VERSION 5.8 ;
BUSBITCHARS "[]" ;
DIVIDERCHAR "/" ;
UNITS
    DATABASE MICRONS 1000 ;
END UNITS

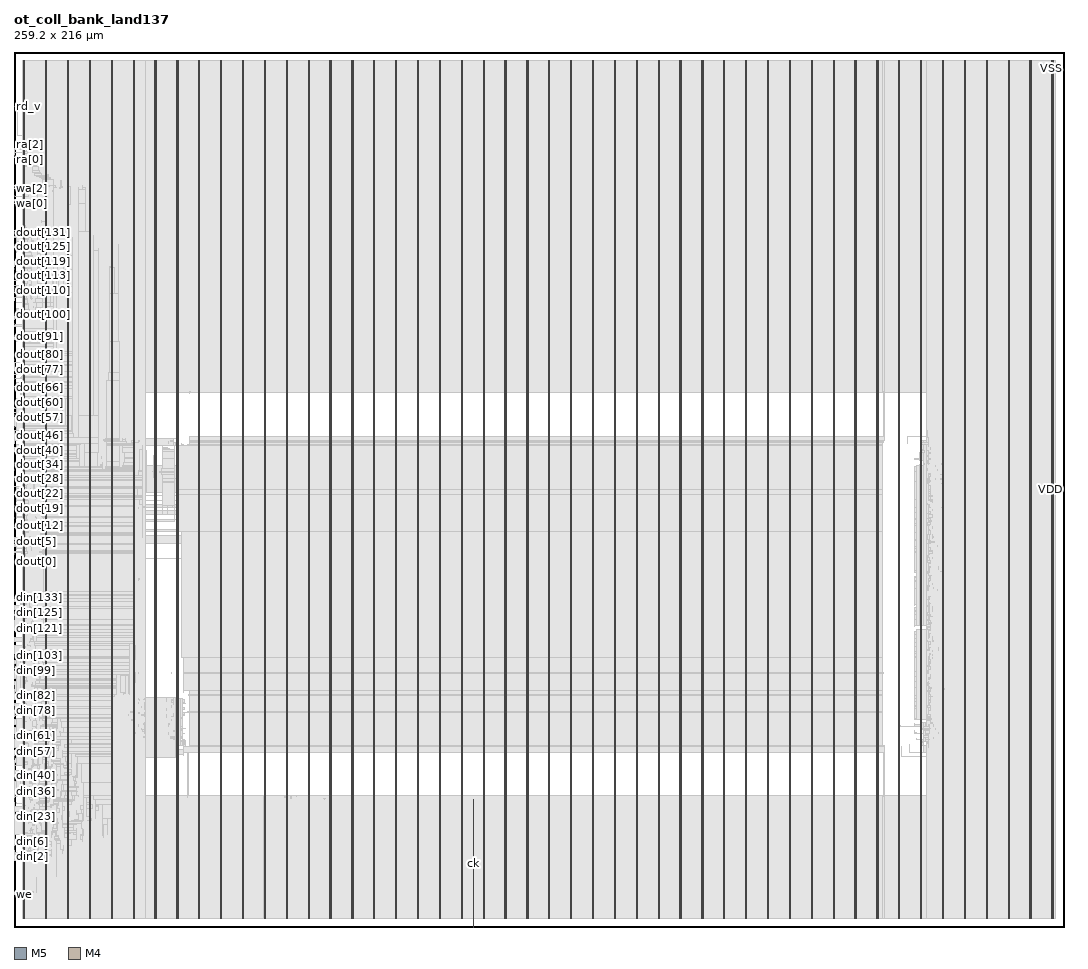
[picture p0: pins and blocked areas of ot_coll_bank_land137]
MACRO ot_coll_bank_land137
  FOREIGN ot_coll_bank_land137 0 0 ;
  CLASS BLOCK ;
  SIZE 259.2 BY 216 ;
  PIN ck
    DIRECTION INPUT ;
    USE SIGNAL ;
    PORT
      LAYER M5 ;
        RECT  113.376 0 113.4 0.084 ;
    END
    PORT
      LAYER M5 ;
        RECT  113.376 0.016 113.4 31.475 ;
    END
  END ck
  PIN din[0]
    DIRECTION INPUT ;
    USE SIGNAL ;
    PORT
      LAYER M4 ;
        RECT  0 16.416 0.084 16.44 ;
    END
  END din[0]
  PIN din[100]
    DIRECTION INPUT ;
    USE SIGNAL ;
    PORT
      LAYER M4 ;
        RECT  0 63.744 0.084 63.768 ;
    END
  END din[100]
  PIN din[101]
    DIRECTION INPUT ;
    USE SIGNAL ;
    PORT
      LAYER M4 ;
        RECT  0 64.176 0.084 64.2 ;
    END
  END din[101]
  PIN din[102]
    DIRECTION INPUT ;
    USE SIGNAL ;
    PORT
      LAYER M4 ;
        RECT  0 64.656 0.084 64.68 ;
    END
  END din[102]
  PIN din[103]
    DIRECTION INPUT ;
    USE SIGNAL ;
    PORT
      LAYER M4 ;
        RECT  0 65.136 0.084 65.16 ;
    END
  END din[103]
  PIN din[104]
    DIRECTION INPUT ;
    USE SIGNAL ;
    PORT
      LAYER M4 ;
        RECT  0 65.616 0.084 65.64 ;
    END
  END din[104]
  PIN din[105]
    DIRECTION INPUT ;
    USE SIGNAL ;
    PORT
      LAYER M4 ;
        RECT  0 66.096 0.084 66.12 ;
    END
  END din[105]
  PIN din[106]
    DIRECTION INPUT ;
    USE SIGNAL ;
    PORT
      LAYER M4 ;
        RECT  0 66.576 0.084 66.6 ;
    END
  END din[106]
  PIN din[107]
    DIRECTION INPUT ;
    USE SIGNAL ;
    PORT
      LAYER M4 ;
        RECT  0 67.056 0.084 67.08 ;
    END
  END din[107]
  PIN din[108]
    DIRECTION INPUT ;
    USE SIGNAL ;
    PORT
      LAYER M4 ;
        RECT  0 67.488 0.084 67.512 ;
    END
  END din[108]
  PIN din[109]
    DIRECTION INPUT ;
    USE SIGNAL ;
    PORT
      LAYER M4 ;
        RECT  0 67.968 0.084 67.992 ;
    END
  END din[109]
  PIN din[10]
    DIRECTION INPUT ;
    USE SIGNAL ;
    PORT
      LAYER M4 ;
        RECT  0 21.168 0.084 21.192 ;
    END
  END din[10]
  PIN din[110]
    DIRECTION INPUT ;
    USE SIGNAL ;
    PORT
      LAYER M4 ;
        RECT  0 68.448 0.084 68.472 ;
    END
  END din[110]
  PIN din[111]
    DIRECTION INPUT ;
    USE SIGNAL ;
    PORT
      LAYER M4 ;
        RECT  0 68.928 0.084 68.952 ;
    END
  END din[111]
  PIN din[112]
    DIRECTION INPUT ;
    USE SIGNAL ;
    PORT
      LAYER M4 ;
        RECT  0 69.408 0.084 69.432 ;
    END
  END din[112]
  PIN din[113]
    DIRECTION INPUT ;
    USE SIGNAL ;
    PORT
      LAYER M4 ;
        RECT  0 69.888 0.084 69.912 ;
    END
  END din[113]
  PIN din[114]
    DIRECTION INPUT ;
    USE SIGNAL ;
    PORT
      LAYER M4 ;
        RECT  0 70.368 0.084 70.392 ;
    END
  END din[114]
  PIN din[115]
    DIRECTION INPUT ;
    USE SIGNAL ;
    PORT
      LAYER M4 ;
        RECT  0 70.8 0.084 70.824 ;
    END
  END din[115]
  PIN din[116]
    DIRECTION INPUT ;
    USE SIGNAL ;
    PORT
      LAYER M4 ;
        RECT  0 71.28 0.084 71.304 ;
    END
  END din[116]
  PIN din[117]
    DIRECTION INPUT ;
    USE SIGNAL ;
    PORT
      LAYER M4 ;
        RECT  0 71.76 0.084 71.784 ;
    END
  END din[117]
  PIN din[118]
    DIRECTION INPUT ;
    USE SIGNAL ;
    PORT
      LAYER M4 ;
        RECT  0 72.24 0.084 72.264 ;
    END
  END din[118]
  PIN din[119]
    DIRECTION INPUT ;
    USE SIGNAL ;
    PORT
      LAYER M4 ;
        RECT  0 72.72 0.084 72.744 ;
    END
  END din[119]
  PIN din[11]
    DIRECTION INPUT ;
    USE SIGNAL ;
    PORT
      LAYER M4 ;
        RECT  0 21.648 0.084 21.672 ;
    END
  END din[11]
  PIN din[120]
    DIRECTION INPUT ;
    USE SIGNAL ;
    PORT
      LAYER M4 ;
        RECT  0 73.2 0.084 73.224 ;
    END
  END din[120]
  PIN din[121]
    DIRECTION INPUT ;
    USE SIGNAL ;
    PORT
      LAYER M4 ;
        RECT  0 73.68 0.084 73.704 ;
    END
  END din[121]
  PIN din[122]
    DIRECTION INPUT ;
    USE SIGNAL ;
    PORT
      LAYER M4 ;
        RECT  0 74.112 0.084 74.136 ;
    END
  END din[122]
  PIN din[123]
    DIRECTION INPUT ;
    USE SIGNAL ;
    PORT
      LAYER M4 ;
        RECT  0 74.592 0.084 74.616 ;
    END
  END din[123]
  PIN din[124]
    DIRECTION INPUT ;
    USE SIGNAL ;
    PORT
      LAYER M4 ;
        RECT  0 75.072 0.084 75.096 ;
    END
  END din[124]
  PIN din[125]
    DIRECTION INPUT ;
    USE SIGNAL ;
    PORT
      LAYER M4 ;
        RECT  0 75.552 0.084 75.576 ;
    END
  END din[125]
  PIN din[126]
    DIRECTION INPUT ;
    USE SIGNAL ;
    PORT
      LAYER M4 ;
        RECT  0 76.032 0.084 76.056 ;
    END
  END din[126]
  PIN din[127]
    DIRECTION INPUT ;
    USE SIGNAL ;
    PORT
      LAYER M4 ;
        RECT  0 76.512 0.084 76.536 ;
    END
  END din[127]
  PIN din[128]
    DIRECTION INPUT ;
    USE SIGNAL ;
    PORT
      LAYER M4 ;
        RECT  0 76.992 0.084 77.016 ;
    END
  END din[128]
  PIN din[129]
    DIRECTION INPUT ;
    USE SIGNAL ;
    PORT
      LAYER M4 ;
        RECT  0 77.424 0.084 77.448 ;
    END
  END din[129]
  PIN din[12]
    DIRECTION INPUT ;
    USE SIGNAL ;
    PORT
      LAYER M4 ;
        RECT  0 22.08 0.084 22.104 ;
    END
  END din[12]
  PIN din[130]
    DIRECTION INPUT ;
    USE SIGNAL ;
    PORT
      LAYER M4 ;
        RECT  0 77.904 0.084 77.928 ;
    END
  END din[130]
  PIN din[131]
    DIRECTION INPUT ;
    USE SIGNAL ;
    PORT
      LAYER M4 ;
        RECT  0 78.384 0.084 78.408 ;
    END
  END din[131]
  PIN din[132]
    DIRECTION INPUT ;
    USE SIGNAL ;
    PORT
      LAYER M4 ;
        RECT  0 78.864 0.084 78.888 ;
    END
  END din[132]
  PIN din[133]
    DIRECTION INPUT ;
    USE SIGNAL ;
    PORT
      LAYER M4 ;
        RECT  0 79.344 0.084 79.368 ;
    END
  END din[133]
  PIN din[134]
    DIRECTION INPUT ;
    USE SIGNAL ;
    PORT
      LAYER M4 ;
        RECT  0 79.824 0.084 79.848 ;
    END
  END din[134]
  PIN din[135]
    DIRECTION INPUT ;
    USE SIGNAL ;
    PORT
      LAYER M4 ;
        RECT  0 80.256 0.084 80.28 ;
    END
  END din[135]
  PIN din[136]
    DIRECTION INPUT ;
    USE SIGNAL ;
    PORT
      LAYER M4 ;
        RECT  0 80.736 0.084 80.76 ;
    END
  END din[136]
  PIN din[13]
    DIRECTION INPUT ;
    USE SIGNAL ;
    PORT
      LAYER M4 ;
        RECT  0 22.56 0.084 22.584 ;
    END
  END din[13]
  PIN din[14]
    DIRECTION INPUT ;
    USE SIGNAL ;
    PORT
      LAYER M4 ;
        RECT  0 23.04 0.084 23.064 ;
    END
  END din[14]
  PIN din[15]
    DIRECTION INPUT ;
    USE SIGNAL ;
    PORT
      LAYER M4 ;
        RECT  0 23.52 0.084 23.544 ;
    END
  END din[15]
  PIN din[16]
    DIRECTION INPUT ;
    USE SIGNAL ;
    PORT
      LAYER M4 ;
        RECT  0 24 0.084 24.024 ;
    END
  END din[16]
  PIN din[17]
    DIRECTION INPUT ;
    USE SIGNAL ;
    PORT
      LAYER M4 ;
        RECT  0 24.48 0.084 24.504 ;
    END
  END din[17]
  PIN din[18]
    DIRECTION INPUT ;
    USE SIGNAL ;
    PORT
      LAYER M4 ;
        RECT  0 24.96 0.084 24.984 ;
    END
  END din[18]
  PIN din[19]
    DIRECTION INPUT ;
    USE SIGNAL ;
    PORT
      LAYER M4 ;
        RECT  0 25.392 0.084 25.416 ;
    END
  END din[19]
  PIN din[1]
    DIRECTION INPUT ;
    USE SIGNAL ;
    PORT
      LAYER M4 ;
        RECT  0 16.896 0.084 16.92 ;
    END
  END din[1]
  PIN din[20]
    DIRECTION INPUT ;
    USE SIGNAL ;
    PORT
      LAYER M4 ;
        RECT  0 25.872 0.084 25.896 ;
    END
  END din[20]
  PIN din[21]
    DIRECTION INPUT ;
    USE SIGNAL ;
    PORT
      LAYER M4 ;
        RECT  0 26.352 0.084 26.376 ;
    END
  END din[21]
  PIN din[22]
    DIRECTION INPUT ;
    USE SIGNAL ;
    PORT
      LAYER M4 ;
        RECT  0 26.832 0.084 26.856 ;
    END
  END din[22]
  PIN din[23]
    DIRECTION INPUT ;
    USE SIGNAL ;
    PORT
      LAYER M4 ;
        RECT  0 27.312 0.084 27.336 ;
    END
  END din[23]
  PIN din[24]
    DIRECTION INPUT ;
    USE SIGNAL ;
    PORT
      LAYER M4 ;
        RECT  0 27.792 0.084 27.816 ;
    END
  END din[24]
  PIN din[25]
    DIRECTION INPUT ;
    USE SIGNAL ;
    PORT
      LAYER M4 ;
        RECT  0 28.272 0.084 28.296 ;
    END
  END din[25]
  PIN din[26]
    DIRECTION INPUT ;
    USE SIGNAL ;
    PORT
      LAYER M4 ;
        RECT  0 28.704 0.084 28.728 ;
    END
  END din[26]
  PIN din[27]
    DIRECTION INPUT ;
    USE SIGNAL ;
    PORT
      LAYER M4 ;
        RECT  0 29.184 0.084 29.208 ;
    END
  END din[27]
  PIN din[28]
    DIRECTION INPUT ;
    USE SIGNAL ;
    PORT
      LAYER M4 ;
        RECT  0 29.664 0.084 29.688 ;
    END
  END din[28]
  PIN din[29]
    DIRECTION INPUT ;
    USE SIGNAL ;
    PORT
      LAYER M4 ;
        RECT  0 30.144 0.084 30.168 ;
    END
  END din[29]
  PIN din[2]
    DIRECTION INPUT ;
    USE SIGNAL ;
    PORT
      LAYER M4 ;
        RECT  0 17.376 0.084 17.4 ;
    END
  END din[2]
  PIN din[30]
    DIRECTION INPUT ;
    USE SIGNAL ;
    PORT
      LAYER M4 ;
        RECT  0 30.624 0.084 30.648 ;
    END
  END din[30]
  PIN din[31]
    DIRECTION INPUT ;
    USE SIGNAL ;
    PORT
      LAYER M4 ;
        RECT  0 31.104 0.084 31.128 ;
    END
  END din[31]
  PIN din[32]
    DIRECTION INPUT ;
    USE SIGNAL ;
    PORT
      LAYER M4 ;
        RECT  0 31.584 0.084 31.608 ;
    END
  END din[32]
  PIN din[33]
    DIRECTION INPUT ;
    USE SIGNAL ;
    PORT
      LAYER M4 ;
        RECT  0 32.016 0.084 32.04 ;
    END
  END din[33]
  PIN din[34]
    DIRECTION INPUT ;
    USE SIGNAL ;
    PORT
      LAYER M4 ;
        RECT  0 32.496 0.084 32.52 ;
    END
  END din[34]
  PIN din[35]
    DIRECTION INPUT ;
    USE SIGNAL ;
    PORT
      LAYER M4 ;
        RECT  0 32.976 0.084 33 ;
    END
  END din[35]
  PIN din[36]
    DIRECTION INPUT ;
    USE SIGNAL ;
    PORT
      LAYER M4 ;
        RECT  0 33.456 0.084 33.48 ;
    END
  END din[36]
  PIN din[37]
    DIRECTION INPUT ;
    USE SIGNAL ;
    PORT
      LAYER M4 ;
        RECT  0 33.936 0.084 33.96 ;
    END
  END din[37]
  PIN din[38]
    DIRECTION INPUT ;
    USE SIGNAL ;
    PORT
      LAYER M4 ;
        RECT  0 34.416 0.084 34.44 ;
    END
  END din[38]
  PIN din[39]
    DIRECTION INPUT ;
    USE SIGNAL ;
    PORT
      LAYER M4 ;
        RECT  0 34.848 0.084 34.872 ;
    END
  END din[39]
  PIN din[3]
    DIRECTION INPUT ;
    USE SIGNAL ;
    PORT
      LAYER M4 ;
        RECT  0 17.856 0.084 17.88 ;
    END
  END din[3]
  PIN din[40]
    DIRECTION INPUT ;
    USE SIGNAL ;
    PORT
      LAYER M4 ;
        RECT  0 35.328 0.084 35.352 ;
    END
  END din[40]
  PIN din[41]
    DIRECTION INPUT ;
    USE SIGNAL ;
    PORT
      LAYER M4 ;
        RECT  0 35.808 0.084 35.832 ;
    END
  END din[41]
  PIN din[42]
    DIRECTION INPUT ;
    USE SIGNAL ;
    PORT
      LAYER M4 ;
        RECT  0 36.288 0.084 36.312 ;
    END
  END din[42]
  PIN din[43]
    DIRECTION INPUT ;
    USE SIGNAL ;
    PORT
      LAYER M4 ;
        RECT  0 36.768 0.084 36.792 ;
    END
  END din[43]
  PIN din[44]
    DIRECTION INPUT ;
    USE SIGNAL ;
    PORT
      LAYER M4 ;
        RECT  0 37.248 0.084 37.272 ;
    END
  END din[44]
  PIN din[45]
    DIRECTION INPUT ;
    USE SIGNAL ;
    PORT
      LAYER M4 ;
        RECT  0 37.728 0.084 37.752 ;
    END
  END din[45]
  PIN din[46]
    DIRECTION INPUT ;
    USE SIGNAL ;
    PORT
      LAYER M4 ;
        RECT  0 38.16 0.084 38.184 ;
    END
  END din[46]
  PIN din[47]
    DIRECTION INPUT ;
    USE SIGNAL ;
    PORT
      LAYER M4 ;
        RECT  0 38.64 0.084 38.664 ;
    END
  END din[47]
  PIN din[48]
    DIRECTION INPUT ;
    USE SIGNAL ;
    PORT
      LAYER M4 ;
        RECT  0 39.12 0.084 39.144 ;
    END
  END din[48]
  PIN din[49]
    DIRECTION INPUT ;
    USE SIGNAL ;
    PORT
      LAYER M4 ;
        RECT  0 39.6 0.084 39.624 ;
    END
  END din[49]
  PIN din[4]
    DIRECTION INPUT ;
    USE SIGNAL ;
    PORT
      LAYER M4 ;
        RECT  0 18.336 0.084 18.36 ;
    END
  END din[4]
  PIN din[50]
    DIRECTION INPUT ;
    USE SIGNAL ;
    PORT
      LAYER M4 ;
        RECT  0 40.08 0.084 40.104 ;
    END
  END din[50]
  PIN din[51]
    DIRECTION INPUT ;
    USE SIGNAL ;
    PORT
      LAYER M4 ;
        RECT  0 40.56 0.084 40.584 ;
    END
  END din[51]
  PIN din[52]
    DIRECTION INPUT ;
    USE SIGNAL ;
    PORT
      LAYER M4 ;
        RECT  0 41.04 0.084 41.064 ;
    END
  END din[52]
  PIN din[53]
    DIRECTION INPUT ;
    USE SIGNAL ;
    PORT
      LAYER M4 ;
        RECT  0 41.472 0.084 41.496 ;
    END
  END din[53]
  PIN din[54]
    DIRECTION INPUT ;
    USE SIGNAL ;
    PORT
      LAYER M4 ;
        RECT  0 41.952 0.084 41.976 ;
    END
  END din[54]
  PIN din[55]
    DIRECTION INPUT ;
    USE SIGNAL ;
    PORT
      LAYER M4 ;
        RECT  0 42.432 0.084 42.456 ;
    END
  END din[55]
  PIN din[56]
    DIRECTION INPUT ;
    USE SIGNAL ;
    PORT
      LAYER M4 ;
        RECT  0 42.912 0.084 42.936 ;
    END
  END din[56]
  PIN din[57]
    DIRECTION INPUT ;
    USE SIGNAL ;
    PORT
      LAYER M4 ;
        RECT  0 43.392 0.084 43.416 ;
    END
  END din[57]
  PIN din[58]
    DIRECTION INPUT ;
    USE SIGNAL ;
    PORT
      LAYER M4 ;
        RECT  0 43.872 0.084 43.896 ;
    END
  END din[58]
  PIN din[59]
    DIRECTION INPUT ;
    USE SIGNAL ;
    PORT
      LAYER M4 ;
        RECT  0 44.352 0.084 44.376 ;
    END
  END din[59]
  PIN din[5]
    DIRECTION INPUT ;
    USE SIGNAL ;
    PORT
      LAYER M4 ;
        RECT  0 18.768 0.084 18.792 ;
    END
  END din[5]
  PIN din[60]
    DIRECTION INPUT ;
    USE SIGNAL ;
    PORT
      LAYER M4 ;
        RECT  0 44.784 0.084 44.808 ;
    END
  END din[60]
  PIN din[61]
    DIRECTION INPUT ;
    USE SIGNAL ;
    PORT
      LAYER M4 ;
        RECT  0 45.264 0.084 45.288 ;
    END
  END din[61]
  PIN din[62]
    DIRECTION INPUT ;
    USE SIGNAL ;
    PORT
      LAYER M4 ;
        RECT  0 45.744 0.084 45.768 ;
    END
  END din[62]
  PIN din[63]
    DIRECTION INPUT ;
    USE SIGNAL ;
    PORT
      LAYER M4 ;
        RECT  0 46.224 0.084 46.248 ;
    END
  END din[63]
  PIN din[64]
    DIRECTION INPUT ;
    USE SIGNAL ;
    PORT
      LAYER M4 ;
        RECT  0 46.704 0.084 46.728 ;
    END
  END din[64]
  PIN din[65]
    DIRECTION INPUT ;
    USE SIGNAL ;
    PORT
      LAYER M4 ;
        RECT  0 47.184 0.084 47.208 ;
    END
  END din[65]
  PIN din[66]
    DIRECTION INPUT ;
    USE SIGNAL ;
    PORT
      LAYER M4 ;
        RECT  0 47.664 0.084 47.688 ;
    END
  END din[66]
  PIN din[67]
    DIRECTION INPUT ;
    USE SIGNAL ;
    PORT
      LAYER M4 ;
        RECT  0 48.096 0.084 48.12 ;
    END
  END din[67]
  PIN din[68]
    DIRECTION INPUT ;
    USE SIGNAL ;
    PORT
      LAYER M4 ;
        RECT  0 48.576 0.084 48.6 ;
    END
  END din[68]
  PIN din[69]
    DIRECTION INPUT ;
    USE SIGNAL ;
    PORT
      LAYER M4 ;
        RECT  0 49.056 0.084 49.08 ;
    END
  END din[69]
  PIN din[6]
    DIRECTION INPUT ;
    USE SIGNAL ;
    PORT
      LAYER M4 ;
        RECT  0 19.248 0.084 19.272 ;
    END
  END din[6]
  PIN din[70]
    DIRECTION INPUT ;
    USE SIGNAL ;
    PORT
      LAYER M4 ;
        RECT  0 49.536 0.084 49.56 ;
    END
  END din[70]
  PIN din[71]
    DIRECTION INPUT ;
    USE SIGNAL ;
    PORT
      LAYER M4 ;
        RECT  0 50.016 0.084 50.04 ;
    END
  END din[71]
  PIN din[72]
    DIRECTION INPUT ;
    USE SIGNAL ;
    PORT
      LAYER M4 ;
        RECT  0 50.496 0.084 50.52 ;
    END
  END din[72]
  PIN din[73]
    DIRECTION INPUT ;
    USE SIGNAL ;
    PORT
      LAYER M4 ;
        RECT  0 50.976 0.084 51 ;
    END
  END din[73]
  PIN din[74]
    DIRECTION INPUT ;
    USE SIGNAL ;
    PORT
      LAYER M4 ;
        RECT  0 51.408 0.084 51.432 ;
    END
  END din[74]
  PIN din[75]
    DIRECTION INPUT ;
    USE SIGNAL ;
    PORT
      LAYER M4 ;
        RECT  0 51.888 0.084 51.912 ;
    END
  END din[75]
  PIN din[76]
    DIRECTION INPUT ;
    USE SIGNAL ;
    PORT
      LAYER M4 ;
        RECT  0 52.368 0.084 52.392 ;
    END
  END din[76]
  PIN din[77]
    DIRECTION INPUT ;
    USE SIGNAL ;
    PORT
      LAYER M4 ;
        RECT  0 52.848 0.084 52.872 ;
    END
  END din[77]
  PIN din[78]
    DIRECTION INPUT ;
    USE SIGNAL ;
    PORT
      LAYER M4 ;
        RECT  0 53.328 0.084 53.352 ;
    END
  END din[78]
  PIN din[79]
    DIRECTION INPUT ;
    USE SIGNAL ;
    PORT
      LAYER M4 ;
        RECT  0 53.808 0.084 53.832 ;
    END
  END din[79]
  PIN din[7]
    DIRECTION INPUT ;
    USE SIGNAL ;
    PORT
      LAYER M4 ;
        RECT  0 19.728 0.084 19.752 ;
    END
  END din[7]
  PIN din[80]
    DIRECTION INPUT ;
    USE SIGNAL ;
    PORT
      LAYER M4 ;
        RECT  0 54.288 0.084 54.312 ;
    END
  END din[80]
  PIN din[81]
    DIRECTION INPUT ;
    USE SIGNAL ;
    PORT
      LAYER M4 ;
        RECT  0 54.72 0.084 54.744 ;
    END
  END din[81]
  PIN din[82]
    DIRECTION INPUT ;
    USE SIGNAL ;
    PORT
      LAYER M4 ;
        RECT  0 55.2 0.084 55.224 ;
    END
  END din[82]
  PIN din[83]
    DIRECTION INPUT ;
    USE SIGNAL ;
    PORT
      LAYER M4 ;
        RECT  0 55.68 0.084 55.704 ;
    END
  END din[83]
  PIN din[84]
    DIRECTION INPUT ;
    USE SIGNAL ;
    PORT
      LAYER M4 ;
        RECT  0 56.16 0.084 56.184 ;
    END
  END din[84]
  PIN din[85]
    DIRECTION INPUT ;
    USE SIGNAL ;
    PORT
      LAYER M4 ;
        RECT  0 56.64 0.084 56.664 ;
    END
  END din[85]
  PIN din[86]
    DIRECTION INPUT ;
    USE SIGNAL ;
    PORT
      LAYER M4 ;
        RECT  0 57.12 0.084 57.144 ;
    END
  END din[86]
  PIN din[87]
    DIRECTION INPUT ;
    USE SIGNAL ;
    PORT
      LAYER M4 ;
        RECT  0 57.552 0.084 57.576 ;
    END
  END din[87]
  PIN din[88]
    DIRECTION INPUT ;
    USE SIGNAL ;
    PORT
      LAYER M4 ;
        RECT  0 58.032 0.084 58.056 ;
    END
  END din[88]
  PIN din[89]
    DIRECTION INPUT ;
    USE SIGNAL ;
    PORT
      LAYER M4 ;
        RECT  0 58.512 0.084 58.536 ;
    END
  END din[89]
  PIN din[8]
    DIRECTION INPUT ;
    USE SIGNAL ;
    PORT
      LAYER M4 ;
        RECT  0 20.208 0.084 20.232 ;
    END
  END din[8]
  PIN din[90]
    DIRECTION INPUT ;
    USE SIGNAL ;
    PORT
      LAYER M4 ;
        RECT  0 58.992 0.084 59.016 ;
    END
  END din[90]
  PIN din[91]
    DIRECTION INPUT ;
    USE SIGNAL ;
    PORT
      LAYER M4 ;
        RECT  0 59.472 0.084 59.496 ;
    END
  END din[91]
  PIN din[92]
    DIRECTION INPUT ;
    USE SIGNAL ;
    PORT
      LAYER M4 ;
        RECT  0 59.952 0.084 59.976 ;
    END
  END din[92]
  PIN din[93]
    DIRECTION INPUT ;
    USE SIGNAL ;
    PORT
      LAYER M4 ;
        RECT  0 60.432 0.084 60.456 ;
    END
  END din[93]
  PIN din[94]
    DIRECTION INPUT ;
    USE SIGNAL ;
    PORT
      LAYER M4 ;
        RECT  0 60.864 0.084 60.888 ;
    END
  END din[94]
  PIN din[95]
    DIRECTION INPUT ;
    USE SIGNAL ;
    PORT
      LAYER M4 ;
        RECT  0 61.344 0.084 61.368 ;
    END
  END din[95]
  PIN din[96]
    DIRECTION INPUT ;
    USE SIGNAL ;
    PORT
      LAYER M4 ;
        RECT  0 61.824 0.084 61.848 ;
    END
  END din[96]
  PIN din[97]
    DIRECTION INPUT ;
    USE SIGNAL ;
    PORT
      LAYER M4 ;
        RECT  0 62.304 0.084 62.328 ;
    END
  END din[97]
  PIN din[98]
    DIRECTION INPUT ;
    USE SIGNAL ;
    PORT
      LAYER M4 ;
        RECT  0 62.784 0.084 62.808 ;
    END
  END din[98]
  PIN din[99]
    DIRECTION INPUT ;
    USE SIGNAL ;
    PORT
      LAYER M4 ;
        RECT  0 63.264 0.084 63.288 ;
    END
  END din[99]
  PIN din[9]
    DIRECTION INPUT ;
    USE SIGNAL ;
    PORT
      LAYER M4 ;
        RECT  0 20.688 0.084 20.712 ;
    END
  END din[9]
  PIN dout[0]
    DIRECTION OUTPUT ;
    USE SIGNAL ;
    PORT
      LAYER M4 ;
        RECT  0 92.064 0.084 92.088 ;
    END
  END dout[0]
  PIN dout[100]
    DIRECTION OUTPUT ;
    USE SIGNAL ;
    PORT
      LAYER M4 ;
        RECT  0 151.2 0.084 151.224 ;
    END
  END dout[100]
  PIN dout[101]
    DIRECTION OUTPUT ;
    USE SIGNAL ;
    PORT
      LAYER M4 ;
        RECT  0 151.776 0.084 151.8 ;
    END
  END dout[101]
  PIN dout[102]
    DIRECTION OUTPUT ;
    USE SIGNAL ;
    PORT
      LAYER M4 ;
        RECT  0 152.4 0.084 152.424 ;
    END
  END dout[102]
  PIN dout[103]
    DIRECTION OUTPUT ;
    USE SIGNAL ;
    PORT
      LAYER M4 ;
        RECT  0 152.976 0.084 153 ;
    END
  END dout[103]
  PIN dout[104]
    DIRECTION OUTPUT ;
    USE SIGNAL ;
    PORT
      LAYER M4 ;
        RECT  0 153.552 0.084 153.576 ;
    END
  END dout[104]
  PIN dout[105]
    DIRECTION OUTPUT ;
    USE SIGNAL ;
    PORT
      LAYER M4 ;
        RECT  0 154.176 0.084 154.2 ;
    END
  END dout[105]
  PIN dout[106]
    DIRECTION OUTPUT ;
    USE SIGNAL ;
    PORT
      LAYER M4 ;
        RECT  0 154.752 0.084 154.776 ;
    END
  END dout[106]
  PIN dout[107]
    DIRECTION OUTPUT ;
    USE SIGNAL ;
    PORT
      LAYER M4 ;
        RECT  0 155.328 0.084 155.352 ;
    END
  END dout[107]
  PIN dout[108]
    DIRECTION OUTPUT ;
    USE SIGNAL ;
    PORT
      LAYER M4 ;
        RECT  0 155.952 0.084 155.976 ;
    END
  END dout[108]
  PIN dout[109]
    DIRECTION OUTPUT ;
    USE SIGNAL ;
    PORT
      LAYER M4 ;
        RECT  0 156.528 0.084 156.552 ;
    END
  END dout[109]
  PIN dout[10]
    DIRECTION OUTPUT ;
    USE SIGNAL ;
    PORT
      LAYER M4 ;
        RECT  0 98.016 0.084 98.04 ;
    END
  END dout[10]
  PIN dout[110]
    DIRECTION OUTPUT ;
    USE SIGNAL ;
    PORT
      LAYER M4 ;
        RECT  0 157.104 0.084 157.128 ;
    END
  END dout[110]
  PIN dout[111]
    DIRECTION OUTPUT ;
    USE SIGNAL ;
    PORT
      LAYER M4 ;
        RECT  0 157.728 0.084 157.752 ;
    END
  END dout[111]
  PIN dout[112]
    DIRECTION OUTPUT ;
    USE SIGNAL ;
    PORT
      LAYER M4 ;
        RECT  0 158.304 0.084 158.328 ;
    END
  END dout[112]
  PIN dout[113]
    DIRECTION OUTPUT ;
    USE SIGNAL ;
    PORT
      LAYER M4 ;
        RECT  0 158.88 0.084 158.904 ;
    END
  END dout[113]
  PIN dout[114]
    DIRECTION OUTPUT ;
    USE SIGNAL ;
    PORT
      LAYER M4 ;
        RECT  0 159.504 0.084 159.528 ;
    END
  END dout[114]
  PIN dout[115]
    DIRECTION OUTPUT ;
    USE SIGNAL ;
    PORT
      LAYER M4 ;
        RECT  0 160.08 0.084 160.104 ;
    END
  END dout[115]
  PIN dout[116]
    DIRECTION OUTPUT ;
    USE SIGNAL ;
    PORT
      LAYER M4 ;
        RECT  0 160.656 0.084 160.68 ;
    END
  END dout[116]
  PIN dout[117]
    DIRECTION OUTPUT ;
    USE SIGNAL ;
    PORT
      LAYER M4 ;
        RECT  0 161.28 0.084 161.304 ;
    END
  END dout[117]
  PIN dout[118]
    DIRECTION OUTPUT ;
    USE SIGNAL ;
    PORT
      LAYER M4 ;
        RECT  0 161.856 0.084 161.88 ;
    END
  END dout[118]
  PIN dout[119]
    DIRECTION OUTPUT ;
    USE SIGNAL ;
    PORT
      LAYER M4 ;
        RECT  0 162.432 0.084 162.456 ;
    END
  END dout[119]
  PIN dout[11]
    DIRECTION OUTPUT ;
    USE SIGNAL ;
    PORT
      LAYER M4 ;
        RECT  0 98.592 0.084 98.616 ;
    END
  END dout[11]
  PIN dout[120]
    DIRECTION OUTPUT ;
    USE SIGNAL ;
    PORT
      LAYER M4 ;
        RECT  0 163.056 0.084 163.08 ;
    END
  END dout[120]
  PIN dout[121]
    DIRECTION OUTPUT ;
    USE SIGNAL ;
    PORT
      LAYER M4 ;
        RECT  0 163.632 0.084 163.656 ;
    END
  END dout[121]
  PIN dout[122]
    DIRECTION OUTPUT ;
    USE SIGNAL ;
    PORT
      LAYER M4 ;
        RECT  0 164.208 0.084 164.232 ;
    END
  END dout[122]
  PIN dout[123]
    DIRECTION OUTPUT ;
    USE SIGNAL ;
    PORT
      LAYER M4 ;
        RECT  0 164.784 0.084 164.808 ;
    END
  END dout[123]
  PIN dout[124]
    DIRECTION OUTPUT ;
    USE SIGNAL ;
    PORT
      LAYER M4 ;
        RECT  0 165.408 0.084 165.432 ;
    END
  END dout[124]
  PIN dout[125]
    DIRECTION OUTPUT ;
    USE SIGNAL ;
    PORT
      LAYER M4 ;
        RECT  0 165.984 0.084 166.008 ;
    END
  END dout[125]
  PIN dout[126]
    DIRECTION OUTPUT ;
    USE SIGNAL ;
    PORT
      LAYER M4 ;
        RECT  0 166.56 0.084 166.584 ;
    END
  END dout[126]
  PIN dout[127]
    DIRECTION OUTPUT ;
    USE SIGNAL ;
    PORT
      LAYER M4 ;
        RECT  0 167.184 0.084 167.208 ;
    END
  END dout[127]
  PIN dout[128]
    DIRECTION OUTPUT ;
    USE SIGNAL ;
    PORT
      LAYER M4 ;
        RECT  0 167.76 0.084 167.784 ;
    END
  END dout[128]
  PIN dout[129]
    DIRECTION OUTPUT ;
    USE SIGNAL ;
    PORT
      LAYER M4 ;
        RECT  0 168.336 0.084 168.36 ;
    END
  END dout[129]
  PIN dout[12]
    DIRECTION OUTPUT ;
    USE SIGNAL ;
    PORT
      LAYER M4 ;
        RECT  0 99.168 0.084 99.192 ;
    END
  END dout[12]
  PIN dout[130]
    DIRECTION OUTPUT ;
    USE SIGNAL ;
    PORT
      LAYER M4 ;
        RECT  0 168.96 0.084 168.984 ;
    END
  END dout[130]
  PIN dout[131]
    DIRECTION OUTPUT ;
    USE SIGNAL ;
    PORT
      LAYER M4 ;
        RECT  0 169.536 0.084 169.56 ;
    END
  END dout[131]
  PIN dout[132]
    DIRECTION OUTPUT ;
    USE SIGNAL ;
    PORT
      LAYER M4 ;
        RECT  0 170.112 0.084 170.136 ;
    END
  END dout[132]
  PIN dout[133]
    DIRECTION OUTPUT ;
    USE SIGNAL ;
    PORT
      LAYER M4 ;
        RECT  0 170.736 0.084 170.76 ;
    END
  END dout[133]
  PIN dout[134]
    DIRECTION OUTPUT ;
    USE SIGNAL ;
    PORT
      LAYER M4 ;
        RECT  0 171.312 0.084 171.336 ;
    END
  END dout[134]
  PIN dout[135]
    DIRECTION OUTPUT ;
    USE SIGNAL ;
    PORT
      LAYER M4 ;
        RECT  0 171.888 0.084 171.912 ;
    END
  END dout[135]
  PIN dout[136]
    DIRECTION OUTPUT ;
    USE SIGNAL ;
    PORT
      LAYER M4 ;
        RECT  0 172.512 0.084 172.536 ;
    END
  END dout[136]
  PIN dout[13]
    DIRECTION OUTPUT ;
    USE SIGNAL ;
    PORT
      LAYER M4 ;
        RECT  0 99.792 0.084 99.816 ;
    END
  END dout[13]
  PIN dout[14]
    DIRECTION OUTPUT ;
    USE SIGNAL ;
    PORT
      LAYER M4 ;
        RECT  0 100.368 0.084 100.392 ;
    END
  END dout[14]
  PIN dout[15]
    DIRECTION OUTPUT ;
    USE SIGNAL ;
    PORT
      LAYER M4 ;
        RECT  0 100.944 0.084 100.968 ;
    END
  END dout[15]
  PIN dout[16]
    DIRECTION OUTPUT ;
    USE SIGNAL ;
    PORT
      LAYER M4 ;
        RECT  0 101.52 0.084 101.544 ;
    END
  END dout[16]
  PIN dout[17]
    DIRECTION OUTPUT ;
    USE SIGNAL ;
    PORT
      LAYER M4 ;
        RECT  0 102.144 0.084 102.168 ;
    END
  END dout[17]
  PIN dout[18]
    DIRECTION OUTPUT ;
    USE SIGNAL ;
    PORT
      LAYER M4 ;
        RECT  0 102.72 0.084 102.744 ;
    END
  END dout[18]
  PIN dout[19]
    DIRECTION OUTPUT ;
    USE SIGNAL ;
    PORT
      LAYER M4 ;
        RECT  0 103.296 0.084 103.32 ;
    END
  END dout[19]
  PIN dout[1]
    DIRECTION OUTPUT ;
    USE SIGNAL ;
    PORT
      LAYER M4 ;
        RECT  0 92.688 0.084 92.712 ;
    END
  END dout[1]
  PIN dout[20]
    DIRECTION OUTPUT ;
    USE SIGNAL ;
    PORT
      LAYER M4 ;
        RECT  0 103.92 0.084 103.944 ;
    END
  END dout[20]
  PIN dout[21]
    DIRECTION OUTPUT ;
    USE SIGNAL ;
    PORT
      LAYER M4 ;
        RECT  0 104.496 0.084 104.52 ;
    END
  END dout[21]
  PIN dout[22]
    DIRECTION OUTPUT ;
    USE SIGNAL ;
    PORT
      LAYER M4 ;
        RECT  0 105.072 0.084 105.096 ;
    END
  END dout[22]
  PIN dout[23]
    DIRECTION OUTPUT ;
    USE SIGNAL ;
    PORT
      LAYER M4 ;
        RECT  0 105.696 0.084 105.72 ;
    END
  END dout[23]
  PIN dout[24]
    DIRECTION OUTPUT ;
    USE SIGNAL ;
    PORT
      LAYER M4 ;
        RECT  0 106.272 0.084 106.296 ;
    END
  END dout[24]
  PIN dout[25]
    DIRECTION OUTPUT ;
    USE SIGNAL ;
    PORT
      LAYER M4 ;
        RECT  0 106.848 0.084 106.872 ;
    END
  END dout[25]
  PIN dout[26]
    DIRECTION OUTPUT ;
    USE SIGNAL ;
    PORT
      LAYER M4 ;
        RECT  0 107.472 0.084 107.496 ;
    END
  END dout[26]
  PIN dout[27]
    DIRECTION OUTPUT ;
    USE SIGNAL ;
    PORT
      LAYER M4 ;
        RECT  0 108.048 0.084 108.072 ;
    END
  END dout[27]
  PIN dout[28]
    DIRECTION OUTPUT ;
    USE SIGNAL ;
    PORT
      LAYER M4 ;
        RECT  0 108.624 0.084 108.648 ;
    END
  END dout[28]
  PIN dout[29]
    DIRECTION OUTPUT ;
    USE SIGNAL ;
    PORT
      LAYER M4 ;
        RECT  0 109.248 0.084 109.272 ;
    END
  END dout[29]
  PIN dout[2]
    DIRECTION OUTPUT ;
    USE SIGNAL ;
    PORT
      LAYER M4 ;
        RECT  0 93.264 0.084 93.288 ;
    END
  END dout[2]
  PIN dout[30]
    DIRECTION OUTPUT ;
    USE SIGNAL ;
    PORT
      LAYER M4 ;
        RECT  0 109.824 0.084 109.848 ;
    END
  END dout[30]
  PIN dout[31]
    DIRECTION OUTPUT ;
    USE SIGNAL ;
    PORT
      LAYER M4 ;
        RECT  0 110.4 0.084 110.424 ;
    END
  END dout[31]
  PIN dout[32]
    DIRECTION OUTPUT ;
    USE SIGNAL ;
    PORT
      LAYER M4 ;
        RECT  0 111.024 0.084 111.048 ;
    END
  END dout[32]
  PIN dout[33]
    DIRECTION OUTPUT ;
    USE SIGNAL ;
    PORT
      LAYER M4 ;
        RECT  0 111.6 0.084 111.624 ;
    END
  END dout[33]
  PIN dout[34]
    DIRECTION OUTPUT ;
    USE SIGNAL ;
    PORT
      LAYER M4 ;
        RECT  0 112.176 0.084 112.2 ;
    END
  END dout[34]
  PIN dout[35]
    DIRECTION OUTPUT ;
    USE SIGNAL ;
    PORT
      LAYER M4 ;
        RECT  0 112.8 0.084 112.824 ;
    END
  END dout[35]
  PIN dout[36]
    DIRECTION OUTPUT ;
    USE SIGNAL ;
    PORT
      LAYER M4 ;
        RECT  0 113.376 0.084 113.4 ;
    END
  END dout[36]
  PIN dout[37]
    DIRECTION OUTPUT ;
    USE SIGNAL ;
    PORT
      LAYER M4 ;
        RECT  0 113.952 0.084 113.976 ;
    END
  END dout[37]
  PIN dout[38]
    DIRECTION OUTPUT ;
    USE SIGNAL ;
    PORT
      LAYER M4 ;
        RECT  0 114.528 0.084 114.552 ;
    END
  END dout[38]
  PIN dout[39]
    DIRECTION OUTPUT ;
    USE SIGNAL ;
    PORT
      LAYER M4 ;
        RECT  0 115.152 0.084 115.176 ;
    END
  END dout[39]
  PIN dout[3]
    DIRECTION OUTPUT ;
    USE SIGNAL ;
    PORT
      LAYER M4 ;
        RECT  0 93.84 0.084 93.864 ;
    END
  END dout[3]
  PIN dout[40]
    DIRECTION OUTPUT ;
    USE SIGNAL ;
    PORT
      LAYER M4 ;
        RECT  0 115.728 0.084 115.752 ;
    END
  END dout[40]
  PIN dout[41]
    DIRECTION OUTPUT ;
    USE SIGNAL ;
    PORT
      LAYER M4 ;
        RECT  0 116.304 0.084 116.328 ;
    END
  END dout[41]
  PIN dout[42]
    DIRECTION OUTPUT ;
    USE SIGNAL ;
    PORT
      LAYER M4 ;
        RECT  0 116.928 0.084 116.952 ;
    END
  END dout[42]
  PIN dout[43]
    DIRECTION OUTPUT ;
    USE SIGNAL ;
    PORT
      LAYER M4 ;
        RECT  0 117.504 0.084 117.528 ;
    END
  END dout[43]
  PIN dout[44]
    DIRECTION OUTPUT ;
    USE SIGNAL ;
    PORT
      LAYER M4 ;
        RECT  0 118.08 0.084 118.104 ;
    END
  END dout[44]
  PIN dout[45]
    DIRECTION OUTPUT ;
    USE SIGNAL ;
    PORT
      LAYER M4 ;
        RECT  0 118.704 0.084 118.728 ;
    END
  END dout[45]
  PIN dout[46]
    DIRECTION OUTPUT ;
    USE SIGNAL ;
    PORT
      LAYER M4 ;
        RECT  0 119.28 0.084 119.304 ;
    END
  END dout[46]
  PIN dout[47]
    DIRECTION OUTPUT ;
    USE SIGNAL ;
    PORT
      LAYER M4 ;
        RECT  0 119.856 0.084 119.88 ;
    END
  END dout[47]
  PIN dout[48]
    DIRECTION OUTPUT ;
    USE SIGNAL ;
    PORT
      LAYER M4 ;
        RECT  0 120.48 0.084 120.504 ;
    END
  END dout[48]
  PIN dout[49]
    DIRECTION OUTPUT ;
    USE SIGNAL ;
    PORT
      LAYER M4 ;
        RECT  0 121.056 0.084 121.08 ;
    END
  END dout[49]
  PIN dout[4]
    DIRECTION OUTPUT ;
    USE SIGNAL ;
    PORT
      LAYER M4 ;
        RECT  0 94.464 0.084 94.488 ;
    END
  END dout[4]
  PIN dout[50]
    DIRECTION OUTPUT ;
    USE SIGNAL ;
    PORT
      LAYER M4 ;
        RECT  0 121.632 0.084 121.656 ;
    END
  END dout[50]
  PIN dout[51]
    DIRECTION OUTPUT ;
    USE SIGNAL ;
    PORT
      LAYER M4 ;
        RECT  0 122.256 0.084 122.28 ;
    END
  END dout[51]
  PIN dout[52]
    DIRECTION OUTPUT ;
    USE SIGNAL ;
    PORT
      LAYER M4 ;
        RECT  0 122.832 0.084 122.856 ;
    END
  END dout[52]
  PIN dout[53]
    DIRECTION OUTPUT ;
    USE SIGNAL ;
    PORT
      LAYER M4 ;
        RECT  0 123.408 0.084 123.432 ;
    END
  END dout[53]
  PIN dout[54]
    DIRECTION OUTPUT ;
    USE SIGNAL ;
    PORT
      LAYER M4 ;
        RECT  0 124.032 0.084 124.056 ;
    END
  END dout[54]
  PIN dout[55]
    DIRECTION OUTPUT ;
    USE SIGNAL ;
    PORT
      LAYER M4 ;
        RECT  0 124.608 0.084 124.632 ;
    END
  END dout[55]
  PIN dout[56]
    DIRECTION OUTPUT ;
    USE SIGNAL ;
    PORT
      LAYER M4 ;
        RECT  0 125.184 0.084 125.208 ;
    END
  END dout[56]
  PIN dout[57]
    DIRECTION OUTPUT ;
    USE SIGNAL ;
    PORT
      LAYER M4 ;
        RECT  0 125.808 0.084 125.832 ;
    END
  END dout[57]
  PIN dout[58]
    DIRECTION OUTPUT ;
    USE SIGNAL ;
    PORT
      LAYER M4 ;
        RECT  0 126.384 0.084 126.408 ;
    END
  END dout[58]
  PIN dout[59]
    DIRECTION OUTPUT ;
    USE SIGNAL ;
    PORT
      LAYER M4 ;
        RECT  0 126.96 0.084 126.984 ;
    END
  END dout[59]
  PIN dout[5]
    DIRECTION OUTPUT ;
    USE SIGNAL ;
    PORT
      LAYER M4 ;
        RECT  0 95.04 0.084 95.064 ;
    END
  END dout[5]
  PIN dout[60]
    DIRECTION OUTPUT ;
    USE SIGNAL ;
    PORT
      LAYER M4 ;
        RECT  0 127.536 0.084 127.56 ;
    END
  END dout[60]
  PIN dout[61]
    DIRECTION OUTPUT ;
    USE SIGNAL ;
    PORT
      LAYER M4 ;
        RECT  0 128.16 0.084 128.184 ;
    END
  END dout[61]
  PIN dout[62]
    DIRECTION OUTPUT ;
    USE SIGNAL ;
    PORT
      LAYER M4 ;
        RECT  0 128.736 0.084 128.76 ;
    END
  END dout[62]
  PIN dout[63]
    DIRECTION OUTPUT ;
    USE SIGNAL ;
    PORT
      LAYER M4 ;
        RECT  0 129.312 0.084 129.336 ;
    END
  END dout[63]
  PIN dout[64]
    DIRECTION OUTPUT ;
    USE SIGNAL ;
    PORT
      LAYER M4 ;
        RECT  0 129.936 0.084 129.96 ;
    END
  END dout[64]
  PIN dout[65]
    DIRECTION OUTPUT ;
    USE SIGNAL ;
    PORT
      LAYER M4 ;
        RECT  0 130.512 0.084 130.536 ;
    END
  END dout[65]
  PIN dout[66]
    DIRECTION OUTPUT ;
    USE SIGNAL ;
    PORT
      LAYER M4 ;
        RECT  0 131.088 0.084 131.112 ;
    END
  END dout[66]
  PIN dout[67]
    DIRECTION OUTPUT ;
    USE SIGNAL ;
    PORT
      LAYER M4 ;
        RECT  0 131.712 0.084 131.736 ;
    END
  END dout[67]
  PIN dout[68]
    DIRECTION OUTPUT ;
    USE SIGNAL ;
    PORT
      LAYER M4 ;
        RECT  0 132.288 0.084 132.312 ;
    END
  END dout[68]
  PIN dout[69]
    DIRECTION OUTPUT ;
    USE SIGNAL ;
    PORT
      LAYER M4 ;
        RECT  0 132.864 0.084 132.888 ;
    END
  END dout[69]
  PIN dout[6]
    DIRECTION OUTPUT ;
    USE SIGNAL ;
    PORT
      LAYER M4 ;
        RECT  0 95.616 0.084 95.64 ;
    END
  END dout[6]
  PIN dout[70]
    DIRECTION OUTPUT ;
    USE SIGNAL ;
    PORT
      LAYER M4 ;
        RECT  0 133.488 0.084 133.512 ;
    END
  END dout[70]
  PIN dout[71]
    DIRECTION OUTPUT ;
    USE SIGNAL ;
    PORT
      LAYER M4 ;
        RECT  0 134.064 0.084 134.088 ;
    END
  END dout[71]
  PIN dout[72]
    DIRECTION OUTPUT ;
    USE SIGNAL ;
    PORT
      LAYER M4 ;
        RECT  0 134.64 0.084 134.664 ;
    END
  END dout[72]
  PIN dout[73]
    DIRECTION OUTPUT ;
    USE SIGNAL ;
    PORT
      LAYER M4 ;
        RECT  0 135.264 0.084 135.288 ;
    END
  END dout[73]
  PIN dout[74]
    DIRECTION OUTPUT ;
    USE SIGNAL ;
    PORT
      LAYER M4 ;
        RECT  0 135.84 0.084 135.864 ;
    END
  END dout[74]
  PIN dout[75]
    DIRECTION OUTPUT ;
    USE SIGNAL ;
    PORT
      LAYER M4 ;
        RECT  0 136.416 0.084 136.44 ;
    END
  END dout[75]
  PIN dout[76]
    DIRECTION OUTPUT ;
    USE SIGNAL ;
    PORT
      LAYER M4 ;
        RECT  0 137.04 0.084 137.064 ;
    END
  END dout[76]
  PIN dout[77]
    DIRECTION OUTPUT ;
    USE SIGNAL ;
    PORT
      LAYER M4 ;
        RECT  0 137.616 0.084 137.64 ;
    END
  END dout[77]
  PIN dout[78]
    DIRECTION OUTPUT ;
    USE SIGNAL ;
    PORT
      LAYER M4 ;
        RECT  0 138.192 0.084 138.216 ;
    END
  END dout[78]
  PIN dout[79]
    DIRECTION OUTPUT ;
    USE SIGNAL ;
    PORT
      LAYER M4 ;
        RECT  0 138.816 0.084 138.84 ;
    END
  END dout[79]
  PIN dout[7]
    DIRECTION OUTPUT ;
    USE SIGNAL ;
    PORT
      LAYER M4 ;
        RECT  0 96.24 0.084 96.264 ;
    END
  END dout[7]
  PIN dout[80]
    DIRECTION OUTPUT ;
    USE SIGNAL ;
    PORT
      LAYER M4 ;
        RECT  0 139.392 0.084 139.416 ;
    END
  END dout[80]
  PIN dout[81]
    DIRECTION OUTPUT ;
    USE SIGNAL ;
    PORT
      LAYER M4 ;
        RECT  0 139.968 0.084 139.992 ;
    END
  END dout[81]
  PIN dout[82]
    DIRECTION OUTPUT ;
    USE SIGNAL ;
    PORT
      LAYER M4 ;
        RECT  0 140.544 0.084 140.568 ;
    END
  END dout[82]
  PIN dout[83]
    DIRECTION OUTPUT ;
    USE SIGNAL ;
    PORT
      LAYER M4 ;
        RECT  0 141.168 0.084 141.192 ;
    END
  END dout[83]
  PIN dout[84]
    DIRECTION OUTPUT ;
    USE SIGNAL ;
    PORT
      LAYER M4 ;
        RECT  0 141.744 0.084 141.768 ;
    END
  END dout[84]
  PIN dout[85]
    DIRECTION OUTPUT ;
    USE SIGNAL ;
    PORT
      LAYER M4 ;
        RECT  0 142.32 0.084 142.344 ;
    END
  END dout[85]
  PIN dout[86]
    DIRECTION OUTPUT ;
    USE SIGNAL ;
    PORT
      LAYER M4 ;
        RECT  0 142.944 0.084 142.968 ;
    END
  END dout[86]
  PIN dout[87]
    DIRECTION OUTPUT ;
    USE SIGNAL ;
    PORT
      LAYER M4 ;
        RECT  0 143.52 0.084 143.544 ;
    END
  END dout[87]
  PIN dout[88]
    DIRECTION OUTPUT ;
    USE SIGNAL ;
    PORT
      LAYER M4 ;
        RECT  0 144.096 0.084 144.12 ;
    END
  END dout[88]
  PIN dout[89]
    DIRECTION OUTPUT ;
    USE SIGNAL ;
    PORT
      LAYER M4 ;
        RECT  0 144.72 0.084 144.744 ;
    END
  END dout[89]
  PIN dout[8]
    DIRECTION OUTPUT ;
    USE SIGNAL ;
    PORT
      LAYER M4 ;
        RECT  0 96.816 0.084 96.84 ;
    END
  END dout[8]
  PIN dout[90]
    DIRECTION OUTPUT ;
    USE SIGNAL ;
    PORT
      LAYER M4 ;
        RECT  0 145.296 0.084 145.32 ;
    END
  END dout[90]
  PIN dout[91]
    DIRECTION OUTPUT ;
    USE SIGNAL ;
    PORT
      LAYER M4 ;
        RECT  0 145.872 0.084 145.896 ;
    END
  END dout[91]
  PIN dout[92]
    DIRECTION OUTPUT ;
    USE SIGNAL ;
    PORT
      LAYER M4 ;
        RECT  0 146.496 0.084 146.52 ;
    END
  END dout[92]
  PIN dout[93]
    DIRECTION OUTPUT ;
    USE SIGNAL ;
    PORT
      LAYER M4 ;
        RECT  0 147.072 0.084 147.096 ;
    END
  END dout[93]
  PIN dout[94]
    DIRECTION OUTPUT ;
    USE SIGNAL ;
    PORT
      LAYER M4 ;
        RECT  0 147.648 0.084 147.672 ;
    END
  END dout[94]
  PIN dout[95]
    DIRECTION OUTPUT ;
    USE SIGNAL ;
    PORT
      LAYER M4 ;
        RECT  0 148.272 0.084 148.296 ;
    END
  END dout[95]
  PIN dout[96]
    DIRECTION OUTPUT ;
    USE SIGNAL ;
    PORT
      LAYER M4 ;
        RECT  0 148.848 0.084 148.872 ;
    END
  END dout[96]
  PIN dout[97]
    DIRECTION OUTPUT ;
    USE SIGNAL ;
    PORT
      LAYER M4 ;
        RECT  0 149.424 0.084 149.448 ;
    END
  END dout[97]
  PIN dout[98]
    DIRECTION OUTPUT ;
    USE SIGNAL ;
    PORT
      LAYER M4 ;
        RECT  0 150.048 0.084 150.072 ;
    END
  END dout[98]
  PIN dout[99]
    DIRECTION OUTPUT ;
    USE SIGNAL ;
    PORT
      LAYER M4 ;
        RECT  0 150.624 0.084 150.648 ;
    END
  END dout[99]
  PIN dout[9]
    DIRECTION OUTPUT ;
    USE SIGNAL ;
    PORT
      LAYER M4 ;
        RECT  0 97.392 0.084 97.416 ;
    END
  END dout[9]
  PIN ra[0]
    DIRECTION INPUT ;
    USE SIGNAL ;
    PORT
      LAYER M4 ;
        RECT  0 189.456 0.084 189.48 ;
    END
  END ra[0]
  PIN ra[1]
    DIRECTION INPUT ;
    USE SIGNAL ;
    PORT
      LAYER M4 ;
        RECT  0 190.32 0.084 190.344 ;
    END
  END ra[1]
  PIN ra[2]
    DIRECTION INPUT ;
    USE SIGNAL ;
    PORT
      LAYER M4 ;
        RECT  0 191.232 0.084 191.256 ;
    END
  END ra[2]
  PIN ra[3]
    DIRECTION INPUT ;
    USE SIGNAL ;
    PORT
      LAYER M4 ;
        RECT  0 192.144 0.084 192.168 ;
    END
  END ra[3]
  PIN ra[4]
    DIRECTION INPUT ;
    USE SIGNAL ;
    PORT
      LAYER M4 ;
        RECT  0 193.056 0.084 193.08 ;
    END
  END ra[4]
  PIN ra[5]
    DIRECTION INPUT ;
    USE SIGNAL ;
    PORT
      LAYER M4 ;
        RECT  0 193.92 0.084 193.944 ;
    END
  END ra[5]
  PIN rd_v
    DIRECTION INPUT ;
    USE SIGNAL ;
    PORT
      LAYER M4 ;
        RECT  0 202.512 0.084 202.536 ;
    END
    PORT
      LAYER M4 ;
        RECT  0.06 202.512 0.857 202.536 ;
    END
  END rd_v
  PIN wa[0]
    DIRECTION INPUT ;
    USE SIGNAL ;
    PORT
      LAYER M4 ;
        RECT  0 178.656 0.084 178.68 ;
    END
  END wa[0]
  PIN wa[1]
    DIRECTION INPUT ;
    USE SIGNAL ;
    PORT
      LAYER M4 ;
        RECT  0 179.52 0.084 179.544 ;
    END
  END wa[1]
  PIN wa[2]
    DIRECTION INPUT ;
    USE SIGNAL ;
    PORT
      LAYER M4 ;
        RECT  0 180.432 0.084 180.456 ;
    END
  END wa[2]
  PIN wa[3]
    DIRECTION INPUT ;
    USE SIGNAL ;
    PORT
      LAYER M4 ;
        RECT  0 181.344 0.084 181.368 ;
    END
  END wa[3]
  PIN wa[4]
    DIRECTION INPUT ;
    USE SIGNAL ;
    PORT
      LAYER M4 ;
        RECT  0 182.256 0.084 182.28 ;
    END
  END wa[4]
  PIN wa[5]
    DIRECTION INPUT ;
    USE SIGNAL ;
    PORT
      LAYER M4 ;
        RECT  0 183.12 0.084 183.144 ;
    END
  END wa[5]
  PIN we
    DIRECTION INPUT ;
    USE SIGNAL ;
    PORT
      LAYER M4 ;
        RECT  0 8.112 0.084 8.136 ;
    END
    PORT
      LAYER M4 ;
        RECT  0.06 8.112 0.137 8.136 ;
    END
  END we
  PIN VDD
    DIRECTION INOUT ;
    USE POWER ;
    PORT
      LAYER M5 ;
        RECT  256.392 2.151 256.512 213.849 ;
        RECT  250.992 2.151 251.112 213.849 ;
        RECT  245.592 2.151 245.712 213.849 ;
        RECT  240.192 2.151 240.312 213.849 ;
        RECT  234.792 2.151 234.912 213.849 ;
        RECT  229.392 2.151 229.512 213.849 ;
        RECT  223.992 2.151 224.112 213.849 ;
        RECT  218.592 2.151 218.712 213.849 ;
        RECT  213.192 2.151 213.312 213.849 ;
        RECT  207.792 2.151 207.912 213.849 ;
        RECT  202.392 2.151 202.512 213.849 ;
        RECT  196.992 2.151 197.112 213.849 ;
        RECT  191.592 2.151 191.712 213.849 ;
        RECT  186.192 2.151 186.312 213.849 ;
        RECT  180.792 2.151 180.912 213.849 ;
        RECT  175.392 2.151 175.512 213.849 ;
        RECT  169.992 2.151 170.112 213.849 ;
        RECT  164.592 2.151 164.712 213.849 ;
        RECT  159.192 2.151 159.312 213.849 ;
        RECT  153.792 2.151 153.912 213.849 ;
        RECT  148.392 2.151 148.512 213.849 ;
        RECT  142.992 2.151 143.112 213.849 ;
        RECT  137.592 2.151 137.712 213.849 ;
        RECT  132.192 2.151 132.312 213.849 ;
        RECT  126.792 2.151 126.912 213.849 ;
        RECT  121.392 2.151 121.512 213.849 ;
        RECT  115.992 2.151 116.112 213.849 ;
        RECT  110.592 2.151 110.712 213.849 ;
        RECT  105.192 2.151 105.312 213.849 ;
        RECT  99.792 2.151 99.912 213.849 ;
        RECT  94.392 2.151 94.512 213.849 ;
        RECT  88.992 2.151 89.112 213.849 ;
        RECT  83.592 2.151 83.712 213.849 ;
        RECT  78.192 2.151 78.312 213.849 ;
        RECT  72.792 2.151 72.912 213.849 ;
        RECT  67.392 2.151 67.512 213.849 ;
        RECT  61.992 2.151 62.112 213.849 ;
        RECT  56.592 2.151 56.712 213.849 ;
        RECT  51.192 2.151 51.312 213.849 ;
        RECT  45.792 2.151 45.912 213.849 ;
        RECT  40.392 2.151 40.512 213.849 ;
        RECT  34.992 2.151 35.112 213.849 ;
        RECT  29.592 2.151 29.712 213.849 ;
        RECT  24.192 2.151 24.312 213.849 ;
        RECT  18.792 2.151 18.912 213.849 ;
        RECT  13.392 2.151 13.512 213.849 ;
        RECT  7.992 2.151 8.112 213.849 ;
        RECT  2.592 2.151 2.712 213.849 ;
    END
  END VDD
  PIN VSS
    DIRECTION INOUT ;
    USE GROUND ;
    PORT
      LAYER M5 ;
        RECT  256.2 2.137 256.32 213.863 ;
        RECT  250.8 2.137 250.92 213.863 ;
        RECT  245.4 2.137 245.52 213.863 ;
        RECT  240 2.137 240.12 213.863 ;
        RECT  234.6 2.137 234.72 213.863 ;
        RECT  229.2 2.137 229.32 213.863 ;
        RECT  223.8 2.137 223.92 213.863 ;
        RECT  218.4 2.137 218.52 213.863 ;
        RECT  213 2.137 213.12 213.863 ;
        RECT  207.6 2.137 207.72 213.863 ;
        RECT  202.2 2.137 202.32 213.863 ;
        RECT  196.8 2.137 196.92 213.863 ;
        RECT  191.4 2.137 191.52 213.863 ;
        RECT  186 2.137 186.12 213.863 ;
        RECT  180.6 2.137 180.72 213.863 ;
        RECT  175.2 2.137 175.32 213.863 ;
        RECT  169.8 2.137 169.92 213.863 ;
        RECT  164.4 2.137 164.52 213.863 ;
        RECT  159 2.137 159.12 213.863 ;
        RECT  153.6 2.137 153.72 213.863 ;
        RECT  148.2 2.137 148.32 213.863 ;
        RECT  142.8 2.137 142.92 213.863 ;
        RECT  137.4 2.137 137.52 213.863 ;
        RECT  132 2.137 132.12 213.863 ;
        RECT  126.6 2.137 126.72 213.863 ;
        RECT  121.2 2.137 121.32 213.863 ;
        RECT  115.8 2.137 115.92 213.863 ;
        RECT  110.4 2.137 110.52 213.863 ;
        RECT  105 2.137 105.12 213.863 ;
        RECT  99.6 2.137 99.72 213.863 ;
        RECT  94.2 2.137 94.32 213.863 ;
        RECT  88.8 2.137 88.92 213.863 ;
        RECT  83.4 2.137 83.52 213.863 ;
        RECT  78 2.137 78.12 213.863 ;
        RECT  72.6 2.137 72.72 213.863 ;
        RECT  67.2 2.137 67.32 213.863 ;
        RECT  61.8 2.137 61.92 213.863 ;
        RECT  56.4 2.137 56.52 213.863 ;
        RECT  51 2.137 51.12 213.863 ;
        RECT  45.6 2.137 45.72 213.863 ;
        RECT  40.2 2.137 40.32 213.863 ;
        RECT  34.8 2.137 34.92 213.863 ;
        RECT  29.4 2.137 29.52 213.863 ;
        RECT  24 2.137 24.12 213.863 ;
        RECT  18.6 2.137 18.72 213.863 ;
        RECT  13.2 2.137 13.32 213.863 ;
        RECT  7.8 2.137 7.92 213.863 ;
        RECT  2.4 2.137 2.52 213.863 ;
    END
  END VSS
  # OT_OBS_CLOSED layer=M5 d_um=1.536 added=112
  OBS
    LAYER RVTN ;
     RECT  2.16 2.16 257.04 2.295 ;
     RECT  2.16 2.565 257.04 2.835 ;
     RECT  2.16 3.105 257.04 3.375 ;
     RECT  2.16 3.645 257.04 3.915 ;
     RECT  2.16 4.185 257.04 4.455 ;
     RECT  2.16 4.725 257.04 4.995 ;
     RECT  2.16 5.265 257.04 5.535 ;
     RECT  2.16 5.805 257.04 6.075 ;
     RECT  2.16 6.345 257.04 6.615 ;
     RECT  2.16 6.885 257.04 7.155 ;
     RECT  2.16 7.425 257.04 7.695 ;
     RECT  2.16 7.965 257.04 8.235 ;
     RECT  2.16 8.505 257.04 8.775 ;
     RECT  2.16 9.045 257.04 9.315 ;
     RECT  2.16 9.585 257.04 9.855 ;
     RECT  2.16 10.125 257.04 10.395 ;
     RECT  2.16 10.665 257.04 10.935 ;
     RECT  2.16 11.205 257.04 11.475 ;
     RECT  2.16 11.745 257.04 12.015 ;
     RECT  2.16 12.285 257.04 12.555 ;
     RECT  2.16 12.825 257.04 13.095 ;
     RECT  2.16 13.365 257.04 13.635 ;
     RECT  2.16 13.905 257.04 14.175 ;
     RECT  2.16 14.445 257.04 14.715 ;
     RECT  2.16 14.985 257.04 15.255 ;
     RECT  2.16 15.525 257.04 15.795 ;
     RECT  2.16 16.065 257.04 16.335 ;
     RECT  2.16 16.605 257.04 16.875 ;
     RECT  2.16 17.145 257.04 17.415 ;
     RECT  2.16 17.685 257.04 17.955 ;
     RECT  2.16 18.225 257.04 18.495 ;
     RECT  2.16 18.765 257.04 19.035 ;
     RECT  2.16 19.305 257.04 19.575 ;
     RECT  2.16 19.845 257.04 20.115 ;
     RECT  2.16 20.385 257.04 20.655 ;
     RECT  2.16 20.925 257.04 21.195 ;
     RECT  2.16 21.465 257.04 21.735 ;
     RECT  2.16 22.005 257.04 22.275 ;
     RECT  2.16 22.545 257.04 22.815 ;
     RECT  2.16 23.085 257.04 23.355 ;
     RECT  2.16 23.625 257.04 23.895 ;
     RECT  2.16 24.165 257.04 24.435 ;
     RECT  2.16 24.705 257.04 24.975 ;
     RECT  2.16 25.245 257.04 25.515 ;
     RECT  2.16 25.785 257.04 26.055 ;
     RECT  2.16 26.325 257.04 26.595 ;
     RECT  2.16 26.865 257.04 27.135 ;
     RECT  2.16 27.405 257.04 27.675 ;
     RECT  2.16 27.945 257.04 28.215 ;
     RECT  2.16 28.485 257.04 28.755 ;
     RECT  2.16 29.025 257.04 29.295 ;
     RECT  2.16 29.565 257.04 29.835 ;
     RECT  2.16 30.105 257.04 30.375 ;
     RECT  2.16 30.645 257.04 30.915 ;
     RECT  2.16 31.185 257.04 31.455 ;
     RECT  2.16 31.725 257.04 31.995 ;
     RECT  2.16 32.265 257.04 32.4 ;
     RECT  2.16 32.4 32.4 32.535 ;
     RECT  225.288 32.4 257.04 32.535 ;
     RECT  2.16 32.805 32.4 33.075 ;
     RECT  225.288 32.805 257.04 33.075 ;
     RECT  2.16 33.345 32.4 33.615 ;
     RECT  225.288 33.345 257.04 33.615 ;
     RECT  2.16 33.885 32.4 34.155 ;
     RECT  225.288 33.885 257.04 34.155 ;
     RECT  2.16 34.425 32.4 34.695 ;
     RECT  225.288 34.425 257.04 34.695 ;
     RECT  2.16 34.965 32.4 35.235 ;
     RECT  225.288 34.965 257.04 35.235 ;
     RECT  2.16 35.505 32.4 35.775 ;
     RECT  225.288 35.505 257.04 35.775 ;
     RECT  2.16 36.045 32.4 36.315 ;
     RECT  225.288 36.045 257.04 36.315 ;
     RECT  2.16 36.585 32.4 36.855 ;
     RECT  225.288 36.585 257.04 36.855 ;
     RECT  2.16 37.125 32.4 37.395 ;
     RECT  225.288 37.125 257.04 37.395 ;
     RECT  2.16 37.665 32.4 37.935 ;
     RECT  225.288 37.665 257.04 37.935 ;
     RECT  2.16 38.205 32.4 38.475 ;
     RECT  225.288 38.205 257.04 38.475 ;
     RECT  2.16 38.745 32.4 39.015 ;
     RECT  225.288 38.745 257.04 39.015 ;
     RECT  2.16 39.285 32.4 39.555 ;
     RECT  225.288 39.285 257.04 39.555 ;
     RECT  2.16 39.825 32.4 40.095 ;
     RECT  225.288 39.825 257.04 40.095 ;
     RECT  2.16 40.365 32.4 40.635 ;
     RECT  225.288 40.365 257.04 40.635 ;
     RECT  2.16 40.905 32.4 41.175 ;
     RECT  225.288 40.905 257.04 41.175 ;
     RECT  2.16 41.445 32.4 41.715 ;
     RECT  225.288 41.445 257.04 41.715 ;
     RECT  2.16 41.985 32.4 42.255 ;
     RECT  225.288 41.985 257.04 42.255 ;
     RECT  2.16 42.525 32.4 42.795 ;
     RECT  225.288 42.525 257.04 42.795 ;
     RECT  2.16 43.065 32.4 43.335 ;
     RECT  225.288 43.065 257.04 43.335 ;
     RECT  2.16 43.605 32.4 43.875 ;
     RECT  225.288 43.605 257.04 43.875 ;
     RECT  2.16 44.145 32.4 44.415 ;
     RECT  225.288 44.145 257.04 44.415 ;
     RECT  2.16 44.685 32.4 44.955 ;
     RECT  225.288 44.685 257.04 44.955 ;
     RECT  2.16 45.225 32.4 45.495 ;
     RECT  225.288 45.225 257.04 45.495 ;
     RECT  2.16 45.765 32.4 46.035 ;
     RECT  225.288 45.765 257.04 46.035 ;
     RECT  2.16 46.305 32.4 46.575 ;
     RECT  225.288 46.305 257.04 46.575 ;
     RECT  2.16 46.845 32.4 47.115 ;
     RECT  225.288 46.845 257.04 47.115 ;
     RECT  2.16 47.385 32.4 47.655 ;
     RECT  225.288 47.385 257.04 47.655 ;
     RECT  2.16 47.925 32.4 48.195 ;
     RECT  225.288 47.925 257.04 48.195 ;
     RECT  2.16 48.465 32.4 48.735 ;
     RECT  225.288 48.465 257.04 48.735 ;
     RECT  2.16 49.005 32.4 49.275 ;
     RECT  225.288 49.005 257.04 49.275 ;
     RECT  2.16 49.545 32.4 49.815 ;
     RECT  225.288 49.545 257.04 49.815 ;
     RECT  2.16 50.085 32.4 50.355 ;
     RECT  225.288 50.085 257.04 50.355 ;
     RECT  2.16 50.625 32.4 50.895 ;
     RECT  225.288 50.625 257.04 50.895 ;
     RECT  2.16 51.165 32.4 51.435 ;
     RECT  225.288 51.165 257.04 51.435 ;
     RECT  2.16 51.705 32.4 51.975 ;
     RECT  225.288 51.705 257.04 51.975 ;
     RECT  2.16 52.245 32.4 52.515 ;
     RECT  225.288 52.245 257.04 52.515 ;
     RECT  2.16 52.785 32.4 53.055 ;
     RECT  225.288 52.785 257.04 53.055 ;
     RECT  2.16 53.325 32.4 53.595 ;
     RECT  225.288 53.325 257.04 53.595 ;
     RECT  2.16 53.865 32.4 54.135 ;
     RECT  225.288 53.865 257.04 54.135 ;
     RECT  2.16 54.405 32.4 54.675 ;
     RECT  225.288 54.405 257.04 54.675 ;
     RECT  2.16 54.945 32.4 55.215 ;
     RECT  225.288 54.945 257.04 55.215 ;
     RECT  2.16 55.485 32.4 55.755 ;
     RECT  225.288 55.485 257.04 55.755 ;
     RECT  2.16 56.025 32.4 56.295 ;
     RECT  225.288 56.025 257.04 56.295 ;
     RECT  2.16 56.565 32.4 56.835 ;
     RECT  225.288 56.565 257.04 56.835 ;
     RECT  2.16 57.105 32.4 57.375 ;
     RECT  225.288 57.105 257.04 57.375 ;
     RECT  2.16 57.645 32.4 57.915 ;
     RECT  225.288 57.645 257.04 57.915 ;
     RECT  2.16 58.185 32.4 58.455 ;
     RECT  225.288 58.185 257.04 58.455 ;
     RECT  2.16 58.725 32.4 58.995 ;
     RECT  225.288 58.725 257.04 58.995 ;
     RECT  2.16 59.265 32.4 59.535 ;
     RECT  225.288 59.265 257.04 59.535 ;
     RECT  2.16 59.805 32.4 60.075 ;
     RECT  225.288 59.805 257.04 60.075 ;
     RECT  2.16 60.345 32.4 60.615 ;
     RECT  225.288 60.345 257.04 60.615 ;
     RECT  2.16 60.885 32.4 61.155 ;
     RECT  225.288 60.885 257.04 61.155 ;
     RECT  2.16 61.425 32.4 61.695 ;
     RECT  225.288 61.425 257.04 61.695 ;
     RECT  2.16 61.965 32.4 62.235 ;
     RECT  225.288 61.965 257.04 62.235 ;
     RECT  2.16 62.505 32.4 62.775 ;
     RECT  225.288 62.505 257.04 62.775 ;
     RECT  2.16 63.045 32.4 63.315 ;
     RECT  225.288 63.045 257.04 63.315 ;
     RECT  2.16 63.585 32.4 63.855 ;
     RECT  225.288 63.585 257.04 63.855 ;
     RECT  2.16 64.125 32.4 64.395 ;
     RECT  225.288 64.125 257.04 64.395 ;
     RECT  2.16 64.665 32.4 64.935 ;
     RECT  225.288 64.665 257.04 64.935 ;
     RECT  2.16 65.205 32.4 65.475 ;
     RECT  225.288 65.205 257.04 65.475 ;
     RECT  2.16 65.745 32.4 66.015 ;
     RECT  225.288 65.745 257.04 66.015 ;
     RECT  2.16 66.285 32.4 66.555 ;
     RECT  225.288 66.285 257.04 66.555 ;
     RECT  2.16 66.825 32.4 67.095 ;
     RECT  225.288 66.825 257.04 67.095 ;
     RECT  2.16 67.365 32.4 67.635 ;
     RECT  225.288 67.365 257.04 67.635 ;
     RECT  2.16 67.905 32.4 68.175 ;
     RECT  225.288 67.905 257.04 68.175 ;
     RECT  2.16 68.445 32.4 68.715 ;
     RECT  225.288 68.445 257.04 68.715 ;
     RECT  2.16 68.985 32.4 69.255 ;
     RECT  225.288 68.985 257.04 69.255 ;
     RECT  2.16 69.525 32.4 69.795 ;
     RECT  225.288 69.525 257.04 69.795 ;
     RECT  2.16 70.065 32.4 70.335 ;
     RECT  225.288 70.065 257.04 70.335 ;
     RECT  2.16 70.605 32.4 70.875 ;
     RECT  225.288 70.605 257.04 70.875 ;
     RECT  2.16 71.145 32.4 71.415 ;
     RECT  225.288 71.145 257.04 71.415 ;
     RECT  2.16 71.685 32.4 71.955 ;
     RECT  225.288 71.685 257.04 71.955 ;
     RECT  2.16 72.225 32.4 72.495 ;
     RECT  225.288 72.225 257.04 72.495 ;
     RECT  2.16 72.765 32.4 73.035 ;
     RECT  225.288 72.765 257.04 73.035 ;
     RECT  2.16 73.305 32.4 73.575 ;
     RECT  225.288 73.305 257.04 73.575 ;
     RECT  2.16 73.845 32.4 74.115 ;
     RECT  225.288 73.845 257.04 74.115 ;
     RECT  2.16 74.385 32.4 74.655 ;
     RECT  225.288 74.385 257.04 74.655 ;
     RECT  2.16 74.925 32.4 75.195 ;
     RECT  225.288 74.925 257.04 75.195 ;
     RECT  2.16 75.465 32.4 75.735 ;
     RECT  225.288 75.465 257.04 75.735 ;
     RECT  2.16 76.005 32.4 76.275 ;
     RECT  225.288 76.005 257.04 76.275 ;
     RECT  2.16 76.545 32.4 76.815 ;
     RECT  225.288 76.545 257.04 76.815 ;
     RECT  2.16 77.085 32.4 77.355 ;
     RECT  225.288 77.085 257.04 77.355 ;
     RECT  2.16 77.625 32.4 77.895 ;
     RECT  225.288 77.625 257.04 77.895 ;
     RECT  2.16 78.165 32.4 78.435 ;
     RECT  225.288 78.165 257.04 78.435 ;
     RECT  2.16 78.705 32.4 78.975 ;
     RECT  225.288 78.705 257.04 78.975 ;
     RECT  2.16 79.245 32.4 79.515 ;
     RECT  225.288 79.245 257.04 79.515 ;
     RECT  2.16 79.785 32.4 80.055 ;
     RECT  225.288 79.785 257.04 80.055 ;
     RECT  2.16 80.325 32.4 80.595 ;
     RECT  225.288 80.325 257.04 80.595 ;
     RECT  2.16 80.865 32.4 81.135 ;
     RECT  225.288 80.865 257.04 81.135 ;
     RECT  2.16 81.405 32.4 81.675 ;
     RECT  225.288 81.405 257.04 81.675 ;
     RECT  2.16 81.945 32.4 82.215 ;
     RECT  225.288 81.945 257.04 82.215 ;
     RECT  2.16 82.485 32.4 82.755 ;
     RECT  225.288 82.485 257.04 82.755 ;
     RECT  2.16 83.025 32.4 83.295 ;
     RECT  225.288 83.025 257.04 83.295 ;
     RECT  2.16 83.565 32.4 83.835 ;
     RECT  225.288 83.565 257.04 83.835 ;
     RECT  2.16 84.105 32.4 84.375 ;
     RECT  225.288 84.105 257.04 84.375 ;
     RECT  2.16 84.645 32.4 84.915 ;
     RECT  225.288 84.645 257.04 84.915 ;
     RECT  2.16 85.185 32.4 85.455 ;
     RECT  225.288 85.185 257.04 85.455 ;
     RECT  2.16 85.725 32.4 85.995 ;
     RECT  225.288 85.725 257.04 85.995 ;
     RECT  2.16 86.265 32.4 86.535 ;
     RECT  225.288 86.265 257.04 86.535 ;
     RECT  2.16 86.805 32.4 87.075 ;
     RECT  225.288 86.805 257.04 87.075 ;
     RECT  2.16 87.345 32.4 87.615 ;
     RECT  225.288 87.345 257.04 87.615 ;
     RECT  2.16 87.885 32.4 88.155 ;
     RECT  225.288 87.885 257.04 88.155 ;
     RECT  2.16 88.425 32.4 88.695 ;
     RECT  225.288 88.425 257.04 88.695 ;
     RECT  2.16 88.965 32.4 89.235 ;
     RECT  225.288 88.965 257.04 89.235 ;
     RECT  2.16 89.505 32.4 89.775 ;
     RECT  225.288 89.505 257.04 89.775 ;
     RECT  2.16 90.045 32.4 90.315 ;
     RECT  225.288 90.045 257.04 90.315 ;
     RECT  2.16 90.585 32.4 90.855 ;
     RECT  225.288 90.585 257.04 90.855 ;
     RECT  2.16 91.125 32.4 91.395 ;
     RECT  225.288 91.125 257.04 91.395 ;
     RECT  2.16 91.665 32.4 91.935 ;
     RECT  225.288 91.665 257.04 91.935 ;
     RECT  2.16 92.205 32.4 92.475 ;
     RECT  225.288 92.205 257.04 92.475 ;
     RECT  2.16 92.745 32.4 93.015 ;
     RECT  225.288 92.745 257.04 93.015 ;
     RECT  2.16 93.285 32.4 93.555 ;
     RECT  225.288 93.285 257.04 93.555 ;
     RECT  2.16 93.825 32.4 94.095 ;
     RECT  225.288 93.825 257.04 94.095 ;
     RECT  2.16 94.365 32.4 94.635 ;
     RECT  225.288 94.365 257.04 94.635 ;
     RECT  2.16 94.905 32.4 95.175 ;
     RECT  225.288 94.905 257.04 95.175 ;
     RECT  2.16 95.445 32.4 95.715 ;
     RECT  225.288 95.445 257.04 95.715 ;
     RECT  2.16 95.985 32.4 96.255 ;
     RECT  225.288 95.985 257.04 96.255 ;
     RECT  2.16 96.525 32.4 96.795 ;
     RECT  225.288 96.525 257.04 96.795 ;
     RECT  2.16 97.065 32.4 97.335 ;
     RECT  225.288 97.065 257.04 97.335 ;
     RECT  2.16 97.605 32.4 97.875 ;
     RECT  225.288 97.605 257.04 97.875 ;
     RECT  2.16 98.145 32.4 98.415 ;
     RECT  225.288 98.145 257.04 98.415 ;
     RECT  2.16 98.685 32.4 98.955 ;
     RECT  225.288 98.685 257.04 98.955 ;
     RECT  2.16 99.225 32.4 99.495 ;
     RECT  225.288 99.225 257.04 99.495 ;
     RECT  2.16 99.765 32.4 100.035 ;
     RECT  225.288 99.765 257.04 100.035 ;
     RECT  2.16 100.305 32.4 100.575 ;
     RECT  225.288 100.305 257.04 100.575 ;
     RECT  2.16 100.845 32.4 101.115 ;
     RECT  225.288 100.845 257.04 101.115 ;
     RECT  2.16 101.385 32.4 101.655 ;
     RECT  225.288 101.385 257.04 101.655 ;
     RECT  2.16 101.925 32.4 102.195 ;
     RECT  225.288 101.925 257.04 102.195 ;
     RECT  2.16 102.465 32.4 102.735 ;
     RECT  225.288 102.465 257.04 102.735 ;
     RECT  2.16 103.005 32.4 103.275 ;
     RECT  225.288 103.005 257.04 103.275 ;
     RECT  2.16 103.545 32.4 103.815 ;
     RECT  225.288 103.545 257.04 103.815 ;
     RECT  2.16 104.085 32.4 104.355 ;
     RECT  225.288 104.085 257.04 104.355 ;
     RECT  2.16 104.625 32.4 104.895 ;
     RECT  225.288 104.625 257.04 104.895 ;
     RECT  2.16 105.165 32.4 105.435 ;
     RECT  225.288 105.165 257.04 105.435 ;
     RECT  2.16 105.705 32.4 105.975 ;
     RECT  225.288 105.705 257.04 105.975 ;
     RECT  2.16 106.245 32.4 106.515 ;
     RECT  225.288 106.245 257.04 106.515 ;
     RECT  2.16 106.785 32.4 107.055 ;
     RECT  225.288 106.785 257.04 107.055 ;
     RECT  2.16 107.325 32.4 107.595 ;
     RECT  225.288 107.325 257.04 107.595 ;
     RECT  2.16 107.865 32.4 108.135 ;
     RECT  225.288 107.865 257.04 108.135 ;
     RECT  2.16 108.405 32.4 108.675 ;
     RECT  225.288 108.405 257.04 108.675 ;
     RECT  2.16 108.945 32.4 109.215 ;
     RECT  225.288 108.945 257.04 109.215 ;
     RECT  2.16 109.485 32.4 109.755 ;
     RECT  225.288 109.485 257.04 109.755 ;
     RECT  2.16 110.025 32.4 110.295 ;
     RECT  225.288 110.025 257.04 110.295 ;
     RECT  2.16 110.565 32.4 110.835 ;
     RECT  225.288 110.565 257.04 110.835 ;
     RECT  2.16 111.105 32.4 111.375 ;
     RECT  225.288 111.105 257.04 111.375 ;
     RECT  2.16 111.645 32.4 111.915 ;
     RECT  225.288 111.645 257.04 111.915 ;
     RECT  2.16 112.185 32.4 112.455 ;
     RECT  225.288 112.185 257.04 112.455 ;
     RECT  2.16 112.725 32.4 112.995 ;
     RECT  225.288 112.725 257.04 112.995 ;
     RECT  2.16 113.265 32.4 113.535 ;
     RECT  225.288 113.265 257.04 113.535 ;
     RECT  2.16 113.805 32.4 114.075 ;
     RECT  225.288 113.805 257.04 114.075 ;
     RECT  2.16 114.345 32.4 114.615 ;
     RECT  225.288 114.345 257.04 114.615 ;
     RECT  2.16 114.885 32.4 115.155 ;
     RECT  225.288 114.885 257.04 115.155 ;
     RECT  2.16 115.425 32.4 115.695 ;
     RECT  225.288 115.425 257.04 115.695 ;
     RECT  2.16 115.965 32.4 116.235 ;
     RECT  225.288 115.965 257.04 116.235 ;
     RECT  2.16 116.505 32.4 116.775 ;
     RECT  225.288 116.505 257.04 116.775 ;
     RECT  2.16 117.045 32.4 117.315 ;
     RECT  225.288 117.045 257.04 117.315 ;
     RECT  2.16 117.585 32.4 117.855 ;
     RECT  225.288 117.585 257.04 117.855 ;
     RECT  2.16 118.125 32.4 118.395 ;
     RECT  225.288 118.125 257.04 118.395 ;
     RECT  2.16 118.665 32.4 118.935 ;
     RECT  225.288 118.665 257.04 118.935 ;
     RECT  2.16 119.205 32.4 119.475 ;
     RECT  225.288 119.205 257.04 119.475 ;
     RECT  2.16 119.745 32.4 120.015 ;
     RECT  225.288 119.745 257.04 120.015 ;
     RECT  2.16 120.285 32.4 120.555 ;
     RECT  225.288 120.285 257.04 120.555 ;
     RECT  2.16 120.825 32.4 121.095 ;
     RECT  225.288 120.825 257.04 121.095 ;
     RECT  2.16 121.365 32.4 121.635 ;
     RECT  225.288 121.365 257.04 121.635 ;
     RECT  2.16 121.905 32.4 122.175 ;
     RECT  225.288 121.905 257.04 122.175 ;
     RECT  2.16 122.445 32.4 122.715 ;
     RECT  225.288 122.445 257.04 122.715 ;
     RECT  2.16 122.985 32.4 123.255 ;
     RECT  225.288 122.985 257.04 123.255 ;
     RECT  2.16 123.525 32.4 123.795 ;
     RECT  225.288 123.525 257.04 123.795 ;
     RECT  2.16 124.065 32.4 124.335 ;
     RECT  225.288 124.065 257.04 124.335 ;
     RECT  2.16 124.605 32.4 124.875 ;
     RECT  225.288 124.605 257.04 124.875 ;
     RECT  2.16 125.145 32.4 125.415 ;
     RECT  225.288 125.145 257.04 125.415 ;
     RECT  2.16 125.685 32.4 125.955 ;
     RECT  225.288 125.685 257.04 125.955 ;
     RECT  2.16 126.225 32.4 126.495 ;
     RECT  225.288 126.225 257.04 126.495 ;
     RECT  2.16 126.765 32.4 127.035 ;
     RECT  225.288 126.765 257.04 127.035 ;
     RECT  2.16 127.305 32.4 127.575 ;
     RECT  225.288 127.305 257.04 127.575 ;
     RECT  2.16 127.845 32.4 128.115 ;
     RECT  225.288 127.845 257.04 128.115 ;
     RECT  2.16 128.385 32.4 128.655 ;
     RECT  225.288 128.385 257.04 128.655 ;
     RECT  2.16 128.925 32.4 129.195 ;
     RECT  225.288 128.925 257.04 129.195 ;
     RECT  2.16 129.465 32.4 129.735 ;
     RECT  225.288 129.465 257.04 129.735 ;
     RECT  2.16 130.005 32.4 130.275 ;
     RECT  225.288 130.005 257.04 130.275 ;
     RECT  2.16 130.545 32.4 130.815 ;
     RECT  225.288 130.545 257.04 130.815 ;
     RECT  2.16 131.085 32.4 131.355 ;
     RECT  225.288 131.085 257.04 131.355 ;
     RECT  2.16 131.625 32.4 131.895 ;
     RECT  225.288 131.625 257.04 131.895 ;
     RECT  2.16 132.165 257.04 132.435 ;
     RECT  2.16 132.705 257.04 132.975 ;
     RECT  2.16 133.245 257.04 133.515 ;
     RECT  2.16 133.785 257.04 134.055 ;
     RECT  2.16 134.325 257.04 134.595 ;
     RECT  2.16 134.865 257.04 135.135 ;
     RECT  2.16 135.405 257.04 135.675 ;
     RECT  2.16 135.945 257.04 136.215 ;
     RECT  2.16 136.485 257.04 136.755 ;
     RECT  2.16 137.025 257.04 137.295 ;
     RECT  2.16 137.565 257.04 137.835 ;
     RECT  2.16 138.105 257.04 138.375 ;
     RECT  2.16 138.645 257.04 138.915 ;
     RECT  2.16 139.185 257.04 139.455 ;
     RECT  2.16 139.725 257.04 139.995 ;
     RECT  2.16 140.265 257.04 140.535 ;
     RECT  2.16 140.805 257.04 141.075 ;
     RECT  2.16 141.345 257.04 141.615 ;
     RECT  2.16 141.885 257.04 142.155 ;
     RECT  2.16 142.425 257.04 142.695 ;
     RECT  2.16 142.965 257.04 143.235 ;
     RECT  2.16 143.505 257.04 143.775 ;
     RECT  2.16 144.045 257.04 144.315 ;
     RECT  2.16 144.585 257.04 144.855 ;
     RECT  2.16 145.125 257.04 145.395 ;
     RECT  2.16 145.665 257.04 145.935 ;
     RECT  2.16 146.205 257.04 146.475 ;
     RECT  2.16 146.745 257.04 147.015 ;
     RECT  2.16 147.285 257.04 147.555 ;
     RECT  2.16 147.825 257.04 148.095 ;
     RECT  2.16 148.365 257.04 148.635 ;
     RECT  2.16 148.905 257.04 149.175 ;
     RECT  2.16 149.445 257.04 149.715 ;
     RECT  2.16 149.985 257.04 150.255 ;
     RECT  2.16 150.525 257.04 150.795 ;
     RECT  2.16 151.065 257.04 151.335 ;
     RECT  2.16 151.605 257.04 151.875 ;
     RECT  2.16 152.145 257.04 152.415 ;
     RECT  2.16 152.685 257.04 152.955 ;
     RECT  2.16 153.225 257.04 153.495 ;
     RECT  2.16 153.765 257.04 154.035 ;
     RECT  2.16 154.305 257.04 154.575 ;
     RECT  2.16 154.845 257.04 155.115 ;
     RECT  2.16 155.385 257.04 155.655 ;
     RECT  2.16 155.925 257.04 156.195 ;
     RECT  2.16 156.465 257.04 156.735 ;
     RECT  2.16 157.005 257.04 157.275 ;
     RECT  2.16 157.545 257.04 157.815 ;
     RECT  2.16 158.085 257.04 158.355 ;
     RECT  2.16 158.625 257.04 158.895 ;
     RECT  2.16 159.165 257.04 159.435 ;
     RECT  2.16 159.705 257.04 159.975 ;
     RECT  2.16 160.245 257.04 160.515 ;
     RECT  2.16 160.785 257.04 161.055 ;
     RECT  2.16 161.325 257.04 161.595 ;
     RECT  2.16 161.865 257.04 162.135 ;
     RECT  2.16 162.405 257.04 162.675 ;
     RECT  2.16 162.945 257.04 163.215 ;
     RECT  2.16 163.485 257.04 163.755 ;
     RECT  2.16 164.025 257.04 164.295 ;
     RECT  2.16 164.565 257.04 164.835 ;
     RECT  2.16 165.105 257.04 165.375 ;
     RECT  2.16 165.645 257.04 165.915 ;
     RECT  2.16 166.185 257.04 166.455 ;
     RECT  2.16 166.725 257.04 166.995 ;
     RECT  2.16 167.265 257.04 167.535 ;
     RECT  2.16 167.805 257.04 168.075 ;
     RECT  2.16 168.345 257.04 168.615 ;
     RECT  2.16 168.885 257.04 169.155 ;
     RECT  2.16 169.425 257.04 169.695 ;
     RECT  2.16 169.965 257.04 170.235 ;
     RECT  2.16 170.505 257.04 170.775 ;
     RECT  2.16 171.045 257.04 171.315 ;
     RECT  2.16 171.585 257.04 171.855 ;
     RECT  2.16 172.125 257.04 172.395 ;
     RECT  2.16 172.665 257.04 172.935 ;
     RECT  2.16 173.205 257.04 173.475 ;
     RECT  2.16 173.745 257.04 174.015 ;
     RECT  2.16 174.285 257.04 174.555 ;
     RECT  2.16 174.825 257.04 175.095 ;
     RECT  2.16 175.365 257.04 175.635 ;
     RECT  2.16 175.905 257.04 176.175 ;
     RECT  2.16 176.445 257.04 176.715 ;
     RECT  2.16 176.985 257.04 177.255 ;
     RECT  2.16 177.525 257.04 177.795 ;
     RECT  2.16 178.065 257.04 178.335 ;
     RECT  2.16 178.605 257.04 178.875 ;
     RECT  2.16 179.145 257.04 179.415 ;
     RECT  2.16 179.685 257.04 179.955 ;
     RECT  2.16 180.225 257.04 180.495 ;
     RECT  2.16 180.765 257.04 181.035 ;
     RECT  2.16 181.305 257.04 181.575 ;
     RECT  2.16 181.845 257.04 182.115 ;
     RECT  2.16 182.385 257.04 182.655 ;
     RECT  2.16 182.925 257.04 183.195 ;
     RECT  2.16 183.465 257.04 183.735 ;
     RECT  2.16 184.005 257.04 184.275 ;
     RECT  2.16 184.545 257.04 184.815 ;
     RECT  2.16 185.085 257.04 185.355 ;
     RECT  2.16 185.625 257.04 185.895 ;
     RECT  2.16 186.165 257.04 186.435 ;
     RECT  2.16 186.705 257.04 186.975 ;
     RECT  2.16 187.245 257.04 187.515 ;
     RECT  2.16 187.785 257.04 188.055 ;
     RECT  2.16 188.325 257.04 188.595 ;
     RECT  2.16 188.865 257.04 189.135 ;
     RECT  2.16 189.405 257.04 189.675 ;
     RECT  2.16 189.945 257.04 190.215 ;
     RECT  2.16 190.485 257.04 190.755 ;
     RECT  2.16 191.025 257.04 191.295 ;
     RECT  2.16 191.565 257.04 191.835 ;
     RECT  2.16 192.105 257.04 192.375 ;
     RECT  2.16 192.645 257.04 192.915 ;
     RECT  2.16 193.185 257.04 193.455 ;
     RECT  2.16 193.725 257.04 193.995 ;
     RECT  2.16 194.265 257.04 194.535 ;
     RECT  2.16 194.805 257.04 195.075 ;
     RECT  2.16 195.345 257.04 195.615 ;
     RECT  2.16 195.885 257.04 196.155 ;
     RECT  2.16 196.425 257.04 196.695 ;
     RECT  2.16 196.965 257.04 197.235 ;
     RECT  2.16 197.505 257.04 197.775 ;
     RECT  2.16 198.045 257.04 198.315 ;
     RECT  2.16 198.585 257.04 198.855 ;
     RECT  2.16 199.125 257.04 199.395 ;
     RECT  2.16 199.665 257.04 199.935 ;
     RECT  2.16 200.205 257.04 200.475 ;
     RECT  2.16 200.745 257.04 201.015 ;
     RECT  2.16 201.285 257.04 201.555 ;
     RECT  2.16 201.825 257.04 202.095 ;
     RECT  2.16 202.365 257.04 202.635 ;
     RECT  2.16 202.905 257.04 203.175 ;
     RECT  2.16 203.445 257.04 203.715 ;
     RECT  2.16 203.985 257.04 204.255 ;
     RECT  2.16 204.525 257.04 204.795 ;
     RECT  2.16 205.065 257.04 205.335 ;
     RECT  2.16 205.605 257.04 205.875 ;
     RECT  2.16 206.145 257.04 206.415 ;
     RECT  2.16 206.685 257.04 206.955 ;
     RECT  2.16 207.225 257.04 207.495 ;
     RECT  2.16 207.765 257.04 208.035 ;
     RECT  2.16 208.305 257.04 208.575 ;
     RECT  2.16 208.845 257.04 209.115 ;
     RECT  2.16 209.385 257.04 209.655 ;
     RECT  2.16 209.925 257.04 210.195 ;
     RECT  2.16 210.465 257.04 210.735 ;
     RECT  2.16 211.005 257.04 211.275 ;
     RECT  2.16 211.545 257.04 211.815 ;
     RECT  2.16 212.085 257.04 212.355 ;
     RECT  2.16 212.625 257.04 212.895 ;
     RECT  2.16 213.165 257.04 213.435 ;
     RECT  2.16 213.705 257.04 213.84 ;
    LAYER RVTP ;
     RECT  2.16 2.295 257.04 2.565 ;
     RECT  2.16 2.835 257.04 3.105 ;
     RECT  2.16 3.375 257.04 3.645 ;
     RECT  2.16 3.915 257.04 4.185 ;
     RECT  2.16 4.455 257.04 4.725 ;
     RECT  2.16 4.995 257.04 5.265 ;
     RECT  2.16 5.535 257.04 5.805 ;
     RECT  2.16 6.075 257.04 6.345 ;
     RECT  2.16 6.615 257.04 6.885 ;
     RECT  2.16 7.155 257.04 7.425 ;
     RECT  2.16 7.695 257.04 7.965 ;
     RECT  2.16 8.235 257.04 8.505 ;
     RECT  2.16 8.775 257.04 9.045 ;
     RECT  2.16 9.315 257.04 9.585 ;
     RECT  2.16 9.855 257.04 10.125 ;
     RECT  2.16 10.395 257.04 10.665 ;
     RECT  2.16 10.935 257.04 11.205 ;
     RECT  2.16 11.475 257.04 11.745 ;
     RECT  2.16 12.015 257.04 12.285 ;
     RECT  2.16 12.555 257.04 12.825 ;
     RECT  2.16 13.095 257.04 13.365 ;
     RECT  2.16 13.635 257.04 13.905 ;
     RECT  2.16 14.175 257.04 14.445 ;
     RECT  2.16 14.715 257.04 14.985 ;
     RECT  2.16 15.255 257.04 15.525 ;
     RECT  2.16 15.795 257.04 16.065 ;
     RECT  2.16 16.335 257.04 16.605 ;
     RECT  2.16 16.875 257.04 17.145 ;
     RECT  2.16 17.415 257.04 17.685 ;
     RECT  2.16 17.955 257.04 18.225 ;
     RECT  2.16 18.495 257.04 18.765 ;
     RECT  2.16 19.035 257.04 19.305 ;
     RECT  2.16 19.575 257.04 19.845 ;
     RECT  2.16 20.115 257.04 20.385 ;
     RECT  2.16 20.655 257.04 20.925 ;
     RECT  2.16 21.195 257.04 21.465 ;
     RECT  2.16 21.735 257.04 22.005 ;
     RECT  2.16 22.275 257.04 22.545 ;
     RECT  2.16 22.815 257.04 23.085 ;
     RECT  2.16 23.355 257.04 23.625 ;
     RECT  2.16 23.895 257.04 24.165 ;
     RECT  2.16 24.435 257.04 24.705 ;
     RECT  2.16 24.975 257.04 25.245 ;
     RECT  2.16 25.515 257.04 25.785 ;
     RECT  2.16 26.055 257.04 26.325 ;
     RECT  2.16 26.595 257.04 26.865 ;
     RECT  2.16 27.135 257.04 27.405 ;
     RECT  2.16 27.675 257.04 27.945 ;
     RECT  2.16 28.215 257.04 28.485 ;
     RECT  2.16 28.755 257.04 29.025 ;
     RECT  2.16 29.295 257.04 29.565 ;
     RECT  2.16 29.835 257.04 30.105 ;
     RECT  2.16 30.375 257.04 30.645 ;
     RECT  2.16 30.915 257.04 31.185 ;
     RECT  2.16 31.455 257.04 31.725 ;
     RECT  2.16 31.995 257.04 32.265 ;
     RECT  2.16 32.535 32.4 32.805 ;
     RECT  225.288 32.535 257.04 32.805 ;
     RECT  2.16 33.075 32.4 33.345 ;
     RECT  225.288 33.075 257.04 33.345 ;
     RECT  2.16 33.615 32.4 33.885 ;
     RECT  225.288 33.615 257.04 33.885 ;
     RECT  2.16 34.155 32.4 34.425 ;
     RECT  225.288 34.155 257.04 34.425 ;
     RECT  2.16 34.695 32.4 34.965 ;
     RECT  225.288 34.695 257.04 34.965 ;
     RECT  2.16 35.235 32.4 35.505 ;
     RECT  225.288 35.235 257.04 35.505 ;
     RECT  2.16 35.775 32.4 36.045 ;
     RECT  225.288 35.775 257.04 36.045 ;
     RECT  2.16 36.315 32.4 36.585 ;
     RECT  225.288 36.315 257.04 36.585 ;
     RECT  2.16 36.855 32.4 37.125 ;
     RECT  225.288 36.855 257.04 37.125 ;
     RECT  2.16 37.395 32.4 37.665 ;
     RECT  225.288 37.395 257.04 37.665 ;
     RECT  2.16 37.935 32.4 38.205 ;
     RECT  225.288 37.935 257.04 38.205 ;
     RECT  2.16 38.475 32.4 38.745 ;
     RECT  225.288 38.475 257.04 38.745 ;
     RECT  2.16 39.015 32.4 39.285 ;
     RECT  225.288 39.015 257.04 39.285 ;
     RECT  2.16 39.555 32.4 39.825 ;
     RECT  225.288 39.555 257.04 39.825 ;
     RECT  2.16 40.095 32.4 40.365 ;
     RECT  225.288 40.095 257.04 40.365 ;
     RECT  2.16 40.635 32.4 40.905 ;
     RECT  225.288 40.635 257.04 40.905 ;
     RECT  2.16 41.175 32.4 41.445 ;
     RECT  225.288 41.175 257.04 41.445 ;
     RECT  2.16 41.715 32.4 41.985 ;
     RECT  225.288 41.715 257.04 41.985 ;
     RECT  2.16 42.255 32.4 42.525 ;
     RECT  225.288 42.255 257.04 42.525 ;
     RECT  2.16 42.795 32.4 43.065 ;
     RECT  225.288 42.795 257.04 43.065 ;
     RECT  2.16 43.335 32.4 43.605 ;
     RECT  225.288 43.335 257.04 43.605 ;
     RECT  2.16 43.875 32.4 44.145 ;
     RECT  225.288 43.875 257.04 44.145 ;
     RECT  2.16 44.415 32.4 44.685 ;
     RECT  225.288 44.415 257.04 44.685 ;
     RECT  2.16 44.955 32.4 45.225 ;
     RECT  225.288 44.955 257.04 45.225 ;
     RECT  2.16 45.495 32.4 45.765 ;
     RECT  225.288 45.495 257.04 45.765 ;
     RECT  2.16 46.035 32.4 46.305 ;
     RECT  225.288 46.035 257.04 46.305 ;
     RECT  2.16 46.575 32.4 46.845 ;
     RECT  225.288 46.575 257.04 46.845 ;
     RECT  2.16 47.115 32.4 47.385 ;
     RECT  225.288 47.115 257.04 47.385 ;
     RECT  2.16 47.655 32.4 47.925 ;
     RECT  225.288 47.655 257.04 47.925 ;
     RECT  2.16 48.195 32.4 48.465 ;
     RECT  225.288 48.195 257.04 48.465 ;
     RECT  2.16 48.735 32.4 49.005 ;
     RECT  225.288 48.735 257.04 49.005 ;
     RECT  2.16 49.275 32.4 49.545 ;
     RECT  225.288 49.275 257.04 49.545 ;
     RECT  2.16 49.815 32.4 50.085 ;
     RECT  225.288 49.815 257.04 50.085 ;
     RECT  2.16 50.355 32.4 50.625 ;
     RECT  225.288 50.355 257.04 50.625 ;
     RECT  2.16 50.895 32.4 51.165 ;
     RECT  225.288 50.895 257.04 51.165 ;
     RECT  2.16 51.435 32.4 51.705 ;
     RECT  225.288 51.435 257.04 51.705 ;
     RECT  2.16 51.975 32.4 52.245 ;
     RECT  225.288 51.975 257.04 52.245 ;
     RECT  2.16 52.515 32.4 52.785 ;
     RECT  225.288 52.515 257.04 52.785 ;
     RECT  2.16 53.055 32.4 53.325 ;
     RECT  225.288 53.055 257.04 53.325 ;
     RECT  2.16 53.595 32.4 53.865 ;
     RECT  225.288 53.595 257.04 53.865 ;
     RECT  2.16 54.135 32.4 54.405 ;
     RECT  225.288 54.135 257.04 54.405 ;
     RECT  2.16 54.675 32.4 54.945 ;
     RECT  225.288 54.675 257.04 54.945 ;
     RECT  2.16 55.215 32.4 55.485 ;
     RECT  225.288 55.215 257.04 55.485 ;
     RECT  2.16 55.755 32.4 56.025 ;
     RECT  225.288 55.755 257.04 56.025 ;
     RECT  2.16 56.295 32.4 56.565 ;
     RECT  225.288 56.295 257.04 56.565 ;
     RECT  2.16 56.835 32.4 57.105 ;
     RECT  225.288 56.835 257.04 57.105 ;
     RECT  2.16 57.375 32.4 57.645 ;
     RECT  225.288 57.375 257.04 57.645 ;
     RECT  2.16 57.915 32.4 58.185 ;
     RECT  225.288 57.915 257.04 58.185 ;
     RECT  2.16 58.455 32.4 58.725 ;
     RECT  225.288 58.455 257.04 58.725 ;
     RECT  2.16 58.995 32.4 59.265 ;
     RECT  225.288 58.995 257.04 59.265 ;
     RECT  2.16 59.535 32.4 59.805 ;
     RECT  225.288 59.535 257.04 59.805 ;
     RECT  2.16 60.075 32.4 60.345 ;
     RECT  225.288 60.075 257.04 60.345 ;
     RECT  2.16 60.615 32.4 60.885 ;
     RECT  225.288 60.615 257.04 60.885 ;
     RECT  2.16 61.155 32.4 61.425 ;
     RECT  225.288 61.155 257.04 61.425 ;
     RECT  2.16 61.695 32.4 61.965 ;
     RECT  225.288 61.695 257.04 61.965 ;
     RECT  2.16 62.235 32.4 62.505 ;
     RECT  225.288 62.235 257.04 62.505 ;
     RECT  2.16 62.775 32.4 63.045 ;
     RECT  225.288 62.775 257.04 63.045 ;
     RECT  2.16 63.315 32.4 63.585 ;
     RECT  225.288 63.315 257.04 63.585 ;
     RECT  2.16 63.855 32.4 64.125 ;
     RECT  225.288 63.855 257.04 64.125 ;
     RECT  2.16 64.395 32.4 64.665 ;
     RECT  225.288 64.395 257.04 64.665 ;
     RECT  2.16 64.935 32.4 65.205 ;
     RECT  225.288 64.935 257.04 65.205 ;
     RECT  2.16 65.475 32.4 65.745 ;
     RECT  225.288 65.475 257.04 65.745 ;
     RECT  2.16 66.015 32.4 66.285 ;
     RECT  225.288 66.015 257.04 66.285 ;
     RECT  2.16 66.555 32.4 66.825 ;
     RECT  225.288 66.555 257.04 66.825 ;
     RECT  2.16 67.095 32.4 67.365 ;
     RECT  225.288 67.095 257.04 67.365 ;
     RECT  2.16 67.635 32.4 67.905 ;
     RECT  225.288 67.635 257.04 67.905 ;
     RECT  2.16 68.175 32.4 68.445 ;
     RECT  225.288 68.175 257.04 68.445 ;
     RECT  2.16 68.715 32.4 68.985 ;
     RECT  225.288 68.715 257.04 68.985 ;
     RECT  2.16 69.255 32.4 69.525 ;
     RECT  225.288 69.255 257.04 69.525 ;
     RECT  2.16 69.795 32.4 70.065 ;
     RECT  225.288 69.795 257.04 70.065 ;
     RECT  2.16 70.335 32.4 70.605 ;
     RECT  225.288 70.335 257.04 70.605 ;
     RECT  2.16 70.875 32.4 71.145 ;
     RECT  225.288 70.875 257.04 71.145 ;
     RECT  2.16 71.415 32.4 71.685 ;
     RECT  225.288 71.415 257.04 71.685 ;
     RECT  2.16 71.955 32.4 72.225 ;
     RECT  225.288 71.955 257.04 72.225 ;
     RECT  2.16 72.495 32.4 72.765 ;
     RECT  225.288 72.495 257.04 72.765 ;
     RECT  2.16 73.035 32.4 73.305 ;
     RECT  225.288 73.035 257.04 73.305 ;
     RECT  2.16 73.575 32.4 73.845 ;
     RECT  225.288 73.575 257.04 73.845 ;
     RECT  2.16 74.115 32.4 74.385 ;
     RECT  225.288 74.115 257.04 74.385 ;
     RECT  2.16 74.655 32.4 74.925 ;
     RECT  225.288 74.655 257.04 74.925 ;
     RECT  2.16 75.195 32.4 75.465 ;
     RECT  225.288 75.195 257.04 75.465 ;
     RECT  2.16 75.735 32.4 76.005 ;
     RECT  225.288 75.735 257.04 76.005 ;
     RECT  2.16 76.275 32.4 76.545 ;
     RECT  225.288 76.275 257.04 76.545 ;
     RECT  2.16 76.815 32.4 77.085 ;
     RECT  225.288 76.815 257.04 77.085 ;
     RECT  2.16 77.355 32.4 77.625 ;
     RECT  225.288 77.355 257.04 77.625 ;
     RECT  2.16 77.895 32.4 78.165 ;
     RECT  225.288 77.895 257.04 78.165 ;
     RECT  2.16 78.435 32.4 78.705 ;
     RECT  225.288 78.435 257.04 78.705 ;
     RECT  2.16 78.975 32.4 79.245 ;
     RECT  225.288 78.975 257.04 79.245 ;
     RECT  2.16 79.515 32.4 79.785 ;
     RECT  225.288 79.515 257.04 79.785 ;
     RECT  2.16 80.055 32.4 80.325 ;
     RECT  225.288 80.055 257.04 80.325 ;
     RECT  2.16 80.595 32.4 80.865 ;
     RECT  225.288 80.595 257.04 80.865 ;
     RECT  2.16 81.135 32.4 81.405 ;
     RECT  225.288 81.135 257.04 81.405 ;
     RECT  2.16 81.675 32.4 81.945 ;
     RECT  225.288 81.675 257.04 81.945 ;
     RECT  2.16 82.215 32.4 82.485 ;
     RECT  225.288 82.215 257.04 82.485 ;
     RECT  2.16 82.755 32.4 83.025 ;
     RECT  225.288 82.755 257.04 83.025 ;
     RECT  2.16 83.295 32.4 83.565 ;
     RECT  225.288 83.295 257.04 83.565 ;
     RECT  2.16 83.835 32.4 84.105 ;
     RECT  225.288 83.835 257.04 84.105 ;
     RECT  2.16 84.375 32.4 84.645 ;
     RECT  225.288 84.375 257.04 84.645 ;
     RECT  2.16 84.915 32.4 85.185 ;
     RECT  225.288 84.915 257.04 85.185 ;
     RECT  2.16 85.455 32.4 85.725 ;
     RECT  225.288 85.455 257.04 85.725 ;
     RECT  2.16 85.995 32.4 86.265 ;
     RECT  225.288 85.995 257.04 86.265 ;
     RECT  2.16 86.535 32.4 86.805 ;
     RECT  225.288 86.535 257.04 86.805 ;
     RECT  2.16 87.075 32.4 87.345 ;
     RECT  225.288 87.075 257.04 87.345 ;
     RECT  2.16 87.615 32.4 87.885 ;
     RECT  225.288 87.615 257.04 87.885 ;
     RECT  2.16 88.155 32.4 88.425 ;
     RECT  225.288 88.155 257.04 88.425 ;
     RECT  2.16 88.695 32.4 88.965 ;
     RECT  225.288 88.695 257.04 88.965 ;
     RECT  2.16 89.235 32.4 89.505 ;
     RECT  225.288 89.235 257.04 89.505 ;
     RECT  2.16 89.775 32.4 90.045 ;
     RECT  225.288 89.775 257.04 90.045 ;
     RECT  2.16 90.315 32.4 90.585 ;
     RECT  225.288 90.315 257.04 90.585 ;
     RECT  2.16 90.855 32.4 91.125 ;
     RECT  225.288 90.855 257.04 91.125 ;
     RECT  2.16 91.395 32.4 91.665 ;
     RECT  225.288 91.395 257.04 91.665 ;
     RECT  2.16 91.935 32.4 92.205 ;
     RECT  225.288 91.935 257.04 92.205 ;
     RECT  2.16 92.475 32.4 92.745 ;
     RECT  225.288 92.475 257.04 92.745 ;
     RECT  2.16 93.015 32.4 93.285 ;
     RECT  225.288 93.015 257.04 93.285 ;
     RECT  2.16 93.555 32.4 93.825 ;
     RECT  225.288 93.555 257.04 93.825 ;
     RECT  2.16 94.095 32.4 94.365 ;
     RECT  225.288 94.095 257.04 94.365 ;
     RECT  2.16 94.635 32.4 94.905 ;
     RECT  225.288 94.635 257.04 94.905 ;
     RECT  2.16 95.175 32.4 95.445 ;
     RECT  225.288 95.175 257.04 95.445 ;
     RECT  2.16 95.715 32.4 95.985 ;
     RECT  225.288 95.715 257.04 95.985 ;
     RECT  2.16 96.255 32.4 96.525 ;
     RECT  225.288 96.255 257.04 96.525 ;
     RECT  2.16 96.795 32.4 97.065 ;
     RECT  225.288 96.795 257.04 97.065 ;
     RECT  2.16 97.335 32.4 97.605 ;
     RECT  225.288 97.335 257.04 97.605 ;
     RECT  2.16 97.875 32.4 98.145 ;
     RECT  225.288 97.875 257.04 98.145 ;
     RECT  2.16 98.415 32.4 98.685 ;
     RECT  225.288 98.415 257.04 98.685 ;
     RECT  2.16 98.955 32.4 99.225 ;
     RECT  225.288 98.955 257.04 99.225 ;
     RECT  2.16 99.495 32.4 99.765 ;
     RECT  225.288 99.495 257.04 99.765 ;
     RECT  2.16 100.035 32.4 100.305 ;
     RECT  225.288 100.035 257.04 100.305 ;
     RECT  2.16 100.575 32.4 100.845 ;
     RECT  225.288 100.575 257.04 100.845 ;
     RECT  2.16 101.115 32.4 101.385 ;
     RECT  225.288 101.115 257.04 101.385 ;
     RECT  2.16 101.655 32.4 101.925 ;
     RECT  225.288 101.655 257.04 101.925 ;
     RECT  2.16 102.195 32.4 102.465 ;
     RECT  225.288 102.195 257.04 102.465 ;
     RECT  2.16 102.735 32.4 103.005 ;
     RECT  225.288 102.735 257.04 103.005 ;
     RECT  2.16 103.275 32.4 103.545 ;
     RECT  225.288 103.275 257.04 103.545 ;
     RECT  2.16 103.815 32.4 104.085 ;
     RECT  225.288 103.815 257.04 104.085 ;
     RECT  2.16 104.355 32.4 104.625 ;
     RECT  225.288 104.355 257.04 104.625 ;
     RECT  2.16 104.895 32.4 105.165 ;
     RECT  225.288 104.895 257.04 105.165 ;
     RECT  2.16 105.435 32.4 105.705 ;
     RECT  225.288 105.435 257.04 105.705 ;
     RECT  2.16 105.975 32.4 106.245 ;
     RECT  225.288 105.975 257.04 106.245 ;
     RECT  2.16 106.515 32.4 106.785 ;
     RECT  225.288 106.515 257.04 106.785 ;
     RECT  2.16 107.055 32.4 107.325 ;
     RECT  225.288 107.055 257.04 107.325 ;
     RECT  2.16 107.595 32.4 107.865 ;
     RECT  225.288 107.595 257.04 107.865 ;
     RECT  2.16 108.135 32.4 108.405 ;
     RECT  225.288 108.135 257.04 108.405 ;
     RECT  2.16 108.675 32.4 108.945 ;
     RECT  225.288 108.675 257.04 108.945 ;
     RECT  2.16 109.215 32.4 109.485 ;
     RECT  225.288 109.215 257.04 109.485 ;
     RECT  2.16 109.755 32.4 110.025 ;
     RECT  225.288 109.755 257.04 110.025 ;
     RECT  2.16 110.295 32.4 110.565 ;
     RECT  225.288 110.295 257.04 110.565 ;
     RECT  2.16 110.835 32.4 111.105 ;
     RECT  225.288 110.835 257.04 111.105 ;
     RECT  2.16 111.375 32.4 111.645 ;
     RECT  225.288 111.375 257.04 111.645 ;
     RECT  2.16 111.915 32.4 112.185 ;
     RECT  225.288 111.915 257.04 112.185 ;
     RECT  2.16 112.455 32.4 112.725 ;
     RECT  225.288 112.455 257.04 112.725 ;
     RECT  2.16 112.995 32.4 113.265 ;
     RECT  225.288 112.995 257.04 113.265 ;
     RECT  2.16 113.535 32.4 113.805 ;
     RECT  225.288 113.535 257.04 113.805 ;
     RECT  2.16 114.075 32.4 114.345 ;
     RECT  225.288 114.075 257.04 114.345 ;
     RECT  2.16 114.615 32.4 114.885 ;
     RECT  225.288 114.615 257.04 114.885 ;
     RECT  2.16 115.155 32.4 115.425 ;
     RECT  225.288 115.155 257.04 115.425 ;
     RECT  2.16 115.695 32.4 115.965 ;
     RECT  225.288 115.695 257.04 115.965 ;
     RECT  2.16 116.235 32.4 116.505 ;
     RECT  225.288 116.235 257.04 116.505 ;
     RECT  2.16 116.775 32.4 117.045 ;
     RECT  225.288 116.775 257.04 117.045 ;
     RECT  2.16 117.315 32.4 117.585 ;
     RECT  225.288 117.315 257.04 117.585 ;
     RECT  2.16 117.855 32.4 118.125 ;
     RECT  225.288 117.855 257.04 118.125 ;
     RECT  2.16 118.395 32.4 118.665 ;
     RECT  225.288 118.395 257.04 118.665 ;
     RECT  2.16 118.935 32.4 119.205 ;
     RECT  225.288 118.935 257.04 119.205 ;
     RECT  2.16 119.475 32.4 119.745 ;
     RECT  225.288 119.475 257.04 119.745 ;
     RECT  2.16 120.015 32.4 120.285 ;
     RECT  225.288 120.015 257.04 120.285 ;
     RECT  2.16 120.555 32.4 120.825 ;
     RECT  225.288 120.555 257.04 120.825 ;
     RECT  2.16 121.095 32.4 121.365 ;
     RECT  225.288 121.095 257.04 121.365 ;
     RECT  2.16 121.635 32.4 121.905 ;
     RECT  225.288 121.635 257.04 121.905 ;
     RECT  2.16 122.175 32.4 122.445 ;
     RECT  225.288 122.175 257.04 122.445 ;
     RECT  2.16 122.715 32.4 122.985 ;
     RECT  225.288 122.715 257.04 122.985 ;
     RECT  2.16 123.255 32.4 123.525 ;
     RECT  225.288 123.255 257.04 123.525 ;
     RECT  2.16 123.795 32.4 124.065 ;
     RECT  225.288 123.795 257.04 124.065 ;
     RECT  2.16 124.335 32.4 124.605 ;
     RECT  225.288 124.335 257.04 124.605 ;
     RECT  2.16 124.875 32.4 125.145 ;
     RECT  225.288 124.875 257.04 125.145 ;
     RECT  2.16 125.415 32.4 125.685 ;
     RECT  225.288 125.415 257.04 125.685 ;
     RECT  2.16 125.955 32.4 126.225 ;
     RECT  225.288 125.955 257.04 126.225 ;
     RECT  2.16 126.495 32.4 126.765 ;
     RECT  225.288 126.495 257.04 126.765 ;
     RECT  2.16 127.035 32.4 127.305 ;
     RECT  225.288 127.035 257.04 127.305 ;
     RECT  2.16 127.575 32.4 127.845 ;
     RECT  225.288 127.575 257.04 127.845 ;
     RECT  2.16 128.115 32.4 128.385 ;
     RECT  225.288 128.115 257.04 128.385 ;
     RECT  2.16 128.655 32.4 128.925 ;
     RECT  225.288 128.655 257.04 128.925 ;
     RECT  2.16 129.195 32.4 129.465 ;
     RECT  225.288 129.195 257.04 129.465 ;
     RECT  2.16 129.735 32.4 130.005 ;
     RECT  225.288 129.735 257.04 130.005 ;
     RECT  2.16 130.275 32.4 130.545 ;
     RECT  225.288 130.275 257.04 130.545 ;
     RECT  2.16 130.815 32.4 131.085 ;
     RECT  225.288 130.815 257.04 131.085 ;
     RECT  2.16 131.355 32.4 131.625 ;
     RECT  225.288 131.355 257.04 131.625 ;
     RECT  2.16 131.895 32.4 132.03 ;
     RECT  225.288 131.895 257.04 132.03 ;
     RECT  2.16 132.03 257.04 132.165 ;
     RECT  2.16 132.435 257.04 132.705 ;
     RECT  2.16 132.975 257.04 133.245 ;
     RECT  2.16 133.515 257.04 133.785 ;
     RECT  2.16 134.055 257.04 134.325 ;
     RECT  2.16 134.595 257.04 134.865 ;
     RECT  2.16 135.135 257.04 135.405 ;
     RECT  2.16 135.675 257.04 135.945 ;
     RECT  2.16 136.215 257.04 136.485 ;
     RECT  2.16 136.755 257.04 137.025 ;
     RECT  2.16 137.295 257.04 137.565 ;
     RECT  2.16 137.835 257.04 138.105 ;
     RECT  2.16 138.375 257.04 138.645 ;
     RECT  2.16 138.915 257.04 139.185 ;
     RECT  2.16 139.455 257.04 139.725 ;
     RECT  2.16 139.995 257.04 140.265 ;
     RECT  2.16 140.535 257.04 140.805 ;
     RECT  2.16 141.075 257.04 141.345 ;
     RECT  2.16 141.615 257.04 141.885 ;
     RECT  2.16 142.155 257.04 142.425 ;
     RECT  2.16 142.695 257.04 142.965 ;
     RECT  2.16 143.235 257.04 143.505 ;
     RECT  2.16 143.775 257.04 144.045 ;
     RECT  2.16 144.315 257.04 144.585 ;
     RECT  2.16 144.855 257.04 145.125 ;
     RECT  2.16 145.395 257.04 145.665 ;
     RECT  2.16 145.935 257.04 146.205 ;
     RECT  2.16 146.475 257.04 146.745 ;
     RECT  2.16 147.015 257.04 147.285 ;
     RECT  2.16 147.555 257.04 147.825 ;
     RECT  2.16 148.095 257.04 148.365 ;
     RECT  2.16 148.635 257.04 148.905 ;
     RECT  2.16 149.175 257.04 149.445 ;
     RECT  2.16 149.715 257.04 149.985 ;
     RECT  2.16 150.255 257.04 150.525 ;
     RECT  2.16 150.795 257.04 151.065 ;
     RECT  2.16 151.335 257.04 151.605 ;
     RECT  2.16 151.875 257.04 152.145 ;
     RECT  2.16 152.415 257.04 152.685 ;
     RECT  2.16 152.955 257.04 153.225 ;
     RECT  2.16 153.495 257.04 153.765 ;
     RECT  2.16 154.035 257.04 154.305 ;
     RECT  2.16 154.575 257.04 154.845 ;
     RECT  2.16 155.115 257.04 155.385 ;
     RECT  2.16 155.655 257.04 155.925 ;
     RECT  2.16 156.195 257.04 156.465 ;
     RECT  2.16 156.735 257.04 157.005 ;
     RECT  2.16 157.275 257.04 157.545 ;
     RECT  2.16 157.815 257.04 158.085 ;
     RECT  2.16 158.355 257.04 158.625 ;
     RECT  2.16 158.895 257.04 159.165 ;
     RECT  2.16 159.435 257.04 159.705 ;
     RECT  2.16 159.975 257.04 160.245 ;
     RECT  2.16 160.515 257.04 160.785 ;
     RECT  2.16 161.055 257.04 161.325 ;
     RECT  2.16 161.595 257.04 161.865 ;
     RECT  2.16 162.135 257.04 162.405 ;
     RECT  2.16 162.675 257.04 162.945 ;
     RECT  2.16 163.215 257.04 163.485 ;
     RECT  2.16 163.755 257.04 164.025 ;
     RECT  2.16 164.295 257.04 164.565 ;
     RECT  2.16 164.835 257.04 165.105 ;
     RECT  2.16 165.375 257.04 165.645 ;
     RECT  2.16 165.915 257.04 166.185 ;
     RECT  2.16 166.455 257.04 166.725 ;
     RECT  2.16 166.995 257.04 167.265 ;
     RECT  2.16 167.535 257.04 167.805 ;
     RECT  2.16 168.075 257.04 168.345 ;
     RECT  2.16 168.615 257.04 168.885 ;
     RECT  2.16 169.155 257.04 169.425 ;
     RECT  2.16 169.695 257.04 169.965 ;
     RECT  2.16 170.235 257.04 170.505 ;
     RECT  2.16 170.775 257.04 171.045 ;
     RECT  2.16 171.315 257.04 171.585 ;
     RECT  2.16 171.855 257.04 172.125 ;
     RECT  2.16 172.395 257.04 172.665 ;
     RECT  2.16 172.935 257.04 173.205 ;
     RECT  2.16 173.475 257.04 173.745 ;
     RECT  2.16 174.015 257.04 174.285 ;
     RECT  2.16 174.555 257.04 174.825 ;
     RECT  2.16 175.095 257.04 175.365 ;
     RECT  2.16 175.635 257.04 175.905 ;
     RECT  2.16 176.175 257.04 176.445 ;
     RECT  2.16 176.715 257.04 176.985 ;
     RECT  2.16 177.255 257.04 177.525 ;
     RECT  2.16 177.795 257.04 178.065 ;
     RECT  2.16 178.335 257.04 178.605 ;
     RECT  2.16 178.875 257.04 179.145 ;
     RECT  2.16 179.415 257.04 179.685 ;
     RECT  2.16 179.955 257.04 180.225 ;
     RECT  2.16 180.495 257.04 180.765 ;
     RECT  2.16 181.035 257.04 181.305 ;
     RECT  2.16 181.575 257.04 181.845 ;
     RECT  2.16 182.115 257.04 182.385 ;
     RECT  2.16 182.655 257.04 182.925 ;
     RECT  2.16 183.195 257.04 183.465 ;
     RECT  2.16 183.735 257.04 184.005 ;
     RECT  2.16 184.275 257.04 184.545 ;
     RECT  2.16 184.815 257.04 185.085 ;
     RECT  2.16 185.355 257.04 185.625 ;
     RECT  2.16 185.895 257.04 186.165 ;
     RECT  2.16 186.435 257.04 186.705 ;
     RECT  2.16 186.975 257.04 187.245 ;
     RECT  2.16 187.515 257.04 187.785 ;
     RECT  2.16 188.055 257.04 188.325 ;
     RECT  2.16 188.595 257.04 188.865 ;
     RECT  2.16 189.135 257.04 189.405 ;
     RECT  2.16 189.675 257.04 189.945 ;
     RECT  2.16 190.215 257.04 190.485 ;
     RECT  2.16 190.755 257.04 191.025 ;
     RECT  2.16 191.295 257.04 191.565 ;
     RECT  2.16 191.835 257.04 192.105 ;
     RECT  2.16 192.375 257.04 192.645 ;
     RECT  2.16 192.915 257.04 193.185 ;
     RECT  2.16 193.455 257.04 193.725 ;
     RECT  2.16 193.995 257.04 194.265 ;
     RECT  2.16 194.535 257.04 194.805 ;
     RECT  2.16 195.075 257.04 195.345 ;
     RECT  2.16 195.615 257.04 195.885 ;
     RECT  2.16 196.155 257.04 196.425 ;
     RECT  2.16 196.695 257.04 196.965 ;
     RECT  2.16 197.235 257.04 197.505 ;
     RECT  2.16 197.775 257.04 198.045 ;
     RECT  2.16 198.315 257.04 198.585 ;
     RECT  2.16 198.855 257.04 199.125 ;
     RECT  2.16 199.395 257.04 199.665 ;
     RECT  2.16 199.935 257.04 200.205 ;
     RECT  2.16 200.475 257.04 200.745 ;
     RECT  2.16 201.015 257.04 201.285 ;
     RECT  2.16 201.555 257.04 201.825 ;
     RECT  2.16 202.095 257.04 202.365 ;
     RECT  2.16 202.635 257.04 202.905 ;
     RECT  2.16 203.175 257.04 203.445 ;
     RECT  2.16 203.715 257.04 203.985 ;
     RECT  2.16 204.255 257.04 204.525 ;
     RECT  2.16 204.795 257.04 205.065 ;
     RECT  2.16 205.335 257.04 205.605 ;
     RECT  2.16 205.875 257.04 206.145 ;
     RECT  2.16 206.415 257.04 206.685 ;
     RECT  2.16 206.955 257.04 207.225 ;
     RECT  2.16 207.495 257.04 207.765 ;
     RECT  2.16 208.035 257.04 208.305 ;
     RECT  2.16 208.575 257.04 208.845 ;
     RECT  2.16 209.115 257.04 209.385 ;
     RECT  2.16 209.655 257.04 209.925 ;
     RECT  2.16 210.195 257.04 210.465 ;
     RECT  2.16 210.735 257.04 211.005 ;
     RECT  2.16 211.275 257.04 211.545 ;
     RECT  2.16 211.815 257.04 212.085 ;
     RECT  2.16 212.355 257.04 212.625 ;
     RECT  2.16 212.895 257.04 213.165 ;
     RECT  2.16 213.435 257.04 213.705 ;
    LAYER M1 ;
     RECT  2.16 2.151 257.04 32.409 ;
     RECT  43.2 43.2 214.488 120.984 ;
     RECT  2.16 32.409 32.4 132.021 ;
     RECT  225.288 32.409 257.04 132.021 ;
     RECT  2.16 132.021 257.04 213.849 ;
    LAYER M2 ;
     RECT  0.103 20.322 0.535 20.88 ;
     RECT  0.103 21.672 0.535 21.69 ;
     RECT  0.103 33.012 0.535 35.838 ;
     RECT  0.103 36.792 0.535 37.35 ;
     RECT  0.103 39.762 0.535 39.78 ;
     RECT  0.103 40.572 0.535 41.508 ;
     RECT  0.103 42.462 0.535 43.56 ;
     RECT  0.103 47.862 0.535 49.23 ;
     RECT  0.103 50.022 0.535 51.12 ;
     RECT  0.103 58.122 0.535 60.57 ;
     RECT  0.103 61.362 0.535 63 ;
     RECT  0.103 63.792 0.535 64.35 ;
     RECT  0.103 65.142 0.535 65.7 ;
     RECT  0.103 93.906 0.535 94.284 ;
     RECT  0.103 106.866 0.535 106.884 ;
     RECT  0.103 108.684 0.535 108.702 ;
     RECT  0.103 117.63 0.535 118.314 ;
     RECT  0.103 122.526 0.535 122.544 ;
     RECT  0.103 123.534 0.535 125.604 ;
     RECT  0.103 126.936 0.535 126.954 ;
     RECT  0.103 128.016 0.535 128.034 ;
     RECT  0.103 145.026 0.535 145.044 ;
     RECT  0.103 155.466 0.535 155.484 ;
     RECT  0.103 156.546 0.535 156.564 ;
     RECT  0.103 158.436 0.535 158.454 ;
     RECT  0.103 163.566 0.535 164.322 ;
     RECT  0.103 168.048 0.535 168.066 ;
     RECT  0.103 170.316 0.535 170.334 ;
     RECT  0.103 32.202 1.723 32.22 ;
     RECT  0.535 33.012 1.723 37.35 ;
     RECT  0.103 38.142 1.723 38.7 ;
     RECT  0.535 58.122 1.723 63 ;
     RECT  0.535 63.792 1.723 65.7 ;
     RECT  0.103 78.372 1.723 79.47 ;
     RECT  0.103 80.262 1.723 80.82 ;
     RECT  0.535 130.446 1.723 130.464 ;
     RECT  0.535 134.406 1.723 134.424 ;
     RECT  0.103 135.306 1.723 135.324 ;
     RECT  0.103 145.836 1.723 145.854 ;
     RECT  0.103 189.99 1.723 190.008 ;
     RECT  0.103 8.442 2.16 8.46 ;
     RECT  0.103 16.38 2.16 17.37 ;
     RECT  0.103 18.162 2.16 18.45 ;
     RECT  0.535 20.322 2.16 21.69 ;
     RECT  0.103 22.752 2.16 27.36 ;
     RECT  0.103 28.422 2.16 29.79 ;
     RECT  0.535 30.582 2.16 30.6 ;
     RECT  1.723 32.202 2.16 38.7 ;
     RECT  0.535 39.762 2.16 43.56 ;
     RECT  0.103 44.352 2.16 46.26 ;
     RECT  0.535 47.862 2.16 51.39 ;
     RECT  0.103 52.182 2.16 52.2 ;
     RECT  0.103 52.992 2.16 55.17 ;
     RECT  0.103 56.232 2.16 57.33 ;
     RECT  1.723 58.122 2.16 65.7 ;
     RECT  0.103 67.572 2.16 69.48 ;
     RECT  0.103 70.542 2.16 71.37 ;
     RECT  0.103 73.242 2.16 77.04 ;
     RECT  1.723 78.372 2.16 80.82 ;
     RECT  1.723 91.746 2.16 91.764 ;
     RECT  0.103 92.556 2.16 92.574 ;
     RECT  0.535 93.366 2.16 94.824 ;
     RECT  0.103 95.616 2.16 96.174 ;
     RECT  0.103 98.586 2.16 98.604 ;
     RECT  0.535 101.196 2.16 101.214 ;
     RECT  0.535 102.006 2.16 102.564 ;
     RECT  0.535 104.166 2.16 104.184 ;
     RECT  0.535 105.246 2.16 107.424 ;
     RECT  0.535 108.216 2.16 108.702 ;
     RECT  0.535 109.998 2.16 110.016 ;
     RECT  0.103 111.078 2.16 111.096 ;
     RECT  0.535 113.346 2.16 114.444 ;
     RECT  1.723 116.676 2.16 116.694 ;
     RECT  0.535 117.63 2.16 119.034 ;
     RECT  0.103 120.186 2.16 121.662 ;
     RECT  0.535 122.526 2.16 128.682 ;
     RECT  1.723 130.446 2.16 132.624 ;
     RECT  0.103 133.524 2.16 133.542 ;
     RECT  1.723 134.406 2.16 134.514 ;
     RECT  1.723 135.306 2.16 135.594 ;
     RECT  0.103 136.386 2.16 136.404 ;
     RECT  0.103 137.466 2.16 138.024 ;
     RECT  0.103 139.356 2.16 139.374 ;
     RECT  0.535 140.544 2.16 140.562 ;
     RECT  0.535 141.624 2.16 141.642 ;
     RECT  0.535 144.486 2.16 145.044 ;
     RECT  1.723 145.836 2.16 146.934 ;
     RECT  0.103 148.266 2.16 148.824 ;
     RECT  0.103 150.264 2.16 150.822 ;
     RECT  0.535 151.578 2.16 152.676 ;
     RECT  0.535 154.116 2.16 154.134 ;
     RECT  0.535 155.466 2.16 158.454 ;
     RECT  0.103 159.516 2.16 159.534 ;
     RECT  0.535 161.838 2.16 161.856 ;
     RECT  0.535 163.566 2.16 164.934 ;
     RECT  0.535 166.806 2.16 168.444 ;
     RECT  0.535 169.236 2.16 170.334 ;
     RECT  0.103 171.936 2.16 171.954 ;
     RECT  0.103 178.65 2.16 178.668 ;
     RECT  0.103 179.46 2.16 179.478 ;
     RECT  0.103 180.432 2.16 180.45 ;
     RECT  1.723 181.242 2.16 181.26 ;
     RECT  0.103 182.322 2.16 182.34 ;
     RECT  0.103 183.132 2.16 183.15 ;
     RECT  1.723 189.18 2.16 190.008 ;
     RECT  0.139 191.07 2.16 191.088 ;
     RECT  0.571 192.042 2.16 192.06 ;
     RECT  0.823 195.39 2.16 195.408 ;
     RECT  2.16 2.151 32.4 213.849 ;
     RECT  32.4 65.25 32.495 65.268 ;
     RECT  32.4 107.262 32.783 114.03 ;
     RECT  32.4 2.151 34.699 32.409 ;
     RECT  34.699 2.151 35.015 32.49 ;
     RECT  32.4 118.836 39.371 120.51 ;
     RECT  32.4 100.008 39.623 100.602 ;
     RECT  39.371 118.836 39.947 119.574 ;
     RECT  32.4 41.922 39.983 56.754 ;
     RECT  39.983 44.622 40.019 56.754 ;
     RECT  35.015 2.151 40.099 32.409 ;
     RECT  39.983 41.922 40.199 43.794 ;
     RECT  40.099 2.151 40.415 32.49 ;
     RECT  40.019 44.856 40.451 56.754 ;
     RECT  39.371 120.492 40.451 120.51 ;
     RECT  32.4 97.542 40.739 98.064 ;
     RECT  40.451 44.856 41.027 56.52 ;
     RECT  32.4 103.518 41.315 104.346 ;
     RECT  32.783 107.37 41.315 114.03 ;
     RECT  32.4 94.608 41.351 96.552 ;
     RECT  40.739 98.046 41.351 98.064 ;
     RECT  41.351 94.608 41.387 95.472 ;
     RECT  41.387 95.148 41.459 95.472 ;
     RECT  41.315 110.376 41.495 114.03 ;
     RECT  41.027 46.476 41.603 56.52 ;
     RECT  41.027 44.856 41.639 45.72 ;
     RECT  41.603 46.476 41.639 56.214 ;
     RECT  41.495 110.646 41.639 114.03 ;
     RECT  41.639 51.408 41.675 51.426 ;
     RECT  41.639 47.862 41.711 48.114 ;
     RECT  41.639 50.526 41.711 50.544 ;
     RECT  40.199 42.462 41.891 43.794 ;
     RECT  32.4 105.174 41.891 105.192 ;
     RECT  32.4 101.736 41.927 102.726 ;
     RECT  41.315 103.518 41.927 103.536 ;
     RECT  41.891 42.696 41.963 43.794 ;
     RECT  32.4 90.9 41.963 90.918 ;
     RECT  41.351 96.228 41.963 96.552 ;
     RECT  41.315 104.328 41.999 104.346 ;
     RECT  39.623 100.584 42.035 100.602 ;
     RECT  41.315 107.37 42.107 109.584 ;
     RECT  41.639 55.116 42.143 56.214 ;
     RECT  41.639 110.736 42.143 114.03 ;
     RECT  41.711 47.862 42.179 47.88 ;
     RECT  41.639 52.182 42.179 52.974 ;
     RECT  41.639 53.766 42.179 54.279 ;
     RECT  42.143 55.116 42.179 56.124 ;
     RECT  42.107 107.568 42.179 109.584 ;
     RECT  42.143 110.736 42.179 113.832 ;
     RECT  41.639 44.856 42.215 45.414 ;
     RECT  41.639 48.942 42.215 48.96 ;
     RECT  42.179 55.116 42.215 55.134 ;
     RECT  42.179 113.274 42.215 113.832 ;
     RECT  42.215 44.892 42.251 44.982 ;
     RECT  42.179 110.736 42.251 112.518 ;
     RECT  42.215 113.31 42.251 113.832 ;
     RECT  42.251 44.964 42.287 44.982 ;
     RECT  42.251 113.31 42.287 113.76 ;
     RECT  41.963 43.002 42.359 43.794 ;
     RECT  42.359 43.002 42.395 43.596 ;
     RECT  42.395 43.002 42.431 43.02 ;
     RECT  42.367 58.536 42.467 58.554 ;
     RECT  42.287 113.346 42.467 113.76 ;
     RECT  42.251 110.736 43.051 112.212 ;
     RECT  42.467 113.346 43.051 113.724 ;
     RECT  42.179 52.956 43.2 52.974 ;
     RECT  41.459 95.454 43.2 95.472 ;
     RECT  41.963 96.228 43.2 96.246 ;
     RECT  41.927 101.736 43.2 101.916 ;
     RECT  41.927 102.708 43.2 102.726 ;
     RECT  42.403 104.904 43.2 104.922 ;
     RECT  32.4 106.452 43.2 106.506 ;
     RECT  42.179 107.604 43.2 109.584 ;
     RECT  43.051 110.736 43.2 113.724 ;
     RECT  39.947 118.836 43.2 118.854 ;
     RECT  40.415 2.151 45.499 32.409 ;
     RECT  45.499 2.151 45.815 32.49 ;
     RECT  45.815 2.151 50.899 32.409 ;
     RECT  50.899 2.151 51.215 32.49 ;
     RECT  51.215 2.151 56.299 32.409 ;
     RECT  56.299 2.151 56.615 32.49 ;
     RECT  56.615 2.151 61.699 32.409 ;
     RECT  61.699 2.151 62.015 32.49 ;
     RECT  62.015 2.151 214.339 32.409 ;
     RECT  32.4 132.021 214.339 213.849 ;
     RECT  43.2 43.2 214.488 120.984 ;
     RECT  214.339 2.151 214.871 32.454 ;
     RECT  214.339 131.976 214.871 213.849 ;
     RECT  221.071 43.038 221.143 43.056 ;
     RECT  221.143 43.002 222.295 43.056 ;
     RECT  218.839 49.482 222.295 49.5 ;
     RECT  222.295 74.322 222.331 78.12 ;
     RECT  222.295 78.876 222.331 78.894 ;
     RECT  222.295 43.002 222.395 43.164 ;
     RECT  222.295 79.722 222.799 86.49 ;
     RECT  222.295 103.176 222.799 113.76 ;
     RECT  222.259 47.826 222.835 47.844 ;
     RECT  222.295 51.336 222.835 72.954 ;
     RECT  222.331 74.322 222.835 78.894 ;
     RECT  222.799 79.722 222.835 86.724 ;
     RECT  222.295 87.552 222.835 102.42 ;
     RECT  222.799 103.176 222.835 113.832 ;
     RECT  222.295 115.362 223.411 115.614 ;
     RECT  222.835 74.322 223.447 113.904 ;
     RECT  223.411 115.128 223.447 115.614 ;
     RECT  223.447 115.128 223.483 117 ;
     RECT  222.295 49.482 223.987 50.04 ;
     RECT  222.871 46.242 224.023 46.26 ;
     RECT  223.987 48.78 224.023 50.04 ;
     RECT  224.023 119.682 224.059 119.7 ;
     RECT  224.023 118.062 224.131 118.926 ;
     RECT  224.059 119.682 224.131 120.078 ;
     RECT  222.395 43.074 224.419 43.164 ;
     RECT  224.419 43.074 224.455 43.326 ;
     RECT  224.455 43.074 224.491 43.866 ;
     RECT  224.023 44.766 224.491 44.784 ;
     RECT  224.023 45.846 224.599 46.26 ;
     RECT  222.835 47.826 224.599 47.88 ;
     RECT  224.023 48.78 224.599 50.58 ;
     RECT  223.447 74.322 224.599 113.994 ;
     RECT  223.483 115.128 224.599 117.234 ;
     RECT  224.131 118.062 224.599 120.078 ;
     RECT  224.599 45.846 225.031 50.58 ;
     RECT  225.031 45.774 225.139 50.58 ;
     RECT  222.835 51.336 225.139 73.404 ;
     RECT  224.599 74.322 225.139 120.078 ;
     RECT  220.603 120.996 225.139 121.014 ;
     RECT  225.139 45.774 225.175 120.078 ;
     RECT  214.871 2.151 225.288 32.409 ;
     RECT  219.127 42.156 225.288 42.174 ;
     RECT  224.491 43.074 225.288 44.784 ;
     RECT  225.175 45.774 225.288 120.24 ;
     RECT  225.139 120.996 225.288 121.554 ;
     RECT  214.871 132.021 225.288 213.849 ;
     RECT  225.288 2.151 257.04 213.849 ;
    LAYER M3 ;
     RECT  2.415 2.143 2.505 2.413 ;
     RECT  7.815 2.143 7.905 2.413 ;
     RECT  13.215 2.143 13.305 2.413 ;
     RECT  18.615 2.143 18.705 2.413 ;
     RECT  24.015 2.143 24.105 2.413 ;
     RECT  29.415 2.143 29.505 2.413 ;
     RECT  34.815 2.143 34.905 2.413 ;
     RECT  40.215 2.143 40.305 2.413 ;
     RECT  45.615 2.143 45.705 2.413 ;
     RECT  51.015 2.143 51.105 2.413 ;
     RECT  56.415 2.143 56.505 2.413 ;
     RECT  61.815 2.143 61.905 2.413 ;
     RECT  67.215 2.143 67.305 2.413 ;
     RECT  72.615 2.143 72.705 2.413 ;
     RECT  78.015 2.143 78.105 2.413 ;
     RECT  83.415 2.143 83.505 2.413 ;
     RECT  88.815 2.143 88.905 2.413 ;
     RECT  94.215 2.143 94.305 2.413 ;
     RECT  99.615 2.143 99.705 2.413 ;
     RECT  105.015 2.143 105.105 2.413 ;
     RECT  110.415 2.143 110.505 2.413 ;
     RECT  115.815 2.143 115.905 2.413 ;
     RECT  121.215 2.143 121.305 2.413 ;
     RECT  126.615 2.143 126.705 2.413 ;
     RECT  132.015 2.143 132.105 2.413 ;
     RECT  137.415 2.143 137.505 2.413 ;
     RECT  142.815 2.143 142.905 2.413 ;
     RECT  148.215 2.143 148.305 2.413 ;
     RECT  153.615 2.143 153.705 2.413 ;
     RECT  159.015 2.143 159.105 2.413 ;
     RECT  164.415 2.143 164.505 2.413 ;
     RECT  169.815 2.143 169.905 2.413 ;
     RECT  175.215 2.143 175.305 2.413 ;
     RECT  180.615 2.143 180.705 2.413 ;
     RECT  186.015 2.143 186.105 2.413 ;
     RECT  191.415 2.143 191.505 2.413 ;
     RECT  196.815 2.143 196.905 2.413 ;
     RECT  202.215 2.143 202.305 2.413 ;
     RECT  207.615 2.143 207.705 2.413 ;
     RECT  213.015 2.143 213.105 2.413 ;
     RECT  218.415 2.143 218.505 2.413 ;
     RECT  223.815 2.143 223.905 2.413 ;
     RECT  229.215 2.143 229.305 2.413 ;
     RECT  234.615 2.143 234.705 2.413 ;
     RECT  240.015 2.143 240.105 2.413 ;
     RECT  245.415 2.143 245.505 2.413 ;
     RECT  250.815 2.143 250.905 2.413 ;
     RECT  256.215 2.143 256.305 2.413 ;
     RECT  4.032 8.401 4.05 8.437 ;
     RECT  0.108 8.107 0.126 8.465 ;
     RECT  4.032 8.437 4.59 8.509 ;
     RECT  4.032 8.509 4.734 8.699 ;
     RECT  4.032 8.699 4.302 8.735 ;
     RECT  4.284 8.735 4.302 8.771 ;
     RECT  5.508 8.581 5.526 12.245 ;
     RECT  5.652 16.375 5.67 16.411 ;
     RECT  7.815 2.413 8.097 16.411 ;
     RECT  3.96 16.411 3.978 16.501 ;
     RECT  5.652 16.411 5.814 16.529 ;
     RECT  5.652 16.529 5.67 16.541 ;
     RECT  3.96 16.501 4.59 16.565 ;
     RECT  4.572 16.565 4.59 16.673 ;
     RECT  3.672 17.041 3.69 17.375 ;
     RECT  4.428 17.311 4.446 17.411 ;
     RECT  7.416 16.411 8.097 17.581 ;
     RECT  9.144 17.491 9.162 17.581 ;
     RECT  6.624 17.491 6.642 17.651 ;
     RECT  7.416 17.581 9.162 17.915 ;
     RECT  3.78 17.491 3.798 18.121 ;
     RECT  3.528 18.121 3.798 18.139 ;
     RECT  3.528 18.139 4.05 18.301 ;
     RECT  0.108 16.375 0.126 18.455 ;
     RECT  2.415 2.413 2.697 18.571 ;
     RECT  3.528 18.301 4.194 18.571 ;
     RECT  2.415 18.571 4.194 18.763 ;
     RECT  2.415 18.763 4.554 18.803 ;
     RECT  5.94 18.121 5.958 18.811 ;
     RECT  11.916 18.031 11.934 18.931 ;
     RECT  2.415 18.803 4.014 18.995 ;
     RECT  7.815 17.915 9.162 18.995 ;
     RECT  9.144 18.995 9.162 19.103 ;
     RECT  5.724 18.811 5.958 19.111 ;
     RECT  7.815 18.995 8.226 19.111 ;
     RECT  11.916 18.931 12.258 19.111 ;
     RECT  11.412 19.111 12.258 19.229 ;
     RECT  2.415 18.995 2.697 19.243 ;
     RECT  3.492 18.995 4.014 19.265 ;
     RECT  4.932 19.201 4.95 19.301 ;
     RECT  13.215 2.413 13.497 19.345 ;
     RECT  3.78 19.265 4.014 19.805 ;
     RECT  5.724 19.111 5.994 19.877 ;
     RECT  4.428 19.963 4.446 20.039 ;
     RECT  12.24 19.229 12.258 20.039 ;
     RECT  2.304 19.243 2.697 20.075 ;
     RECT  5.724 19.877 5.742 20.191 ;
     RECT  13.104 19.345 13.497 20.191 ;
     RECT  7.416 19.111 8.226 20.281 ;
     RECT  9.144 19.921 9.162 20.281 ;
     RECT  4.572 20.191 4.59 20.309 ;
     RECT  6.588 19.921 6.606 20.345 ;
     RECT  3.528 20.191 3.546 20.461 ;
     RECT  10.584 12.361 10.602 20.587 ;
     RECT  11.412 19.229 11.43 20.587 ;
     RECT  5.364 20.191 5.742 20.821 ;
     RECT  0.108 20.203 0.126 20.885 ;
     RECT  3.492 20.461 3.546 21.001 ;
     RECT  5.292 20.821 5.742 21.119 ;
     RECT  7.416 20.281 9.162 21.119 ;
     RECT  3.492 21.001 3.582 21.155 ;
     RECT  5.364 21.119 5.742 21.155 ;
     RECT  0.54 21.127 0.558 21.197 ;
     RECT  2.415 20.075 2.697 21.271 ;
     RECT  7.416 21.119 8.694 21.271 ;
     RECT  6.84 21.271 8.694 21.389 ;
     RECT  10.584 20.587 11.43 21.389 ;
     RECT  4.32 21.091 4.338 21.469 ;
     RECT  10.584 21.389 11.178 21.469 ;
     RECT  4.32 21.469 4.554 21.541 ;
     RECT  5.688 21.155 5.742 21.541 ;
     RECT  6.84 21.389 8.37 21.541 ;
     RECT  10.26 21.469 11.178 21.541 ;
     RECT  13.104 20.191 14.202 21.541 ;
     RECT  16.992 21.001 17.01 21.631 ;
     RECT  4.212 21.541 4.554 21.659 ;
     RECT  5.688 21.541 8.37 21.659 ;
     RECT  13.104 21.541 15.534 21.659 ;
     RECT  0.108 21.643 0.126 21.695 ;
     RECT  6.84 21.659 8.37 21.695 ;
     RECT  13.104 21.659 14.202 21.695 ;
     RECT  5.688 21.659 6.102 21.803 ;
     RECT  10.116 21.541 11.178 21.929 ;
     RECT  2.415 21.271 3.438 22.075 ;
     RECT  13.104 21.695 13.497 22.081 ;
     RECT  4.284 21.659 4.554 22.123 ;
     RECT  10.116 21.929 11.106 22.235 ;
     RECT  2.304 22.075 3.438 22.505 ;
     RECT  10.26 22.235 11.106 22.505 ;
     RECT  16.524 21.631 17.01 22.585 ;
     RECT  2.415 22.505 3.438 22.621 ;
     RECT  4.284 22.123 4.626 22.621 ;
     RECT  6.084 21.803 6.102 22.621 ;
     RECT  16.524 22.585 17.226 22.621 ;
     RECT  22.032 22.171 22.05 22.621 ;
     RECT  9.144 22.171 9.162 22.711 ;
     RECT  7.416 21.695 8.37 22.739 ;
     RECT  15.516 21.659 15.534 22.739 ;
     RECT  16.308 22.621 17.226 22.739 ;
     RECT  16.848 22.739 17.046 22.781 ;
     RECT  15.372 22.747 15.426 22.783 ;
     RECT  6.084 22.621 6.282 22.981 ;
     RECT  7.416 22.739 8.154 22.981 ;
     RECT  12.564 22.081 13.497 22.981 ;
     RECT  2.415 22.621 5.13 23.009 ;
     RECT  2.415 23.009 4.626 23.045 ;
     RECT  6.084 22.981 8.154 23.083 ;
     RECT  10.26 22.505 10.602 23.161 ;
     RECT  12.564 22.981 13.698 23.161 ;
     RECT  2.415 23.045 3.402 23.279 ;
     RECT  5.472 23.083 8.154 23.279 ;
     RECT  5.616 23.279 8.154 23.315 ;
     RECT  9.144 22.711 9.45 23.323 ;
     RECT  10.224 23.161 10.602 23.323 ;
     RECT  12.564 23.161 13.914 23.323 ;
     RECT  14.724 22.783 15.426 23.323 ;
     RECT  6.804 23.315 8.154 23.549 ;
     RECT  9.144 23.323 10.602 23.549 ;
     RECT  9.432 23.549 10.602 23.701 ;
     RECT  4.14 23.045 4.626 23.791 ;
     RECT  21.924 22.621 22.05 23.791 ;
     RECT  12.564 23.323 15.426 23.819 ;
     RECT  6.84 23.549 8.154 23.855 ;
     RECT  3.744 23.791 4.626 23.891 ;
     RECT  12.564 23.819 14.598 23.899 ;
     RECT  3.996 23.891 4.626 23.971 ;
     RECT  3.996 23.971 4.806 24.089 ;
     RECT  17.028 22.781 17.046 24.089 ;
     RECT  23.076 22.747 23.094 24.097 ;
     RECT  21.78 23.791 22.05 24.169 ;
     RECT  5.616 23.315 5.67 24.241 ;
     RECT  5.616 24.241 5.778 24.359 ;
     RECT  15.408 23.819 15.426 24.359 ;
     RECT  3.996 24.089 4.302 24.395 ;
     RECT  9.432 23.701 10.854 24.395 ;
     RECT  16.884 24.091 16.902 24.403 ;
     RECT  16.56 24.403 16.902 24.431 ;
     RECT  9.432 24.395 9.81 24.503 ;
     RECT  16.56 24.431 16.65 24.509 ;
     RECT  12.528 23.899 14.598 24.601 ;
     RECT  9.684 24.503 9.81 24.629 ;
     RECT  4.284 24.395 4.302 24.665 ;
     RECT  5.616 24.359 5.67 24.665 ;
     RECT  5.616 24.665 5.634 24.935 ;
     RECT  6.84 23.855 6.858 25.051 ;
     RECT  4.5 25.051 4.554 25.141 ;
     RECT  6.588 25.051 6.858 25.141 ;
     RECT  7.815 23.855 8.154 25.147 ;
     RECT  7.815 25.147 8.37 25.205 ;
     RECT  4.5 25.141 5.094 25.241 ;
     RECT  11.988 24.601 14.598 25.285 ;
     RECT  6.588 25.141 6.894 25.313 ;
     RECT  9.792 24.629 9.81 25.321 ;
     RECT  10.584 24.395 10.854 25.321 ;
     RECT  11.988 25.285 14.958 25.321 ;
     RECT  21.78 24.169 22.086 25.411 ;
     RECT  23.076 24.097 23.166 25.411 ;
     RECT  9.792 25.321 10.854 25.439 ;
     RECT  6.588 25.313 6.858 25.475 ;
     RECT  9.9 25.439 10.854 25.519 ;
     RECT  11.988 25.321 15.318 25.547 ;
     RECT  6.588 25.475 6.606 25.591 ;
     RECT  13.104 25.547 15.318 25.591 ;
     RECT  16.632 24.509 16.65 25.591 ;
     RECT  3.564 25.591 3.582 25.681 ;
     RECT  4.5 25.241 4.698 25.681 ;
     RECT  6.3 25.591 6.606 25.709 ;
     RECT  9.9 25.519 10.89 25.709 ;
     RECT  3.564 25.681 4.698 25.745 ;
     RECT  7.815 25.205 8.154 25.745 ;
     RECT  3.636 25.745 4.698 25.781 ;
     RECT  13.104 25.591 16.65 25.979 ;
     RECT  9.9 25.709 10.854 26.015 ;
     RECT  14.256 25.979 16.65 26.023 ;
     RECT  5.472 26.131 5.49 26.189 ;
     RECT  14.256 26.023 17.01 26.221 ;
     RECT  14.256 26.221 17.154 26.249 ;
     RECT  18.615 2.413 18.897 26.251 ;
     RECT  3.636 25.781 3.654 26.285 ;
     RECT  14.94 26.249 16.146 26.291 ;
     RECT  18.18 26.251 18.897 26.291 ;
     RECT  16.956 26.249 17.154 26.393 ;
     RECT  18.615 26.291 18.897 26.401 ;
     RECT  14.94 26.291 15.966 26.429 ;
     RECT  11.988 25.547 12.042 26.491 ;
     RECT  10.512 26.015 10.854 26.555 ;
     RECT  15.3 26.429 15.966 26.555 ;
     RECT  7.815 25.745 8.097 26.635 ;
     RECT  15.876 26.555 15.966 26.663 ;
     RECT  4.5 25.781 4.698 26.671 ;
     RECT  6.3 25.709 6.318 26.671 ;
     RECT  7.74 26.635 8.097 26.671 ;
     RECT  2.415 23.279 2.697 26.761 ;
     RECT  4.464 26.671 4.698 26.761 ;
     RECT  5.832 26.671 6.318 26.761 ;
     RECT  21.78 25.411 23.166 26.761 ;
     RECT  24.015 2.413 24.297 26.761 ;
     RECT  5.832 26.761 6.858 26.765 ;
     RECT  5.976 26.765 6.858 26.789 ;
     RECT  6.3 26.789 6.858 26.797 ;
     RECT  4.464 26.761 4.95 26.825 ;
     RECT  10.584 26.555 10.854 26.825 ;
     RECT  18.615 26.401 19.134 26.825 ;
     RECT  15.948 26.663 15.966 27.031 ;
     RECT  16.956 26.393 17.118 27.059 ;
     RECT  6.3 26.797 6.93 27.095 ;
     RECT  18.615 26.825 18.897 27.211 ;
     RECT  4.464 26.825 4.734 27.301 ;
     RECT  9.648 27.211 9.666 27.301 ;
     RECT  13.104 25.979 13.497 27.301 ;
     RECT  4.212 27.301 4.734 27.341 ;
     RECT  6.48 27.095 6.93 27.355 ;
     RECT  7.668 26.671 8.097 27.355 ;
     RECT  0.108 22.555 0.126 27.365 ;
     RECT  4.716 27.341 4.734 27.365 ;
     RECT  11.7 26.491 12.042 27.365 ;
     RECT  2.415 26.761 3.33 27.481 ;
     RECT  11.7 27.365 12.006 27.599 ;
     RECT  2.415 27.481 3.438 27.787 ;
     RECT  9.144 27.301 9.666 27.841 ;
     RECT  15.948 27.031 16.002 27.841 ;
     RECT  2.304 27.787 3.438 27.905 ;
     RECT  15.408 27.841 16.002 27.985 ;
     RECT  16.956 27.059 17.082 27.985 ;
     RECT  3.888 28.111 3.906 28.123 ;
     RECT  6.48 27.355 8.097 28.139 ;
     RECT  15.408 27.985 17.082 28.139 ;
     RECT  2.304 27.905 2.697 28.175 ;
     RECT  10.584 26.825 10.602 28.183 ;
     RECT  3.888 28.123 4.374 28.211 ;
     RECT  3.996 28.211 4.374 28.291 ;
     RECT  10.584 28.183 10.782 28.291 ;
     RECT  9.144 27.841 9.846 28.409 ;
     RECT  13.104 27.301 13.698 28.409 ;
     RECT  3.996 28.291 4.518 28.459 ;
     RECT  3.996 28.459 4.95 28.651 ;
     RECT  5.724 28.291 5.742 28.651 ;
     RECT  11.988 27.599 12.006 28.651 ;
     RECT  20.196 26.797 20.214 28.651 ;
     RECT  15.408 28.139 15.426 28.679 ;
     RECT  3.996 28.651 5.742 28.715 ;
     RECT  9.828 28.409 9.846 28.715 ;
     RECT  4.356 28.715 5.742 28.795 ;
     RECT  7.128 28.139 8.097 28.921 ;
     RECT  4.356 28.795 6.318 28.949 ;
     RECT  4.356 28.949 4.95 28.985 ;
     RECT  5.724 28.949 6.318 28.985 ;
     RECT  13.104 28.409 13.497 28.985 ;
     RECT  4.536 28.985 4.95 29.021 ;
     RECT  16.56 28.139 17.082 29.029 ;
     RECT  6.012 28.985 6.318 29.069 ;
     RECT  6.264 29.069 6.318 29.083 ;
     RECT  7.092 28.921 8.097 29.083 ;
     RECT  17.892 27.211 18.897 29.191 ;
     RECT  10.584 28.291 11.178 29.219 ;
     RECT  4.788 29.021 4.95 29.489 ;
     RECT  3.564 29.371 3.582 29.525 ;
     RECT  8.928 29.569 8.946 29.605 ;
     RECT  6.264 29.083 8.097 29.755 ;
     RECT  8.928 29.605 9.162 29.755 ;
     RECT  20.196 28.651 20.826 29.755 ;
     RECT  11.988 28.651 12.366 29.759 ;
     RECT  6.264 29.755 9.162 29.789 ;
     RECT  0.108 28.267 0.126 29.795 ;
     RECT  7.128 29.789 9.162 29.795 ;
     RECT  2.415 28.175 2.697 29.911 ;
     RECT  8.928 29.795 9.162 29.911 ;
     RECT  13.215 28.985 13.497 29.911 ;
     RECT  16.524 29.029 17.082 29.939 ;
     RECT  2.415 29.911 2.934 30.029 ;
     RECT  20.124 29.755 20.826 30.065 ;
     RECT  10.584 29.219 10.854 30.109 ;
     RECT  2.415 30.029 2.697 30.139 ;
     RECT  17.892 29.191 19.386 30.173 ;
     RECT  5.004 29.995 5.022 30.181 ;
     RECT  6.264 29.789 6.282 30.181 ;
     RECT  8.928 29.911 9.702 30.181 ;
     RECT  10.584 30.109 10.89 30.181 ;
     RECT  13.104 29.911 13.497 30.181 ;
     RECT  20.196 30.065 20.826 30.181 ;
     RECT  21.78 26.761 24.297 30.181 ;
     RECT  5.004 30.181 5.166 30.299 ;
     RECT  8.928 30.181 10.89 30.299 ;
     RECT  2.304 30.139 2.697 30.335 ;
     RECT  4.032 30.181 4.05 30.335 ;
     RECT  9.684 30.299 10.89 30.451 ;
     RECT  5.94 30.181 6.282 30.541 ;
     RECT  7.128 29.795 8.097 30.541 ;
     RECT  4.788 30.451 4.806 30.605 ;
     RECT  5.58 30.541 8.097 30.641 ;
     RECT  0.54 30.577 0.558 30.653 ;
     RECT  5.94 30.641 8.097 30.721 ;
     RECT  17.892 30.173 18.99 30.839 ;
     RECT  11.988 29.759 12.006 30.919 ;
     RECT  13.104 30.181 14.202 30.919 ;
     RECT  5.94 30.721 8.586 30.983 ;
     RECT  9.684 30.451 11.106 30.991 ;
     RECT  11.988 30.919 14.202 30.991 ;
     RECT  6.228 30.983 8.586 31.081 ;
     RECT  2.415 30.335 2.697 31.099 ;
     RECT  6.228 31.081 8.766 31.261 ;
     RECT  3.996 30.721 4.014 31.339 ;
     RECT  9.684 30.991 14.418 31.339 ;
     RECT  20.196 30.181 24.297 31.351 ;
     RECT  9.684 31.339 14.85 31.379 ;
     RECT  9.684 31.379 13.497 31.415 ;
     RECT  3.996 31.339 4.482 31.531 ;
     RECT  76.536 31.435 76.554 31.621 ;
     RECT  9.9 31.415 13.497 31.649 ;
     RECT  76.536 31.621 76.878 31.675 ;
     RECT  6.228 31.261 8.838 31.685 ;
     RECT  9.9 31.649 11.43 31.685 ;
     RECT  76.392 31.675 76.878 31.721 ;
     RECT  8.82 31.685 8.838 31.801 ;
     RECT  3.888 31.531 4.626 31.891 ;
     RECT  17.064 29.939 17.082 31.891 ;
     RECT  17.892 30.839 18.897 31.891 ;
     RECT  10.44 31.685 11.43 31.955 ;
     RECT  67.215 2.413 67.497 32.011 ;
     RECT  34.815 2.413 35.097 32.147 ;
     RECT  40.215 2.413 40.497 32.147 ;
     RECT  45.615 2.413 45.897 32.147 ;
     RECT  51.015 2.413 51.297 32.147 ;
     RECT  56.415 2.413 56.697 32.147 ;
     RECT  61.815 2.413 62.097 32.147 ;
     RECT  66.708 32.011 67.497 32.147 ;
     RECT  72.615 2.413 72.897 32.147 ;
     RECT  78.015 2.413 78.297 32.147 ;
     RECT  83.415 2.413 83.697 32.147 ;
     RECT  88.815 2.413 89.097 32.147 ;
     RECT  94.215 2.413 94.497 32.147 ;
     RECT  99.615 2.413 99.897 32.147 ;
     RECT  105.015 2.413 105.297 32.147 ;
     RECT  110.415 2.413 110.697 32.147 ;
     RECT  115.815 2.413 116.097 32.147 ;
     RECT  121.215 2.413 121.497 32.147 ;
     RECT  126.615 2.413 126.897 32.147 ;
     RECT  132.015 2.413 132.297 32.147 ;
     RECT  137.415 2.413 137.697 32.147 ;
     RECT  142.815 2.413 143.097 32.147 ;
     RECT  148.215 2.413 148.497 32.147 ;
     RECT  153.615 2.413 153.897 32.147 ;
     RECT  159.015 2.413 159.297 32.147 ;
     RECT  164.415 2.413 164.697 32.147 ;
     RECT  169.815 2.413 170.097 32.147 ;
     RECT  175.215 2.413 175.497 32.147 ;
     RECT  180.615 2.413 180.897 32.147 ;
     RECT  186.015 2.413 186.297 32.147 ;
     RECT  191.415 2.413 191.697 32.147 ;
     RECT  196.815 2.413 197.097 32.147 ;
     RECT  202.215 2.413 202.497 32.147 ;
     RECT  207.615 2.413 207.897 32.147 ;
     RECT  213.015 2.413 213.297 32.147 ;
     RECT  218.415 2.413 218.697 32.147 ;
     RECT  223.815 2.413 224.097 32.147 ;
     RECT  0.108 32.011 0.126 32.225 ;
     RECT  68.364 31.675 68.382 32.225 ;
     RECT  214.56 32.197 214.578 32.269 ;
     RECT  66.708 32.147 67.305 32.285 ;
     RECT  214.56 32.269 214.722 32.305 ;
     RECT  69.84 32.299 69.858 32.339 ;
     RECT  3.636 31.891 4.878 32.341 ;
     RECT  6.228 31.685 8.097 32.341 ;
     RECT  8.82 31.801 9.162 32.341 ;
     RECT  14.4 31.379 14.85 32.341 ;
     RECT  15.84 32.269 15.858 32.341 ;
     RECT  42.732 31.891 42.75 32.341 ;
     RECT  214.56 32.305 214.794 32.341 ;
     RECT  42.732 32.341 43.398 32.381 ;
     RECT  67.215 32.285 67.305 32.417 ;
     RECT  72.615 32.147 72.705 32.417 ;
     RECT  78.015 32.147 78.105 32.417 ;
     RECT  83.415 32.147 83.505 32.417 ;
     RECT  88.815 32.147 88.905 32.417 ;
     RECT  94.215 32.147 94.305 32.417 ;
     RECT  99.615 32.147 99.705 32.417 ;
     RECT  105.015 32.147 105.105 32.417 ;
     RECT  110.415 32.147 110.505 32.417 ;
     RECT  115.815 32.147 115.905 32.417 ;
     RECT  121.215 32.147 121.305 32.417 ;
     RECT  126.615 32.147 126.705 32.417 ;
     RECT  132.015 32.147 132.105 32.417 ;
     RECT  137.415 32.147 137.505 32.417 ;
     RECT  142.815 32.147 142.905 32.417 ;
     RECT  148.215 32.147 148.305 32.417 ;
     RECT  153.615 32.147 153.705 32.417 ;
     RECT  159.015 32.147 159.105 32.417 ;
     RECT  164.415 32.147 164.505 32.417 ;
     RECT  169.815 32.147 169.905 32.417 ;
     RECT  175.215 32.147 175.305 32.417 ;
     RECT  180.615 32.147 180.705 32.417 ;
     RECT  186.015 32.147 186.105 32.417 ;
     RECT  191.415 32.147 191.505 32.417 ;
     RECT  196.815 32.147 196.905 32.417 ;
     RECT  202.215 32.147 202.305 32.417 ;
     RECT  207.615 32.147 207.705 32.417 ;
     RECT  213.015 32.147 213.105 32.417 ;
     RECT  218.415 32.147 218.505 32.417 ;
     RECT  223.815 32.147 223.905 32.417 ;
     RECT  17.064 31.891 18.897 32.431 ;
     RECT  19.656 31.351 24.297 32.431 ;
     RECT  214.344 32.341 214.794 32.431 ;
     RECT  34.815 32.147 35.01 32.443 ;
     RECT  40.215 32.147 40.41 32.443 ;
     RECT  45.615 32.147 45.81 32.443 ;
     RECT  51.015 32.147 51.21 32.443 ;
     RECT  56.415 32.147 56.61 32.443 ;
     RECT  61.815 32.147 62.01 32.443 ;
     RECT  14.292 32.341 15.858 32.459 ;
     RECT  214.344 32.431 214.866 32.459 ;
     RECT  2.304 31.099 2.697 32.467 ;
     RECT  3.636 32.341 8.097 32.467 ;
     RECT  8.82 32.341 9.702 32.467 ;
     RECT  10.44 31.955 10.602 32.467 ;
     RECT  11.412 31.955 11.43 32.467 ;
     RECT  3.636 32.467 10.602 32.495 ;
     RECT  12.564 31.649 13.497 32.495 ;
     RECT  14.292 32.459 15.714 32.495 ;
     RECT  34.704 32.443 35.01 32.495 ;
     RECT  40.104 32.443 40.41 32.495 ;
     RECT  45.504 32.443 45.81 32.495 ;
     RECT  50.904 32.443 51.21 32.495 ;
     RECT  56.304 32.443 56.61 32.495 ;
     RECT  61.704 32.443 62.01 32.495 ;
     RECT  1.728 32.467 2.697 32.525 ;
     RECT  3.456 32.611 3.474 32.765 ;
     RECT  4.248 32.495 5.922 32.837 ;
     RECT  6.912 32.495 10.602 32.873 ;
     RECT  6.948 32.873 10.602 32.909 ;
     RECT  5.58 32.837 5.922 33.035 ;
     RECT  6.984 32.909 10.602 33.035 ;
     RECT  11.412 32.467 11.646 33.241 ;
     RECT  11.412 33.241 11.754 33.349 ;
     RECT  12.6 32.495 13.497 33.349 ;
     RECT  11.412 33.349 13.497 33.421 ;
     RECT  14.292 32.495 15.39 33.421 ;
     RECT  7.128 33.035 10.602 33.449 ;
     RECT  11.412 33.421 15.786 33.539 ;
     RECT  11.736 33.539 15.39 33.575 ;
     RECT  4.248 32.837 4.662 33.583 ;
     RECT  3.924 33.583 4.662 33.739 ;
     RECT  5.58 33.035 5.598 33.739 ;
     RECT  9.936 33.449 10.602 33.787 ;
     RECT  3.924 33.739 5.598 33.809 ;
     RECT  7.128 33.449 9.198 33.917 ;
     RECT  9.936 33.787 10.926 33.917 ;
     RECT  5.112 33.809 5.598 33.961 ;
     RECT  7.488 33.917 9.198 34.187 ;
     RECT  5.112 33.961 6.066 34.349 ;
     RECT  7.488 34.187 8.19 34.349 ;
     RECT  3.924 33.809 3.978 34.385 ;
     RECT  13.104 33.575 15.39 34.429 ;
     RECT  5.58 34.349 6.066 34.591 ;
     RECT  13.104 34.429 16.038 34.619 ;
     RECT  3.888 34.501 3.906 34.655 ;
     RECT  14.76 34.619 15.858 34.655 ;
     RECT  5.58 34.591 6.138 34.771 ;
     RECT  7.488 34.349 8.097 34.771 ;
     RECT  14.76 34.655 15.174 34.781 ;
     RECT  5.58 34.771 8.097 34.925 ;
     RECT  9.18 34.187 9.198 35.041 ;
     RECT  9.936 33.917 10.602 35.041 ;
     RECT  6.12 34.925 8.097 35.131 ;
     RECT  11.736 33.575 12.15 35.159 ;
     RECT  11.988 35.159 12.15 35.203 ;
     RECT  13.104 34.619 13.497 35.203 ;
     RECT  4.644 34.795 4.662 35.311 ;
     RECT  9.18 35.041 10.602 35.311 ;
     RECT  6.12 35.131 8.154 35.429 ;
     RECT  14.976 34.781 15.174 35.509 ;
     RECT  3.744 35.311 3.762 35.545 ;
     RECT  4.644 35.311 4.806 35.545 ;
     RECT  9.144 35.311 10.602 35.581 ;
     RECT  17.064 32.431 24.297 35.581 ;
     RECT  3.744 35.545 5.274 35.699 ;
     RECT  3.744 35.699 4.59 35.735 ;
     RECT  0.108 32.971 0.126 35.843 ;
     RECT  3.888 35.735 4.59 35.843 ;
     RECT  6.228 35.429 8.154 35.851 ;
     RECT  9.144 35.581 10.818 35.851 ;
     RECT  6.228 35.851 10.818 35.969 ;
     RECT  14.976 35.509 15.498 35.969 ;
     RECT  4.572 35.843 4.59 36.005 ;
     RECT  9.684 35.969 10.818 36.113 ;
     RECT  10.584 36.113 10.818 36.121 ;
     RECT  11.988 35.203 13.497 36.121 ;
     RECT  14.976 35.969 15.246 36.121 ;
     RECT  0.54 36.247 0.558 36.317 ;
     RECT  6.228 35.969 8.91 36.413 ;
     RECT  6.228 36.413 6.282 36.509 ;
     RECT  10.584 36.121 13.497 36.509 ;
     RECT  5.328 36.391 5.346 36.545 ;
     RECT  7.164 36.413 8.91 36.545 ;
     RECT  6.264 36.509 6.282 36.617 ;
     RECT  7.344 36.545 8.91 36.815 ;
     RECT  2.415 32.525 2.697 36.895 ;
     RECT  8.892 36.815 8.91 36.895 ;
     RECT  9.684 36.113 9.738 36.895 ;
     RECT  2.415 36.895 3.294 36.931 ;
     RECT  14.652 36.121 15.246 36.931 ;
     RECT  8.892 36.895 9.738 37.021 ;
     RECT  8.892 37.021 9.774 37.085 ;
     RECT  14.652 36.931 15.714 37.165 ;
     RECT  7.38 36.815 8.097 37.193 ;
     RECT  14.508 37.165 15.714 37.229 ;
     RECT  11.376 36.509 13.497 37.319 ;
     RECT  0.108 36.763 0.126 37.355 ;
     RECT  10.584 36.509 10.602 37.399 ;
     RECT  5.148 36.931 5.166 37.471 ;
     RECT  9.36 37.085 9.774 37.471 ;
     RECT  10.584 37.399 10.638 37.471 ;
     RECT  12.564 37.319 13.497 37.471 ;
     RECT  15.228 37.229 15.714 37.499 ;
     RECT  12.564 37.471 13.698 37.561 ;
     RECT  2.415 36.931 3.438 37.589 ;
     RECT  9.36 37.471 10.638 37.589 ;
     RECT  2.415 37.589 3.366 37.597 ;
     RECT  1.728 37.597 3.366 37.625 ;
     RECT  9.36 37.589 10.602 37.625 ;
     RECT  4.5 37.471 5.166 37.741 ;
     RECT  1.728 37.625 2.697 37.757 ;
     RECT  9.756 37.625 10.602 37.895 ;
     RECT  12.564 37.561 14.238 38.165 ;
     RECT  4.356 37.741 5.166 38.173 ;
     RECT  4.284 38.173 5.166 38.189 ;
     RECT  15.48 37.499 15.714 38.189 ;
     RECT  6.264 38.101 6.282 38.515 ;
     RECT  7.452 37.193 8.097 38.551 ;
     RECT  6.264 38.515 6.318 38.573 ;
     RECT  11.376 37.319 11.538 38.579 ;
     RECT  0.108 38.137 0.126 38.705 ;
     RECT  5.148 38.189 5.166 38.705 ;
     RECT  4.284 38.189 4.302 38.821 ;
     RECT  10.26 37.895 10.602 38.939 ;
     RECT  13.14 38.165 14.238 38.975 ;
     RECT  3.672 38.821 4.302 39.091 ;
     RECT  6.264 38.573 6.282 39.091 ;
     RECT  7.416 38.551 8.097 39.091 ;
     RECT  9.108 38.713 9.126 39.091 ;
     RECT  13.14 38.975 13.497 39.091 ;
     RECT  2.415 37.757 2.697 39.115 ;
     RECT  11.412 38.579 11.538 39.209 ;
     RECT  15.516 38.189 15.714 39.209 ;
     RECT  3.672 39.091 4.374 39.245 ;
     RECT  7.416 39.091 9.126 39.289 ;
     RECT  12.564 39.091 13.497 39.289 ;
     RECT  4.248 39.245 4.374 39.355 ;
     RECT  2.304 39.115 2.697 39.515 ;
     RECT  7.416 39.289 9.378 39.515 ;
     RECT  9.36 39.515 9.378 39.559 ;
     RECT  4.248 39.355 4.662 39.631 ;
     RECT  10.584 38.939 10.602 39.631 ;
     RECT  11.412 39.209 11.502 39.631 ;
     RECT  0.108 39.595 0.126 39.785 ;
     RECT  4.248 39.631 4.914 39.785 ;
     RECT  4.644 39.785 4.914 39.865 ;
     RECT  5.724 39.091 6.282 39.865 ;
     RECT  12.276 39.289 13.497 39.893 ;
     RECT  14.292 39.289 14.31 39.901 ;
     RECT  10.584 39.631 11.502 39.991 ;
     RECT  12.276 39.893 12.294 39.991 ;
     RECT  9.36 39.559 9.45 40.019 ;
     RECT  4.644 39.865 6.282 40.055 ;
     RECT  0.54 40.063 0.558 40.109 ;
     RECT  5.688 40.055 6.282 40.165 ;
     RECT  2.415 39.515 2.697 40.171 ;
     RECT  10.584 39.991 12.294 40.171 ;
     RECT  5.688 40.165 6.606 40.205 ;
     RECT  7.416 39.515 8.478 40.289 ;
     RECT  14.256 39.901 14.31 40.289 ;
     RECT  10.26 40.171 12.294 40.325 ;
     RECT  4.644 40.055 4.95 40.361 ;
     RECT  13.068 39.893 13.497 40.411 ;
     RECT  14.256 40.289 14.274 40.411 ;
     RECT  10.26 40.325 11.574 40.441 ;
     RECT  15.516 39.209 15.642 40.441 ;
     RECT  16.776 35.581 24.297 40.441 ;
     RECT  15.516 40.441 24.297 40.445 ;
     RECT  13.068 40.411 14.274 40.469 ;
     RECT  4.644 40.361 4.842 40.64 ;
     RECT  2.415 40.171 3.33 40.711 ;
     RECT  9.684 40.441 11.574 40.801 ;
     RECT  2.415 40.711 3.402 40.865 ;
     RECT  7.815 40.289 8.478 40.865 ;
     RECT  13.068 40.469 13.497 40.909 ;
     RECT  9.36 40.801 11.574 40.981 ;
     RECT  6.912 40.441 6.93 41.135 ;
     RECT  4.644 40.64 4.806 41.251 ;
     RECT  7.815 40.865 8.097 41.251 ;
     RECT  4.284 41.251 4.806 41.369 ;
     RECT  4.284 41.369 4.59 41.405 ;
     RECT  0.108 40.555 0.126 41.513 ;
     RECT  9.144 40.981 11.574 41.639 ;
     RECT  4.536 41.405 4.59 41.675 ;
     RECT  5.688 40.205 5.994 41.675 ;
     RECT  11.556 41.639 11.574 41.675 ;
     RECT  6.948 41.251 8.097 41.719 ;
     RECT  9.144 41.639 10.602 41.719 ;
     RECT  6.948 41.719 10.602 41.783 ;
     RECT  14.256 40.469 14.274 41.791 ;
     RECT  0.54 41.917 0.558 41.981 ;
     RECT  12.024 41.791 12.042 42.025 ;
     RECT  12.816 40.909 13.497 42.025 ;
     RECT  5.904 41.675 5.994 42.061 ;
     RECT  15.768 40.445 24.297 42.061 ;
     RECT  6.948 41.783 9.162 42.089 ;
     RECT  6.948 42.089 7.074 42.173 ;
     RECT  5.904 42.061 6.174 42.179 ;
     RECT  4.536 41.675 4.554 42.215 ;
     RECT  6.948 42.173 6.966 42.215 ;
     RECT  7.815 42.089 9.162 42.215 ;
     RECT  15.228 42.061 24.297 42.691 ;
     RECT  41.868 42.457 41.886 42.691 ;
     RECT  5.904 42.179 6.03 42.727 ;
     RECT  10.08 41.783 10.602 42.727 ;
     RECT  14.256 41.791 14.31 42.727 ;
     RECT  15.12 42.691 24.297 42.727 ;
     RECT  3.564 42.601 3.582 42.755 ;
     RECT  5.472 42.727 6.03 42.763 ;
     RECT  4.644 42.763 6.03 42.8 ;
     RECT  12.024 42.025 13.497 42.871 ;
     RECT  14.256 42.727 24.297 42.871 ;
     RECT  7.815 42.215 8.946 42.961 ;
     RECT  41.868 42.691 41.958 42.997 ;
     RECT  42.732 32.381 43.146 42.997 ;
     RECT  221.148 42.997 221.166 43.033 ;
     RECT  222.372 42.997 222.39 43.033 ;
     RECT  222.3 43.033 222.39 43.097 ;
     RECT  222.3 43.097 222.318 43.169 ;
     RECT  41.868 42.997 43.146 43.2 ;
     RECT  214.56 32.459 214.866 43.2 ;
     RECT  40.176 41.917 40.194 43.231 ;
     RECT  5.004 42.8 6.03 43.259 ;
     RECT  7.815 42.961 9.198 43.295 ;
     RECT  12.024 42.871 24.297 43.331 ;
     RECT  0.108 42.427 0.126 43.565 ;
     RECT  3.924 43.231 3.942 43.565 ;
     RECT  12.024 43.331 12.042 43.565 ;
     RECT  5.004 43.259 5.958 43.681 ;
     RECT  9.936 42.727 10.602 43.681 ;
     RECT  6.876 43.303 6.894 43.771 ;
     RECT  7.815 43.295 8.097 43.771 ;
     RECT  4.788 43.681 5.958 43.835 ;
     RECT  224.424 43.303 224.442 43.843 ;
     RECT  2.415 40.865 2.697 43.867 ;
     RECT  40.032 43.231 40.194 44.077 ;
     RECT  2.304 43.867 2.697 44.105 ;
     RECT  5.256 43.835 5.958 44.105 ;
     RECT  9.936 43.681 10.998 44.105 ;
     RECT  13.215 43.331 24.297 44.221 ;
     RECT  224.424 43.843 224.478 44.221 ;
     RECT  6.876 43.771 8.097 44.311 ;
     RECT  8.856 43.295 9.198 44.311 ;
     RECT  39.96 44.077 40.194 44.311 ;
     RECT  224.424 44.221 224.55 44.311 ;
     RECT  4.284 44.383 4.482 44.429 ;
     RECT  6.876 44.311 9.414 44.443 ;
     RECT  41.868 43.2 214.866 44.477 ;
     RECT  39.924 44.311 40.194 44.573 ;
     RECT  4.464 44.429 4.482 44.609 ;
     RECT  225.72 44.311 225.738 44.617 ;
     RECT  219.132 42.151 219.15 44.669 ;
     RECT  10.584 44.105 10.998 44.761 ;
     RECT  224.424 44.311 224.586 44.761 ;
     RECT  43.2 44.477 214.866 44.765 ;
     RECT  5.256 44.105 5.742 44.851 ;
     RECT  10.584 44.761 11.106 44.851 ;
     RECT  221.076 43.033 221.166 44.861 ;
     RECT  6.84 44.443 9.414 44.915 ;
     RECT  39.924 44.573 40.05 44.957 ;
     RECT  221.148 44.861 221.166 44.957 ;
     RECT  5.04 44.851 5.742 44.995 ;
     RECT  6.84 44.915 8.586 44.995 ;
     RECT  9.396 44.915 9.414 44.995 ;
     RECT  10.584 44.851 11.43 44.995 ;
     RECT  41.868 44.477 42.426 45.053 ;
     RECT  5.04 44.995 8.586 45.101 ;
     RECT  12.564 44.221 24.297 45.149 ;
     RECT  39.924 44.957 40.014 45.149 ;
     RECT  41.868 45.053 42.39 45.157 ;
     RECT  3.564 44.491 3.582 45.185 ;
     RECT  5.112 45.101 8.586 45.185 ;
     RECT  2.415 44.105 2.697 45.301 ;
     RECT  225.684 44.617 225.738 45.301 ;
     RECT  41.616 45.157 42.39 45.341 ;
     RECT  13.176 45.149 24.297 45.419 ;
     RECT  41.616 45.341 42.318 45.437 ;
     RECT  2.415 45.301 3.402 45.455 ;
     RECT  5.112 45.185 5.274 45.455 ;
     RECT  9.396 44.995 11.43 45.455 ;
     RECT  13.176 45.419 13.497 45.485 ;
     RECT  224.028 44.761 224.586 45.533 ;
     RECT  10.008 45.455 11.43 45.689 ;
     RECT  225.504 45.301 225.738 45.769 ;
     RECT  41.616 45.437 42.282 45.821 ;
     RECT  6.084 45.185 8.586 45.841 ;
     RECT  32.184 45.733 32.202 45.869 ;
     RECT  41.616 45.821 42.246 45.883 ;
     RECT  41.004 45.883 42.246 45.959 ;
     RECT  5.112 45.455 5.13 45.995 ;
     RECT  39.924 45.149 39.978 46.003 ;
     RECT  41.616 45.959 42.246 46.013 ;
     RECT  224.028 45.533 224.046 46.031 ;
     RECT  6.084 45.841 8.658 46.111 ;
     RECT  10.152 45.689 11.43 46.171 ;
     RECT  6.084 46.111 8.946 46.201 ;
     RECT  41.616 46.013 42.21 46.205 ;
     RECT  39.924 46.003 40.014 46.237 ;
     RECT  225.036 45.769 225.738 46.237 ;
     RECT  6.084 46.201 9.198 46.253 ;
     RECT  0.108 44.347 0.126 46.265 ;
     RECT  10.152 46.171 12.114 46.265 ;
     RECT  225.036 46.237 226.098 46.301 ;
     RECT  10.476 46.265 12.114 46.381 ;
     RECT  13.215 45.485 13.497 46.381 ;
     RECT  14.256 45.419 24.297 46.381 ;
     RECT  34.776 46.003 34.794 46.507 ;
     RECT  6.084 46.253 8.946 46.535 ;
     RECT  39.348 46.237 40.014 46.555 ;
     RECT  222.876 46.237 222.894 46.589 ;
     RECT  34.776 46.507 34.866 46.607 ;
     RECT  2.415 45.455 2.697 46.651 ;
     RECT  6.084 46.535 6.894 46.651 ;
     RECT  2.415 46.651 3.834 46.699 ;
     RECT  34.704 46.741 34.758 46.747 ;
     RECT  38.736 46.555 40.014 46.747 ;
     RECT  225.036 46.301 225.738 46.747 ;
     RECT  2.304 46.699 3.834 46.805 ;
     RECT  34.632 46.747 34.758 46.805 ;
     RECT  226.872 46.651 226.89 46.805 ;
     RECT  31.932 46.777 31.95 46.813 ;
     RECT  41.616 46.205 41.634 46.813 ;
     RECT  31.932 46.813 32.418 46.885 ;
     RECT  31.932 46.885 32.454 46.913 ;
     RECT  38.736 46.747 40.194 46.925 ;
     RECT  32.4 46.913 32.454 46.949 ;
     RECT  38.736 46.925 38.754 46.949 ;
     RECT  32.436 46.949 32.454 46.994 ;
     RECT  34.668 46.805 34.758 46.994 ;
     RECT  7.74 46.535 8.946 47.011 ;
     RECT  41.04 46.813 41.634 47.069 ;
     RECT  227.124 47.011 227.142 47.069 ;
     RECT  10.476 46.381 24.297 47.075 ;
     RECT  10.476 47.075 10.602 47.119 ;
     RECT  30.78 47.011 30.798 47.147 ;
     RECT  34.668 46.994 34.686 47.147 ;
     RECT  4.572 47.155 4.59 47.191 ;
     RECT  39.924 46.925 40.086 47.261 ;
     RECT  4.572 47.191 4.734 47.275 ;
     RECT  5.796 46.651 6.894 47.275 ;
     RECT  4.572 47.275 6.894 47.281 ;
     RECT  7.74 47.011 9.45 47.281 ;
     RECT  4.572 47.281 9.45 47.309 ;
     RECT  2.304 46.805 2.697 47.345 ;
     RECT  3.42 46.805 3.834 47.345 ;
     RECT  224.604 46.747 225.738 47.357 ;
     RECT  227.448 47.419 227.466 47.489 ;
     RECT  225.072 47.357 225.738 47.549 ;
     RECT  5.112 47.309 9.45 47.579 ;
     RECT  3.96 47.461 3.978 47.615 ;
     RECT  39.924 47.261 40.014 47.707 ;
     RECT  41.616 47.069 41.634 47.803 ;
     RECT  7.38 47.579 9.45 47.821 ;
     RECT  10.224 47.119 10.602 47.821 ;
     RECT  29.415 2.413 29.697 47.821 ;
     RECT  32.112 47.731 32.13 47.857 ;
     RECT  222.264 47.821 222.282 47.857 ;
     RECT  225.108 47.549 225.738 47.857 ;
     RECT  41.616 47.803 42.174 47.885 ;
     RECT  7.38 47.821 10.602 47.891 ;
     RECT  29.415 47.821 30.114 47.921 ;
     RECT  39.888 47.707 40.014 47.933 ;
     RECT  32.112 47.857 32.238 47.957 ;
     RECT  11.484 47.075 24.297 48.001 ;
     RECT  11.34 48.001 24.297 48.029 ;
     RECT  38.16 47.419 38.178 48.029 ;
     RECT  29.415 47.921 29.826 48.119 ;
     RECT  228.204 47.803 228.222 48.119 ;
     RECT  222.264 47.857 222.858 48.125 ;
     RECT  5.148 47.579 6.57 48.155 ;
     RECT  34.848 48.127 34.866 48.227 ;
     RECT  3.816 48.271 3.834 48.361 ;
     RECT  5.472 48.155 6.57 48.361 ;
     RECT  7.38 47.891 8.154 48.361 ;
     RECT  32.112 47.957 32.202 48.361 ;
     RECT  39.888 47.933 39.978 48.361 ;
     RECT  11.34 48.029 11.358 48.365 ;
     RECT  39.348 48.361 39.978 48.379 ;
     RECT  3.816 48.361 4.086 48.397 ;
     RECT  225.108 47.857 225.882 48.397 ;
     RECT  3.816 48.397 4.59 48.425 ;
     RECT  5.472 48.361 8.154 48.425 ;
     RECT  39.312 48.379 39.978 48.425 ;
     RECT  4.068 48.425 4.59 48.461 ;
     RECT  9.072 47.891 10.602 48.461 ;
     RECT  39.348 48.425 39.978 48.509 ;
     RECT  41.616 47.885 41.706 48.541 ;
     RECT  222.264 48.125 222.282 48.605 ;
     RECT  41.04 48.541 41.706 48.631 ;
     RECT  31.752 48.361 32.202 48.659 ;
     RECT  34.74 48.631 34.758 48.667 ;
     RECT  9.072 48.461 9.702 48.695 ;
     RECT  41.004 48.631 41.706 48.701 ;
     RECT  39.924 48.509 39.978 48.703 ;
     RECT  224.604 48.397 225.882 48.775 ;
     RECT  34.704 48.667 34.758 48.803 ;
     RECT  6.444 48.425 8.154 48.811 ;
     RECT  5.472 48.425 5.67 48.929 ;
     RECT  31.392 48.775 31.41 48.929 ;
     RECT  34.74 48.803 34.758 48.929 ;
     RECT  41.04 48.701 41.706 48.937 ;
     RECT  223.992 48.775 225.882 48.937 ;
     RECT  4.464 48.461 4.482 48.965 ;
     RECT  227.448 48.859 227.466 48.965 ;
     RECT  223.992 48.937 225.918 48.973 ;
     RECT  223.992 48.973 226.278 48.989 ;
     RECT  10.584 48.461 10.602 49.081 ;
     RECT  41.04 48.937 42.21 49.085 ;
     RECT  224.568 48.989 226.278 49.085 ;
     RECT  10.584 49.081 10.638 49.171 ;
     RECT  39.924 48.703 40.014 49.181 ;
     RECT  0.108 47.659 0.126 49.235 ;
     RECT  39.924 49.181 39.978 49.277 ;
     RECT  5.472 48.929 5.526 49.351 ;
     RECT  9.504 48.695 9.702 49.351 ;
     RECT  10.584 49.171 10.782 49.351 ;
     RECT  12.312 48.029 24.297 49.351 ;
     RECT  224.568 49.085 225.918 49.373 ;
     RECT  6.444 48.811 8.73 49.435 ;
     RECT  9.504 49.351 10.782 49.435 ;
     RECT  5.22 49.351 5.526 49.441 ;
     RECT  4.572 49.441 5.526 49.505 ;
     RECT  0.54 49.477 0.558 49.565 ;
     RECT  41.04 49.085 41.634 49.565 ;
     RECT  224.568 49.373 224.586 49.565 ;
     RECT  218.844 49.477 218.862 49.661 ;
     RECT  6.444 49.435 10.782 49.775 ;
     RECT  225.72 49.373 225.918 49.855 ;
     RECT  226.872 49.435 226.89 49.883 ;
     RECT  5.508 49.505 5.526 49.891 ;
     RECT  32.184 48.659 32.202 49.891 ;
     RECT  38.196 49.549 38.214 49.981 ;
     RECT  32.184 49.891 32.274 50.008 ;
     RECT  5.508 49.891 5.742 50.009 ;
     RECT  6.984 49.775 10.782 50.009 ;
     RECT  32.112 50.008 32.274 50.011 ;
     RECT  4.572 49.505 4.59 50.045 ;
     RECT  30.78 49.477 30.798 50.045 ;
     RECT  32.04 50.011 32.274 50.045 ;
     RECT  225.72 49.855 226.026 50.045 ;
     RECT  7.38 50.009 8.097 50.051 ;
     RECT  38.196 49.981 38.286 50.117 ;
     RECT  38.196 50.117 38.214 50.141 ;
     RECT  222.3 49.711 222.318 50.141 ;
     RECT  39.924 49.277 39.942 50.251 ;
     RECT  3.528 50.125 3.546 50.315 ;
     RECT  39.852 50.251 39.942 50.333 ;
     RECT  32.04 50.045 32.202 50.351 ;
     RECT  224.532 50.323 224.55 50.395 ;
     RECT  32.184 50.351 32.202 50.423 ;
     RECT  226.296 50.203 226.854 50.423 ;
     RECT  39.888 50.333 39.942 50.429 ;
     RECT  41.616 49.565 41.634 50.521 ;
     RECT  224.532 50.395 224.586 50.525 ;
     RECT  9.144 50.009 10.782 50.549 ;
     RECT  9.144 50.549 10.638 50.585 ;
     RECT  41.616 50.521 41.706 50.621 ;
     RECT  224.028 50.557 224.046 50.621 ;
     RECT  34.776 50.521 34.794 50.657 ;
     RECT  2.415 47.345 2.697 50.701 ;
     RECT  11.664 49.351 24.297 50.701 ;
     RECT  2.415 50.701 3.006 50.819 ;
     RECT  4.464 50.155 4.482 50.819 ;
     RECT  225.144 50.779 225.162 50.819 ;
     RECT  41.616 50.621 41.634 50.827 ;
     RECT  5.508 50.009 5.526 50.855 ;
     RECT  226.296 50.423 226.314 50.863 ;
     RECT  7.488 50.051 8.097 50.971 ;
     RECT  29.415 48.119 29.697 51.061 ;
     RECT  4.788 50.971 5.238 51.089 ;
     RECT  38.772 51.061 38.79 51.101 ;
     RECT  0.108 50.008 0.126 51.125 ;
     RECT  4.032 50.971 4.05 51.125 ;
     RECT  29.124 51.061 29.697 51.161 ;
     RECT  32.22 51.133 32.238 51.269 ;
     RECT  38.196 51.133 38.214 51.293 ;
     RECT  225.468 50.863 226.314 51.331 ;
     RECT  6.228 50.935 6.246 51.355 ;
     RECT  6.984 50.971 8.097 51.355 ;
     RECT  9.396 50.585 10.638 51.355 ;
     RECT  11.412 50.701 24.297 51.355 ;
     RECT  222.3 51.259 222.318 51.355 ;
     RECT  41.58 50.827 41.634 51.367 ;
     RECT  39.924 50.429 39.942 51.389 ;
     RECT  5.22 51.089 5.238 51.395 ;
     RECT  41.04 51.367 41.634 51.403 ;
     RECT  225.468 51.331 226.386 51.431 ;
     RECT  0.54 51.367 0.558 51.437 ;
     RECT  34.704 51.367 34.722 51.503 ;
     RECT  6.228 51.355 8.097 51.511 ;
     RECT  9.396 51.355 24.297 51.511 ;
     RECT  222.3 51.355 222.858 51.581 ;
     RECT  3.744 51.511 3.762 51.665 ;
     RECT  6.228 51.511 24.297 51.701 ;
     RECT  225.468 51.431 226.314 51.739 ;
     RECT  41.04 51.403 41.67 51.773 ;
     RECT  225.144 51.739 226.314 51.899 ;
     RECT  39.348 51.871 39.366 51.907 ;
     RECT  6.984 51.701 8.097 51.935 ;
     RECT  38.808 51.907 39.366 51.965 ;
     RECT  40.428 51.835 40.446 51.971 ;
     RECT  41.616 51.773 41.67 52.123 ;
     RECT  34.848 52.141 34.866 52.277 ;
     RECT  32.184 51.943 32.202 52.285 ;
     RECT  2.415 50.819 2.697 52.363 ;
     RECT  28.26 52.321 28.278 52.439 ;
     RECT  31.5 52.285 32.202 52.439 ;
     RECT  41.616 52.123 42.174 52.439 ;
     RECT  37.62 51.637 37.638 52.445 ;
     RECT  225.504 51.899 226.314 52.448 ;
     RECT  3.96 52.285 4.338 52.475 ;
     RECT  8.856 51.701 24.297 52.475 ;
     RECT  225.504 52.448 225.81 52.541 ;
     RECT  41.616 52.439 41.67 52.603 ;
     RECT  5.112 52.411 5.13 52.681 ;
     RECT  32.112 52.439 32.202 52.681 ;
     RECT  39.348 51.965 39.366 52.733 ;
     RECT  2.304 52.363 2.697 52.745 ;
     RECT  32.112 52.681 32.238 52.789 ;
     RECT  6.228 51.701 6.246 52.825 ;
     RECT  7.092 51.935 8.097 52.825 ;
     RECT  32.112 52.789 32.274 52.825 ;
     RECT  41.58 52.603 41.67 52.829 ;
     RECT  4.644 52.681 5.13 52.861 ;
     RECT  6.228 52.825 8.097 52.861 ;
     RECT  32.112 52.825 32.346 52.889 ;
     RECT  43.2 44.765 214.488 52.951 ;
     RECT  4.644 52.861 5.274 52.979 ;
     RECT  6.048 52.861 8.097 52.979 ;
     RECT  30.852 52.789 30.87 52.979 ;
     RECT  32.184 52.889 32.346 52.979 ;
     RECT  29.415 51.161 29.697 52.987 ;
     RECT  3.888 52.861 3.906 53.015 ;
     RECT  5.112 52.979 5.166 53.021 ;
     RECT  38.196 52.981 38.214 53.021 ;
     RECT  226.764 52.987 226.782 53.024 ;
     RECT  32.328 52.979 32.346 53.051 ;
     RECT  42.768 52.951 214.488 53.117 ;
     RECT  28.728 52.987 29.697 53.123 ;
     RECT  6.804 52.979 8.097 53.371 ;
     RECT  225.72 52.541 225.81 53.371 ;
     RECT  34.776 53.221 34.794 53.429 ;
     RECT  225.72 53.371 225.954 53.467 ;
     RECT  29.415 53.123 29.697 53.491 ;
     RECT  225.72 53.467 226.314 53.563 ;
     RECT  29.415 53.491 29.826 53.591 ;
     RECT  39.924 52.861 39.942 53.693 ;
     RECT  41.58 52.829 41.634 53.752 ;
     RECT  6.804 53.371 8.226 53.789 ;
     RECT  37.62 53.557 37.638 53.885 ;
     RECT  2.415 52.745 2.697 53.941 ;
     RECT  6.984 53.789 8.226 53.941 ;
     RECT  9.036 52.475 24.297 53.941 ;
     RECT  222.3 51.581 222.318 54.043 ;
     RECT  2.415 53.941 2.826 54.059 ;
     RECT  5.148 53.021 5.166 54.103 ;
     RECT  225.684 53.563 226.314 54.103 ;
     RECT  3.996 54.091 4.014 54.131 ;
     RECT  34.848 54.031 34.866 54.131 ;
     RECT  41.58 53.752 42.174 54.284 ;
     RECT  32.184 53.761 32.202 54.301 ;
     RECT  32.184 54.301 32.274 54.337 ;
     RECT  6.984 53.941 24.297 54.365 ;
     RECT  31.392 54.211 31.41 54.365 ;
     RECT  39.852 54.256 39.906 54.427 ;
     RECT  34.704 54.211 34.794 54.437 ;
     RECT  41.58 54.284 41.634 54.437 ;
     RECT  5.148 54.103 5.742 54.445 ;
     RECT  32.184 54.337 32.31 54.473 ;
     RECT  5.112 54.445 5.742 54.481 ;
     RECT  5.112 54.481 6.066 54.509 ;
     RECT  32.292 54.473 32.31 54.509 ;
     RECT  222.3 54.043 222.822 54.523 ;
     RECT  38.808 54.301 38.826 54.557 ;
     RECT  225.576 54.103 226.314 54.571 ;
     RECT  4.248 54.481 4.266 54.635 ;
     RECT  41.616 54.437 41.634 54.653 ;
     RECT  225.504 54.571 226.314 54.653 ;
     RECT  222.3 54.523 222.858 54.671 ;
     RECT  5.256 54.509 6.066 54.715 ;
     RECT  6.984 54.365 8.73 54.715 ;
     RECT  5.256 54.715 8.73 54.749 ;
     RECT  225.504 54.653 225.882 54.749 ;
     RECT  39.852 54.427 40.446 54.845 ;
     RECT  7.668 54.749 8.73 54.869 ;
     RECT  34.776 54.437 34.794 54.941 ;
     RECT  38.196 54.841 38.214 54.941 ;
     RECT  2.415 54.059 2.697 55.021 ;
     RECT  42.156 55.099 42.174 55.111 ;
     RECT  2.415 55.021 3.15 55.139 ;
     RECT  0.108 51.883 0.126 55.229 ;
     RECT  32.328 54.607 32.346 55.291 ;
     RECT  40.428 54.845 40.446 55.319 ;
     RECT  39.348 54.877 39.366 55.381 ;
     RECT  225.684 54.749 225.882 55.387 ;
     RECT  2.415 55.139 2.862 55.409 ;
     RECT  5.256 54.749 6.894 55.409 ;
     RECT  42.156 55.111 42.21 55.421 ;
     RECT  5.256 55.409 6.066 55.445 ;
     RECT  30.78 55.291 30.798 55.445 ;
     RECT  32.328 55.291 32.382 55.445 ;
     RECT  42.156 55.421 42.174 55.453 ;
     RECT  32.328 55.445 32.346 55.517 ;
     RECT  41.616 55.453 42.174 55.517 ;
     RECT  5.256 55.445 5.742 55.553 ;
     RECT  6.84 55.409 6.894 55.561 ;
     RECT  7.668 54.869 8.406 55.561 ;
     RECT  34.74 55.291 34.758 55.589 ;
     RECT  2.415 55.409 2.697 55.675 ;
     RECT  222.3 54.671 222.318 55.771 ;
     RECT  225.684 55.387 226.314 55.901 ;
     RECT  9.684 54.365 24.297 55.949 ;
     RECT  38.808 55.381 39.366 55.957 ;
     RECT  2.412 55.675 2.697 55.985 ;
     RECT  6.84 55.561 8.406 55.985 ;
     RECT  38.772 55.957 39.366 56.093 ;
     RECT  5.256 55.553 5.562 56.101 ;
     RECT  30.888 55.921 30.906 56.129 ;
     RECT  42.12 55.517 42.174 56.129 ;
     RECT  225.828 55.901 226.314 56.129 ;
     RECT  40.464 55.921 40.482 56.189 ;
     RECT  31.932 56.101 32.274 56.219 ;
     RECT  42.12 56.129 42.138 56.219 ;
     RECT  39.348 56.093 39.366 56.285 ;
     RECT  30.78 56.227 30.798 56.327 ;
     RECT  32.256 56.219 32.274 56.327 ;
     RECT  4.896 56.101 5.562 56.371 ;
     RECT  7.02 55.985 8.406 56.371 ;
     RECT  222.3 55.771 222.858 56.381 ;
     RECT  4.5 56.371 6.246 56.489 ;
     RECT  37.584 55.771 37.602 56.489 ;
     RECT  34.74 56.461 34.758 56.497 ;
     RECT  4.5 56.489 4.518 56.525 ;
     RECT  7.02 56.371 8.622 56.525 ;
     RECT  41.58 56.443 41.598 56.525 ;
     RECT  34.704 56.497 34.758 56.597 ;
     RECT  34.704 56.597 34.722 56.669 ;
     RECT  40.428 56.347 40.446 56.759 ;
     RECT  7.815 56.525 8.622 56.795 ;
     RECT  9.684 55.949 9.702 56.795 ;
     RECT  225.864 56.129 226.314 56.875 ;
     RECT  5.364 56.489 6.246 56.911 ;
     RECT  7.02 56.525 7.038 56.911 ;
     RECT  29.415 53.591 29.697 56.923 ;
     RECT  225.864 56.875 226.854 56.957 ;
     RECT  10.584 55.949 24.297 57.001 ;
     RECT  225.864 56.957 226.314 57.019 ;
     RECT  222.3 56.381 222.318 57.181 ;
     RECT  43.2 53.117 214.488 57.211 ;
     RECT  222.3 57.181 222.858 57.245 ;
     RECT  225.792 57.019 226.314 57.299 ;
     RECT  225.792 57.299 225.918 57.343 ;
     RECT  43.092 57.211 214.488 57.389 ;
     RECT  10.584 57.001 24.786 57.403 ;
     RECT  5.364 56.911 7.038 57.451 ;
     RECT  7.815 56.795 8.154 57.451 ;
     RECT  29.415 56.923 29.826 57.479 ;
     RECT  5.148 57.451 8.154 57.541 ;
     RECT  27.036 57.307 27.054 57.541 ;
     RECT  2.415 55.985 2.697 57.547 ;
     RECT  3.42 57.451 3.798 57.569 ;
     RECT  29.415 57.479 29.79 57.569 ;
     RECT  3.924 57.577 3.942 57.595 ;
     RECT  4.86 57.541 8.226 57.595 ;
     RECT  28.404 57.355 28.422 57.595 ;
     RECT  2.304 57.547 2.697 57.605 ;
     RECT  3.924 57.595 8.226 57.629 ;
     RECT  222.3 57.245 222.354 57.641 ;
     RECT  4.356 57.629 8.226 57.839 ;
     RECT  9.036 56.911 9.054 57.839 ;
     RECT  6.732 57.839 8.226 57.875 ;
     RECT  27.036 57.541 27.414 57.883 ;
     RECT  26.568 57.883 27.414 57.979 ;
     RECT  41.868 57.787 41.886 58.075 ;
     RECT  225.684 57.343 225.918 58.075 ;
     RECT  225.684 58.075 226.314 58.117 ;
     RECT  4.356 57.839 5.886 58.168 ;
     RECT  225.468 58.117 226.314 58.205 ;
     RECT  225.54 58.205 226.314 58.301 ;
     RECT  43.2 57.389 214.488 58.411 ;
     RECT  41.868 58.075 41.958 58.459 ;
     RECT  43.092 58.411 214.488 58.459 ;
     RECT  6.912 57.875 8.226 58.531 ;
     RECT  4.86 58.168 5.886 58.685 ;
     RECT  229.215 2.413 229.497 58.693 ;
     RECT  6.912 58.531 8.478 58.801 ;
     RECT  229.215 58.693 229.626 58.829 ;
     RECT  6.912 58.801 8.658 58.843 ;
     RECT  225.648 58.301 226.314 58.843 ;
     RECT  225.648 58.843 226.53 58.973 ;
     RECT  9.576 57.991 9.594 58.987 ;
     RECT  10.584 57.403 25.362 58.987 ;
     RECT  222.3 57.641 222.318 59.029 ;
     RECT  222.3 59.029 222.858 59.069 ;
     RECT  6.804 58.843 8.658 59.071 ;
     RECT  9.576 58.987 25.362 59.071 ;
     RECT  5.076 58.685 5.886 59.161 ;
     RECT  6.804 59.071 25.362 59.161 ;
     RECT  225.756 58.973 226.53 59.225 ;
     RECT  225.756 59.225 225.99 59.357 ;
     RECT  5.076 59.161 25.362 59.419 ;
     RECT  4.356 59.419 25.362 59.495 ;
     RECT  29.415 57.569 29.754 59.539 ;
     RECT  29.415 59.539 29.79 59.645 ;
     RECT  226.836 59.575 226.854 59.645 ;
     RECT  225.756 59.357 225.774 59.737 ;
     RECT  4.356 59.495 4.59 59.837 ;
     RECT  5.364 59.495 25.362 60.035 ;
     RECT  225.54 59.737 225.774 60.115 ;
     RECT  2.415 57.605 2.697 60.151 ;
     RECT  225.54 60.115 225.882 60.221 ;
     RECT  225.54 60.221 225.774 60.377 ;
     RECT  4.572 59.837 4.59 60.413 ;
     RECT  29.415 59.645 29.697 60.475 ;
     RECT  5.364 60.035 5.382 60.539 ;
     RECT  0.108 56.155 0.126 60.575 ;
     RECT  225.684 60.377 225.774 60.605 ;
     RECT  222.3 59.069 222.318 60.655 ;
     RECT  2.415 60.151 2.79 60.691 ;
     RECT  6.3 60.035 25.362 60.781 ;
     RECT  2.415 60.691 3.222 60.809 ;
     RECT  0.54 60.817 0.558 60.893 ;
     RECT  226.836 60.817 226.854 60.893 ;
     RECT  5.58 60.781 25.362 61.079 ;
     RECT  5.58 61.079 6.642 61.115 ;
     RECT  225.792 61.051 226.062 61.223 ;
     RECT  6.336 61.115 6.642 61.229 ;
     RECT  225.828 61.223 226.062 61.357 ;
     RECT  7.416 61.079 25.362 61.385 ;
     RECT  2.415 60.809 3.186 61.619 ;
     RECT  225.828 61.357 226.314 61.661 ;
     RECT  4.608 61.771 4.626 61.819 ;
     RECT  3.672 61.771 3.69 61.853 ;
     RECT  222.3 60.655 222.858 61.853 ;
     RECT  6.336 61.229 6.498 61.925 ;
     RECT  4.572 61.819 4.626 62.041 ;
     RECT  6.372 61.925 6.498 62.041 ;
     RECT  26.352 57.979 27.414 62.203 ;
     RECT  28.188 57.595 28.422 62.203 ;
     RECT  226.296 61.661 226.314 62.237 ;
     RECT  7.815 61.385 25.362 62.299 ;
     RECT  26.352 62.203 28.422 62.299 ;
     RECT  6.372 62.041 6.57 62.311 ;
     RECT  7.815 62.299 28.422 62.311 ;
     RECT  226.836 62.275 226.854 62.333 ;
     RECT  4.572 62.041 4.734 62.509 ;
     RECT  225.684 62.545 225.702 62.671 ;
     RECT  41.868 58.459 214.488 62.683 ;
     RECT  4.572 62.509 5.166 62.707 ;
     RECT  4.464 62.707 5.166 62.735 ;
     RECT  4.464 62.735 4.662 62.807 ;
     RECT  29.415 60.475 29.898 62.807 ;
     RECT  30.672 62.683 30.798 62.861 ;
     RECT  34.74 62.683 34.866 62.861 ;
     RECT  38.772 62.683 38.79 62.861 ;
     RECT  41.868 62.683 214.578 62.861 ;
     RECT  218.268 62.683 218.286 62.861 ;
     RECT  225.576 62.671 225.702 62.968 ;
     RECT  0.108 61.339 0.126 63.005 ;
     RECT  4.464 62.807 4.626 63.005 ;
     RECT  29.415 62.807 29.862 63.005 ;
     RECT  2.415 61.619 2.697 63.049 ;
     RECT  6.372 62.311 28.422 63.049 ;
     RECT  222.3 61.853 222.354 63.067 ;
     RECT  6.336 63.049 28.422 63.121 ;
     RECT  2.415 63.049 3.366 63.149 ;
     RECT  5.724 63.121 28.422 63.149 ;
     RECT  29.415 63.005 29.79 63.149 ;
     RECT  222.3 63.067 222.858 63.149 ;
     RECT  5.724 63.149 6.354 63.239 ;
     RECT  2.415 63.149 2.697 63.247 ;
     RECT  4.464 63.005 4.482 63.275 ;
     RECT  29.415 63.149 29.754 63.275 ;
     RECT  1.728 63.247 2.697 63.293 ;
     RECT  225.576 62.968 225.774 63.293 ;
     RECT  225.684 63.293 225.774 63.355 ;
     RECT  7.092 63.149 28.422 63.545 ;
     RECT  222.3 63.149 222.354 63.617 ;
     RECT  225.684 63.355 225.81 63.643 ;
     RECT  5.724 63.239 6.282 63.779 ;
     RECT  227.088 63.739 227.106 63.779 ;
     RECT  3.708 63.931 3.726 64.049 ;
     RECT  3.564 64.201 3.582 64.253 ;
     RECT  225.684 63.643 226.314 64.291 ;
     RECT  225.612 64.291 226.314 64.319 ;
     RECT  6.264 63.779 6.282 64.327 ;
     RECT  0.108 63.739 0.126 64.355 ;
     RECT  7.416 63.545 28.422 64.471 ;
     RECT  225.612 64.319 225.882 64.637 ;
     RECT  0.54 64.651 0.558 64.733 ;
     RECT  29.415 63.275 29.697 64.795 ;
     RECT  226.836 64.741 226.854 64.829 ;
     RECT  4.716 64.201 4.734 64.939 ;
     RECT  6.264 64.327 6.318 64.987 ;
     RECT  29.415 64.795 29.754 65.083 ;
     RECT  225.864 64.637 225.882 65.083 ;
     RECT  6.12 64.987 6.318 65.129 ;
     RECT  225.864 65.083 226.35 65.18 ;
     RECT  32.472 63.739 32.49 65.273 ;
     RECT  2.415 63.293 2.697 65.281 ;
     RECT  7.236 64.471 28.422 65.281 ;
     RECT  4.716 64.939 4.95 65.371 ;
     RECT  4.716 65.371 5.31 65.509 ;
     RECT  225.864 65.18 226.314 65.515 ;
     RECT  4.356 65.509 5.31 65.549 ;
     RECT  6.12 65.129 6.138 65.549 ;
     RECT  0.108 65.128 0.126 65.705 ;
     RECT  4.932 65.549 5.31 65.705 ;
     RECT  222.3 63.617 222.318 65.755 ;
     RECT  2.415 65.281 2.79 65.821 ;
     RECT  225.684 65.515 226.314 65.939 ;
     RECT  2.415 65.821 3.15 65.975 ;
     RECT  2.415 65.975 2.697 66.091 ;
     RECT  3.816 66.055 3.834 66.125 ;
     RECT  29.415 65.083 29.79 66.139 ;
     RECT  225.684 65.939 225.918 66.245 ;
     RECT  225.684 66.245 225.882 66.269 ;
     RECT  7.092 65.281 28.422 66.361 ;
     RECT  226.656 66.331 226.746 66.389 ;
     RECT  41.868 62.861 214.488 66.427 ;
     RECT  226.656 66.389 226.674 66.461 ;
     RECT  222.3 65.755 222.354 66.595 ;
     RECT  5.076 65.705 5.31 66.631 ;
     RECT  6.732 66.361 28.422 66.631 ;
     RECT  222.3 66.595 222.858 66.653 ;
     RECT  5.076 66.631 5.346 66.749 ;
     RECT  2.304 66.091 2.697 66.785 ;
     RECT  6.588 66.631 28.422 66.785 ;
     RECT  225.864 66.269 225.882 66.785 ;
     RECT  5.112 66.749 5.346 66.901 ;
     RECT  2.415 66.785 2.697 67.051 ;
     RECT  5.112 66.901 5.382 67.055 ;
     RECT  226.836 67.135 226.854 67.229 ;
     RECT  225.936 66.991 225.954 67.291 ;
     RECT  2.415 67.051 2.754 67.325 ;
     RECT  5.292 67.055 5.382 67.441 ;
     RECT  222.3 66.653 222.318 67.441 ;
     RECT  225.936 67.291 226.314 67.559 ;
     RECT  225.792 67.567 225.81 67.613 ;
     RECT  4.212 67.243 4.23 67.711 ;
     RECT  5.292 67.441 5.454 67.711 ;
     RECT  5.292 67.711 5.598 67.801 ;
     RECT  3.816 67.711 4.23 67.819 ;
     RECT  3.708 67.819 4.23 67.853 ;
     RECT  3.708 67.853 3.942 67.865 ;
     RECT  222.3 67.441 222.858 68.009 ;
     RECT  226.692 67.981 226.854 68.093 ;
     RECT  3.816 67.865 3.942 68.099 ;
     RECT  3.816 68.099 3.834 68.135 ;
     RECT  226.692 68.093 226.71 68.243 ;
     RECT  5.292 67.801 5.778 68.251 ;
     RECT  225.72 68.215 225.738 68.341 ;
     RECT  225.72 68.341 225.882 68.377 ;
     RECT  5.148 68.251 5.778 68.405 ;
     RECT  5.328 68.405 5.778 68.521 ;
     RECT  6.732 66.785 28.422 68.521 ;
     RECT  228.204 68.341 228.222 68.549 ;
     RECT  225.468 68.377 225.882 68.573 ;
     RECT  29.415 66.139 29.934 68.827 ;
     RECT  225.648 68.573 225.882 68.917 ;
     RECT  29.415 68.827 29.97 68.945 ;
     RECT  228.276 68.791 228.294 68.945 ;
     RECT  225.648 68.917 226.314 68.957 ;
     RECT  29.415 68.945 29.934 69.017 ;
     RECT  225.648 68.957 225.738 69.053 ;
     RECT  2.415 67.325 2.697 69.061 ;
     RECT  2.415 69.061 2.754 69.179 ;
     RECT  222.3 68.009 222.318 69.259 ;
     RECT  222.3 69.259 222.822 69.331 ;
     RECT  4.14 69.163 4.158 69.421 ;
     RECT  5.328 68.521 28.422 69.421 ;
     RECT  29.415 69.017 29.898 69.437 ;
     RECT  3.42 69.421 4.158 69.449 ;
     RECT  0.108 67.483 0.126 69.485 ;
     RECT  225.684 69.053 225.738 69.485 ;
     RECT  29.415 69.437 29.79 69.521 ;
     RECT  3.42 69.449 3.438 69.755 ;
     RECT  2.415 69.179 2.697 69.883 ;
     RECT  5.076 69.421 28.422 69.979 ;
     RECT  29.415 69.521 29.697 69.979 ;
     RECT  2.304 69.883 2.697 70.295 ;
     RECT  222.3 69.331 222.858 70.331 ;
     RECT  225.756 69.691 226.314 70.403 ;
     RECT  3.744 70.339 3.762 70.411 ;
     RECT  5.076 69.979 29.697 70.411 ;
     RECT  225.756 70.403 225.882 70.501 ;
     RECT  3.744 70.411 29.697 70.529 ;
     RECT  225.504 70.501 225.882 70.565 ;
     RECT  225.504 70.565 225.522 70.609 ;
     RECT  226.836 70.537 226.998 70.637 ;
     RECT  225.144 70.609 225.522 70.781 ;
     RECT  4.068 70.529 4.806 71.069 ;
     RECT  4.068 71.069 4.698 71.105 ;
     RECT  222.3 70.331 222.39 71.227 ;
     RECT  0.108 70.363 0.126 71.375 ;
     RECT  5.58 70.529 29.697 71.455 ;
     RECT  225.72 71.311 225.738 71.515 ;
     RECT  4.68 71.105 4.698 71.645 ;
     RECT  226.836 70.637 226.854 71.645 ;
     RECT  2.415 70.295 2.697 71.755 ;
     RECT  225.72 71.515 225.882 71.761 ;
     RECT  5.436 71.455 29.697 71.837 ;
     RECT  2.304 71.755 2.697 71.915 ;
     RECT  5.58 71.837 29.697 71.915 ;
     RECT  222.3 71.227 222.858 72.125 ;
     RECT  222.3 72.125 222.354 72.23 ;
     RECT  225.684 71.761 225.882 72.463 ;
     RECT  225.684 72.463 226.314 72.509 ;
     RECT  5.796 71.915 29.697 72.689 ;
     RECT  222.3 72.23 222.318 72.959 ;
     RECT  4.356 72.955 4.374 72.995 ;
     RECT  225.684 72.509 225.774 73.237 ;
     RECT  2.415 71.915 2.697 73.381 ;
     RECT  222.84 73.381 222.858 73.469 ;
     RECT  5.292 72.931 5.31 73.483 ;
     RECT  6.192 72.689 29.697 73.483 ;
     RECT  2.415 73.381 2.934 73.499 ;
     RECT  225.684 73.237 226.314 73.507 ;
     RECT  5.292 73.483 29.697 73.535 ;
     RECT  4.536 73.507 4.554 73.921 ;
     RECT  5.292 73.535 5.418 73.921 ;
     RECT  225.576 73.507 226.314 74.011 ;
     RECT  6.192 73.535 6.534 74.075 ;
     RECT  225.504 74.011 226.314 74.083 ;
     RECT  3.96 73.921 5.418 74.141 ;
     RECT  6.444 74.075 6.534 74.389 ;
     RECT  7.416 73.535 29.697 74.389 ;
     RECT  3.96 74.141 4.806 74.461 ;
     RECT  3.636 74.461 4.806 74.551 ;
     RECT  5.58 74.461 5.598 74.615 ;
     RECT  6.444 74.389 29.697 74.651 ;
     RECT  225.144 74.083 226.314 74.717 ;
     RECT  3.42 74.551 4.806 74.759 ;
     RECT  4.284 74.759 4.806 74.849 ;
     RECT  6.444 74.651 6.462 74.849 ;
     RECT  3.42 74.759 3.438 74.885 ;
     RECT  225.684 74.717 226.314 74.971 ;
     RECT  225.684 74.971 226.458 75.119 ;
     RECT  225.684 75.119 226.386 75.191 ;
     RECT  6.3 74.965 6.318 75.245 ;
     RECT  222.3 74.299 222.318 75.355 ;
     RECT  4.284 74.849 4.698 75.425 ;
     RECT  4.536 75.425 4.698 75.437 ;
     RECT  5.616 75.541 5.634 75.581 ;
     RECT  225.684 75.191 226.314 75.581 ;
     RECT  225.684 75.581 225.954 75.775 ;
     RECT  7.236 74.651 29.697 75.901 ;
     RECT  4.536 75.437 4.554 75.965 ;
     RECT  225.576 75.775 225.954 75.965 ;
     RECT  6.84 75.901 29.697 76.001 ;
     RECT  222.3 75.355 222.354 76.027 ;
     RECT  2.415 73.499 2.697 76.081 ;
     RECT  2.415 76.081 3.006 76.199 ;
     RECT  225.648 75.965 225.954 76.309 ;
     RECT  225.648 76.309 225.99 76.603 ;
     RECT  225.648 76.603 226.314 76.621 ;
     RECT  225.648 76.621 226.854 76.733 ;
     RECT  4.464 76.363 4.482 76.891 ;
     RECT  5.544 75.931 5.562 76.891 ;
     RECT  4.284 76.891 4.626 77.009 ;
     RECT  225.648 76.733 226.314 77.017 ;
     RECT  0.108 73.195 0.126 77.045 ;
     RECT  4.284 77.009 4.518 77.045 ;
     RECT  5.544 76.891 5.598 77.045 ;
     RECT  5.58 77.045 5.598 77.161 ;
     RECT  222.3 76.027 222.858 77.189 ;
     RECT  225.612 77.017 226.314 77.213 ;
     RECT  5.58 77.161 5.778 77.279 ;
     RECT  2.415 76.199 2.697 77.419 ;
     RECT  2.412 77.419 2.697 77.585 ;
     RECT  225.612 77.213 225.954 77.597 ;
     RECT  222.3 77.189 222.318 77.935 ;
     RECT  4.464 77.045 4.518 77.971 ;
     RECT  5.58 77.279 5.598 77.971 ;
     RECT  5.4 77.971 5.598 78.029 ;
     RECT  5.58 78.029 5.598 78.061 ;
     RECT  222.3 77.935 222.858 78.077 ;
     RECT  3.852 77.971 4.626 78.089 ;
     RECT  5.58 78.061 5.742 78.125 ;
     RECT  225.792 77.597 225.954 78.269 ;
     RECT  5.724 78.125 5.742 78.331 ;
     RECT  3.852 78.089 4.554 78.395 ;
     RECT  5.724 78.331 5.778 78.395 ;
     RECT  222.3 78.077 222.354 78.503 ;
     RECT  2.415 77.585 2.697 78.511 ;
     RECT  7.236 76.001 29.697 78.601 ;
     RECT  2.415 78.511 2.79 78.629 ;
     RECT  225.792 78.269 225.882 78.637 ;
     RECT  3.852 78.395 4.446 78.667 ;
     RECT  3.816 78.667 4.446 78.899 ;
     RECT  222.3 78.503 222.318 78.899 ;
     RECT  226.836 77.935 226.854 79.133 ;
     RECT  3.816 78.899 4.014 79.169 ;
     RECT  5.724 78.395 5.742 79.169 ;
     RECT  225.684 78.637 225.882 79.177 ;
     RECT  3.816 79.169 3.906 79.205 ;
     RECT  6.768 78.601 29.697 79.213 ;
     RECT  4.788 79.141 4.806 79.241 ;
     RECT  225.468 79.177 225.918 79.325 ;
     RECT  0.108 78.367 0.126 79.475 ;
     RECT  222.336 79.387 222.354 79.555 ;
     RECT  2.415 78.629 2.697 79.681 ;
     RECT  2.415 79.681 3.114 79.717 ;
     RECT  222.336 79.555 222.858 79.717 ;
     RECT  3.888 79.205 3.906 79.745 ;
     RECT  1.728 79.717 3.114 79.853 ;
     RECT  225.72 79.325 225.918 79.867 ;
     RECT  2.415 79.853 3.114 79.979 ;
     RECT  225.72 79.867 226.314 79.979 ;
     RECT  225.72 79.979 225.882 80.123 ;
     RECT  5.76 79.213 29.697 80.285 ;
     RECT  5.76 80.285 6.282 80.357 ;
     RECT  3.852 80.221 3.87 80.555 ;
     RECT  5.76 80.357 5.778 80.671 ;
     RECT  225.684 80.293 225.702 80.797 ;
     RECT  0.108 80.248 0.126 80.825 ;
     RECT  225.54 80.797 225.702 80.897 ;
     RECT  5.4 80.671 5.778 80.923 ;
     RECT  225.684 80.897 225.702 80.923 ;
     RECT  2.415 79.979 2.697 80.941 ;
     RECT  4.464 80.635 4.482 80.957 ;
     RECT  225.684 80.923 225.954 81.053 ;
     RECT  2.415 80.941 3.402 81.059 ;
     RECT  225.72 81.053 225.954 81.203 ;
     RECT  7.236 80.285 29.697 81.211 ;
     RECT  5.256 80.923 5.778 81.341 ;
     RECT  5.4 81.341 5.778 81.509 ;
     RECT  225.828 81.203 225.954 81.595 ;
     RECT  5.4 81.509 5.418 81.635 ;
     RECT  225.828 81.595 226.314 81.635 ;
     RECT  6.696 81.211 29.697 81.751 ;
     RECT  225.792 81.976 225.81 82.021 ;
     RECT  225.684 82.021 225.81 82.109 ;
     RECT  6.444 81.751 29.697 82.139 ;
     RECT  226.836 82.255 226.854 82.301 ;
     RECT  226.296 82.552 226.314 82.589 ;
     RECT  225.144 82.561 225.162 82.685 ;
     RECT  6.696 82.139 29.697 82.715 ;
     RECT  227.88 83.101 227.898 83.219 ;
     RECT  222.3 79.717 222.858 83.597 ;
     RECT  225.468 83.101 225.738 83.605 ;
     RECT  226.872 83.641 226.89 83.707 ;
     RECT  226.872 83.707 226.962 83.795 ;
     RECT  225.468 83.605 225.81 84.145 ;
     RECT  225.468 84.145 225.918 84.221 ;
     RECT  222.3 83.597 222.354 84.371 ;
     RECT  225.468 84.221 225.81 84.413 ;
     RECT  225.648 84.413 225.81 84.569 ;
     RECT  226.692 84.667 226.71 84.685 ;
     RECT  226.62 84.685 226.71 84.713 ;
     RECT  226.62 84.713 226.638 84.797 ;
     RECT  225.648 84.569 225.666 84.989 ;
     RECT  222.3 84.371 222.318 85.243 ;
     RECT  222.3 85.243 222.858 85.487 ;
     RECT  225.864 85.339 225.882 85.621 ;
     RECT  30.708 85.483 30.726 85.819 ;
     RECT  30.708 85.819 31.014 85.919 ;
     RECT  225.864 85.621 226.314 85.927 ;
     RECT  30.78 85.919 30.798 85.949 ;
     RECT  225.684 85.927 226.314 86.027 ;
     RECT  222.3 85.487 222.318 86.395 ;
     RECT  222.3 86.395 222.858 86.525 ;
     RECT  225.936 86.027 226.314 86.683 ;
     RECT  225.936 86.683 226.494 86.729 ;
     RECT  225.792 86.779 225.81 87.151 ;
     RECT  226.836 87.151 226.854 87.197 ;
     RECT  222.804 86.525 222.858 87.547 ;
     RECT  225.612 87.151 225.81 87.547 ;
     RECT  225.612 87.547 225.918 87.691 ;
     RECT  229.215 58.829 229.497 87.739 ;
     RECT  228.6 87.739 229.497 87.809 ;
     RECT  225.576 87.691 225.918 87.869 ;
     RECT  222.3 87.547 222.858 88.061 ;
     RECT  225.648 87.869 225.918 88.087 ;
     RECT  226.764 87.931 226.782 88.115 ;
     RECT  225.648 88.087 225.99 88.445 ;
     RECT  225.684 88.445 225.99 88.861 ;
     RECT  225.684 88.861 226.242 88.925 ;
     RECT  228.168 88.231 228.186 89.033 ;
     RECT  225.684 88.925 225.81 89.659 ;
     RECT  225.684 89.659 226.314 89.941 ;
     RECT  225.504 89.941 226.314 90.365 ;
     RECT  225.504 90.365 225.918 90.481 ;
     RECT  222.3 88.061 222.318 90.523 ;
     RECT  222.3 90.523 222.354 90.581 ;
     RECT  225.468 90.481 225.918 91.133 ;
     RECT  226.836 91.003 226.854 91.157 ;
     RECT  225.468 91.133 225.702 91.613 ;
     RECT  2.415 81.059 2.697 91.669 ;
     RECT  222.3 90.581 222.318 91.675 ;
     RECT  2.415 91.669 2.718 91.741 ;
     RECT  225.648 91.613 225.702 91.805 ;
     RECT  225.684 91.805 225.702 91.963 ;
     RECT  1.728 91.741 2.718 92.093 ;
     RECT  2.34 92.093 2.718 92.101 ;
     RECT  2.34 92.101 3.006 92.129 ;
     RECT  7.236 82.715 29.697 92.245 ;
     RECT  225.684 91.963 225.918 92.245 ;
     RECT  226.836 92.155 226.854 92.245 ;
     RECT  225.684 92.245 226.854 92.273 ;
     RECT  2.415 92.129 3.006 92.281 ;
     RECT  222.3 91.675 222.354 92.347 ;
     RECT  7.056 92.245 29.697 92.551 ;
     RECT  225.684 92.273 226.638 92.573 ;
     RECT  222.3 92.347 222.858 92.579 ;
     RECT  2.415 92.281 3.222 92.669 ;
     RECT  6.408 92.551 29.697 92.669 ;
     RECT  0.108 92.551 0.126 92.717 ;
     RECT  4.356 92.911 4.374 92.923 ;
     RECT  7.056 92.669 29.697 92.957 ;
     RECT  225.792 92.573 226.638 93.053 ;
     RECT  4.356 92.923 4.41 93.119 ;
     RECT  0.54 93.259 0.558 93.389 ;
     RECT  2.415 92.669 3.114 93.479 ;
     RECT  222.3 92.579 222.318 93.499 ;
     RECT  225.792 93.053 226.314 93.725 ;
     RECT  2.415 93.479 3.042 93.829 ;
     RECT  4.392 93.119 4.41 93.901 ;
     RECT  222.3 93.499 222.858 93.917 ;
     RECT  225.792 93.725 225.81 93.991 ;
     RECT  2.304 93.829 3.042 94.019 ;
     RECT  4.068 93.901 4.41 94.019 ;
     RECT  5.472 93.901 5.49 94.055 ;
     RECT  4.392 94.019 4.41 94.061 ;
     RECT  225.684 93.991 225.81 94.063 ;
     RECT  227.952 93.991 227.97 94.091 ;
     RECT  7.236 92.957 29.697 94.369 ;
     RECT  222.3 93.917 222.39 94.433 ;
     RECT  7.164 94.369 29.697 94.441 ;
     RECT  0.108 93.835 0.126 94.493 ;
     RECT  6.228 94.369 6.246 94.555 ;
     RECT  7.092 94.441 29.697 94.555 ;
     RECT  2.415 94.019 2.934 94.595 ;
     RECT  6.228 94.555 29.697 94.595 ;
     RECT  225.648 94.063 225.81 94.603 ;
     RECT  225.504 94.603 225.81 94.739 ;
     RECT  225.684 94.739 225.81 94.747 ;
     RECT  6.228 94.595 6.246 94.901 ;
     RECT  3.78 94.801 3.798 94.981 ;
     RECT  225.684 94.747 226.314 95.035 ;
     RECT  227.16 94.981 227.178 95.035 ;
     RECT  0.54 94.801 0.558 95.069 ;
     RECT  225.684 95.035 227.178 95.135 ;
     RECT  4.716 94.603 4.734 95.179 ;
     RECT  225.684 95.135 226.314 95.453 ;
     RECT  3.708 94.981 3.798 95.485 ;
     RECT  4.572 95.179 4.734 95.485 ;
     RECT  222.3 94.433 222.354 95.485 ;
     RECT  222.3 95.485 222.858 95.645 ;
     RECT  225.684 95.453 225.918 95.647 ;
     RECT  3.708 95.485 4.734 95.675 ;
     RECT  2.415 94.595 2.862 95.683 ;
     RECT  3.708 95.675 4.302 95.683 ;
     RECT  2.415 95.683 4.302 95.909 ;
     RECT  226.836 96.025 226.854 96.187 ;
     RECT  3.816 95.909 4.302 96.215 ;
     RECT  0.108 95.611 0.126 96.269 ;
     RECT  226.836 96.187 226.998 96.287 ;
     RECT  3.816 96.215 4.158 96.323 ;
     RECT  2.415 95.909 2.862 96.485 ;
     RECT  7.236 94.595 29.697 96.601 ;
     RECT  6.768 96.601 29.697 96.835 ;
     RECT  226.836 96.287 226.854 96.863 ;
     RECT  3.708 96.835 3.726 96.989 ;
     RECT  225.468 95.647 225.918 96.989 ;
     RECT  225.792 96.989 225.918 96.997 ;
     RECT  222.3 95.645 222.318 97.141 ;
     RECT  2.415 96.485 2.826 97.231 ;
     RECT  6.624 96.835 29.697 97.259 ;
     RECT  222.3 97.141 222.354 97.375 ;
     RECT  2.415 97.231 2.898 97.387 ;
     RECT  2.304 97.387 2.898 97.411 ;
     RECT  6.804 97.259 29.697 97.469 ;
     RECT  222.3 97.375 222.858 97.469 ;
     RECT  2.304 97.411 3.582 97.529 ;
     RECT  41.292 66.427 214.488 97.537 ;
     RECT  225.792 96.997 226.314 97.853 ;
     RECT  227.484 98.011 227.502 98.105 ;
     RECT  225.792 97.853 225.882 98.141 ;
     RECT  2.304 97.529 3.402 98.249 ;
     RECT  4.572 98.299 4.59 98.347 ;
     RECT  4.572 98.347 4.734 98.491 ;
     RECT  0.108 98.581 0.126 98.621 ;
     RECT  4.572 98.491 5.274 98.731 ;
     RECT  4.572 98.731 5.814 98.765 ;
     RECT  226.836 98.455 226.854 98.813 ;
     RECT  2.376 98.249 3.402 98.879 ;
     RECT  7.236 97.469 29.697 98.959 ;
     RECT  225.72 98.395 225.738 98.971 ;
     RECT  222.3 97.469 222.318 98.995 ;
     RECT  2.412 98.879 3.402 99.031 ;
     RECT  5.796 98.765 5.814 99.031 ;
     RECT  4.392 98.959 4.518 99.149 ;
     RECT  5.796 99.031 5.994 99.149 ;
     RECT  6.768 98.959 29.697 99.149 ;
     RECT  225.72 98.971 225.81 99.157 ;
     RECT  5.796 99.149 5.814 99.185 ;
     RECT  225.144 99.157 225.99 99.197 ;
     RECT  225.54 99.197 225.99 99.259 ;
     RECT  2.412 99.031 3.438 99.301 ;
     RECT  2.412 99.301 3.726 99.455 ;
     RECT  222.3 98.995 222.858 99.677 ;
     RECT  2.412 99.455 3.294 99.733 ;
     RECT  225.54 99.259 226.314 99.773 ;
     RECT  7.236 99.149 29.697 99.883 ;
     RECT  6.912 99.883 29.697 99.959 ;
     RECT  225.648 99.773 226.314 100.219 ;
     RECT  225.648 100.219 226.53 100.265 ;
     RECT  2.268 99.733 3.294 100.273 ;
     RECT  2.268 100.273 3.438 100.409 ;
     RECT  2.415 100.409 3.438 100.499 ;
     RECT  2.415 100.499 3.15 100.571 ;
     RECT  222.3 99.677 222.354 100.615 ;
     RECT  4.14 100.615 4.158 100.685 ;
     RECT  225.648 100.265 226.314 100.777 ;
     RECT  222.3 100.615 222.858 100.877 ;
     RECT  225.468 100.777 226.314 100.925 ;
     RECT  5.436 100.921 5.454 101.039 ;
     RECT  225.684 100.925 226.314 101.083 ;
     RECT  7.236 99.959 29.697 101.191 ;
     RECT  5.256 101.155 5.274 101.213 ;
     RECT  6.948 101.191 29.697 101.275 ;
     RECT  6.804 101.275 29.697 101.315 ;
     RECT  2.415 100.571 3.006 101.461 ;
     RECT  225.684 101.083 226.854 101.789 ;
     RECT  225.684 101.789 226.314 102.001 ;
     RECT  225.504 102.001 226.314 102.077 ;
     RECT  2.415 101.461 3.294 102.163 ;
     RECT  222.3 100.877 222.318 102.331 ;
     RECT  2.415 102.163 3.402 102.389 ;
     RECT  5.472 102.361 5.49 102.533 ;
     RECT  4.464 102.505 4.482 102.541 ;
     RECT  0.54 100.939 0.558 102.569 ;
     RECT  225.72 102.077 226.314 102.659 ;
     RECT  2.415 102.389 2.862 102.715 ;
     RECT  4.464 102.541 5.13 102.731 ;
     RECT  226.836 102.775 226.854 102.941 ;
     RECT  225.72 102.659 225.738 102.973 ;
     RECT  4.464 102.731 4.59 103.171 ;
     RECT  2.376 102.715 2.862 103.199 ;
     RECT  4.428 103.171 4.59 103.291 ;
     RECT  2.415 103.199 2.862 103.351 ;
     RECT  3.996 103.291 4.59 103.351 ;
     RECT  2.415 103.351 4.59 103.373 ;
     RECT  2.415 103.373 4.446 103.469 ;
     RECT  30.708 103.195 30.726 103.469 ;
     RECT  225.684 102.973 225.738 103.513 ;
     RECT  229.215 87.809 229.497 103.513 ;
     RECT  39.6 100.003 39.618 103.549 ;
     RECT  225.684 103.513 226.278 103.613 ;
     RECT  31.608 96.061 31.626 103.621 ;
     RECT  4.428 103.469 4.446 103.649 ;
     RECT  222.3 102.331 222.858 103.649 ;
     RECT  229.068 103.513 229.497 103.649 ;
     RECT  225.684 103.613 225.882 103.711 ;
     RECT  31.608 103.621 32.274 103.757 ;
     RECT  7.236 101.315 29.697 103.891 ;
     RECT  7.056 103.891 29.697 103.963 ;
     RECT  6.912 103.963 29.697 104.009 ;
     RECT  37.872 101.857 37.89 104.017 ;
     RECT  39.024 103.549 39.618 104.017 ;
     RECT  2.415 103.469 3.69 104.053 ;
     RECT  36.756 102.163 36.774 104.053 ;
     RECT  37.872 104.017 39.618 104.053 ;
     RECT  0.54 103.915 0.558 104.189 ;
     RECT  225.648 103.711 225.882 104.251 ;
     RECT  2.304 104.053 3.69 104.315 ;
     RECT  31.608 103.757 31.626 104.359 ;
     RECT  225.504 104.251 225.882 104.381 ;
     RECT  2.376 104.315 3.69 104.549 ;
     RECT  225.504 104.381 225.522 104.573 ;
     RECT  226.836 104.443 226.854 104.585 ;
     RECT  225.468 104.923 225.486 104.963 ;
     RECT  226.656 104.701 226.674 105.097 ;
     RECT  222.3 103.649 222.318 105.211 ;
     RECT  2.376 104.549 3.618 105.331 ;
     RECT  226.296 105.097 226.674 105.331 ;
     RECT  2.304 105.331 3.618 105.359 ;
     RECT  225.684 105.331 226.674 105.403 ;
     RECT  2.304 105.359 3.294 105.437 ;
     RECT  225.684 105.403 226.782 105.44 ;
     RECT  7.236 104.009 29.697 105.475 ;
     RECT  31.032 104.359 31.626 105.475 ;
     RECT  225.684 105.44 226.314 105.533 ;
     RECT  222.3 105.211 222.354 105.595 ;
     RECT  2.304 105.437 3.006 105.665 ;
     RECT  5.364 105.511 5.382 105.745 ;
     RECT  5.22 105.745 5.382 105.821 ;
     RECT  7.236 105.475 31.626 106.051 ;
     RECT  2.415 105.665 3.006 106.285 ;
     RECT  7.092 106.051 31.626 106.285 ;
     RECT  225.864 105.533 226.314 106.321 ;
     RECT  0.54 105.067 0.558 106.349 ;
     RECT  225.864 106.321 226.854 106.397 ;
     RECT  2.415 106.285 3.258 106.439 ;
     RECT  5.436 106.321 5.454 106.439 ;
     RECT  6.948 106.285 31.626 106.619 ;
     RECT  2.415 106.439 3.006 106.681 ;
     RECT  40.716 97.537 214.488 106.747 ;
     RECT  0.108 106.843 0.126 106.889 ;
     RECT  225.864 106.397 226.314 106.939 ;
     RECT  2.376 106.681 3.006 106.951 ;
     RECT  6.948 106.619 29.697 106.979 ;
     RECT  225.72 106.939 226.314 106.979 ;
     RECT  5.004 106.861 5.022 107.131 ;
     RECT  2.304 106.951 3.006 107.159 ;
     RECT  2.304 107.159 2.697 107.285 ;
     RECT  225.792 106.979 226.314 107.555 ;
     RECT  4.932 107.131 5.022 107.671 ;
     RECT  4.932 107.671 5.31 107.755 ;
     RECT  4.356 107.755 5.742 107.761 ;
     RECT  4.356 107.761 5.886 107.789 ;
     RECT  5.724 107.789 5.886 107.795 ;
     RECT  3.456 107.671 3.474 107.825 ;
     RECT  4.356 107.789 4.95 107.825 ;
     RECT  2.415 107.285 2.697 107.905 ;
     RECT  40.428 106.747 214.488 107.933 ;
     RECT  225.828 107.555 226.314 107.969 ;
     RECT  3.96 107.905 3.978 108.203 ;
     RECT  0.54 107.401 0.558 108.239 ;
     RECT  5.868 107.795 5.886 108.239 ;
     RECT  7.308 106.979 29.697 108.301 ;
     RECT  30.42 106.619 31.626 108.301 ;
     RECT  2.415 107.905 3.042 108.445 ;
     RECT  7.308 108.301 31.626 108.445 ;
     RECT  2.304 108.445 3.042 108.571 ;
     RECT  6.732 108.445 31.626 108.643 ;
     RECT  0.108 108.619 0.126 108.707 ;
     RECT  6.552 108.643 31.626 108.749 ;
     RECT  6.588 108.749 31.626 108.779 ;
     RECT  2.304 108.571 3.186 108.905 ;
     RECT  225.864 107.969 226.314 108.989 ;
     RECT  4.932 107.825 4.95 109.291 ;
     RECT  225.72 109.183 225.738 109.381 ;
     RECT  229.215 103.649 229.497 109.381 ;
     RECT  225.684 109.381 225.738 109.417 ;
     RECT  2.304 108.905 2.697 109.445 ;
     RECT  229.032 109.381 229.497 109.481 ;
     RECT  225.468 109.417 225.738 109.565 ;
     RECT  4.932 109.291 5.13 109.651 ;
     RECT  4.896 109.651 5.13 109.709 ;
     RECT  225.54 109.565 225.738 109.723 ;
     RECT  2.415 109.445 2.697 109.759 ;
     RECT  3.42 109.243 3.438 109.759 ;
     RECT  36.756 104.053 39.618 109.795 ;
     RECT  222.3 105.595 222.858 109.853 ;
     RECT  225.54 109.723 225.918 109.915 ;
     RECT  2.415 109.759 3.438 110.011 ;
     RECT  4.932 109.709 5.13 110.011 ;
     RECT  0.54 109.819 0.558 110.021 ;
     RECT  36.756 109.795 39.654 110.029 ;
     RECT  2.415 110.011 4.05 110.065 ;
     RECT  4.932 110.011 5.562 110.101 ;
     RECT  4.932 110.101 5.706 110.191 ;
     RECT  2.415 110.065 4.194 110.219 ;
     RECT  225.54 109.915 226.314 110.237 ;
     RECT  4.932 110.191 5.778 110.263 ;
     RECT  6.66 108.779 31.626 110.263 ;
     RECT  2.415 110.219 2.718 110.395 ;
     RECT  4.932 110.263 31.626 110.489 ;
     RECT  225.54 110.237 226.098 110.497 ;
     RECT  225.468 110.497 226.098 110.533 ;
     RECT  229.215 109.481 229.497 110.533 ;
     RECT  6.336 110.489 31.626 110.561 ;
     RECT  36.756 110.029 39.69 110.605 ;
     RECT  225.396 110.533 226.098 110.669 ;
     RECT  228.744 110.533 229.497 110.669 ;
     RECT  225.468 110.669 226.098 110.717 ;
     RECT  227.448 110.491 227.466 110.759 ;
     RECT  36.756 110.605 39.942 110.813 ;
     RECT  6.408 110.561 31.626 110.909 ;
     RECT  2.304 110.395 2.718 110.939 ;
     RECT  3.456 110.219 4.194 111.001 ;
     RECT  4.932 110.489 5.598 111.001 ;
     RECT  2.376 110.939 2.718 111.037 ;
     RECT  3.456 111.001 5.598 111.037 ;
     RECT  222.3 109.853 222.318 111.067 ;
     RECT  0.108 111.019 0.126 111.101 ;
     RECT  222.3 111.067 222.354 111.137 ;
     RECT  225.684 110.717 226.098 111.259 ;
     RECT  6.732 110.909 31.626 111.335 ;
     RECT  30.42 111.335 31.626 111.479 ;
     RECT  229.215 110.669 229.497 111.613 ;
     RECT  36.756 110.813 39.69 111.685 ;
     RECT  228.744 111.613 229.497 111.749 ;
     RECT  225.684 111.259 226.314 111.773 ;
     RECT  225.72 111.773 226.314 112.061 ;
     RECT  36.504 111.685 39.69 112.261 ;
     RECT  226.368 112.219 226.386 112.289 ;
     RECT  223.416 112.261 223.434 112.349 ;
     RECT  34.452 111.001 34.47 112.351 ;
     RECT  34.2 112.351 34.47 112.445 ;
     RECT  34.272 112.445 34.47 112.487 ;
     RECT  2.376 111.037 5.598 112.495 ;
     RECT  6.732 111.335 29.697 112.495 ;
     RECT  222.3 111.137 222.318 112.495 ;
     RECT  30.708 111.479 31.626 112.531 ;
     RECT  35.928 112.261 39.69 112.541 ;
     RECT  2.376 112.495 29.697 112.657 ;
     RECT  30.636 112.531 31.626 112.685 ;
     RECT  226.62 112.603 226.638 112.685 ;
     RECT  30.78 112.685 31.626 112.757 ;
     RECT  0.108 112.699 0.126 112.829 ;
     RECT  2.304 112.657 29.697 112.919 ;
     RECT  227.988 112.801 228.006 112.925 ;
     RECT  22.68 112.919 29.697 112.939 ;
     RECT  22.68 112.939 29.79 113.117 ;
     RECT  229.215 111.749 229.497 113.179 ;
     RECT  36.468 112.541 39.69 113.225 ;
     RECT  225.54 112.795 225.558 113.225 ;
     RECT  229.14 113.179 229.497 113.225 ;
     RECT  2.304 112.919 21.87 113.459 ;
     RECT  22.68 113.117 29.697 113.459 ;
     RECT  226.26 113.431 226.278 113.531 ;
     RECT  2.415 113.459 21.87 113.597 ;
     RECT  2.415 113.597 20.574 113.729 ;
     RECT  22.68 113.459 26.01 113.729 ;
     RECT  2.415 113.729 16.434 113.765 ;
     RECT  222.3 112.495 222.858 113.765 ;
     RECT  22.788 113.729 26.01 113.801 ;
     RECT  26.748 113.459 29.697 113.801 ;
     RECT  227.412 113.737 227.43 113.837 ;
     RECT  222.804 113.765 222.858 113.885 ;
     RECT  222.84 113.885 222.858 113.971 ;
     RECT  222.84 113.971 223.47 113.981 ;
     RECT  21.456 113.597 21.87 113.999 ;
     RECT  26.82 113.801 29.697 113.999 ;
     RECT  21.456 113.999 21.762 114.077 ;
     RECT  223.452 113.981 223.47 114.077 ;
     RECT  224.604 114.139 224.622 114.151 ;
     RECT  224.604 114.151 224.658 114.235 ;
     RECT  229.215 113.225 229.497 114.277 ;
     RECT  228.924 114.277 229.497 114.365 ;
     RECT  224.604 114.235 224.694 114.413 ;
     RECT  225.684 114.151 225.702 114.421 ;
     RECT  224.604 114.413 224.658 114.461 ;
     RECT  225.684 114.421 225.918 114.511 ;
     RECT  225.504 114.511 225.918 114.539 ;
     RECT  0.54 113.341 0.558 114.557 ;
     RECT  224.604 114.461 224.622 114.557 ;
     RECT  27 113.999 29.697 114.583 ;
     RECT  27 114.583 29.754 114.611 ;
     RECT  21.744 114.077 21.762 114.653 ;
     RECT  2.415 113.765 16.218 114.817 ;
     RECT  22.86 113.801 26.01 114.941 ;
     RECT  228.168 114.907 228.186 114.953 ;
     RECT  2.415 114.817 16.254 115.123 ;
     RECT  225.504 114.539 225.846 115.133 ;
     RECT  2.268 115.123 16.254 115.181 ;
     RECT  222.3 115.291 222.318 115.387 ;
     RECT  223.416 115.123 223.434 115.387 ;
     RECT  225.684 115.133 225.846 115.457 ;
     RECT  225.72 115.457 225.846 115.501 ;
     RECT  36.756 113.225 39.69 115.613 ;
     RECT  2.34 115.181 16.254 115.619 ;
     RECT  222.3 115.387 223.434 115.619 ;
     RECT  225.72 115.501 226.278 115.655 ;
     RECT  222.84 115.619 223.434 115.709 ;
     RECT  27.324 114.611 29.754 115.723 ;
     RECT  27.324 115.723 29.79 115.901 ;
     RECT  223.452 115.867 223.47 116.041 ;
     RECT  21.6 115.723 21.618 116.159 ;
     RECT  225.72 115.655 225.738 116.203 ;
     RECT  228.096 116.131 228.114 116.231 ;
     RECT  2.34 115.619 15.39 116.239 ;
     RECT  225.612 116.203 225.738 116.303 ;
     RECT  34.452 112.487 34.47 116.477 ;
     RECT  2.268 116.239 15.39 116.671 ;
     RECT  225.684 116.303 225.738 116.923 ;
     RECT  1.728 116.671 15.39 116.957 ;
     RECT  225.684 116.923 225.774 116.977 ;
     RECT  223.452 116.041 224.01 117.005 ;
     RECT  223.488 117.005 224.01 117.019 ;
     RECT  17.388 113.729 20.574 117.121 ;
     RECT  27.324 115.901 29.697 117.121 ;
     RECT  225.684 116.977 226.242 117.205 ;
     RECT  223.488 117.019 224.694 117.239 ;
     RECT  225.684 117.205 226.278 117.245 ;
     RECT  36.756 115.613 39.654 117.341 ;
     RECT  225.684 117.245 225.702 117.517 ;
     RECT  32.76 107.257 32.778 117.533 ;
     RECT  224.028 117.239 224.694 117.617 ;
     RECT  225.612 117.517 225.702 117.617 ;
     RECT  225.684 117.617 225.702 117.629 ;
     RECT  2.304 116.957 15.39 117.689 ;
     RECT  224.028 117.617 224.658 117.692 ;
     RECT  224.028 117.692 224.622 117.779 ;
     RECT  31.032 112.757 31.626 117.821 ;
     RECT  36.756 117.341 39.618 117.917 ;
     RECT  36.756 117.917 38.466 118.205 ;
     RECT  36.756 118.205 37.89 118.301 ;
     RECT  0.108 117.499 0.126 118.319 ;
     RECT  26.856 117.121 29.697 118.363 ;
     RECT  226.296 117.979 226.314 118.363 ;
     RECT  36.756 118.301 37.314 118.397 ;
     RECT  226.296 118.363 226.35 118.4 ;
     RECT  36.756 118.397 36.774 118.493 ;
     RECT  2.415 117.689 15.39 118.741 ;
     RECT  40.716 107.933 214.488 118.781 ;
     RECT  2.304 118.741 15.39 118.859 ;
     RECT  31.608 117.821 31.626 118.859 ;
     RECT  41.364 118.781 214.488 118.877 ;
     RECT  22.86 114.941 25.974 118.903 ;
     RECT  26.748 118.363 29.697 118.903 ;
     RECT  39.6 117.917 39.618 118.973 ;
     RECT  0.54 118.699 0.558 119.039 ;
     RECT  41.364 118.877 41.958 119.069 ;
     RECT  225.756 118.555 225.774 119.131 ;
     RECT  42.768 118.877 214.488 119.165 ;
     RECT  225.684 119.131 225.774 119.165 ;
     RECT  16.2 115.619 16.254 119.173 ;
     RECT  2.415 118.859 15.39 119.209 ;
     RECT  16.2 119.173 16.434 119.209 ;
     RECT  22.86 118.903 29.697 119.209 ;
     RECT  224.028 117.779 224.55 119.227 ;
     RECT  225.684 119.165 225.702 119.227 ;
     RECT  2.415 119.209 16.434 119.281 ;
     RECT  41.364 119.069 41.454 119.357 ;
     RECT  2.415 119.281 16.47 119.371 ;
     RECT  17.388 117.121 20.79 119.371 ;
     RECT  22.824 119.209 29.697 119.399 ;
     RECT  41.364 119.357 41.382 119.453 ;
     RECT  28.692 119.399 29.697 119.471 ;
     RECT  38.232 119.371 38.25 119.515 ;
     RECT  43.2 119.165 214.488 119.515 ;
     RECT  224.028 119.227 225.702 119.543 ;
     RECT  28.98 119.471 29.697 119.551 ;
     RECT  30.528 119.515 30.546 119.551 ;
     RECT  28.98 119.551 30.546 119.641 ;
     RECT  39.924 119.551 39.942 119.645 ;
     RECT  28.98 119.641 30.726 119.669 ;
     RECT  30.708 119.669 30.726 119.693 ;
     RECT  32.256 119.659 32.274 119.705 ;
     RECT  224.028 119.543 224.118 119.705 ;
     RECT  38.196 119.515 38.25 119.741 ;
     RECT  22.824 119.399 27.81 119.749 ;
     RECT  43.2 119.515 214.614 119.803 ;
     RECT  38.7 119.803 38.718 119.821 ;
     RECT  22.32 119.749 27.81 119.939 ;
     RECT  224.064 119.705 224.118 119.939 ;
     RECT  38.7 119.821 39.366 119.975 ;
     RECT  28.98 119.669 29.754 120.011 ;
     RECT  39.348 119.975 39.366 120.029 ;
     RECT  30.78 119.911 30.87 120.083 ;
     RECT  224.064 119.939 224.082 120.083 ;
     RECT  22.32 119.939 25.974 120.091 ;
     RECT  43.2 119.803 214.758 120.091 ;
     RECT  29.415 120.011 29.754 120.119 ;
     RECT  30.78 120.083 30.798 120.119 ;
     RECT  22.212 120.091 25.974 120.245 ;
     RECT  26.784 119.939 27.594 120.281 ;
     RECT  27.576 120.281 27.594 120.515 ;
     RECT  40.428 120.091 40.446 120.515 ;
     RECT  22.644 120.245 25.974 120.551 ;
     RECT  26.784 120.281 26.802 120.587 ;
     RECT  2.415 119.371 20.79 120.749 ;
     RECT  225.144 119.543 225.702 120.785 ;
     RECT  43.2 120.091 214.866 120.984 ;
     RECT  220.608 119.323 220.626 121.019 ;
     RECT  225.144 120.785 225.558 121.559 ;
     RECT  2.415 120.749 14.742 121.711 ;
     RECT  2.304 121.711 14.742 121.829 ;
     RECT  225.504 121.559 225.558 121.865 ;
     RECT  2.304 121.829 14.526 122.369 ;
     RECT  0.108 119.275 0.126 122.549 ;
     RECT  2.415 122.369 14.526 122.639 ;
     RECT  225.504 121.865 225.522 122.639 ;
     RECT  0.54 122.827 0.558 123.089 ;
     RECT  2.415 122.639 13.497 123.151 ;
     RECT  2.304 123.151 13.497 123.449 ;
     RECT  2.415 123.449 13.497 123.719 ;
     RECT  2.415 123.719 11.862 124.681 ;
     RECT  2.34 124.681 11.862 124.799 ;
     RECT  2.376 124.799 11.862 125.339 ;
     RECT  0.108 123.403 0.126 125.837 ;
     RECT  15.804 120.749 20.79 126.257 ;
     RECT  12.744 123.719 13.497 126.265 ;
     RECT  14.22 122.639 14.526 126.265 ;
     RECT  0.54 126.193 0.558 126.413 ;
     RECT  0.108 126.931 0.126 126.989 ;
     RECT  0.54 127.471 0.558 127.565 ;
     RECT  0.108 128.011 0.126 128.189 ;
     RECT  0.54 128.659 0.558 128.765 ;
     RECT  2.415 125.339 11.862 129.307 ;
     RECT  0.54 130.441 0.558 130.541 ;
     RECT  2.304 129.307 11.862 130.555 ;
     RECT  12.744 126.265 14.526 130.555 ;
     RECT  2.304 130.555 14.526 130.981 ;
     RECT  43.236 131.755 43.254 131.899 ;
     RECT  214.524 120.984 214.866 131.971 ;
     RECT  214.344 131.971 214.866 131.999 ;
     RECT  43.236 131.899 43.542 132.089 ;
     RECT  214.344 131.999 214.758 132.125 ;
     RECT  214.56 132.125 214.686 132.197 ;
     RECT  35.007 132.013 35.097 132.283 ;
     RECT  40.407 132.013 40.497 132.283 ;
     RECT  45.807 132.013 45.897 132.283 ;
     RECT  51.207 132.013 51.297 132.283 ;
     RECT  56.607 132.013 56.697 132.283 ;
     RECT  62.007 132.013 62.097 132.283 ;
     RECT  67.407 132.013 67.497 132.283 ;
     RECT  72.807 132.013 72.897 132.283 ;
     RECT  78.207 132.013 78.297 132.283 ;
     RECT  83.607 132.013 83.697 132.283 ;
     RECT  89.007 132.013 89.097 132.283 ;
     RECT  94.407 132.013 94.497 132.283 ;
     RECT  99.807 132.013 99.897 132.283 ;
     RECT  105.207 132.013 105.297 132.283 ;
     RECT  110.607 132.013 110.697 132.283 ;
     RECT  116.007 132.013 116.097 132.283 ;
     RECT  121.407 132.013 121.497 132.283 ;
     RECT  126.807 132.013 126.897 132.283 ;
     RECT  132.207 132.013 132.297 132.283 ;
     RECT  137.607 132.013 137.697 132.283 ;
     RECT  143.007 132.013 143.097 132.283 ;
     RECT  148.407 132.013 148.497 132.283 ;
     RECT  153.807 132.013 153.897 132.283 ;
     RECT  159.207 132.013 159.297 132.283 ;
     RECT  164.607 132.013 164.697 132.283 ;
     RECT  170.007 132.013 170.097 132.283 ;
     RECT  175.407 132.013 175.497 132.283 ;
     RECT  180.807 132.013 180.897 132.283 ;
     RECT  186.207 132.013 186.297 132.283 ;
     RECT  191.607 132.013 191.697 132.283 ;
     RECT  197.007 132.013 197.097 132.283 ;
     RECT  202.407 132.013 202.497 132.283 ;
     RECT  207.807 132.013 207.897 132.283 ;
     RECT  213.207 132.013 213.297 132.283 ;
     RECT  218.607 132.013 218.697 132.283 ;
     RECT  224.007 132.013 224.097 132.283 ;
     RECT  1.728 130.981 14.526 132.893 ;
     RECT  0.108 133.483 0.126 133.547 ;
     RECT  2.304 132.893 14.526 133.709 ;
     RECT  0.54 134.059 0.558 134.429 ;
     RECT  2.415 133.709 14.526 134.491 ;
     RECT  1.728 134.491 14.526 134.669 ;
     RECT  22.86 120.551 25.974 134.825 ;
     RECT  0.108 135.259 0.126 135.329 ;
     RECT  2.415 134.669 14.526 135.571 ;
     RECT  1.728 135.571 14.526 135.869 ;
     RECT  0.108 136.381 0.126 136.445 ;
     RECT  23.292 134.825 25.974 136.949 ;
     RECT  2.415 135.869 14.526 137.101 ;
     RECT  2.304 137.101 14.526 137.219 ;
     RECT  2.415 137.219 14.526 138.721 ;
     RECT  2.34 138.721 14.526 138.839 ;
     RECT  0.108 137.461 0.126 139.421 ;
     RECT  2.412 138.839 14.526 139.649 ;
     RECT  0.54 140.533 0.558 140.573 ;
     RECT  2.415 139.649 14.526 141.163 ;
     RECT  2.304 141.163 14.526 141.539 ;
     RECT  0.54 141.619 0.558 141.773 ;
     RECT  2.415 141.539 14.526 141.989 ;
     RECT  2.415 141.989 9.738 142.315 ;
     RECT  2.304 142.315 9.738 143.339 ;
     RECT  2.415 143.339 9.738 144.121 ;
     RECT  2.34 144.121 9.738 144.239 ;
     RECT  23.616 136.949 25.974 144.509 ;
     RECT  0.54 144.481 0.558 144.749 ;
     RECT  2.415 144.239 9.738 145.471 ;
     RECT  0.108 145.021 0.126 145.901 ;
     RECT  2.304 145.471 9.738 146.443 ;
     RECT  1.728 146.443 9.738 147.101 ;
     RECT  2.268 147.101 9.738 147.677 ;
     RECT  0.108 148.261 0.126 148.877 ;
     RECT  2.415 147.677 9.738 150.449 ;
     RECT  2.415 150.449 4.374 150.461 ;
     RECT  0.108 150.043 0.126 150.827 ;
     RECT  2.415 150.461 3.834 150.997 ;
     RECT  5.4 150.449 9.738 151.979 ;
     RECT  2.304 150.997 3.834 152.339 ;
     RECT  2.304 152.339 3.618 152.525 ;
     RECT  0.54 151.195 0.558 152.681 ;
     RECT  5.4 151.979 7.002 152.879 ;
     RECT  4.716 152.995 4.734 153.053 ;
     RECT  7.815 151.979 9.738 153.059 ;
     RECT  2.304 152.525 3.51 153.571 ;
     RECT  2.304 153.571 3.618 153.599 ;
     RECT  2.34 153.599 3.618 153.833 ;
     RECT  2.34 153.833 3.33 154.031 ;
     RECT  5.472 152.879 7.002 154.111 ;
     RECT  7.815 153.059 8.097 154.111 ;
     RECT  8.892 153.059 9.738 154.111 ;
     RECT  0.54 154.111 0.558 154.205 ;
     RECT  4.896 154.111 7.002 154.219 ;
     RECT  7.815 154.111 9.738 154.219 ;
     RECT  4.896 154.219 9.738 154.229 ;
     RECT  5.4 154.229 8.097 154.265 ;
     RECT  2.415 154.031 3.33 154.843 ;
     RECT  4.32 154.849 4.338 154.921 ;
     RECT  2.415 154.843 3.438 154.949 ;
     RECT  2.415 154.949 3.33 155.039 ;
     RECT  5.4 154.265 7.002 155.039 ;
     RECT  4.248 154.921 4.338 155.155 ;
     RECT  4.248 155.155 4.59 155.191 ;
     RECT  4.068 155.191 4.59 155.213 ;
     RECT  0.108 154.747 0.126 155.489 ;
     RECT  2.415 155.039 3.078 156.001 ;
     RECT  4.068 155.213 4.266 156.001 ;
     RECT  0.54 155.947 0.558 156.029 ;
     RECT  2.415 156.001 3.222 156.091 ;
     RECT  3.96 156.001 4.266 156.091 ;
     RECT  2.415 156.091 4.266 156.119 ;
     RECT  2.415 156.119 3.294 156.191 ;
     RECT  23.616 144.509 25.794 156.497 ;
     RECT  5.904 155.039 7.002 156.541 ;
     RECT  0.108 156.523 0.126 156.569 ;
     RECT  5.904 156.541 7.038 156.631 ;
     RECT  8.892 154.229 9.738 156.659 ;
     RECT  7.815 154.265 8.097 156.703 ;
     RECT  2.415 156.191 3.222 156.731 ;
     RECT  5.508 156.631 7.038 156.731 ;
     RECT  10.512 141.989 14.526 156.731 ;
     RECT  4.248 156.119 4.266 156.763 ;
     RECT  2.415 156.731 3.078 156.901 ;
     RECT  5.508 156.731 7.002 157.307 ;
     RECT  4.248 156.763 4.662 157.351 ;
     RECT  7.815 156.703 8.586 157.379 ;
     RECT  4.248 157.351 5.022 157.469 ;
     RECT  2.304 156.901 3.078 157.621 ;
     RECT  2.304 157.621 3.15 157.775 ;
     RECT  0.54 157.081 0.558 157.811 ;
     RECT  4.248 157.469 4.842 158.093 ;
     RECT  2.304 157.775 3.078 158.189 ;
     RECT  11.844 156.731 14.526 158.189 ;
     RECT  5.904 157.307 7.002 158.279 ;
     RECT  4.248 158.093 4.266 158.431 ;
     RECT  0.108 158.299 0.126 158.459 ;
     RECT  3.816 158.431 4.266 158.693 ;
     RECT  5.904 158.279 6.858 158.819 ;
     RECT  2.415 158.189 3.078 158.827 ;
     RECT  2.415 158.827 3.402 158.971 ;
     RECT  2.412 158.971 3.402 159.475 ;
     RECT  2.376 159.475 3.402 159.511 ;
     RECT  4.248 158.693 4.266 159.511 ;
     RECT  0.108 159.499 0.126 159.539 ;
     RECT  5.904 158.819 6.678 159.547 ;
     RECT  2.376 159.511 4.266 159.781 ;
     RECT  10.512 156.731 11.106 160.169 ;
     RECT  2.304 159.781 4.266 160.241 ;
     RECT  10.62 160.169 11.106 160.439 ;
     RECT  5.58 159.547 6.678 160.733 ;
     RECT  10.62 160.439 11.07 160.979 ;
     RECT  7.815 157.379 8.097 161.131 ;
     RECT  2.304 160.241 3.402 161.221 ;
     RECT  4.176 160.241 4.266 161.221 ;
     RECT  7.56 161.131 8.097 161.321 ;
     RECT  2.304 161.221 4.266 161.789 ;
     RECT  5.148 161.671 5.166 161.789 ;
     RECT  9.54 156.659 9.738 161.789 ;
     RECT  0.54 161.833 0.558 161.885 ;
     RECT  4.248 161.789 4.266 161.941 ;
     RECT  4.248 161.941 4.302 162.059 ;
     RECT  5.904 160.733 6.678 162.283 ;
     RECT  5.616 162.283 6.678 162.329 ;
     RECT  12.24 158.189 14.526 162.329 ;
     RECT  2.304 161.789 3.438 162.571 ;
     RECT  4.248 162.059 4.266 162.571 ;
     RECT  5.904 162.329 6.678 162.715 ;
     RECT  7.815 161.321 8.097 162.715 ;
     RECT  23.616 156.497 24.714 162.743 ;
     RECT  2.304 162.571 4.266 162.869 ;
     RECT  23.616 162.743 24.297 163.049 ;
     RECT  5.904 162.715 8.097 163.409 ;
     RECT  2.304 162.869 2.697 163.445 ;
     RECT  5.904 163.409 7.074 163.565 ;
     RECT  0.108 163.051 0.126 163.627 ;
     RECT  3.42 162.869 4.266 163.751 ;
     RECT  2.415 163.445 2.697 163.795 ;
     RECT  3.42 163.751 3.438 163.795 ;
     RECT  10.62 160.979 10.638 164.219 ;
     RECT  0.108 163.627 0.558 164.327 ;
     RECT  4.248 163.751 4.266 164.335 ;
     RECT  5.904 163.565 6.678 164.491 ;
     RECT  5.652 164.491 6.678 164.531 ;
     RECT  5.904 164.531 6.678 164.633 ;
     RECT  0.54 164.327 0.558 164.939 ;
     RECT  2.415 163.795 3.438 165.001 ;
     RECT  2.415 165.001 3.51 165.181 ;
     RECT  4.248 164.335 4.554 165.181 ;
     RECT  12.24 162.329 12.258 165.209 ;
     RECT  4.248 165.181 4.95 165.299 ;
     RECT  4.248 165.299 4.806 165.341 ;
     RECT  2.268 165.181 3.51 165.437 ;
     RECT  5.904 164.633 6.534 165.451 ;
     RECT  2.34 165.437 3.51 165.541 ;
     RECT  4.248 165.341 4.626 165.541 ;
     RECT  5.688 165.451 6.534 165.749 ;
     RECT  5.904 165.749 6.534 165.811 ;
     RECT  2.34 165.541 4.626 165.839 ;
     RECT  13.215 162.329 14.526 165.839 ;
     RECT  5.904 165.811 6.822 165.869 ;
     RECT  5.904 165.869 6.534 166.289 ;
     RECT  2.34 165.839 4.266 166.531 ;
     RECT  2.304 166.531 4.266 166.801 ;
     RECT  2.304 166.801 5.058 166.919 ;
     RECT  19.692 126.257 20.79 166.919 ;
     RECT  0.54 166.555 0.558 167.369 ;
     RECT  20.772 166.919 20.79 167.459 ;
     RECT  2.415 166.919 5.058 167.467 ;
     RECT  2.415 167.467 5.094 167.501 ;
     RECT  2.415 167.501 4.266 167.729 ;
     RECT  5.076 167.501 5.094 167.909 ;
     RECT  0.108 167.755 0.126 168.071 ;
     RECT  5.904 166.289 5.922 168.523 ;
     RECT  25.776 156.497 25.794 168.539 ;
     RECT  5.868 168.523 5.922 168.575 ;
     RECT  2.415 167.729 3.438 168.961 ;
     RECT  2.376 168.961 3.438 169.079 ;
     RECT  4.248 167.729 4.266 169.291 ;
     RECT  4.248 169.291 4.806 169.349 ;
     RECT  4.248 169.349 4.662 169.565 ;
     RECT  2.415 169.079 3.438 169.771 ;
     RECT  0.54 168.331 0.558 169.799 ;
     RECT  2.415 169.771 3.474 169.889 ;
     RECT  3.456 169.889 3.474 170.131 ;
     RECT  4.248 169.565 4.266 170.131 ;
     RECT  5.904 168.575 5.922 170.131 ;
     RECT  6.804 170.107 6.822 170.131 ;
     RECT  5.904 170.131 6.822 170.159 ;
     RECT  14.508 165.839 14.526 170.159 ;
     RECT  0.108 170.107 0.126 170.339 ;
     RECT  2.415 169.889 2.697 170.671 ;
     RECT  19.692 166.919 19.71 170.699 ;
     RECT  2.415 170.671 2.718 170.731 ;
     RECT  3.456 170.131 4.266 170.731 ;
     RECT  5.904 170.159 6.426 170.861 ;
     RECT  2.415 170.731 4.266 170.969 ;
     RECT  2.415 170.969 3.33 170.977 ;
     RECT  2.376 170.977 3.33 171.121 ;
     RECT  2.268 171.121 3.33 171.341 ;
     RECT  4.104 170.969 4.266 171.509 ;
     RECT  5.04 171.391 5.058 171.509 ;
     RECT  2.304 171.341 3.33 171.751 ;
     RECT  15.804 126.257 18.897 171.779 ;
     RECT  2.304 171.751 3.474 171.887 ;
     RECT  5.904 170.861 5.922 171.895 ;
     RECT  0.108 171.883 0.126 171.959 ;
     RECT  2.304 171.887 3.294 171.959 ;
     RECT  5.58 171.895 5.922 172.157 ;
     RECT  5.76 172.157 5.922 172.319 ;
     RECT  5.76 172.319 5.778 172.493 ;
     RECT  2.304 171.959 3.042 172.589 ;
     RECT  2.304 172.589 2.97 172.625 ;
     RECT  2.304 172.625 2.754 172.733 ;
     RECT  2.415 172.733 2.754 173.201 ;
     RECT  6.84 173.851 6.858 174.181 ;
     RECT  7.815 163.409 8.097 174.181 ;
     RECT  6.84 174.181 8.097 174.221 ;
     RECT  6.84 174.221 6.858 174.479 ;
     RECT  13.215 165.839 13.497 178.267 ;
     RECT  6.588 178.459 6.606 178.529 ;
     RECT  15.804 171.779 17.658 178.529 ;
     RECT  0.108 178.645 0.126 178.685 ;
     RECT  4.536 179.311 4.554 179.491 ;
     RECT  0.108 179.455 0.126 179.549 ;
     RECT  4.176 179.491 4.698 179.609 ;
     RECT  4.176 179.609 4.194 179.645 ;
     RECT  2.415 173.201 2.697 180.301 ;
     RECT  5.724 180.121 5.742 180.301 ;
     RECT  2.415 180.301 3.69 180.419 ;
     RECT  5.724 180.301 5.886 180.419 ;
     RECT  3.672 180.419 3.69 180.455 ;
     RECT  0.108 180.427 0.126 180.464 ;
     RECT  5.724 180.419 5.742 180.697 ;
     RECT  5.292 180.697 5.742 180.725 ;
     RECT  2.415 180.419 2.697 181.237 ;
     RECT  5.292 180.725 5.454 181.277 ;
     RECT  1.728 181.237 2.697 181.373 ;
     RECT  5.436 181.277 5.454 181.499 ;
     RECT  4.536 181.237 4.554 181.535 ;
     RECT  9.72 161.789 9.738 181.615 ;
     RECT  7.815 174.221 8.097 181.651 ;
     RECT  9.468 181.615 9.738 181.805 ;
     RECT  15.804 178.529 17.55 182.039 ;
     RECT  0.108 182.251 0.126 182.345 ;
     RECT  11.448 182.395 11.466 182.425 ;
     RECT  16.812 182.039 17.55 182.453 ;
     RECT  7.092 181.651 8.097 182.461 ;
     RECT  11.304 182.425 11.466 182.461 ;
     RECT  9.72 181.805 9.738 182.539 ;
     RECT  9.72 182.539 10.386 182.579 ;
     RECT  11.304 182.461 11.934 182.579 ;
     RECT  15.804 182.039 15.822 182.579 ;
     RECT  9.72 182.579 10.314 182.623 ;
     RECT  6.84 182.461 8.097 182.731 ;
     RECT  6.84 182.731 8.622 182.759 ;
     RECT  11.592 182.579 11.934 182.759 ;
     RECT  16.812 182.453 16.902 182.759 ;
     RECT  7.092 182.759 8.622 182.827 ;
     RECT  4.428 182.395 4.446 182.849 ;
     RECT  5.364 182.731 5.382 182.849 ;
     RECT  13.215 178.267 13.95 182.849 ;
     RECT  7.092 182.827 8.802 182.929 ;
     RECT  9.648 182.623 10.314 182.929 ;
     RECT  4.572 183.001 4.59 183.119 ;
     RECT  16.884 182.759 16.902 183.119 ;
     RECT  0.108 183.115 0.126 183.155 ;
     RECT  7.092 182.929 10.314 183.155 ;
     RECT  11.592 182.759 11.61 184.199 ;
     RECT  7.092 183.155 9.666 184.469 ;
     RECT  7.092 184.469 9.126 184.855 ;
     RECT  6.84 184.855 9.126 185.009 ;
     RECT  6.84 185.009 8.622 185.125 ;
     RECT  6.228 185.125 8.622 185.287 ;
     RECT  5.652 185.287 8.622 185.395 ;
     RECT  5.148 185.395 8.622 185.549 ;
     RECT  7.815 185.549 8.622 185.819 ;
     RECT  5.148 185.549 6.858 186.089 ;
     RECT  5.148 186.089 6.534 186.125 ;
     RECT  5.148 186.125 6.462 186.133 ;
     RECT  4.464 186.133 6.462 186.197 ;
     RECT  4.464 186.197 6.246 186.809 ;
     RECT  4.464 186.809 6.102 187.709 ;
     RECT  2.415 181.373 2.697 187.753 ;
     RECT  4.464 187.709 5.67 187.853 ;
     RECT  2.415 187.753 3.042 187.979 ;
     RECT  4.464 187.853 5.634 187.979 ;
     RECT  4.464 187.979 5.274 188.015 ;
     RECT  4.464 188.015 5.238 188.519 ;
     RECT  2.415 187.979 2.934 189.175 ;
     RECT  4.536 188.519 5.238 189.329 ;
     RECT  1.728 189.175 2.934 189.445 ;
     RECT  4.536 189.329 4.626 189.869 ;
     RECT  4.608 189.869 4.626 190.139 ;
     RECT  1.728 189.445 3.402 190.349 ;
     RECT  2.415 190.349 3.402 190.949 ;
     RECT  0.108 189.985 0.126 191.065 ;
     RECT  0.108 191.065 0.162 191.261 ;
     RECT  2.415 190.949 3.222 191.489 ;
     RECT  2.415 191.489 3.114 191.497 ;
     RECT  2.304 191.497 3.114 192.029 ;
     RECT  0.144 191.261 0.162 192.037 ;
     RECT  0.144 192.037 0.594 192.173 ;
     RECT  2.304 192.029 2.697 193.085 ;
     RECT  0.576 192.173 0.594 193.949 ;
     RECT  0.828 195.385 0.846 202.541 ;
     RECT  2.415 193.085 2.697 213.587 ;
     RECT  7.815 185.819 8.097 213.587 ;
     RECT  13.215 182.849 13.497 213.587 ;
     RECT  18.615 171.779 18.897 213.587 ;
     RECT  24.015 163.049 24.297 213.587 ;
     RECT  29.415 120.119 29.697 213.587 ;
     RECT  34.815 132.283 35.097 213.587 ;
     RECT  40.215 132.283 40.497 213.587 ;
     RECT  45.615 132.283 45.897 213.587 ;
     RECT  51.015 132.283 51.297 213.587 ;
     RECT  56.415 132.283 56.697 213.587 ;
     RECT  61.815 132.283 62.097 213.587 ;
     RECT  67.215 132.283 67.497 213.587 ;
     RECT  72.615 132.283 72.897 213.587 ;
     RECT  78.015 132.283 78.297 213.587 ;
     RECT  83.415 132.283 83.697 213.587 ;
     RECT  88.815 132.283 89.097 213.587 ;
     RECT  94.215 132.283 94.497 213.587 ;
     RECT  99.615 132.283 99.897 213.587 ;
     RECT  105.015 132.283 105.297 213.587 ;
     RECT  110.415 132.283 110.697 213.587 ;
     RECT  115.815 132.283 116.097 213.587 ;
     RECT  121.215 132.283 121.497 213.587 ;
     RECT  126.615 132.283 126.897 213.587 ;
     RECT  132.015 132.283 132.297 213.587 ;
     RECT  137.415 132.283 137.697 213.587 ;
     RECT  142.815 132.283 143.097 213.587 ;
     RECT  148.215 132.283 148.497 213.587 ;
     RECT  153.615 132.283 153.897 213.587 ;
     RECT  159.015 132.283 159.297 213.587 ;
     RECT  164.415 132.283 164.697 213.587 ;
     RECT  169.815 132.283 170.097 213.587 ;
     RECT  175.215 132.283 175.497 213.587 ;
     RECT  180.615 132.283 180.897 213.587 ;
     RECT  186.015 132.283 186.297 213.587 ;
     RECT  191.415 132.283 191.697 213.587 ;
     RECT  196.815 132.283 197.097 213.587 ;
     RECT  202.215 132.283 202.497 213.587 ;
     RECT  207.615 132.283 207.897 213.587 ;
     RECT  213.015 132.283 213.297 213.587 ;
     RECT  218.415 132.283 218.697 213.587 ;
     RECT  223.815 132.283 224.097 213.587 ;
     RECT  229.215 114.365 229.497 213.587 ;
     RECT  234.615 2.413 234.897 213.587 ;
     RECT  240.015 2.413 240.297 213.587 ;
     RECT  245.415 2.413 245.697 213.587 ;
     RECT  250.815 2.413 251.097 213.587 ;
     RECT  256.215 2.413 256.497 213.587 ;
     RECT  2.415 213.587 2.505 213.857 ;
     RECT  7.815 213.587 7.905 213.857 ;
     RECT  13.215 213.587 13.305 213.857 ;
     RECT  18.615 213.587 18.705 213.857 ;
     RECT  24.015 213.587 24.105 213.857 ;
     RECT  29.415 213.587 29.505 213.857 ;
     RECT  34.815 213.587 34.905 213.857 ;
     RECT  40.215 213.587 40.305 213.857 ;
     RECT  45.615 213.587 45.705 213.857 ;
     RECT  51.015 213.587 51.105 213.857 ;
     RECT  56.415 213.587 56.505 213.857 ;
     RECT  61.815 213.587 61.905 213.857 ;
     RECT  67.215 213.587 67.305 213.857 ;
     RECT  72.615 213.587 72.705 213.857 ;
     RECT  78.015 213.587 78.105 213.857 ;
     RECT  83.415 213.587 83.505 213.857 ;
     RECT  88.815 213.587 88.905 213.857 ;
     RECT  94.215 213.587 94.305 213.857 ;
     RECT  99.615 213.587 99.705 213.857 ;
     RECT  105.015 213.587 105.105 213.857 ;
     RECT  110.415 213.587 110.505 213.857 ;
     RECT  115.815 213.587 115.905 213.857 ;
     RECT  121.215 213.587 121.305 213.857 ;
     RECT  126.615 213.587 126.705 213.857 ;
     RECT  132.015 213.587 132.105 213.857 ;
     RECT  137.415 213.587 137.505 213.857 ;
     RECT  142.815 213.587 142.905 213.857 ;
     RECT  148.215 213.587 148.305 213.857 ;
     RECT  153.615 213.587 153.705 213.857 ;
     RECT  159.015 213.587 159.105 213.857 ;
     RECT  164.415 213.587 164.505 213.857 ;
     RECT  169.815 213.587 169.905 213.857 ;
     RECT  175.215 213.587 175.305 213.857 ;
     RECT  180.615 213.587 180.705 213.857 ;
     RECT  186.015 213.587 186.105 213.857 ;
     RECT  191.415 213.587 191.505 213.857 ;
     RECT  196.815 213.587 196.905 213.857 ;
     RECT  202.215 213.587 202.305 213.857 ;
     RECT  207.615 213.587 207.705 213.857 ;
     RECT  213.015 213.587 213.105 213.857 ;
     RECT  218.415 213.587 218.505 213.857 ;
     RECT  223.815 213.587 223.905 213.857 ;
     RECT  229.215 213.587 229.305 213.857 ;
     RECT  234.615 213.587 234.705 213.857 ;
     RECT  240.015 213.587 240.105 213.857 ;
     RECT  245.415 213.587 245.505 213.857 ;
     RECT  250.815 213.587 250.905 213.857 ;
     RECT  256.215 213.587 256.305 213.857 ;
    LAYER M4 ;
     RECT  0.084 16.416 0.137 16.44 ;
     RECT  0.06 16.44 0.137 16.896 ;
     RECT  0.084 16.896 0.137 16.92 ;
     RECT  0.06 16.92 0.137 17.376 ;
     RECT  0.084 17.376 0.137 17.4 ;
     RECT  0.06 17.4 0.137 17.856 ;
     RECT  0.084 17.856 0.137 17.88 ;
     RECT  0.06 17.88 0.137 18.336 ;
     RECT  0.084 18.336 0.137 18.36 ;
     RECT  0.06 18.36 0.137 18.768 ;
     RECT  0.084 18.768 0.137 18.792 ;
     RECT  0.06 18.792 0.137 19.248 ;
     RECT  0.084 19.248 0.137 19.272 ;
     RECT  0.06 19.272 0.137 19.728 ;
     RECT  0.084 19.728 0.137 19.752 ;
     RECT  0.06 19.752 0.137 20.208 ;
     RECT  0.084 20.208 0.137 20.232 ;
     RECT  0.06 20.232 0.137 20.688 ;
     RECT  0.084 20.688 0.137 20.712 ;
     RECT  0.06 20.712 0.137 21.168 ;
     RECT  0.084 21.168 0.137 21.192 ;
     RECT  0.06 21.192 0.137 21.648 ;
     RECT  0.084 21.648 0.137 21.672 ;
     RECT  0.06 21.672 0.137 22.08 ;
     RECT  0.084 22.08 0.137 22.104 ;
     RECT  0.06 22.104 0.137 22.56 ;
     RECT  0.084 22.56 0.137 22.584 ;
     RECT  0.06 22.584 0.137 23.04 ;
     RECT  0.084 23.04 0.137 23.064 ;
     RECT  0.06 23.064 0.137 23.52 ;
     RECT  0.084 23.52 0.137 23.544 ;
     RECT  0.06 23.544 0.137 24 ;
     RECT  0.084 24 0.137 24.024 ;
     RECT  0.06 24.024 0.137 24.48 ;
     RECT  0.084 24.48 0.137 24.504 ;
     RECT  0.06 24.504 0.137 24.96 ;
     RECT  0.084 24.96 0.137 24.984 ;
     RECT  0.06 24.984 0.137 25.392 ;
     RECT  0.084 25.392 0.137 25.416 ;
     RECT  0.06 25.416 0.137 25.872 ;
     RECT  0.084 25.872 0.137 25.896 ;
     RECT  0.06 25.896 0.137 26.352 ;
     RECT  0.084 26.352 0.137 26.376 ;
     RECT  0.06 26.376 0.137 26.832 ;
     RECT  0.084 26.832 0.137 26.856 ;
     RECT  0.06 26.856 0.137 27.312 ;
     RECT  0.084 27.312 0.137 27.336 ;
     RECT  0.06 27.336 0.137 27.792 ;
     RECT  0.084 27.792 0.137 27.816 ;
     RECT  0.06 27.816 0.137 28.272 ;
     RECT  0.084 28.272 0.137 28.296 ;
     RECT  0.06 28.296 0.137 28.704 ;
     RECT  0.084 28.704 0.137 28.728 ;
     RECT  0.06 28.728 0.137 29.184 ;
     RECT  0.084 29.184 0.137 29.208 ;
     RECT  0.06 29.208 0.137 29.664 ;
     RECT  0.084 29.664 0.137 29.688 ;
     RECT  0.06 29.688 0.137 30.144 ;
     RECT  0.084 30.144 0.137 30.168 ;
     RECT  0.06 30.168 0.137 30.624 ;
     RECT  0.084 30.624 0.137 30.648 ;
     RECT  0.06 30.648 0.137 31.104 ;
     RECT  0.084 31.104 0.137 31.128 ;
     RECT  0.06 31.128 0.137 31.584 ;
     RECT  0.084 31.584 0.137 31.608 ;
     RECT  0.06 31.608 0.137 32.016 ;
     RECT  0.084 32.016 0.137 32.04 ;
     RECT  0.06 32.04 0.137 32.496 ;
     RECT  0.084 32.496 0.137 32.52 ;
     RECT  0.06 32.52 0.137 32.976 ;
     RECT  0.084 32.976 0.137 33 ;
     RECT  0.06 33 0.137 33.456 ;
     RECT  0.084 33.456 0.137 33.48 ;
     RECT  0.06 33.48 0.137 33.936 ;
     RECT  0.084 33.936 0.137 33.96 ;
     RECT  0.06 33.96 0.137 34.416 ;
     RECT  0.084 34.416 0.137 34.44 ;
     RECT  0.06 34.44 0.137 34.848 ;
     RECT  0.084 34.848 0.137 34.872 ;
     RECT  0.06 34.872 0.137 35.328 ;
     RECT  0.084 35.328 0.137 35.352 ;
     RECT  0.06 35.352 0.137 35.808 ;
     RECT  0.084 35.808 0.137 35.832 ;
     RECT  0.06 35.832 0.137 36.288 ;
     RECT  0.084 36.288 0.137 36.312 ;
     RECT  0.06 36.312 0.137 36.768 ;
     RECT  0.084 36.768 0.137 36.792 ;
     RECT  0.06 36.792 0.137 37.248 ;
     RECT  0.084 37.248 0.137 37.272 ;
     RECT  0.06 37.272 0.137 37.728 ;
     RECT  0.084 37.728 0.137 37.752 ;
     RECT  0.06 37.752 0.137 38.16 ;
     RECT  0.084 38.16 0.137 38.184 ;
     RECT  0.06 38.184 0.137 38.64 ;
     RECT  0.084 38.64 0.137 38.664 ;
     RECT  0.06 38.664 0.137 39.12 ;
     RECT  0.084 39.12 0.137 39.144 ;
     RECT  0.06 39.144 0.137 39.6 ;
     RECT  0.084 39.6 0.137 39.624 ;
     RECT  0.06 39.624 0.137 40.08 ;
     RECT  0.084 40.08 0.137 40.104 ;
     RECT  0.06 40.104 0.137 40.56 ;
     RECT  0.084 40.56 0.137 40.584 ;
     RECT  0.06 40.584 0.137 41.04 ;
     RECT  0.084 41.04 0.137 41.064 ;
     RECT  0.06 41.064 0.137 41.472 ;
     RECT  0.084 41.472 0.137 41.496 ;
     RECT  0.06 41.496 0.137 41.952 ;
     RECT  0.084 41.952 0.137 41.976 ;
     RECT  0.06 41.976 0.137 42.432 ;
     RECT  0.084 42.432 0.137 42.456 ;
     RECT  0.06 42.456 0.137 42.912 ;
     RECT  0.084 42.912 0.137 42.936 ;
     RECT  0.06 42.936 0.137 43.392 ;
     RECT  0.084 43.392 0.137 43.416 ;
     RECT  0.06 43.416 0.137 43.872 ;
     RECT  0.084 43.872 0.137 43.896 ;
     RECT  0.06 43.896 0.137 44.352 ;
     RECT  0.084 44.352 0.137 44.376 ;
     RECT  0.06 44.376 0.137 44.784 ;
     RECT  0.084 44.784 0.137 44.808 ;
     RECT  0.06 44.808 0.137 45.264 ;
     RECT  0.084 45.264 0.137 45.288 ;
     RECT  0.06 45.288 0.137 45.744 ;
     RECT  0.084 45.744 0.137 45.768 ;
     RECT  0.06 45.768 0.137 46.224 ;
     RECT  0.084 46.224 0.137 46.248 ;
     RECT  0.06 46.248 0.137 46.704 ;
     RECT  0.084 46.704 0.137 46.728 ;
     RECT  0.06 46.728 0.137 47.184 ;
     RECT  0.084 47.184 0.137 47.208 ;
     RECT  0.06 47.208 0.137 47.664 ;
     RECT  0.084 47.664 0.137 47.688 ;
     RECT  0.06 47.688 0.137 48.096 ;
     RECT  0.084 48.096 0.137 48.12 ;
     RECT  0.06 48.12 0.137 48.576 ;
     RECT  0.084 48.576 0.137 48.6 ;
     RECT  0.06 48.6 0.137 49.056 ;
     RECT  0.084 49.056 0.137 49.08 ;
     RECT  0.06 49.08 0.137 49.536 ;
     RECT  0.084 49.536 0.137 49.56 ;
     RECT  0.06 49.56 0.137 50.016 ;
     RECT  0.084 50.016 0.137 50.04 ;
     RECT  0.06 50.04 0.137 50.496 ;
     RECT  0.084 50.496 0.137 50.52 ;
     RECT  0.06 50.52 0.137 50.976 ;
     RECT  0.084 50.976 0.137 51 ;
     RECT  0.06 51 0.137 51.408 ;
     RECT  0.084 51.408 0.137 51.432 ;
     RECT  0.06 51.432 0.137 51.888 ;
     RECT  0.084 51.888 0.137 51.912 ;
     RECT  0.06 51.912 0.137 52.368 ;
     RECT  0.084 52.368 0.137 52.392 ;
     RECT  0.06 52.392 0.137 52.848 ;
     RECT  0.084 52.848 0.137 52.872 ;
     RECT  0.06 52.872 0.137 53.328 ;
     RECT  0.084 53.328 0.137 53.352 ;
     RECT  0.06 53.352 0.137 53.808 ;
     RECT  0.084 53.808 0.137 53.832 ;
     RECT  0.06 53.832 0.137 54.288 ;
     RECT  0.084 54.288 0.137 54.312 ;
     RECT  0.06 54.312 0.137 54.72 ;
     RECT  0.084 54.72 0.137 54.744 ;
     RECT  0.06 54.744 0.137 55.2 ;
     RECT  0.084 55.2 0.137 55.224 ;
     RECT  0.06 55.224 0.137 55.68 ;
     RECT  0.084 55.68 0.137 55.704 ;
     RECT  0.06 55.704 0.137 56.16 ;
     RECT  0.084 56.16 0.137 56.184 ;
     RECT  0.06 56.184 0.137 56.64 ;
     RECT  0.084 56.64 0.137 56.664 ;
     RECT  0.06 56.664 0.137 57.12 ;
     RECT  0.084 57.12 0.137 57.144 ;
     RECT  0.06 57.144 0.137 57.552 ;
     RECT  0.084 57.552 0.137 57.576 ;
     RECT  0.06 57.576 0.137 58.032 ;
     RECT  0.084 58.032 0.137 58.056 ;
     RECT  0.06 58.056 0.137 58.512 ;
     RECT  0.084 58.512 0.137 58.536 ;
     RECT  0.06 58.536 0.137 58.992 ;
     RECT  0.084 58.992 0.137 59.016 ;
     RECT  0.06 59.016 0.137 59.472 ;
     RECT  0.084 59.472 0.137 59.496 ;
     RECT  0.06 59.496 0.137 59.952 ;
     RECT  0.084 59.952 0.137 59.976 ;
     RECT  0.06 59.976 0.137 60.432 ;
     RECT  0.084 60.432 0.137 60.456 ;
     RECT  0.06 60.456 0.137 60.864 ;
     RECT  0.084 60.864 0.137 60.888 ;
     RECT  0.06 60.888 0.137 61.344 ;
     RECT  0.084 61.344 0.137 61.368 ;
     RECT  0.06 61.368 0.137 61.824 ;
     RECT  0.084 61.824 0.137 61.848 ;
     RECT  0.06 61.848 0.137 62.304 ;
     RECT  0.084 62.304 0.137 62.328 ;
     RECT  0.06 62.328 0.137 62.784 ;
     RECT  0.084 62.784 0.137 62.808 ;
     RECT  0.06 62.808 0.137 63.264 ;
     RECT  0.084 63.264 0.137 63.288 ;
     RECT  0.06 63.288 0.137 63.744 ;
     RECT  0.084 63.744 0.137 63.768 ;
     RECT  0.06 63.768 0.137 64.176 ;
     RECT  0.084 64.176 0.137 64.2 ;
     RECT  0.06 64.2 0.137 64.656 ;
     RECT  0.084 64.656 0.137 64.68 ;
     RECT  0.06 64.68 0.137 65.136 ;
     RECT  0.084 65.136 0.137 65.16 ;
     RECT  0.06 65.16 0.137 65.616 ;
     RECT  0.084 65.616 0.137 65.64 ;
     RECT  0.06 65.64 0.137 66.096 ;
     RECT  0.084 66.096 0.137 66.12 ;
     RECT  0.06 66.12 0.137 66.576 ;
     RECT  0.084 66.576 0.137 66.6 ;
     RECT  0.06 66.6 0.137 67.056 ;
     RECT  0.084 67.056 0.137 67.08 ;
     RECT  0.06 67.08 0.137 67.488 ;
     RECT  0.084 67.488 0.137 67.512 ;
     RECT  0.06 67.512 0.137 67.968 ;
     RECT  0.084 67.968 0.137 67.992 ;
     RECT  0.06 67.992 0.137 68.448 ;
     RECT  0.084 68.448 0.137 68.472 ;
     RECT  0.06 68.472 0.137 68.928 ;
     RECT  0.084 68.928 0.137 68.952 ;
     RECT  0.06 68.952 0.137 69.408 ;
     RECT  0.084 69.408 0.137 69.432 ;
     RECT  0.06 69.432 0.137 69.888 ;
     RECT  0.084 69.888 0.137 69.912 ;
     RECT  0.06 69.912 0.137 70.368 ;
     RECT  0.084 70.368 0.137 70.392 ;
     RECT  0.06 70.392 0.137 70.8 ;
     RECT  0.084 70.8 0.137 70.824 ;
     RECT  0.06 70.824 0.137 71.28 ;
     RECT  0.084 71.28 0.137 71.304 ;
     RECT  0.06 71.304 0.137 71.76 ;
     RECT  0.084 71.76 0.137 71.784 ;
     RECT  0.06 71.784 0.137 72.24 ;
     RECT  0.084 72.24 0.137 72.264 ;
     RECT  0.06 72.264 0.137 72.72 ;
     RECT  0.084 72.72 0.137 72.744 ;
     RECT  0.06 72.744 0.137 73.2 ;
     RECT  0.084 73.2 0.137 73.224 ;
     RECT  0.06 73.224 0.137 73.68 ;
     RECT  0.084 73.68 0.137 73.704 ;
     RECT  0.06 73.704 0.137 74.112 ;
     RECT  0.084 74.112 0.137 74.136 ;
     RECT  0.06 74.136 0.137 74.592 ;
     RECT  0.084 74.592 0.137 74.616 ;
     RECT  0.06 74.616 0.137 75.072 ;
     RECT  0.084 75.072 0.137 75.096 ;
     RECT  0.06 75.096 0.137 75.552 ;
     RECT  0.084 75.552 0.137 75.576 ;
     RECT  0.06 75.576 0.137 76.032 ;
     RECT  0.084 76.032 0.137 76.056 ;
     RECT  0.06 76.056 0.137 76.512 ;
     RECT  0.084 76.512 0.137 76.536 ;
     RECT  0.06 76.536 0.137 76.992 ;
     RECT  0.084 76.992 0.137 77.016 ;
     RECT  0.06 77.016 0.137 77.424 ;
     RECT  0.084 77.424 0.137 77.448 ;
     RECT  0.06 77.448 0.137 77.904 ;
     RECT  0.084 77.904 0.137 77.928 ;
     RECT  0.06 77.928 0.137 78.384 ;
     RECT  0.084 78.384 0.137 78.408 ;
     RECT  0.06 78.408 0.137 78.864 ;
     RECT  0.084 78.864 0.137 78.888 ;
     RECT  0.06 78.888 0.137 79.344 ;
     RECT  0.084 79.344 0.137 79.368 ;
     RECT  0.06 79.368 0.137 79.824 ;
     RECT  0.084 79.824 0.137 79.848 ;
     RECT  0.06 79.848 0.137 80.256 ;
     RECT  0.084 80.256 0.137 80.28 ;
     RECT  0.06 80.28 0.137 80.736 ;
     RECT  0.084 80.736 0.137 80.76 ;
     RECT  0.084 92.064 0.137 92.088 ;
     RECT  0.06 92.088 0.137 92.688 ;
     RECT  0.084 92.688 0.137 92.712 ;
     RECT  0.06 92.712 0.137 93.264 ;
     RECT  0.084 93.264 0.137 93.288 ;
     RECT  0.06 93.288 0.137 93.84 ;
     RECT  0.084 93.84 0.137 93.864 ;
     RECT  0.06 93.864 0.137 94.464 ;
     RECT  0.084 94.464 0.137 94.488 ;
     RECT  0.06 94.488 0.137 95.04 ;
     RECT  0.084 95.04 0.137 95.064 ;
     RECT  0.06 95.064 0.137 95.616 ;
     RECT  0.084 95.616 0.137 95.64 ;
     RECT  0.06 95.64 0.137 96.24 ;
     RECT  0.084 96.24 0.137 96.264 ;
     RECT  0.06 96.264 0.137 96.816 ;
     RECT  0.084 96.816 0.137 96.84 ;
     RECT  0.06 96.84 0.137 97.392 ;
     RECT  0.084 97.392 0.137 97.416 ;
     RECT  0.06 97.416 0.137 98.016 ;
     RECT  0.084 98.016 0.137 98.04 ;
     RECT  0.06 98.04 0.137 98.592 ;
     RECT  0.084 98.592 0.137 98.616 ;
     RECT  0.06 98.616 0.137 99.168 ;
     RECT  0.084 99.168 0.137 99.192 ;
     RECT  0.06 99.192 0.137 99.792 ;
     RECT  0.084 99.792 0.137 99.816 ;
     RECT  0.06 99.816 0.137 100.368 ;
     RECT  0.084 100.368 0.137 100.392 ;
     RECT  0.06 100.392 0.137 100.944 ;
     RECT  0.084 100.944 0.137 100.968 ;
     RECT  0.06 100.968 0.137 101.52 ;
     RECT  0.084 101.52 0.137 101.544 ;
     RECT  0.06 101.544 0.137 102.144 ;
     RECT  0.084 102.144 0.137 102.168 ;
     RECT  0.06 102.168 0.137 102.72 ;
     RECT  0.084 102.72 0.137 102.744 ;
     RECT  0.06 102.744 0.137 103.296 ;
     RECT  0.084 103.296 0.137 103.32 ;
     RECT  0.06 103.32 0.137 103.92 ;
     RECT  0.084 103.92 0.137 103.944 ;
     RECT  0.06 103.944 0.137 104.496 ;
     RECT  0.084 104.496 0.137 104.52 ;
     RECT  0.06 104.52 0.137 105.072 ;
     RECT  0.084 105.072 0.137 105.096 ;
     RECT  0.06 105.096 0.137 105.696 ;
     RECT  0.084 105.696 0.137 105.72 ;
     RECT  0.06 105.72 0.137 106.272 ;
     RECT  0.084 106.272 0.137 106.296 ;
     RECT  0.06 106.296 0.137 106.848 ;
     RECT  0.084 106.848 0.137 106.872 ;
     RECT  0.06 106.872 0.137 107.472 ;
     RECT  0.084 107.472 0.137 107.496 ;
     RECT  0.06 107.496 0.137 108.048 ;
     RECT  0.084 108.048 0.137 108.072 ;
     RECT  0.06 108.072 0.137 108.624 ;
     RECT  0.084 108.624 0.137 108.648 ;
     RECT  0.06 108.648 0.137 109.248 ;
     RECT  0.084 109.248 0.137 109.272 ;
     RECT  0.06 109.272 0.137 109.824 ;
     RECT  0.084 109.824 0.137 109.848 ;
     RECT  0.06 109.848 0.137 110.4 ;
     RECT  0.084 110.4 0.137 110.424 ;
     RECT  0.06 110.424 0.137 111.024 ;
     RECT  0.084 111.024 0.137 111.048 ;
     RECT  0.06 111.048 0.137 111.6 ;
     RECT  0.084 111.6 0.137 111.624 ;
     RECT  0.06 111.624 0.137 112.176 ;
     RECT  0.084 112.176 0.137 112.2 ;
     RECT  0.06 112.2 0.137 112.8 ;
     RECT  0.084 112.8 0.137 112.824 ;
     RECT  0.06 112.824 0.137 113.376 ;
     RECT  0.084 113.376 0.137 113.4 ;
     RECT  0.06 113.4 0.137 113.952 ;
     RECT  0.084 113.952 0.137 113.976 ;
     RECT  0.06 113.976 0.137 114.528 ;
     RECT  0.084 114.528 0.137 114.552 ;
     RECT  0.06 114.552 0.137 115.152 ;
     RECT  0.084 115.152 0.137 115.176 ;
     RECT  0.06 115.176 0.137 115.728 ;
     RECT  0.084 115.728 0.137 115.752 ;
     RECT  0.06 115.752 0.137 116.304 ;
     RECT  0.084 116.304 0.137 116.328 ;
     RECT  0.06 116.328 0.137 116.928 ;
     RECT  0.084 116.928 0.137 116.952 ;
     RECT  0.06 116.952 0.137 117.504 ;
     RECT  0.084 117.504 0.137 117.528 ;
     RECT  0.06 117.528 0.137 118.08 ;
     RECT  0.084 118.08 0.137 118.104 ;
     RECT  0.06 118.104 0.137 118.704 ;
     RECT  0.084 118.704 0.137 118.728 ;
     RECT  0.06 118.728 0.137 119.28 ;
     RECT  0.084 119.28 0.137 119.304 ;
     RECT  0.06 119.304 0.137 119.856 ;
     RECT  0.084 119.856 0.137 119.88 ;
     RECT  0.06 119.88 0.137 120.48 ;
     RECT  0.084 120.48 0.137 120.504 ;
     RECT  0.06 120.504 0.137 121.056 ;
     RECT  0.084 121.056 0.137 121.08 ;
     RECT  0.06 121.08 0.137 121.632 ;
     RECT  0.084 121.632 0.137 121.656 ;
     RECT  0.06 121.656 0.137 122.256 ;
     RECT  0.084 122.256 0.137 122.28 ;
     RECT  0.06 122.28 0.137 122.832 ;
     RECT  0.084 122.832 0.137 122.856 ;
     RECT  0.06 122.856 0.137 123.408 ;
     RECT  0.084 123.408 0.137 123.432 ;
     RECT  0.06 123.432 0.137 124.032 ;
     RECT  0.084 124.032 0.137 124.056 ;
     RECT  0.06 124.056 0.137 124.608 ;
     RECT  0.084 124.608 0.137 124.632 ;
     RECT  0.06 124.632 0.137 125.184 ;
     RECT  0.084 125.184 0.137 125.208 ;
     RECT  0.06 125.208 0.137 125.808 ;
     RECT  0.084 125.808 0.137 125.832 ;
     RECT  0.06 125.832 0.137 126.384 ;
     RECT  0.084 126.384 0.137 126.408 ;
     RECT  0.06 126.408 0.137 126.96 ;
     RECT  0.084 126.96 0.137 126.984 ;
     RECT  0.06 126.984 0.137 127.536 ;
     RECT  0.084 127.536 0.137 127.56 ;
     RECT  0.06 127.56 0.137 128.16 ;
     RECT  0.084 128.16 0.137 128.184 ;
     RECT  0.06 128.184 0.137 128.736 ;
     RECT  0.084 128.736 0.137 128.76 ;
     RECT  0.06 128.76 0.137 129.312 ;
     RECT  0.084 129.312 0.137 129.336 ;
     RECT  0.06 129.336 0.137 129.936 ;
     RECT  0.084 129.936 0.137 129.96 ;
     RECT  0.06 129.96 0.137 130.512 ;
     RECT  0.084 130.512 0.137 130.536 ;
     RECT  0.06 130.536 0.137 131.088 ;
     RECT  0.084 131.088 0.137 131.112 ;
     RECT  0.06 131.112 0.137 131.712 ;
     RECT  0.084 131.712 0.137 131.736 ;
     RECT  0.06 131.736 0.137 132.288 ;
     RECT  0.084 132.288 0.137 132.312 ;
     RECT  0.06 132.312 0.137 132.864 ;
     RECT  0.084 132.864 0.137 132.888 ;
     RECT  0.06 132.888 0.137 133.488 ;
     RECT  0.084 133.488 0.137 133.512 ;
     RECT  0.06 133.512 0.137 134.064 ;
     RECT  0.084 134.064 0.137 134.088 ;
     RECT  0.06 134.088 0.137 134.64 ;
     RECT  0.084 134.64 0.137 134.664 ;
     RECT  0.06 134.664 0.137 135.264 ;
     RECT  0.084 135.264 0.137 135.288 ;
     RECT  0.06 135.288 0.137 135.84 ;
     RECT  0.084 135.84 0.137 135.864 ;
     RECT  0.06 135.864 0.137 136.416 ;
     RECT  0.084 136.416 0.137 136.44 ;
     RECT  0.06 136.44 0.137 137.04 ;
     RECT  0.084 137.04 0.137 137.064 ;
     RECT  0.06 137.064 0.137 137.616 ;
     RECT  0.084 137.616 0.137 137.64 ;
     RECT  0.06 137.64 0.137 138.192 ;
     RECT  0.084 138.192 0.137 138.216 ;
     RECT  0.06 138.216 0.137 138.816 ;
     RECT  0.084 138.816 0.137 138.84 ;
     RECT  0.06 138.84 0.137 139.392 ;
     RECT  0.084 139.392 0.137 139.416 ;
     RECT  0.06 139.416 0.137 139.968 ;
     RECT  0.084 139.968 0.137 139.992 ;
     RECT  0.06 139.992 0.137 140.544 ;
     RECT  0.084 140.544 0.137 140.568 ;
     RECT  0.06 140.568 0.137 141.168 ;
     RECT  0.084 141.168 0.137 141.192 ;
     RECT  0.06 141.192 0.137 141.744 ;
     RECT  0.084 141.744 0.137 141.768 ;
     RECT  0.06 141.768 0.137 142.32 ;
     RECT  0.084 142.32 0.137 142.344 ;
     RECT  0.06 142.344 0.137 142.944 ;
     RECT  0.084 142.944 0.137 142.968 ;
     RECT  0.06 142.968 0.137 143.52 ;
     RECT  0.084 143.52 0.137 143.544 ;
     RECT  0.06 143.544 0.137 144.096 ;
     RECT  0.084 144.096 0.137 144.12 ;
     RECT  0.06 144.12 0.137 144.72 ;
     RECT  0.084 144.72 0.137 144.744 ;
     RECT  0.06 144.744 0.137 145.296 ;
     RECT  0.084 145.296 0.137 145.32 ;
     RECT  0.06 145.32 0.137 145.872 ;
     RECT  0.084 145.872 0.137 145.896 ;
     RECT  0.06 145.896 0.137 146.496 ;
     RECT  0.084 146.496 0.137 146.52 ;
     RECT  0.06 146.52 0.137 147.072 ;
     RECT  0.084 147.072 0.137 147.096 ;
     RECT  0.06 147.096 0.137 147.648 ;
     RECT  0.084 147.648 0.137 147.672 ;
     RECT  0.06 147.672 0.137 148.272 ;
     RECT  0.084 148.272 0.137 148.296 ;
     RECT  0.06 148.296 0.137 148.848 ;
     RECT  0.084 148.848 0.137 148.872 ;
     RECT  0.06 148.872 0.137 149.424 ;
     RECT  0.084 149.424 0.137 149.448 ;
     RECT  0.06 149.448 0.137 150.048 ;
     RECT  0.084 150.048 0.137 150.072 ;
     RECT  0.06 150.072 0.137 150.624 ;
     RECT  0.084 150.624 0.137 150.648 ;
     RECT  0.06 150.648 0.137 151.2 ;
     RECT  0.084 151.2 0.137 151.224 ;
     RECT  0.06 151.224 0.137 151.776 ;
     RECT  0.084 151.776 0.137 151.8 ;
     RECT  0.06 151.8 0.137 152.4 ;
     RECT  0.084 152.4 0.137 152.424 ;
     RECT  0.06 152.424 0.137 152.976 ;
     RECT  0.084 152.976 0.137 153 ;
     RECT  0.06 153 0.137 153.552 ;
     RECT  0.084 153.552 0.137 153.576 ;
     RECT  0.06 153.576 0.137 154.176 ;
     RECT  0.084 154.176 0.137 154.2 ;
     RECT  0.06 154.2 0.137 154.752 ;
     RECT  0.084 154.752 0.137 154.776 ;
     RECT  0.06 154.776 0.137 155.328 ;
     RECT  0.084 155.328 0.137 155.352 ;
     RECT  0.06 155.352 0.137 155.952 ;
     RECT  0.084 155.952 0.137 155.976 ;
     RECT  0.06 155.976 0.137 156.528 ;
     RECT  0.084 156.528 0.137 156.552 ;
     RECT  0.06 156.552 0.137 157.104 ;
     RECT  0.084 157.104 0.137 157.128 ;
     RECT  0.06 157.128 0.137 157.728 ;
     RECT  0.084 157.728 0.137 157.752 ;
     RECT  0.06 157.752 0.137 158.304 ;
     RECT  0.084 158.304 0.137 158.328 ;
     RECT  0.06 158.328 0.137 158.88 ;
     RECT  0.084 158.88 0.137 158.904 ;
     RECT  0.06 158.904 0.137 159.504 ;
     RECT  0.084 159.504 0.137 159.528 ;
     RECT  0.06 159.528 0.137 160.08 ;
     RECT  0.084 160.08 0.137 160.104 ;
     RECT  0.06 160.104 0.137 160.656 ;
     RECT  0.084 160.656 0.137 160.68 ;
     RECT  0.06 160.68 0.137 161.28 ;
     RECT  0.084 161.28 0.137 161.304 ;
     RECT  0.06 161.304 0.137 161.856 ;
     RECT  0.084 161.856 0.137 161.88 ;
     RECT  0.06 161.88 0.137 162.432 ;
     RECT  0.084 162.432 0.137 162.456 ;
     RECT  0.06 162.456 0.137 163.056 ;
     RECT  0.084 163.056 0.137 163.08 ;
     RECT  0.06 163.08 0.137 163.632 ;
     RECT  0.084 163.632 0.137 163.656 ;
     RECT  0.06 163.656 0.137 164.208 ;
     RECT  0.084 164.208 0.137 164.232 ;
     RECT  0.06 164.232 0.137 164.784 ;
     RECT  0.084 164.784 0.137 164.808 ;
     RECT  0.06 164.808 0.137 165.408 ;
     RECT  0.084 165.408 0.137 165.432 ;
     RECT  0.06 165.432 0.137 165.984 ;
     RECT  0.084 165.984 0.137 166.008 ;
     RECT  0.06 166.008 0.137 166.56 ;
     RECT  0.084 166.56 0.137 166.584 ;
     RECT  0.06 166.584 0.137 167.184 ;
     RECT  0.084 167.184 0.137 167.208 ;
     RECT  0.06 167.208 0.137 167.76 ;
     RECT  0.084 167.76 0.137 167.784 ;
     RECT  0.06 167.784 0.137 168.336 ;
     RECT  0.084 168.336 0.137 168.36 ;
     RECT  0.06 168.36 0.137 168.96 ;
     RECT  0.084 168.96 0.137 168.984 ;
     RECT  0.06 168.984 0.137 169.536 ;
     RECT  0.084 169.536 0.137 169.56 ;
     RECT  0.06 169.56 0.137 170.112 ;
     RECT  0.084 170.112 0.137 170.136 ;
     RECT  0.06 170.136 0.137 170.736 ;
     RECT  0.084 170.736 0.137 170.76 ;
     RECT  0.06 170.76 0.137 171.312 ;
     RECT  0.084 171.312 0.137 171.336 ;
     RECT  0.06 171.336 0.137 171.888 ;
     RECT  0.084 171.888 0.137 171.912 ;
     RECT  0.06 171.912 0.137 172.512 ;
     RECT  0.084 172.512 0.137 172.536 ;
     RECT  0.084 178.656 0.137 178.68 ;
     RECT  0.06 178.68 0.137 179.52 ;
     RECT  0.084 179.52 0.137 179.544 ;
     RECT  0.06 179.544 0.137 180.432 ;
     RECT  0.084 180.432 0.137 180.456 ;
     RECT  0.06 180.456 0.137 181.344 ;
     RECT  0.084 181.344 0.137 181.368 ;
     RECT  0.06 181.368 0.137 182.256 ;
     RECT  0.084 182.256 0.137 182.28 ;
     RECT  0.06 182.28 0.137 183.12 ;
     RECT  0.084 183.12 0.137 183.144 ;
     RECT  0.084 189.456 0.137 189.48 ;
     RECT  0.06 189.48 0.137 190.32 ;
     RECT  0.084 190.32 0.137 190.344 ;
     RECT  0.06 190.344 0.137 191.232 ;
     RECT  0.084 191.232 0.137 191.256 ;
     RECT  0.06 191.256 0.137 192.144 ;
     RECT  0.084 192.144 0.137 192.168 ;
     RECT  0.06 192.168 0.137 193.056 ;
     RECT  0.084 193.056 0.137 193.08 ;
     RECT  0.06 193.08 0.137 193.92 ;
     RECT  0.084 193.92 0.137 193.944 ;
     RECT  0.137 192.144 0.173 193.944 ;
     RECT  0.137 21.168 0.569 22.104 ;
     RECT  0.137 36.288 0.569 36.312 ;
     RECT  0.137 39.12 0.569 40.104 ;
     RECT  0.137 41.952 0.569 41.976 ;
     RECT  0.137 49.536 0.569 49.56 ;
     RECT  0.137 51.408 0.569 52.392 ;
     RECT  0.137 60.864 0.569 60.888 ;
     RECT  0.137 64.656 0.569 64.68 ;
     RECT  0.137 93.264 0.569 93.288 ;
     RECT  0.137 95.04 0.569 95.064 ;
     RECT  0.137 99.168 0.569 106.296 ;
     RECT  0.137 107.472 0.569 108.072 ;
     RECT  0.137 109.248 0.569 110.424 ;
     RECT  0.137 111.6 0.569 116.952 ;
     RECT  0.137 118.704 0.569 119.448 ;
     RECT  0.137 122.832 0.569 122.856 ;
     RECT  0.137 126.384 0.569 126.408 ;
     RECT  0.137 127.536 0.569 127.56 ;
     RECT  0.137 128.736 0.569 132.888 ;
     RECT  0.137 134.064 0.569 134.664 ;
     RECT  0.137 139.968 0.569 144.744 ;
     RECT  0.137 151.2 0.569 154.872 ;
     RECT  0.137 155.952 0.569 155.976 ;
     RECT  0.137 157.104 0.569 157.752 ;
     RECT  0.137 160.08 0.569 162.456 ;
     RECT  0.137 163.632 0.569 163.656 ;
     RECT  0.137 164.784 0.569 167.208 ;
     RECT  0.137 168.336 0.569 169.56 ;
     RECT  0.173 193.056 0.605 193.944 ;
     RECT  0.137 18.768 2.408 19.752 ;
     RECT  0.569 22.08 2.408 22.104 ;
     RECT  0.137 27.792 2.408 27.816 ;
     RECT  0.137 30.144 2.408 32.52 ;
     RECT  0.137 37.728 2.408 37.752 ;
     RECT  0.569 39.12 2.408 39.144 ;
     RECT  0.137 43.872 2.408 43.896 ;
     RECT  0.137 46.704 2.408 47.208 ;
     RECT  0.569 52.368 2.408 52.392 ;
     RECT  0.137 55.68 2.408 55.704 ;
     RECT  0.137 57.552 2.408 57.576 ;
     RECT  0.137 63.264 2.408 63.288 ;
     RECT  0.137 66.096 2.408 67.08 ;
     RECT  0.137 69.888 2.408 69.912 ;
     RECT  0.137 71.76 2.408 72.744 ;
     RECT  0.137 77.424 2.408 77.928 ;
     RECT  0.137 79.824 2.408 79.848 ;
     RECT  0.137 92.064 2.408 92.088 ;
     RECT  0.137 96.816 2.408 98.04 ;
     RECT  0.569 99.168 2.408 100.392 ;
     RECT  0.569 102.72 2.408 103.32 ;
     RECT  0.569 104.496 2.408 104.52 ;
     RECT  0.569 109.248 2.408 109.272 ;
     RECT  0.569 110.4 2.408 110.424 ;
     RECT  0.569 111.6 2.408 112.728 ;
     RECT  0.569 115.152 2.408 116.952 ;
     RECT  0.569 119.424 2.408 119.448 ;
     RECT  0.569 129.312 2.408 129.96 ;
     RECT  0.569 131.088 2.408 132.888 ;
     RECT  0.569 134.64 2.408 134.664 ;
     RECT  0.137 135.84 2.408 135.864 ;
     RECT  0.137 137.04 2.408 137.064 ;
     RECT  0.137 138.912 2.408 138.936 ;
     RECT  0.569 139.968 2.408 139.992 ;
     RECT  0.569 141.168 2.408 141.192 ;
     RECT  0.569 142.32 2.408 144.12 ;
     RECT  0.137 146.496 2.408 147.672 ;
     RECT  0.137 149.424 2.408 149.448 ;
     RECT  0.569 152.976 2.408 153.576 ;
     RECT  0.569 154.848 2.408 154.872 ;
     RECT  0.137 158.88 2.408 158.904 ;
     RECT  0.569 160.08 2.408 161.304 ;
     RECT  0.569 162.432 2.408 162.456 ;
     RECT  0.569 165.408 2.408 166.008 ;
     RECT  0.137 170.736 2.408 171.336 ;
     RECT  0.137 172.512 2.408 172.536 ;
     RECT  0.137 181.344 2.408 181.368 ;
     RECT  0.137 189.456 2.408 190.344 ;
     RECT  0.605 193.056 2.408 193.08 ;
     RECT  2.408 2.148 2.512 213.852 ;
     RECT  2.512 2.418 2.704 213.582 ;
     RECT  2.704 18.624 2.765 18.792 ;
     RECT  2.704 67.056 2.765 67.08 ;
     RECT  2.704 112.176 2.801 112.728 ;
     RECT  2.704 109.248 3.449 109.272 ;
     RECT  2.801 112.704 3.449 112.728 ;
     RECT  2.704 119.424 3.449 119.448 ;
     RECT  2.704 136.128 3.449 137.064 ;
     RECT  2.704 138.912 3.449 138.936 ;
     RECT  2.704 139.968 3.449 139.992 ;
     RECT  2.704 149.424 3.449 149.448 ;
     RECT  2.704 154.848 3.449 155.016 ;
     RECT  2.704 170.736 3.449 170.76 ;
     RECT  2.704 27.312 3.973 27.336 ;
     RECT  3.913 57.6 3.973 57.624 ;
     RECT  3.805 78.672 3.973 78.696 ;
     RECT  2.765 18.624 3.98 18.648 ;
     RECT  3.973 78.576 4.019 78.696 ;
     RECT  2.704 142.752 4.021 142.776 ;
     RECT  3.98 18.144 4.067 18.648 ;
     RECT  3.98 141.12 4.067 141.144 ;
     RECT  4.021 142.752 4.067 143.64 ;
     RECT  4.093 138.528 4.117 138.552 ;
     RECT  3.697 67.824 4.172 67.848 ;
     RECT  4.117 138.144 4.177 138.552 ;
     RECT  4.117 69.168 4.204 69.192 ;
     RECT  3.973 27.312 4.213 28.152 ;
     RECT  3.805 66.096 4.213 66.12 ;
     RECT  4.172 67.248 4.241 67.848 ;
     RECT  4.213 27.312 4.259 29.112 ;
     RECT  2.704 64.224 4.259 64.248 ;
     RECT  4.213 65.52 4.259 66.12 ;
     RECT  4.241 67.248 4.259 67.272 ;
     RECT  2.704 21.792 4.273 21.816 ;
     RECT  3.973 56.736 4.345 57.624 ;
     RECT  4.019 78.576 4.345 78.6 ;
     RECT  4.309 150.144 4.345 150.168 ;
     RECT  4.268 145.296 4.355 145.32 ;
     RECT  4.259 28.128 4.385 29.112 ;
     RECT  4.345 56.736 4.385 58.152 ;
     RECT  4.345 78.336 4.385 78.6 ;
     RECT  4.345 150.144 4.396 150.456 ;
     RECT  4.316 59.424 4.403 59.448 ;
     RECT  4.385 58.128 4.429 58.152 ;
     RECT  2.704 103.296 4.453 103.32 ;
     RECT  4.453 112.08 4.489 112.104 ;
     RECT  4.213 63.216 4.493 63.24 ;
     RECT  4.067 18.624 4.499 18.648 ;
     RECT  4.412 19.968 4.499 19.992 ;
     RECT  4.273 21.792 4.499 22.2 ;
     RECT  4.021 129.36 4.501 129.384 ;
     RECT  2.704 133.296 4.501 133.32 ;
     RECT  3.973 26.112 4.529 26.136 ;
     RECT  4.501 133.296 4.547 134.232 ;
     RECT  4.201 38.928 4.549 38.952 ;
     RECT  4.517 60.384 4.549 60.408 ;
     RECT  4.517 98.736 4.549 98.76 ;
     RECT  4.129 100.656 4.549 100.68 ;
     RECT  4.453 102.528 4.549 103.32 ;
     RECT  3.449 154.992 4.556 155.016 ;
     RECT  2.704 46.656 4.559 46.68 ;
     RECT  4.067 143.616 4.565 143.64 ;
     RECT  4.489 25.104 4.573 25.128 ;
     RECT  4.501 18.768 4.588 19.416 ;
     RECT  4.501 130.944 4.588 131.784 ;
     RECT  4.547 134.208 4.588 134.232 ;
     RECT  3.449 136.128 4.588 136.152 ;
     RECT  4.501 137.136 4.588 137.16 ;
     RECT  2.704 36.912 4.595 36.936 ;
     RECT  4.549 38.16 4.595 39.384 ;
     RECT  4.453 50.16 4.595 50.184 ;
     RECT  4.345 72.96 4.595 72.984 ;
     RECT  4.381 94.032 4.595 94.056 ;
     RECT  4.129 96.288 4.595 96.312 ;
     RECT  4.549 100.656 4.595 101.208 ;
     RECT  4.549 102.528 4.595 103.368 ;
     RECT  4.489 112.08 4.595 112.68 ;
     RECT  4.273 44.4 4.597 44.424 ;
     RECT  2.704 169.2 4.597 169.224 ;
     RECT  4.021 8.496 4.601 8.52 ;
     RECT  4.549 60.384 4.601 60.84 ;
     RECT  4.517 95.184 4.601 95.208 ;
     RECT  4.549 35.568 4.633 35.592 ;
     RECT  4.549 114.24 4.633 114.264 ;
     RECT  4.549 48.432 4.636 48.696 ;
     RECT  2.704 61.824 4.636 61.848 ;
     RECT  4.549 98.304 4.636 98.76 ;
     RECT  4.595 103.344 4.636 103.368 ;
     RECT  4.633 114.24 4.636 115.08 ;
     RECT  4.499 22.128 4.637 22.2 ;
     RECT  4.501 23.904 4.637 23.928 ;
     RECT  4.549 70.944 4.637 70.968 ;
     RECT  4.597 43.824 4.643 45 ;
     RECT  4.559 46.656 4.643 47.304 ;
     RECT  4.556 123.696 4.643 123.72 ;
     RECT  4.597 169.2 4.643 169.56 ;
     RECT  4.093 171.024 4.643 171.048 ;
     RECT  4.453 76.368 4.669 76.392 ;
     RECT  4.501 33.216 4.673 33.768 ;
     RECT  4.595 39.36 4.673 39.384 ;
     RECT  4.589 156.768 4.673 156.792 ;
     RECT  4.597 125.616 4.684 126.408 ;
     RECT  4.643 169.296 4.684 169.56 ;
     RECT  4.604 41.28 4.691 41.304 ;
     RECT  2.704 152.496 4.693 152.52 ;
     RECT  4.595 38.16 4.709 38.184 ;
     RECT  4.633 34.8 4.717 35.592 ;
     RECT  4.633 42.768 4.717 42.792 ;
     RECT  4.693 152.496 4.739 153.048 ;
     RECT  4.556 154.992 4.739 155.208 ;
     RECT  4.381 158.016 4.741 158.04 ;
     RECT  4.453 146.928 4.745 147.624 ;
     RECT  4.525 164.496 4.748 164.52 ;
     RECT  4.739 153.024 4.78 153.048 ;
     RECT  2.704 166.368 4.789 166.392 ;
     RECT  4.597 167.472 4.789 167.496 ;
     RECT  4.748 164.496 4.835 165.336 ;
     RECT  4.789 166.368 4.835 167.496 ;
     RECT  4.021 110.016 4.837 110.04 ;
     RECT  4.741 158.016 4.853 158.088 ;
     RECT  4.684 169.296 4.883 169.32 ;
     RECT  4.385 56.736 4.885 56.76 ;
     RECT  4.837 110.016 4.885 110.76 ;
     RECT  4.396 150.384 4.885 150.456 ;
     RECT  4.501 129.36 4.921 129.864 ;
     RECT  4.835 166.992 4.925 167.496 ;
     RECT  4.885 150.384 4.931 150.984 ;
     RECT  4.684 125.616 4.957 125.64 ;
     RECT  4.385 28.464 4.961 29.112 ;
     RECT  4.921 129.36 4.979 129.96 ;
     RECT  4.643 43.824 4.981 43.848 ;
     RECT  4.961 29.04 4.988 29.112 ;
     RECT  4.933 127.392 5.02 127.416 ;
     RECT  4.643 44.976 5.029 45 ;
     RECT  4.925 167.472 5.033 167.496 ;
     RECT  4.981 43.296 5.068 43.848 ;
     RECT  5.029 44.976 5.069 45.096 ;
     RECT  4.988 29.04 5.075 30.024 ;
     RECT  4.453 31.344 5.075 31.368 ;
     RECT  4.201 52.416 5.077 52.44 ;
     RECT  3.985 54.096 5.077 54.12 ;
     RECT  2.704 105.408 5.077 105.432 ;
     RECT  4.885 109.68 5.077 110.76 ;
     RECT  4.636 115.056 5.077 115.08 ;
     RECT  5.077 54.096 5.123 54.504 ;
     RECT  4.885 56.208 5.123 56.76 ;
     RECT  5.077 105.408 5.123 105.816 ;
     RECT  5.077 115.056 5.123 115.656 ;
     RECT  4.717 35.568 5.141 35.592 ;
     RECT  5.077 52.416 5.141 53.016 ;
     RECT  5.141 52.992 5.164 53.016 ;
     RECT  5.123 54.48 5.164 54.504 ;
     RECT  5.077 109.632 5.164 110.76 ;
     RECT  4.643 47.28 5.213 47.304 ;
     RECT  4.417 182.4 5.221 182.424 ;
     RECT  4.453 80.928 5.245 80.952 ;
     RECT  5.123 105.792 5.249 105.816 ;
     RECT  4.595 112.608 5.249 112.68 ;
     RECT  5.221 182.16 5.267 182.424 ;
     RECT  4.957 124.848 5.281 125.64 ;
     RECT  5.267 182.16 5.281 182.184 ;
     RECT  4.673 33.744 5.285 33.768 ;
     RECT  5.245 80.928 5.285 81.336 ;
     RECT  4.595 101.184 5.285 101.208 ;
     RECT  4.385 78.336 5.372 78.36 ;
     RECT  5.123 56.736 5.393 56.76 ;
     RECT  5.372 78 5.413 78.36 ;
     RECT  4.633 74.112 5.429 74.136 ;
     RECT  5.413 78 5.459 78.936 ;
     RECT  5.42 26.16 5.461 26.184 ;
     RECT  4.636 48.672 5.501 48.696 ;
     RECT  5.461 26.16 5.507 26.808 ;
     RECT  4.669 75.408 5.557 76.392 ;
     RECT  4.561 119.616 5.564 119.64 ;
     RECT  5.164 109.68 5.573 110.76 ;
     RECT  5.425 71.808 5.603 71.832 ;
     RECT  5.557 75.216 5.605 76.392 ;
     RECT  2.704 159.552 5.609 159.576 ;
     RECT  4.637 22.176 5.641 22.2 ;
     RECT  5.557 73.488 5.644 73.512 ;
     RECT  5.605 75.216 5.651 76.536 ;
     RECT  4.381 117.36 5.651 117.384 ;
     RECT  5.564 119.616 5.651 119.688 ;
     RECT  5.281 124.752 5.651 125.64 ;
     RECT  5.564 162.288 5.651 162.312 ;
     RECT  5.569 160.704 5.653 160.728 ;
     RECT  5.068 43.824 5.681 43.848 ;
     RECT  4.835 164.496 5.692 164.52 ;
     RECT  5.281 181.248 5.699 182.184 ;
     RECT  5.285 81.312 5.708 81.336 ;
     RECT  4.525 179.328 5.708 179.352 ;
     RECT  4.588 19.392 5.713 19.416 ;
     RECT  5.123 115.632 5.713 115.656 ;
     RECT  5.641 22.176 5.747 23.304 ;
     RECT  5.459 78.336 5.749 78.936 ;
     RECT  4.381 92.928 5.749 92.952 ;
     RECT  5.569 172.128 5.749 172.152 ;
     RECT  5.708 179.328 5.749 180.168 ;
     RECT  4.345 107.76 5.753 107.784 ;
     RECT  5.713 115.632 5.753 115.752 ;
     RECT  5.701 21.024 5.788 21.048 ;
     RECT  5.713 18.816 5.789 19.416 ;
     RECT  5.749 172.128 5.789 172.488 ;
     RECT  5.708 81.312 5.795 81.48 ;
     RECT  5.749 92.928 5.795 93.48 ;
     RECT  5.749 178.464 5.795 180.168 ;
     RECT  4.636 98.736 5.825 98.76 ;
     RECT  5.749 78.336 5.833 79.272 ;
     RECT  5.833 78.336 5.853 78.936 ;
     RECT  5.069 45.072 5.933 45.096 ;
     RECT  4.745 146.928 5.957 146.952 ;
     RECT  4.601 60.816 6.005 60.84 ;
     RECT  5.075 29.04 6.041 29.112 ;
     RECT  5.957 146.448 6.041 146.952 ;
     RECT  4.259 65.52 6.109 65.544 ;
     RECT  4.177 138.144 6.14 138.168 ;
     RECT  6.109 64.992 6.149 65.544 ;
     RECT  5.651 125.616 6.149 125.64 ;
     RECT  6.14 137.664 6.181 138.168 ;
     RECT  6.181 137.664 6.227 139.128 ;
     RECT  6.149 64.992 6.229 65.016 ;
     RECT  6.227 139.104 6.265 139.128 ;
     RECT  5.641 16.512 6.275 16.536 ;
     RECT  5.789 18.816 6.275 18.84 ;
     RECT  6.229 64.368 6.275 65.016 ;
     RECT  4.931 150.96 6.277 150.984 ;
     RECT  6.073 153.408 6.277 153.432 ;
     RECT  6.073 156.528 6.277 156.552 ;
     RECT  4.853 158.016 6.277 158.04 ;
     RECT  5.533 145.344 6.284 145.368 ;
     RECT  5.651 119.616 6.323 119.64 ;
     RECT  6.277 150.96 6.323 151.56 ;
     RECT  6.277 153.408 6.323 154.248 ;
     RECT  6.277 156 6.323 156.552 ;
     RECT  4.813 40.608 6.325 40.632 ;
     RECT  4.345 122.4 6.325 122.424 ;
     RECT  6.275 64.368 6.329 64.392 ;
     RECT  5.651 75.216 6.329 75.24 ;
     RECT  6.277 120.72 6.364 120.744 ;
     RECT  6.284 145.008 6.365 145.368 ;
     RECT  6.284 38.544 6.371 38.568 ;
     RECT  6.325 122.4 6.371 122.664 ;
     RECT  4.979 129.936 6.371 129.96 ;
     RECT  6.277 158.016 6.371 158.568 ;
     RECT  5.573 110.736 6.397 110.76 ;
     RECT  5.753 115.728 6.437 115.752 ;
     RECT  6.041 146.928 6.437 146.952 ;
     RECT  6.38 170.832 6.467 170.856 ;
     RECT  5.789 172.464 6.467 172.488 ;
     RECT  6.325 131.28 6.469 131.304 ;
     RECT  6.041 29.088 6.473 29.112 ;
     RECT  5.249 112.656 6.476 112.68 ;
     RECT  6.323 156 6.501 156.024 ;
     RECT  6.365 145.008 6.505 145.032 ;
     RECT  6.397 110.736 6.517 110.904 ;
     RECT  6.476 112.656 6.517 113.352 ;
     RECT  6.421 174.192 6.517 174.456 ;
     RECT  5.573 109.68 6.524 109.704 ;
     RECT  6.517 112.656 6.563 113.736 ;
     RECT  6.524 108.72 6.611 109.704 ;
     RECT  6.361 62.592 6.613 62.616 ;
     RECT  6.229 17.616 6.653 17.64 ;
     RECT  6.371 122.64 6.653 122.664 ;
     RECT  6.572 60.96 6.659 61.224 ;
     RECT  6.572 66.672 6.659 66.696 ;
     RECT  5.795 178.464 6.659 178.488 ;
     RECT  6.371 158.4 6.725 158.568 ;
     RECT  6.325 36.384 6.757 36.408 ;
     RECT  5.965 141.888 6.764 141.912 ;
     RECT  6.757 35.856 6.797 36.408 ;
     RECT  6.721 54.72 6.829 54.744 ;
     RECT  5.795 81.312 6.829 81.336 ;
     RECT  6.613 134.544 6.853 134.568 ;
     RECT  6.853 134.544 6.86 135.144 ;
     RECT  6.649 29.76 6.901 29.784 ;
     RECT  6.793 101.28 6.901 101.304 ;
     RECT  6.901 31.92 6.937 31.944 ;
     RECT  5.795 93.456 6.949 93.48 ;
     RECT  6.908 117.744 6.949 117.768 ;
     RECT  6.829 54.72 6.956 55.416 ;
     RECT  6.793 46.128 6.997 46.152 ;
     RECT  5.507 26.736 7.045 26.808 ;
     RECT  6.997 41.904 7.045 41.928 ;
     RECT  6.505 49.2 7.093 49.224 ;
     RECT  6.956 54.096 7.093 55.416 ;
     RECT  6.797 35.856 7.148 35.88 ;
     RECT  6.901 29.76 7.153 30.6 ;
     RECT  7.045 26.736 7.369 27.384 ;
     RECT  7.109 28.464 7.369 28.488 ;
     RECT  7.369 26.736 7.429 28.488 ;
     RECT  6.901 103.968 7.429 103.992 ;
     RECT  6.937 106.608 7.669 106.632 ;
     RECT  6.908 94.56 7.765 94.584 ;
     RECT  5.747 22.176 7.808 22.2 ;
     RECT  5.747 23.28 7.808 23.304 ;
     RECT  7.429 26.64 7.808 28.488 ;
     RECT  7.153 29.76 7.808 30.888 ;
     RECT  6.937 31.92 7.808 32.904 ;
     RECT  7.073 33.888 7.808 33.912 ;
     RECT  7.148 35.04 7.808 35.88 ;
     RECT  6.325 40.176 7.808 40.632 ;
     RECT  7.045 41.904 7.808 42.168 ;
     RECT  6.829 44.448 7.808 44.472 ;
     RECT  6.997 46.128 7.808 46.728 ;
     RECT  6.853 47.856 7.808 47.88 ;
     RECT  7.093 49.2 7.808 50.04 ;
     RECT  6.829 51.36 7.808 51.384 ;
     RECT  7.093 53.376 7.808 55.416 ;
     RECT  6.397 57.6 7.808 57.624 ;
     RECT  6.793 58.848 7.808 58.872 ;
     RECT  6.659 60.96 7.808 60.984 ;
     RECT  6.613 62.592 7.808 63.144 ;
     RECT  7.093 66.768 7.808 66.792 ;
     RECT  7.261 70.8 7.808 70.824 ;
     RECT  5.651 76.512 7.808 76.536 ;
     RECT  5.853 78.912 7.808 78.936 ;
     RECT  6.829 81.312 7.808 81.432 ;
     RECT  6.949 92.928 7.808 93.48 ;
     RECT  7.765 94.56 7.808 94.68 ;
     RECT  6.793 97.44 7.808 97.464 ;
     RECT  6.86 99.888 7.808 99.912 ;
     RECT  6.901 101.28 7.808 102.12 ;
     RECT  7.429 103.968 7.808 104.568 ;
     RECT  7.669 106.608 7.808 106.728 ;
     RECT  6.611 109.152 7.808 109.704 ;
     RECT  6.517 110.736 7.808 111.288 ;
     RECT  6.563 112.656 7.808 112.68 ;
     RECT  6.563 113.712 7.808 113.736 ;
     RECT  6.949 117.744 7.808 118.728 ;
     RECT  6.949 119.712 7.808 119.736 ;
     RECT  7.045 128.784 7.808 128.808 ;
     RECT  7.004 130.128 7.808 130.152 ;
     RECT  6.469 131.28 7.808 132.264 ;
     RECT  6.86 134.544 7.808 135.48 ;
     RECT  6.829 139.68 7.808 139.848 ;
     RECT  6.764 141.888 7.808 142.488 ;
     RECT  6.505 144.096 7.808 145.032 ;
     RECT  4.885 149.136 7.808 149.16 ;
     RECT  6.323 151.536 7.808 151.56 ;
     RECT  6.323 154.224 7.808 154.248 ;
     RECT  6.725 158.4 7.808 158.424 ;
     RECT  6.613 161.136 7.808 161.16 ;
     RECT  6.253 163.536 7.808 163.56 ;
     RECT  6.764 165.84 7.808 165.864 ;
     RECT  5.857 168.528 7.808 168.552 ;
     RECT  6.764 170.112 7.808 170.136 ;
     RECT  6.517 173.856 7.808 174.456 ;
     RECT  5.699 182.16 7.808 182.184 ;
     RECT  7.808 2.148 7.912 213.852 ;
     RECT  7.912 2.418 8.104 213.582 ;
     RECT  8.104 53.376 8.237 53.4 ;
     RECT  8.104 21.552 8.243 21.576 ;
     RECT  8.104 23.232 8.243 23.256 ;
     RECT  8.104 26.64 8.243 26.664 ;
     RECT  8.104 74.544 8.243 74.664 ;
     RECT  8.104 76.176 8.243 77.544 ;
     RECT  8.104 94.656 8.243 94.68 ;
     RECT  8.104 108.048 8.243 110.76 ;
     RECT  8.104 92.64 8.281 92.664 ;
     RECT  8.104 70.704 8.291 73.56 ;
     RECT  8.104 81.408 8.291 81.432 ;
     RECT  8.243 74.64 8.309 74.664 ;
     RECT  8.104 25.152 8.381 25.176 ;
     RECT  8.104 30.864 8.381 30.888 ;
     RECT  8.291 70.704 8.381 70.824 ;
     RECT  8.104 63.072 8.387 63.672 ;
     RECT  8.104 68.592 8.387 69.576 ;
     RECT  8.104 47.856 8.417 48.36 ;
     RECT  8.381 70.704 8.425 70.728 ;
     RECT  8.104 118.704 8.489 118.728 ;
     RECT  8.104 59.184 8.579 59.832 ;
     RECT  8.387 63.072 8.579 63.096 ;
     RECT  8.104 78.912 8.633 79.272 ;
     RECT  8.291 72.576 8.675 73.56 ;
     RECT  8.675 72.576 8.716 72.6 ;
     RECT  8.104 29.76 8.741 29.784 ;
     RECT  8.104 181.776 8.771 182.856 ;
     RECT  8.243 76.512 8.849 77.544 ;
     RECT  8.104 60.96 9.029 60.984 ;
     RECT  8.104 46.512 9.164 46.536 ;
     RECT  8.243 108.816 9.241 108.888 ;
     RECT  8.104 41.904 9.251 41.928 ;
     RECT  9.164 46.224 9.251 46.536 ;
     RECT  8.417 48.336 9.251 48.36 ;
     RECT  9.205 49.44 9.389 49.464 ;
     RECT  9.241 108.72 9.421 108.888 ;
     RECT  8.579 59.328 9.457 59.832 ;
     RECT  8.104 112.176 9.493 112.68 ;
     RECT  8.771 181.776 9.497 181.8 ;
     RECT  8.243 110.592 9.529 110.76 ;
     RECT  9.421 108.72 9.565 109.464 ;
     RECT  8.104 106.704 9.637 106.728 ;
     RECT  9.565 107.76 9.637 109.464 ;
     RECT  9.637 106.704 9.683 109.464 ;
     RECT  9.493 111.888 9.817 112.68 ;
     RECT  8.771 182.832 9.889 182.856 ;
     RECT  9.457 59.328 9.961 60.408 ;
     RECT  9.925 75.6 9.961 75.624 ;
     RECT  8.849 76.896 9.961 77.352 ;
     RECT  9.961 58.992 9.971 60.408 ;
     RECT  9.781 72.672 9.971 72.696 ;
     RECT  9.683 107.136 10.001 107.16 ;
     RECT  9.961 75.6 10.012 77.352 ;
     RECT  9.683 108.72 10.177 109.464 ;
     RECT  9.529 110.496 10.177 110.76 ;
     RECT  8.633 79.248 10.213 79.272 ;
     RECT  10.012 76.368 10.259 77.352 ;
     RECT  9.853 61.392 10.321 61.416 ;
     RECT  9.889 182.832 10.325 183 ;
     RECT  10.105 48.432 10.453 48.456 ;
     RECT  10.453 48.336 10.499 48.456 ;
     RECT  10.412 49.536 10.499 49.56 ;
     RECT  10.177 108.72 10.645 110.76 ;
     RECT  9.817 111.744 10.645 112.68 ;
     RECT  10.453 50.688 10.649 51.384 ;
     RECT  10.645 108.72 10.681 112.68 ;
     RECT  10.177 53.376 10.748 53.4 ;
     RECT  8.104 33.888 10.789 33.912 ;
     RECT  10.321 61.392 10.825 61.656 ;
     RECT  10.748 52.992 10.835 53.4 ;
     RECT  10.681 107.76 10.865 112.68 ;
     RECT  10.789 33.792 10.937 33.912 ;
     RECT  9.925 74.064 10.973 74.088 ;
     RECT  9.971 58.992 11.149 60.024 ;
     RECT  10.645 55.392 11.189 55.416 ;
     RECT  10.649 51.36 11.297 51.384 ;
     RECT  10.825 61.2 11.329 61.656 ;
     RECT  10.499 48.336 11.369 48.36 ;
     RECT  10.357 182.544 11.437 182.568 ;
     RECT  10.865 108.72 11.461 112.68 ;
     RECT  11.437 182.4 11.477 182.568 ;
     RECT  11.477 182.4 11.521 182.424 ;
     RECT  11.329 61.152 11.545 61.656 ;
     RECT  10.213 78.336 11.765 79.272 ;
     RECT  11.725 96.336 11.809 96.984 ;
     RECT  8.104 66.768 11.905 66.792 ;
     RECT  8.104 83.184 11.941 83.208 ;
     RECT  11.905 66.768 11.977 67.272 ;
     RECT  9.251 46.512 11.981 46.536 ;
     RECT  11.64 64.848 11.981 64.872 ;
     RECT  11.941 83.04 11.987 83.208 ;
     RECT  10.259 77.328 11.989 77.352 ;
     RECT  11.765 78.336 11.989 78.36 ;
     RECT  11.989 77.328 12.035 78.36 ;
     RECT  11.948 81.024 12.035 81.048 ;
     RECT  11.545 61.104 12.049 61.656 ;
     RECT  12.035 77.328 12.053 77.496 ;
     RECT  11.329 105.456 12.332 105.48 ;
     RECT  11.149 58.992 12.337 60.072 ;
     RECT  8.104 131.28 12.437 131.304 ;
     RECT  12.049 61.104 12.481 61.752 ;
     RECT  12.085 46.176 12.517 46.2 ;
     RECT  12.337 58.944 12.697 60.072 ;
     RECT  12.437 130.56 13.045 131.304 ;
     RECT  10.937 33.888 13.201 33.912 ;
     RECT  13.201 33.072 13.208 33.912 ;
     RECT  11.977 35.328 13.208 35.352 ;
     RECT  13.093 38.4 13.208 38.424 ;
     RECT  13.093 39.744 13.208 39.768 ;
     RECT  13.052 41.376 13.208 41.4 ;
     RECT  12.589 43.296 13.208 43.32 ;
     RECT  12.517 45.456 13.208 46.2 ;
     RECT  12.877 53.568 13.208 53.592 ;
     RECT  12.901 56.496 13.208 56.52 ;
     RECT  12.697 58.464 13.208 60.072 ;
     RECT  12.481 61.104 13.208 61.944 ;
     RECT  12.841 64.656 13.208 64.68 ;
     RECT  11.977 66.72 13.208 67.272 ;
     RECT  12.301 69.456 13.208 69.48 ;
     RECT  12.625 72.384 13.208 72.408 ;
     RECT  12.053 77.472 13.208 77.496 ;
     RECT  11.987 83.04 13.208 83.064 ;
     RECT  11.809 96.864 13.208 96.984 ;
     RECT  12.469 98.448 13.208 98.472 ;
     RECT  12.332 104.784 13.208 105.48 ;
     RECT  12.085 107.52 13.208 107.544 ;
     RECT  11.461 108.72 13.208 113.304 ;
     RECT  13.045 129.936 13.208 131.304 ;
     RECT  13.208 2.148 13.312 213.852 ;
     RECT  13.312 2.418 13.504 213.582 ;
     RECT  13.504 66.912 13.619 66.936 ;
     RECT  13.504 104.88 13.619 105.48 ;
     RECT  13.619 104.976 13.66 105.48 ;
     RECT  13.504 43.296 13.781 43.944 ;
     RECT  13.66 105.456 13.889 105.48 ;
     RECT  13.504 64.56 14.321 64.68 ;
     RECT  13.504 56.496 14.429 56.808 ;
     RECT  14.569 23.76 14.675 23.784 ;
     RECT  13.504 68.352 14.681 68.424 ;
     RECT  13.504 69.456 14.681 69.48 ;
     RECT  13.504 33.072 14.749 33.912 ;
     RECT  14.605 106.56 14.785 106.584 ;
     RECT  13.504 107.856 14.785 113.256 ;
     RECT  14.681 68.352 14.867 68.376 ;
     RECT  14.749 33.072 14.869 34.776 ;
     RECT  14.821 35.904 14.869 35.928 ;
     RECT  14.869 33.072 14.905 35.928 ;
     RECT  14.905 34.608 14.917 35.928 ;
     RECT  14.497 37.2 14.917 37.224 ;
     RECT  13.504 25.68 14.924 25.704 ;
     RECT  14.917 114.24 14.924 114.264 ;
     RECT  13.504 58.464 14.929 60.072 ;
     RECT  14.785 106.56 14.963 113.256 ;
     RECT  14.963 106.56 14.965 113.016 ;
     RECT  14.821 63.36 14.972 63.384 ;
     RECT  14.821 104.88 15.001 104.904 ;
     RECT  14.917 34.608 15.005 37.224 ;
     RECT  14.924 114.24 15.005 114.552 ;
     RECT  14.924 25.68 15.011 26.424 ;
     RECT  14.605 31.344 15.011 31.368 ;
     RECT  15.005 34.608 15.011 34.776 ;
     RECT  15.005 114.528 15.011 114.552 ;
     RECT  13.504 129.936 15.011 129.96 ;
     RECT  15.013 66.096 15.037 66.12 ;
     RECT  14.605 67.296 15.037 67.32 ;
     RECT  14.965 106.464 15.041 113.016 ;
     RECT  14.321 64.56 15.059 64.584 ;
     RECT  15.037 66.096 15.059 67.32 ;
     RECT  13.504 98.448 15.073 98.472 ;
     RECT  14.821 87.216 15.077 87.24 ;
     RECT  14.972 63.216 15.145 63.384 ;
     RECT  15.068 42.72 15.155 42.744 ;
     RECT  13.781 43.92 15.155 43.944 ;
     RECT  15.145 63.216 15.253 64.152 ;
     RECT  15.001 104.88 15.293 105.48 ;
     RECT  15.059 66.096 15.329 66.696 ;
     RECT  14.785 69.504 15.349 69.528 ;
     RECT  15.349 69.504 15.395 70.488 ;
     RECT  15.073 98.064 15.395 98.472 ;
     RECT  15.005 37.2 15.397 37.224 ;
     RECT  13.504 38.688 15.397 38.712 ;
     RECT  14.629 22.752 15.401 22.776 ;
     RECT  14.905 33.072 15.401 33.096 ;
     RECT  15.293 105.456 15.401 105.48 ;
     RECT  15.395 98.448 15.437 98.472 ;
     RECT  15.397 37.2 15.505 38.712 ;
     RECT  15.505 37.2 15.509 38.808 ;
     RECT  13.504 40.416 15.545 40.44 ;
     RECT  15.509 38.688 15.587 38.808 ;
     RECT  15.587 38.784 15.589 38.808 ;
     RECT  14.429 56.784 15.589 56.808 ;
     RECT  15.329 66.096 15.617 66.12 ;
     RECT  15.349 96.048 15.685 96.072 ;
     RECT  15.589 56.688 15.731 56.808 ;
     RECT  15.685 95.76 15.769 96.072 ;
     RECT  15.685 32.256 15.827 32.472 ;
     RECT  15.011 34.608 15.933 34.632 ;
     RECT  15.011 26.064 16.117 26.088 ;
     RECT  15.253 63.072 16.117 64.152 ;
     RECT  15.731 56.784 16.157 56.808 ;
     RECT  13.504 83.184 16.189 83.208 ;
     RECT  14.605 85.248 16.309 85.272 ;
     RECT  16.309 85.248 16.355 85.368 ;
     RECT  16.355 85.344 16.396 85.368 ;
     RECT  16.117 63.072 16.441 64.632 ;
     RECT  15.041 106.464 16.441 112.68 ;
     RECT  14.929 58.176 16.549 60.072 ;
     RECT  16.549 24.48 16.633 24.504 ;
     RECT  15.781 29.664 16.789 29.688 ;
     RECT  16.441 106.464 16.801 113.544 ;
     RECT  16.789 28.8 16.876 29.688 ;
     RECT  16.837 24.096 16.924 24.12 ;
     RECT  16.801 105.792 16.981 113.544 ;
     RECT  16.776 22.752 17.057 22.776 ;
     RECT  15.769 96.048 17.093 96.072 ;
     RECT  16.189 83.184 17.125 84.024 ;
     RECT  16.981 105.168 17.129 113.544 ;
     RECT  17.129 105.168 17.161 106.728 ;
     RECT  15.395 70.464 17.193 70.488 ;
     RECT  17.161 104.88 17.269 106.728 ;
     RECT  15.005 35.904 17.273 35.976 ;
     RECT  17.273 35.952 17.603 35.976 ;
     RECT  16.549 58.128 17.603 60.072 ;
     RECT  16.441 63.072 17.701 64.728 ;
     RECT  17.603 58.176 17.737 60.072 ;
     RECT  13.504 61.056 17.737 61.944 ;
     RECT  17.129 107.76 17.773 113.544 ;
     RECT  17.269 104.496 17.809 106.728 ;
     RECT  16.876 29.664 17.989 29.688 ;
     RECT  17.809 103.968 18.169 106.728 ;
     RECT  17.773 107.76 18.169 113.88 ;
     RECT  16.117 26.064 18.608 26.28 ;
     RECT  17.989 29.664 18.608 29.784 ;
     RECT  15.827 32.256 18.608 32.28 ;
     RECT  17.557 56.736 18.608 56.76 ;
     RECT  17.737 58.176 18.608 61.944 ;
     RECT  17.701 62.976 18.608 64.728 ;
     RECT  17.125 79.728 18.608 79.752 ;
     RECT  17.125 83.184 18.608 84.36 ;
     RECT  18.14 85.776 18.608 85.8 ;
     RECT  18.097 102.624 18.608 102.648 ;
     RECT  18.169 103.968 18.608 113.88 ;
     RECT  18.608 2.148 18.712 213.852 ;
     RECT  18.712 2.418 18.904 213.582 ;
     RECT  18.904 104.352 19.325 105.672 ;
     RECT  18.904 83.184 19.721 84.36 ;
     RECT  19.721 84.336 19.763 84.36 ;
     RECT  19.721 83.184 19.944 83.256 ;
     RECT  19.897 81.216 19.964 81.24 ;
     RECT  19.944 82.656 19.973 83.256 ;
     RECT  19.964 80.304 20.051 81.24 ;
     RECT  19.973 82.656 20.051 83.208 ;
     RECT  18.904 29.76 20.153 29.784 ;
     RECT  18.904 106.704 20.329 112.44 ;
     RECT  18.904 79.056 20.339 79.08 ;
     RECT  20.293 70.128 20.377 70.68 ;
     RECT  19.325 104.352 20.657 105.384 ;
     RECT  20.377 70.128 20.732 70.152 ;
     RECT  20.732 69.504 20.819 70.152 ;
     RECT  20.329 106.704 20.905 112.536 ;
     RECT  20.657 104.64 20.941 105.384 ;
     RECT  20.221 56.544 20.977 56.568 ;
     RECT  20.905 106.608 20.977 112.536 ;
     RECT  20.941 104.64 20.981 105.432 ;
     RECT  20.977 106.608 21.193 112.632 ;
     RECT  18.904 113.856 21.193 114.552 ;
     RECT  20.819 70.128 21.197 70.152 ;
     RECT  18.904 62.976 21.553 65.688 ;
     RECT  20.051 82.656 21.553 82.68 ;
     RECT  21.397 115.728 21.629 115.752 ;
     RECT  21.553 82.656 21.637 83.208 ;
     RECT  21.637 82.656 21.683 83.832 ;
     RECT  20.981 105.216 21.701 105.432 ;
     RECT  21.193 106.608 21.733 114.552 ;
     RECT  21.683 82.656 21.737 82.68 ;
     RECT  21.733 106.608 21.737 114.648 ;
     RECT  21.701 105.216 22.061 105.24 ;
     RECT  20.051 80.304 22.205 80.328 ;
     RECT  20.977 56.544 22.237 57.048 ;
     RECT  21.737 106.656 22.777 114.648 ;
     RECT  22.777 106.176 22.817 114.648 ;
     RECT  21.553 62.976 23.029 65.784 ;
     RECT  20.005 91.056 23.029 91.08 ;
     RECT  22.988 98.64 23.029 98.664 ;
     RECT  22.817 106.176 23.065 106.2 ;
     RECT  23.029 62.976 23.533 66.552 ;
     RECT  23.237 97.44 23.605 97.464 ;
     RECT  23.029 98.64 23.605 98.856 ;
     RECT  23.533 62.976 23.677 67.08 ;
     RECT  22.817 107.52 23.821 114.648 ;
     RECT  18.904 58.176 23.929 61.944 ;
     RECT  23.677 62.976 23.929 67.704 ;
     RECT  18.904 25.968 24.008 25.992 ;
     RECT  18.904 32.256 24.008 32.28 ;
     RECT  22.237 56.544 24.008 57.144 ;
     RECT  23.929 58.176 24.008 67.704 ;
     RECT  21.683 83.808 24.008 83.832 ;
     RECT  23.029 91.056 24.008 92.04 ;
     RECT  22.957 94.656 24.008 94.68 ;
     RECT  23.605 97.44 24.008 98.856 ;
     RECT  23.605 100.32 24.008 100.344 ;
     RECT  23.677 102.144 24.008 102.168 ;
     RECT  23.533 104.304 24.008 104.328 ;
     RECT  23.065 105.456 24.008 106.2 ;
     RECT  23.821 107.52 24.008 115.176 ;
     RECT  23.857 119.232 24.008 119.256 ;
     RECT  24.008 2.148 24.112 213.852 ;
     RECT  24.112 2.418 24.304 213.582 ;
     RECT  24.304 81.168 24.419 81.192 ;
     RECT  24.304 102.144 24.419 102.648 ;
     RECT  24.304 119.232 24.419 119.256 ;
     RECT  24.304 104.352 24.473 105.432 ;
     RECT  24.304 99.6 24.581 99.624 ;
     RECT  24.473 104.544 24.977 105.432 ;
     RECT  24.304 56.544 25.333 57.144 ;
     RECT  24.304 58.176 25.333 67.704 ;
     RECT  24.304 106.8 25.333 115.512 ;
     RECT  24.304 69.216 25.405 69.24 ;
     RECT  25.405 69.216 25.513 69.528 ;
     RECT  24.304 91.056 25.513 91.08 ;
     RECT  25.513 68.928 25.621 69.528 ;
     RECT  25.573 99.024 25.621 99.048 ;
     RECT  25.333 56.544 25.657 67.704 ;
     RECT  25.621 68.928 25.657 69.624 ;
     RECT  25.621 98.736 25.661 99.048 ;
     RECT  24.977 104.832 25.669 105.432 ;
     RECT  25.333 106.56 25.669 115.512 ;
     RECT  25.669 104.832 25.763 115.512 ;
     RECT  25.513 91.056 25.861 91.32 ;
     RECT  24.304 89.376 25.907 89.4 ;
     RECT  25.861 90.576 25.949 91.32 ;
     RECT  25.763 105.408 26.021 115.512 ;
     RECT  26.021 105.408 26.165 106.056 ;
     RECT  26.161 94.56 26.197 94.584 ;
     RECT  26.197 94.56 26.245 95.208 ;
     RECT  26.245 95.184 26.345 95.208 ;
     RECT  25.513 100.08 26.413 100.104 ;
     RECT  25.949 91.296 26.485 91.32 ;
     RECT  26.485 91.296 26.525 92.136 ;
     RECT  25.661 98.736 26.525 98.952 ;
     RECT  25.649 102.048 26.713 102.072 ;
     RECT  26.165 105.648 26.741 106.056 ;
     RECT  26.413 100.08 26.813 100.776 ;
     RECT  26.525 92.112 26.957 92.136 ;
     RECT  26.377 119.136 27.059 119.16 ;
     RECT  25.909 93.36 27.097 93.384 ;
     RECT  26.021 107.856 27.097 115.512 ;
     RECT  27.097 93.36 27.205 93.528 ;
     RECT  26.813 100.08 27.209 100.104 ;
     RECT  27.097 107.76 27.277 115.512 ;
     RECT  26.741 106.032 27.308 106.056 ;
     RECT  27.308 106.032 27.349 106.2 ;
     RECT  27.277 107.664 27.349 115.512 ;
     RECT  27.349 106.032 27.457 115.512 ;
     RECT  27.205 93.264 27.497 93.528 ;
     RECT  26.525 98.928 27.533 98.952 ;
     RECT  27.497 93.504 27.749 93.528 ;
     RECT  27.301 95.76 27.817 95.784 ;
     RECT  25.657 56.544 27.853 69.624 ;
     RECT  27.565 99.552 27.923 99.576 ;
     RECT  27.311 105.024 27.923 105.048 ;
     RECT  27.457 106.032 28.211 115.992 ;
     RECT  27.853 56.544 28.285 70.296 ;
     RECT  26.629 97.68 28.289 97.704 ;
     RECT  28.211 106.032 28.289 106.584 ;
     RECT  27.817 95.76 28.892 95.976 ;
     RECT  24.304 32.256 29.408 32.28 ;
     RECT  28.285 56.544 29.408 70.344 ;
     RECT  27.889 94.56 29.408 94.584 ;
     RECT  28.892 95.76 29.408 96.024 ;
     RECT  28.289 106.032 29.408 106.056 ;
     RECT  28.211 107.856 29.408 115.992 ;
     RECT  28.933 119.232 29.408 119.256 ;
     RECT  29.408 2.148 29.512 213.852 ;
     RECT  29.512 2.418 29.704 213.582 ;
     RECT  29.704 119.232 30.668 119.256 ;
     RECT  29.704 32.256 30.709 32.28 ;
     RECT  30.668 85.488 30.709 85.512 ;
     RECT  30.709 85.488 30.755 85.944 ;
     RECT  30.668 103.2 30.755 103.224 ;
     RECT  30.668 119.232 30.755 119.688 ;
     RECT  30.755 85.824 30.816 85.944 ;
     RECT  30.816 85.824 31.025 85.848 ;
     RECT  31.021 117.792 31.093 117.816 ;
     RECT  32.029 50.016 32.141 50.04 ;
     RECT  30.755 119.232 32.245 119.256 ;
     RECT  30.709 131.904 32.245 131.928 ;
     RECT  32.245 103.728 32.329 103.752 ;
     RECT  32.245 119.232 32.437 119.688 ;
     RECT  29.704 107.856 34.441 115.992 ;
     RECT  31.093 117.408 34.441 117.816 ;
     RECT  34.621 46.752 34.733 46.776 ;
     RECT  30.709 32.256 34.808 32.472 ;
     RECT  32.245 131.76 34.808 131.928 ;
     RECT  34.808 2.148 34.912 32.472 ;
     RECT  34.808 131.76 34.912 213.852 ;
     RECT  34.912 2.418 35.104 32.472 ;
     RECT  34.912 131.76 35.104 213.582 ;
     RECT  34.441 107.856 36.745 117.816 ;
     RECT  32.437 119.232 36.745 120.216 ;
     RECT  29.704 56.544 37.573 70.344 ;
     RECT  37.609 51.648 38.185 52.44 ;
     RECT  37.609 53.568 38.185 53.88 ;
     RECT  37.573 55.776 38.185 70.344 ;
     RECT  36.745 107.856 38.689 120.216 ;
     RECT  38.149 47.424 38.725 47.448 ;
     RECT  38.185 49.632 38.761 50.136 ;
     RECT  38.185 51.264 38.761 53.88 ;
     RECT  38.761 49.632 38.797 53.88 ;
     RECT  38.185 54.912 38.797 70.344 ;
     RECT  38.725 46.56 39.301 47.448 ;
     RECT  39.301 46.56 39.337 48.408 ;
     RECT  39.337 46.56 39.913 48.504 ;
     RECT  38.797 49.632 39.913 70.344 ;
     RECT  39.913 45.696 39.949 70.344 ;
     RECT  39.949 45.6 39.985 70.344 ;
     RECT  39.985 45.12 40.021 70.344 ;
     RECT  40.021 44.928 40.165 70.344 ;
     RECT  35.104 32.256 40.208 32.472 ;
     RECT  35.104 131.76 40.208 131.928 ;
     RECT  40.208 2.148 40.312 32.472 ;
     RECT  40.208 131.76 40.312 213.852 ;
     RECT  38.689 107.136 40.417 120.216 ;
     RECT  40.312 2.418 40.504 32.472 ;
     RECT  40.312 131.76 40.504 213.582 ;
     RECT  40.417 106.752 42.073 120.216 ;
     RECT  42.073 106.464 42.505 120.216 ;
     RECT  40.165 44.544 42.721 70.344 ;
     RECT  42.721 44.352 43.009 70.344 ;
     RECT  43.009 43.92 43.2 70.344 ;
     RECT  42.505 106.368 43.2 120.216 ;
     RECT  40.504 131.76 43.265 131.928 ;
     RECT  43.2 43.92 43.272 120.216 ;
     RECT  43.265 131.904 43.553 131.928 ;
     RECT  40.504 32.256 45.608 32.472 ;
     RECT  45.608 2.148 45.712 32.472 ;
     RECT  45.608 132.288 45.712 213.852 ;
     RECT  45.712 132.288 45.8 213.582 ;
     RECT  45.712 2.418 45.904 32.472 ;
     RECT  45.8 132.018 45.904 213.582 ;
     RECT  45.904 32.256 51.008 32.472 ;
     RECT  51.008 2.148 51.112 32.472 ;
     RECT  51.008 132.288 51.112 213.852 ;
     RECT  51.112 132.288 51.2 213.582 ;
     RECT  51.112 2.418 51.304 32.472 ;
     RECT  51.2 132.018 51.304 213.582 ;
     RECT  51.304 32.256 56.408 32.472 ;
     RECT  56.408 2.148 56.512 32.472 ;
     RECT  56.408 132.288 56.512 213.852 ;
     RECT  56.512 132.288 56.6 213.582 ;
     RECT  56.512 2.418 56.704 32.472 ;
     RECT  56.6 132.018 56.704 213.582 ;
     RECT  56.704 32.256 61.808 32.472 ;
     RECT  61.808 2.148 61.912 32.472 ;
     RECT  61.808 132.288 61.912 213.852 ;
     RECT  61.912 132.288 62 213.582 ;
     RECT  61.912 2.418 62.104 32.472 ;
     RECT  62 132.018 62.104 213.582 ;
     RECT  62.104 32.256 66.697 32.472 ;
     RECT  66.697 32.016 67.139 32.472 ;
     RECT  67.139 32.016 67.208 32.412 ;
     RECT  67.208 2.148 67.312 32.412 ;
     RECT  67.208 132.288 67.312 213.852 ;
     RECT  67.312 132.288 67.4 213.582 ;
     RECT  67.312 2.418 67.504 32.328 ;
     RECT  67.4 132.018 67.504 213.582 ;
     RECT  67.504 31.68 69.869 32.328 ;
     RECT  69.869 31.68 72.608 31.704 ;
     RECT  72.608 2.148 72.712 32.412 ;
     RECT  72.608 132.288 72.712 213.852 ;
     RECT  72.712 132.288 72.8 213.582 ;
     RECT  72.712 2.418 72.904 32.142 ;
     RECT  72.8 132.018 72.904 213.582 ;
     RECT  72.904 31.68 76.421 31.704 ;
     RECT  76.525 31.44 78.008 31.464 ;
     RECT  78.008 2.148 78.112 32.412 ;
     RECT  78.008 132.288 78.112 213.852 ;
     RECT  78.112 132.288 78.2 213.582 ;
     RECT  78.112 2.418 78.304 32.142 ;
     RECT  78.2 132.018 78.304 213.582 ;
     RECT  78.304 31.44 83.408 31.464 ;
     RECT  83.408 2.148 83.512 32.412 ;
     RECT  83.408 132.288 83.512 213.852 ;
     RECT  83.512 132.288 83.6 213.582 ;
     RECT  83.512 2.418 83.704 32.142 ;
     RECT  83.6 132.018 83.704 213.582 ;
     RECT  83.704 31.44 88.808 31.464 ;
     RECT  88.808 2.148 88.912 32.412 ;
     RECT  88.808 132.288 88.912 213.852 ;
     RECT  88.912 132.288 89 213.582 ;
     RECT  88.912 2.418 89.104 32.142 ;
     RECT  89 132.018 89.104 213.582 ;
     RECT  89.104 31.44 94.208 31.464 ;
     RECT  94.208 2.148 94.312 32.412 ;
     RECT  94.208 132.288 94.312 213.852 ;
     RECT  94.312 132.288 94.4 213.582 ;
     RECT  94.312 2.418 94.504 32.142 ;
     RECT  94.4 132.018 94.504 213.582 ;
     RECT  94.504 31.44 99.608 31.464 ;
     RECT  99.608 2.148 99.712 32.412 ;
     RECT  99.608 132.288 99.712 213.852 ;
     RECT  99.712 132.288 99.8 213.582 ;
     RECT  99.712 2.418 99.904 32.142 ;
     RECT  99.8 132.018 99.904 213.582 ;
     RECT  99.904 31.44 105.008 31.464 ;
     RECT  105.008 2.148 105.112 32.412 ;
     RECT  105.008 132.288 105.112 213.852 ;
     RECT  105.112 132.288 105.2 213.582 ;
     RECT  105.112 2.418 105.304 32.142 ;
     RECT  105.2 132.018 105.304 213.582 ;
     RECT  105.304 31.44 110.408 31.464 ;
     RECT  110.408 2.148 110.512 32.412 ;
     RECT  110.408 132.288 110.512 213.852 ;
     RECT  110.512 132.288 110.6 213.582 ;
     RECT  110.512 2.418 110.704 32.142 ;
     RECT  110.6 132.018 110.704 213.582 ;
     RECT  110.704 31.44 113.411 31.464 ;
     RECT  115.808 2.148 115.912 32.412 ;
     RECT  115.808 132.288 115.912 213.852 ;
     RECT  115.912 132.288 116 213.582 ;
     RECT  115.912 2.418 116.104 32.142 ;
     RECT  116 132.018 116.104 213.582 ;
     RECT  121.208 2.148 121.312 32.412 ;
     RECT  121.208 132.288 121.312 213.852 ;
     RECT  121.312 132.288 121.4 213.582 ;
     RECT  121.312 2.418 121.504 32.142 ;
     RECT  121.4 132.018 121.504 213.582 ;
     RECT  126.608 2.148 126.712 32.412 ;
     RECT  126.608 132.288 126.712 213.852 ;
     RECT  126.712 132.288 126.8 213.582 ;
     RECT  126.712 2.418 126.904 32.142 ;
     RECT  126.8 132.018 126.904 213.582 ;
     RECT  132.008 2.148 132.112 32.412 ;
     RECT  132.008 132.288 132.112 213.852 ;
     RECT  132.112 132.288 132.2 213.582 ;
     RECT  132.112 2.418 132.304 32.142 ;
     RECT  132.2 132.018 132.304 213.582 ;
     RECT  137.408 2.148 137.512 32.412 ;
     RECT  137.408 132.288 137.512 213.852 ;
     RECT  137.512 132.288 137.6 213.582 ;
     RECT  137.512 2.418 137.704 32.142 ;
     RECT  137.6 132.018 137.704 213.582 ;
     RECT  142.808 2.148 142.912 32.412 ;
     RECT  142.808 132.288 142.912 213.852 ;
     RECT  142.912 132.288 143 213.582 ;
     RECT  142.912 2.418 143.104 32.142 ;
     RECT  143 132.018 143.104 213.582 ;
     RECT  148.208 2.148 148.312 32.412 ;
     RECT  148.208 132.288 148.312 213.852 ;
     RECT  148.312 132.288 148.4 213.582 ;
     RECT  148.312 2.418 148.504 32.142 ;
     RECT  148.4 132.018 148.504 213.582 ;
     RECT  153.608 2.148 153.712 32.412 ;
     RECT  153.608 132.288 153.712 213.852 ;
     RECT  153.712 132.288 153.8 213.582 ;
     RECT  153.712 2.418 153.904 32.142 ;
     RECT  153.8 132.018 153.904 213.582 ;
     RECT  159.008 2.148 159.112 32.412 ;
     RECT  159.008 132.288 159.112 213.852 ;
     RECT  159.112 132.288 159.2 213.582 ;
     RECT  159.112 2.418 159.304 32.142 ;
     RECT  159.2 132.018 159.304 213.582 ;
     RECT  164.408 2.148 164.512 32.412 ;
     RECT  164.408 132.288 164.512 213.852 ;
     RECT  164.512 132.288 164.6 213.582 ;
     RECT  164.512 2.418 164.704 32.142 ;
     RECT  164.6 132.018 164.704 213.582 ;
     RECT  169.808 2.148 169.912 32.412 ;
     RECT  169.808 132.288 169.912 213.852 ;
     RECT  169.912 132.288 170 213.582 ;
     RECT  169.912 2.418 170.104 32.142 ;
     RECT  170 132.018 170.104 213.582 ;
     RECT  175.208 2.148 175.312 32.412 ;
     RECT  175.208 132.288 175.312 213.852 ;
     RECT  175.312 132.288 175.4 213.582 ;
     RECT  175.312 2.418 175.504 32.142 ;
     RECT  175.4 132.018 175.504 213.582 ;
     RECT  180.608 2.148 180.712 32.412 ;
     RECT  180.608 132.288 180.712 213.852 ;
     RECT  180.712 132.288 180.8 213.582 ;
     RECT  180.712 2.418 180.904 32.142 ;
     RECT  180.8 132.018 180.904 213.582 ;
     RECT  186.008 2.148 186.112 32.412 ;
     RECT  186.008 132.288 186.112 213.852 ;
     RECT  186.112 132.288 186.2 213.582 ;
     RECT  186.112 2.418 186.304 32.142 ;
     RECT  186.2 132.018 186.304 213.582 ;
     RECT  191.408 2.148 191.512 32.412 ;
     RECT  191.408 132.288 191.512 213.852 ;
     RECT  191.512 132.288 191.6 213.582 ;
     RECT  191.512 2.418 191.704 32.142 ;
     RECT  191.6 132.018 191.704 213.582 ;
     RECT  196.808 2.148 196.912 32.412 ;
     RECT  196.808 132.288 196.912 213.852 ;
     RECT  196.912 132.288 197 213.582 ;
     RECT  196.912 2.418 197.104 32.142 ;
     RECT  197 132.018 197.104 213.582 ;
     RECT  202.208 2.148 202.312 32.412 ;
     RECT  202.208 132.288 202.312 213.852 ;
     RECT  202.312 132.288 202.4 213.582 ;
     RECT  202.312 2.418 202.504 32.142 ;
     RECT  202.4 132.018 202.504 213.582 ;
     RECT  207.608 2.148 207.712 32.412 ;
     RECT  207.608 132.288 207.712 213.852 ;
     RECT  207.712 132.288 207.8 213.582 ;
     RECT  207.712 2.418 207.904 32.142 ;
     RECT  207.8 132.018 207.904 213.582 ;
     RECT  213.008 2.148 213.112 32.412 ;
     RECT  213.008 132.288 213.112 213.852 ;
     RECT  213.112 132.288 213.2 213.582 ;
     RECT  213.112 2.418 213.304 32.142 ;
     RECT  213.2 132.018 213.304 213.582 ;
     RECT  43.272 43.2 214.416 120.984 ;
     RECT  214.416 44.256 214.661 120.216 ;
     RECT  214.661 44.352 214.697 120.216 ;
     RECT  214.697 44.352 214.733 120.12 ;
     RECT  214.733 44.544 214.805 120.12 ;
     RECT  214.805 44.64 214.877 120.12 ;
     RECT  218.408 2.148 218.512 32.412 ;
     RECT  218.408 132.288 218.512 213.852 ;
     RECT  218.512 132.288 218.6 213.582 ;
     RECT  218.512 2.418 218.704 32.142 ;
     RECT  218.6 132.018 218.704 213.582 ;
     RECT  214.877 44.64 219.161 119.928 ;
     RECT  219.161 44.832 221.105 119.928 ;
     RECT  221.105 44.928 221.177 119.928 ;
     RECT  223.808 2.148 223.912 32.412 ;
     RECT  223.808 132.288 223.912 213.852 ;
     RECT  223.912 132.288 224 213.582 ;
     RECT  223.912 2.418 224.104 32.142 ;
     RECT  224 132.018 224.104 213.582 ;
     RECT  221.177 45.024 224.453 119.928 ;
     RECT  224.453 45.12 224.489 119.928 ;
     RECT  224.489 45.312 224.525 119.928 ;
     RECT  224.525 45.408 224.561 119.928 ;
     RECT  224.561 45.504 224.597 119.928 ;
     RECT  224.597 45.6 224.633 119.928 ;
     RECT  224.633 114.24 224.705 119.928 ;
     RECT  224.705 114.336 225.533 119.928 ;
     RECT  225.533 114.336 225.569 119.64 ;
     RECT  225.569 114.336 225.605 119.448 ;
     RECT  224.633 45.6 225.713 113.208 ;
     RECT  225.605 114.336 225.713 119.16 ;
     RECT  225.713 45.6 225.749 50.712 ;
     RECT  225.713 51.936 225.749 113.208 ;
     RECT  225.713 114.336 225.749 115.8 ;
     RECT  225.749 51.936 225.785 82.584 ;
     RECT  225.713 116.928 225.785 118.584 ;
     RECT  225.785 63.36 225.821 82.584 ;
     RECT  225.749 83.616 225.821 113.208 ;
     RECT  225.749 46.272 225.893 50.712 ;
     RECT  225.785 51.936 225.893 62.328 ;
     RECT  225.821 63.648 225.893 82.584 ;
     RECT  225.821 83.712 225.929 93.72 ;
     RECT  225.821 94.752 225.929 113.208 ;
     RECT  225.893 80.928 225.965 82.584 ;
     RECT  225.893 63.648 226.001 79.896 ;
     RECT  225.893 46.272 226.109 47.832 ;
     RECT  225.929 83.712 226.253 91.032 ;
     RECT  225.785 117.12 226.253 118.392 ;
     RECT  226.253 117.216 226.289 118.392 ;
     RECT  225.893 48.864 226.325 50.712 ;
     RECT  225.893 51.936 226.325 59.64 ;
     RECT  225.893 60.864 226.325 62.328 ;
     RECT  226.001 63.648 226.325 75.576 ;
     RECT  226.001 76.608 226.325 79.896 ;
     RECT  225.965 81.6 226.325 82.584 ;
     RECT  226.253 83.712 226.325 87.96 ;
     RECT  226.253 89.664 226.325 91.032 ;
     RECT  225.929 92.16 226.325 93.72 ;
     RECT  225.929 94.752 226.325 102.936 ;
     RECT  225.929 104.448 226.325 113.208 ;
     RECT  226.289 117.984 226.325 118.392 ;
     RECT  226.325 64.8 226.361 65.112 ;
     RECT  226.325 118.368 226.361 118.392 ;
     RECT  226.325 112.224 226.397 113.208 ;
     RECT  226.325 74.976 226.469 75 ;
     RECT  226.325 86.688 226.505 87.96 ;
     RECT  226.325 58.848 226.541 59.64 ;
     RECT  226.325 100.224 226.541 101.784 ;
     RECT  226.325 83.712 226.649 84.792 ;
     RECT  226.325 92.16 226.649 93.048 ;
     RECT  226.397 112.608 226.649 113.208 ;
     RECT  226.325 66.336 226.721 68.184 ;
     RECT  226.649 83.712 226.721 84.696 ;
     RECT  226.721 66.336 226.757 68.088 ;
     RECT  226.325 95.04 226.757 95.064 ;
     RECT  226.325 52.992 226.793 53.016 ;
     RECT  226.505 87.168 226.793 87.96 ;
     RECT  226.325 104.448 226.793 106.392 ;
     RECT  226.325 48.864 226.865 50.328 ;
     RECT  226.325 56.928 226.865 56.952 ;
     RECT  226.541 59.616 226.865 59.64 ;
     RECT  226.325 60.864 226.865 60.888 ;
     RECT  226.325 62.304 226.865 62.328 ;
     RECT  226.361 64.8 226.865 64.824 ;
     RECT  226.757 67.2 226.865 68.088 ;
     RECT  226.325 70.944 226.865 71.64 ;
     RECT  226.325 76.704 226.865 76.728 ;
     RECT  226.325 77.952 226.865 79.128 ;
     RECT  226.325 82.272 226.865 82.296 ;
     RECT  226.793 87.168 226.865 87.768 ;
     RECT  226.325 91.008 226.865 91.032 ;
     RECT  226.649 92.16 226.865 92.184 ;
     RECT  226.325 96.096 226.865 96.792 ;
     RECT  226.325 98.016 226.865 98.808 ;
     RECT  226.541 101.088 226.865 101.784 ;
     RECT  226.325 102.912 226.865 102.936 ;
     RECT  226.793 104.448 226.865 104.472 ;
     RECT  226.793 106.368 226.865 106.392 ;
     RECT  226.109 46.656 226.901 47.832 ;
     RECT  226.865 48.864 226.901 49.848 ;
     RECT  226.721 83.712 226.973 83.736 ;
     RECT  226.325 63.744 227.117 63.768 ;
     RECT  226.901 47.04 227.153 47.832 ;
     RECT  227.153 47.424 227.477 47.832 ;
     RECT  226.901 48.864 227.477 48.888 ;
     RECT  226.325 110.496 227.477 110.52 ;
     RECT  226.865 98.016 227.513 98.04 ;
     RECT  226.649 112.896 228.017 113.208 ;
     RECT  225.749 114.336 228.197 114.936 ;
     RECT  227.477 47.808 228.233 47.832 ;
     RECT  226.865 87.744 229.208 87.768 ;
     RECT  228.017 113.184 229.208 113.208 ;
     RECT  228.197 114.336 229.208 114.36 ;
     RECT  229.208 2.148 229.312 213.852 ;
     RECT  229.312 2.418 229.504 213.582 ;
     RECT  234.608 2.148 234.712 213.852 ;
     RECT  234.712 2.418 234.904 213.582 ;
     RECT  240.008 2.148 240.112 213.852 ;
     RECT  240.112 2.418 240.304 213.582 ;
     RECT  245.408 2.148 245.512 213.852 ;
     RECT  245.512 2.418 245.704 213.582 ;
     RECT  250.808 2.148 250.912 213.852 ;
     RECT  250.912 2.418 251.104 213.582 ;
     RECT  256.208 2.148 256.312 213.852 ;
     RECT  256.312 2.418 256.504 213.582 ;
    LAYER M5 ;
     RECT  2.4 2.137 2.52 2.151 ;
     RECT  7.8 2.137 7.92 2.151 ;
     RECT  13.2 2.137 13.32 2.151 ;
     RECT  18.6 2.137 18.72 2.151 ;
     RECT  24 2.137 24.12 2.151 ;
     RECT  29.4 2.137 29.52 2.151 ;
     RECT  34.8 2.137 34.92 2.151 ;
     RECT  40.2 2.137 40.32 2.151 ;
     RECT  45.6 2.137 45.72 2.151 ;
     RECT  51 2.137 51.12 2.151 ;
     RECT  56.4 2.137 56.52 2.151 ;
     RECT  61.8 2.137 61.92 2.151 ;
     RECT  67.2 2.137 67.32 2.151 ;
     RECT  72.6 2.137 72.72 2.151 ;
     RECT  78 2.137 78.12 2.151 ;
     RECT  83.4 2.137 83.52 2.151 ;
     RECT  88.8 2.137 88.92 2.151 ;
     RECT  94.2 2.137 94.32 2.151 ;
     RECT  99.6 2.137 99.72 2.151 ;
     RECT  105 2.137 105.12 2.151 ;
     RECT  110.4 2.137 110.52 2.151 ;
     RECT  115.8 2.137 115.92 2.151 ;
     RECT  121.2 2.137 121.32 2.151 ;
     RECT  126.6 2.137 126.72 2.151 ;
     RECT  132 2.137 132.12 2.151 ;
     RECT  137.4 2.137 137.52 2.151 ;
     RECT  142.8 2.137 142.92 2.151 ;
     RECT  148.2 2.137 148.32 2.151 ;
     RECT  153.6 2.137 153.72 2.151 ;
     RECT  159 2.137 159.12 2.151 ;
     RECT  164.4 2.137 164.52 2.151 ;
     RECT  169.8 2.137 169.92 2.151 ;
     RECT  175.2 2.137 175.32 2.151 ;
     RECT  180.6 2.137 180.72 2.151 ;
     RECT  186 2.137 186.12 2.151 ;
     RECT  191.4 2.137 191.52 2.151 ;
     RECT  196.8 2.137 196.92 2.151 ;
     RECT  202.2 2.137 202.32 2.151 ;
     RECT  207.6 2.137 207.72 2.151 ;
     RECT  213 2.137 213.12 2.151 ;
     RECT  218.4 2.137 218.52 2.151 ;
     RECT  223.8 2.137 223.92 2.151 ;
     RECT  229.2 2.137 229.32 2.151 ;
     RECT  234.6 2.137 234.72 2.151 ;
     RECT  240 2.137 240.12 2.151 ;
     RECT  245.4 2.137 245.52 2.151 ;
     RECT  250.8 2.137 250.92 2.151 ;
     RECT  256.2 2.137 256.32 2.151 ;
     RECT  4.032 8.485 4.056 18.613 ;
     RECT  4.032 18.613 4.488 18.659 ;
     RECT  4.464 18.659 4.488 18.757 ;
     RECT  6.24 16.501 6.264 18.851 ;
     RECT  4.464 18.757 4.536 19.427 ;
     RECT  7.8 2.151 8.112 21.541 ;
     RECT  4.464 19.427 4.488 22.163 ;
     RECT  7.8 21.541 8.232 22.165 ;
     RECT  5.712 21.013 5.736 23.123 ;
     RECT  14.64 22.741 14.664 23.795 ;
     RECT  16.848 22.741 16.872 24.131 ;
     RECT  4.512 23.893 4.536 25.139 ;
     RECT  24 2.151 24.312 25.957 ;
     RECT  16.56 24.469 16.584 26.291 ;
     RECT  7.056 22.165 8.232 26.675 ;
     RECT  5.472 26.149 5.496 26.819 ;
     RECT  3.984 26.101 4.008 27.301 ;
     RECT  7.056 26.675 8.112 27.395 ;
     RECT  3.984 27.301 4.248 28.163 ;
     RECT  7.68 27.395 8.112 28.453 ;
     RECT  4.224 28.163 4.248 29.029 ;
     RECT  4.224 29.029 5.064 29.123 ;
     RECT  14.976 25.669 15 29.653 ;
     RECT  16.8 28.789 16.824 29.699 ;
     RECT  7.152 28.453 8.112 30.565 ;
     RECT  5.04 29.123 5.064 31.333 ;
     RECT  4.512 31.333 5.064 31.379 ;
     RECT  14.976 29.653 15.816 31.379 ;
     RECT  6.912 30.565 8.112 31.955 ;
     RECT  67.2 2.151 67.512 32.293 ;
     RECT  67.104 32.293 67.512 32.483 ;
     RECT  4.512 31.379 4.536 33.733 ;
     RECT  4.512 33.733 4.68 33.779 ;
     RECT  7.2 31.955 8.112 33.877 ;
     RECT  15.696 31.379 15.816 33.877 ;
     RECT  14.832 33.877 15.816 34.597 ;
     RECT  4.656 33.779 4.68 34.835 ;
     RECT  13.2 2.151 13.512 35.317 ;
     RECT  14.832 34.597 15.912 35.939 ;
     RECT  14.928 35.939 15.912 35.987 ;
     RECT  7.104 33.877 8.112 36.373 ;
     RECT  14.928 35.987 15.72 37.235 ;
     RECT  15.408 37.235 15.72 38.723 ;
     RECT  15.552 38.723 15.72 38.819 ;
     RECT  4.56 35.557 4.584 39.395 ;
     RECT  6.336 36.373 8.112 40.211 ;
     RECT  15.696 38.819 15.72 40.405 ;
     RECT  13.104 35.317 13.512 41.411 ;
     RECT  7.008 40.211 8.112 41.939 ;
     RECT  4.656 41.269 4.68 42.803 ;
     RECT  13.2 41.411 13.512 43.285 ;
     RECT  4.992 43.285 5.016 43.813 ;
     RECT  4.608 43.813 5.016 43.859 ;
     RECT  15.12 40.405 15.72 43.955 ;
     RECT  43.104 32.341 43.128 44.675 ;
     RECT  13.104 43.285 13.512 45.445 ;
     RECT  7.056 41.939 8.112 46.117 ;
     RECT  12.528 45.445 13.512 46.211 ;
     RECT  4.608 43.859 4.632 47.269 ;
     RECT  4.608 47.269 5.112 47.315 ;
     RECT  5.088 47.315 5.112 48.421 ;
     RECT  4.56 48.421 5.112 48.707 ;
     RECT  6.864 46.117 8.112 49.235 ;
     RECT  9.216 41.893 9.24 49.475 ;
     RECT  4.56 48.707 4.584 50.195 ;
     RECT  10.464 48.325 10.488 51.349 ;
     RECT  10.464 51.349 10.824 51.395 ;
     RECT  13.2 46.211 13.512 53.557 ;
     RECT  7.008 49.235 8.112 55.381 ;
     RECT  10.8 51.395 10.824 55.427 ;
     RECT  12.912 53.557 13.512 56.531 ;
     RECT  15.696 43.955 15.72 56.677 ;
     RECT  5.088 52.981 5.112 56.771 ;
     RECT  3.984 56.725 4.008 57.635 ;
     RECT  17.568 35.941 17.592 58.163 ;
     RECT  6.864 55.381 8.112 58.883 ;
     RECT  7.008 58.883 8.112 59.173 ;
     RECT  43.056 59.125 43.08 59.315 ;
     RECT  4.368 58.117 4.392 59.459 ;
     RECT  15.6 56.677 15.72 59.749 ;
     RECT  18.6 2.151 18.912 60.853 ;
     RECT  7.008 59.173 8.568 60.949 ;
     RECT  4.56 60.373 4.584 61.859 ;
     RECT  218.4 2.151 218.712 62.677 ;
     RECT  26.784 62.677 26.808 62.867 ;
     RECT  38.736 62.677 38.76 62.867 ;
     RECT  218.304 62.677 218.712 62.867 ;
     RECT  222.24 62.677 222.264 62.867 ;
     RECT  6.624 60.949 8.568 63.107 ;
     RECT  6.624 63.107 8.376 64.357 ;
     RECT  6.24 64.357 8.376 65.027 ;
     RECT  23.04 25.957 24.312 66.037 ;
     RECT  25.968 63.301 25.992 66.037 ;
     RECT  6.624 65.027 8.376 66.707 ;
     RECT  7.104 66.707 8.376 66.803 ;
     RECT  13.2 56.531 13.512 66.901 ;
     RECT  11.712 64.837 11.736 67.237 ;
     RECT  13.2 66.901 13.608 67.237 ;
     RECT  4.224 63.205 4.248 67.283 ;
     RECT  15.024 59.749 15.72 67.285 ;
     RECT  14.832 67.285 15.72 68.387 ;
     RECT  11.712 67.237 13.608 68.435 ;
     RECT  4.128 67.813 4.152 69.203 ;
     RECT  15.696 68.387 15.72 69.493 ;
     RECT  20.784 69.493 20.808 70.163 ;
     RECT  18 60.853 18.912 70.453 ;
     RECT  15.36 69.493 15.72 70.499 ;
     RECT  7.8 66.803 8.376 70.739 ;
     RECT  7.8 70.739 8.28 72.565 ;
     RECT  4.56 70.933 4.584 72.995 ;
     RECT  5.568 71.797 5.592 73.523 ;
     RECT  7.8 72.565 8.664 73.571 ;
     RECT  5.568 75.205 5.592 75.541 ;
     RECT  9.936 60.373 9.96 75.635 ;
     RECT  5.568 75.541 5.64 75.971 ;
     RECT  5.616 75.971 5.64 76.547 ;
     RECT  7.8 73.571 8.28 76.885 ;
     RECT  7.8 76.885 9.096 77.363 ;
     RECT  5.424 77.989 5.448 78.325 ;
     RECT  10.224 76.357 10.248 78.371 ;
     RECT  3.984 78.565 4.008 78.707 ;
     RECT  5.424 78.325 5.784 78.947 ;
     RECT  20.304 70.645 20.328 79.045 ;
     RECT  20.016 79.045 20.328 79.091 ;
     RECT  5.76 78.947 5.784 79.283 ;
     RECT  17.136 70.453 18.912 79.763 ;
     RECT  7.8 77.363 8.28 83.219 ;
     RECT  21.648 83.173 21.672 83.843 ;
     RECT  15.696 70.499 15.72 83.989 ;
     RECT  17.328 79.763 18.912 84.035 ;
     RECT  18 84.035 18.912 84.325 ;
     RECT  20.016 79.091 20.04 84.325 ;
     RECT  15.696 83.989 16.344 85.237 ;
     RECT  14.832 85.237 16.344 85.379 ;
     RECT  14.832 85.379 15.72 87.251 ;
     RECT  18 84.325 20.04 91.091 ;
     RECT  7.8 83.219 8.232 92.917 ;
     RECT  5.76 81.445 5.784 93.491 ;
     RECT  23.04 66.037 25.992 94.549 ;
     RECT  6.96 92.917 8.232 94.595 ;
     RECT  7.8 94.595 8.232 94.691 ;
     RECT  23.04 94.549 26.232 94.691 ;
     RECT  4.56 94.021 4.584 95.219 ;
     RECT  24 94.691 26.232 95.219 ;
     RECT  15.696 87.251 15.72 95.795 ;
     RECT  27.312 93.301 27.336 95.795 ;
     RECT  29.4 2.151 29.712 95.989 ;
     RECT  7.8 94.691 8.112 97.429 ;
     RECT  24 95.219 25.992 97.429 ;
     RECT  23.28 97.429 25.992 97.669 ;
     RECT  15.36 96.037 15.384 98.099 ;
     RECT  23.28 97.669 26.664 98.629 ;
     RECT  23.04 98.629 26.664 98.867 ;
     RECT  23.616 98.867 26.664 100.355 ;
     RECT  24 100.355 26.664 102.083 ;
     RECT  6.912 97.429 8.112 102.131 ;
     RECT  30.72 32.437 30.744 103.235 ;
     RECT  7.44 102.131 8.112 104.579 ;
     RECT  11.712 68.435 13.512 104.869 ;
     RECT  18 91.091 19.752 104.869 ;
     RECT  24 102.083 25.992 104.915 ;
     RECT  11.712 104.869 13.608 105.011 ;
     RECT  27.888 99.541 27.912 105.013 ;
     RECT  27.36 105.013 27.912 105.059 ;
     RECT  4.56 96.277 4.584 105.397 ;
     RECT  4.56 105.397 5.112 105.443 ;
     RECT  17.28 104.869 19.896 105.781 ;
     RECT  17.04 105.781 19.896 106.501 ;
     RECT  24 104.915 24.696 106.549 ;
     RECT  25.68 104.915 25.992 106.549 ;
     RECT  27.36 105.059 27.384 106.549 ;
     RECT  28.944 95.989 29.712 106.549 ;
     RECT  7.68 104.579 8.112 106.739 ;
     RECT  15.024 106.885 15.048 107.029 ;
     RECT  16.896 106.501 19.896 107.029 ;
     RECT  15.024 107.029 19.896 107.509 ;
     RECT  15.024 107.509 20.28 107.749 ;
     RECT  9.648 106.693 9.672 107.795 ;
     RECT  27.36 106.549 29.712 107.795 ;
     RECT  15.024 107.749 20.472 107.797 ;
     RECT  7.8 106.739 8.112 108.037 ;
     RECT  15.024 107.797 21.144 108.131 ;
     RECT  22.8 108.085 22.824 108.133 ;
     RECT  22.512 108.133 22.824 108.325 ;
     RECT  24 106.549 25.992 108.325 ;
     RECT  15.024 108.131 20.856 108.419 ;
     RECT  22.512 108.325 25.992 108.421 ;
     RECT  22.464 108.421 25.992 108.469 ;
     RECT  16.896 108.419 20.856 108.659 ;
     RECT  15.024 108.419 15.048 108.709 ;
     RECT  22.368 108.469 25.992 108.805 ;
     RECT  16.896 108.659 20.376 108.851 ;
     RECT  28.176 107.795 29.712 108.995 ;
     RECT  22.368 108.805 26.76 109.091 ;
     RECT  22.368 109.091 22.776 109.283 ;
     RECT  28.944 108.995 29.712 109.525 ;
     RECT  5.088 105.443 5.112 109.667 ;
     RECT  24 109.091 26.76 109.669 ;
     RECT  27.744 109.381 27.816 109.669 ;
     RECT  7.8 108.037 8.232 109.715 ;
     RECT  24 109.669 27.816 109.715 ;
     RECT  28.944 109.525 30.648 109.715 ;
     RECT  11.712 105.011 13.512 109.861 ;
     RECT  24 109.715 27.768 109.907 ;
     RECT  22.512 109.283 22.536 110.003 ;
     RECT  24 109.907 27.048 110.003 ;
     RECT  11.712 109.861 13.896 110.051 ;
     RECT  16.896 108.851 19.944 110.293 ;
     RECT  24 110.003 25.992 110.627 ;
     RECT  10.224 109.333 10.248 110.723 ;
     RECT  16.56 110.293 19.944 110.723 ;
     RECT  4.56 110.005 4.584 110.725 ;
     RECT  6.576 108.709 6.6 110.819 ;
     RECT  43.104 110.629 43.128 110.915 ;
     RECT  16.56 110.723 19.8 111.011 ;
     RECT  16.56 111.011 19.368 111.155 ;
     RECT  24 110.627 25.368 111.203 ;
     RECT  42.72 111.541 42.744 111.731 ;
     RECT  24 111.203 25.32 111.779 ;
     RECT  14.976 108.709 15.048 111.827 ;
     RECT  16.944 111.155 19.368 111.875 ;
     RECT  12.48 110.051 13.896 112.355 ;
     RECT  16.944 111.875 18.912 112.883 ;
     RECT  14.976 111.827 15 113.221 ;
     RECT  16.992 112.883 18.912 113.459 ;
     RECT  17.616 113.459 18.912 113.507 ;
     RECT  6.528 110.869 6.552 113.701 ;
     RECT  7.8 109.715 8.112 113.701 ;
     RECT  6.528 113.701 8.112 113.747 ;
     RECT  4.56 110.725 4.872 114.275 ;
     RECT  14.928 113.221 15 114.275 ;
     RECT  4.848 114.275 4.872 115.045 ;
     RECT  21.408 110.869 21.432 115.763 ;
     RECT  4.848 115.045 5.112 117.349 ;
     RECT  27.024 110.003 27.048 119.171 ;
     RECT  24 111.779 24.408 119.267 ;
     RECT  28.944 109.715 29.712 119.267 ;
     RECT  4.848 117.349 5.64 119.605 ;
     RECT  6.96 113.747 8.112 119.605 ;
     RECT  32.256 103.717 32.28 119.653 ;
     RECT  4.848 119.605 8.112 119.747 ;
     RECT  32.256 119.653 32.472 120.227 ;
     RECT  4.848 119.747 6.312 120.755 ;
     RECT  4.848 120.755 5.64 122.389 ;
     RECT  4.608 122.389 6.36 122.675 ;
     RECT  4.608 122.675 5.64 124.787 ;
     RECT  4.608 124.787 4.872 126.419 ;
     RECT  4.848 126.419 4.872 127.381 ;
     RECT  7.8 119.747 8.112 128.773 ;
     RECT  4.848 127.381 4.968 129.349 ;
     RECT  4.512 129.349 4.968 129.395 ;
     RECT  7.056 128.773 8.112 129.925 ;
     RECT  14.976 114.275 15 129.971 ;
     RECT  12.48 112.355 13.512 130.595 ;
     RECT  13.056 130.595 13.512 131.171 ;
     RECT  32.256 120.227 32.28 131.795 ;
     RECT  30.72 119.653 30.744 131.939 ;
     RECT  6.336 129.925 8.112 137.653 ;
     RECT  4.512 129.395 4.872 138.133 ;
     RECT  4.128 138.133 4.872 138.563 ;
     RECT  6.192 137.653 8.112 139.139 ;
     RECT  4.848 138.563 4.872 141.109 ;
     RECT  4.032 141.109 4.872 143.651 ;
     RECT  6.336 139.139 8.112 145.043 ;
     RECT  6.336 145.043 6.36 146.437 ;
     RECT  6 146.437 6.36 146.963 ;
     RECT  4.32 143.651 4.872 149.125 ;
     RECT  4.32 149.125 4.92 150.179 ;
     RECT  6.336 146.963 6.36 150.949 ;
     RECT  4.368 150.179 4.92 150.995 ;
     RECT  4.368 150.995 4.872 152.531 ;
     RECT  6.288 150.949 6.36 154.213 ;
     RECT  6.288 154.213 6.456 154.259 ;
     RECT  4.704 152.531 4.872 155.173 ;
     RECT  6.336 154.259 6.456 155.989 ;
     RECT  6.288 155.989 6.456 156.035 ;
     RECT  4.608 155.173 4.872 156.803 ;
     RECT  4.848 156.803 4.872 158.053 ;
     RECT  6.288 156.035 6.36 158.389 ;
     RECT  7.8 145.043 8.112 158.389 ;
     RECT  6.288 158.389 8.112 158.579 ;
     RECT  4.752 158.053 4.872 159.587 ;
     RECT  4.848 159.587 4.872 160.693 ;
     RECT  6.528 158.579 8.112 160.693 ;
     RECT  4.848 160.693 8.112 164.485 ;
     RECT  4.8 164.485 8.112 164.531 ;
     RECT  4.8 164.531 4.872 167.461 ;
     RECT  4.608 167.461 4.872 169.331 ;
     RECT  6.528 164.531 8.112 170.147 ;
     RECT  6.528 170.147 6.552 170.821 ;
     RECT  4.608 169.331 4.632 171.059 ;
     RECT  6.432 170.821 6.552 174.421 ;
     RECT  6.432 174.421 6.648 174.467 ;
     RECT  6.624 174.467 6.648 178.453 ;
     RECT  5.76 178.453 6.648 178.499 ;
     RECT  5.76 178.499 5.784 180.179 ;
     RECT  7.8 170.147 8.112 181.765 ;
     RECT  5.664 181.237 5.688 182.149 ;
     RECT  5.232 182.149 5.688 182.195 ;
     RECT  5.232 182.195 5.256 182.435 ;
     RECT  11.472 113.269 11.496 182.435 ;
     RECT  7.8 181.765 8.76 182.867 ;
     RECT  2.4 2.151 2.712 213.849 ;
     RECT  7.8 182.867 8.112 213.849 ;
     RECT  13.2 131.171 13.512 213.849 ;
     RECT  18.6 113.507 18.912 213.849 ;
     RECT  24 119.267 24.312 213.849 ;
     RECT  29.4 119.267 29.712 213.849 ;
     RECT  34.8 2.151 35.112 213.849 ;
     RECT  40.2 2.151 40.512 213.849 ;
     RECT  45.6 2.151 45.912 213.849 ;
     RECT  51 2.151 51.312 213.849 ;
     RECT  56.4 2.151 56.712 213.849 ;
     RECT  61.8 2.151 62.112 213.849 ;
     RECT  67.2 32.483 67.512 213.849 ;
     RECT  72.6 2.151 72.912 213.849 ;
     RECT  78 2.151 78.312 213.849 ;
     RECT  83.4 2.151 83.712 213.849 ;
     RECT  88.8 2.151 89.112 213.849 ;
     RECT  94.2 2.151 94.512 213.849 ;
     RECT  99.6 2.151 99.912 213.849 ;
     RECT  105 2.151 105.312 213.849 ;
     RECT  110.4 2.151 110.712 213.849 ;
     RECT  115.8 2.151 116.112 213.849 ;
     RECT  121.2 2.151 121.512 213.849 ;
     RECT  126.6 2.151 126.912 213.849 ;
     RECT  132 2.151 132.312 213.849 ;
     RECT  137.4 2.151 137.712 213.849 ;
     RECT  142.8 2.151 143.112 213.849 ;
     RECT  148.2 2.151 148.512 213.849 ;
     RECT  153.6 2.151 153.912 213.849 ;
     RECT  159 2.151 159.312 213.849 ;
     RECT  164.4 2.151 164.712 213.849 ;
     RECT  169.8 2.151 170.112 213.849 ;
     RECT  175.2 2.151 175.512 213.849 ;
     RECT  180.6 2.151 180.912 213.849 ;
     RECT  186 2.151 186.312 213.849 ;
     RECT  191.4 2.151 191.712 213.849 ;
     RECT  196.8 2.151 197.112 213.849 ;
     RECT  202.2 2.151 202.512 213.849 ;
     RECT  207.6 2.151 207.912 213.849 ;
     RECT  213 2.151 213.312 213.849 ;
     RECT  218.4 62.867 218.712 213.849 ;
     RECT  223.8 2.151 224.112 213.849 ;
     RECT  229.2 2.151 229.512 213.849 ;
     RECT  234.6 2.151 234.912 213.849 ;
     RECT  240 2.151 240.312 213.849 ;
     RECT  245.4 2.151 245.712 213.849 ;
     RECT  250.8 2.151 251.112 213.849 ;
     RECT  256.2 2.151 256.512 213.849 ;
     RECT  2.4 213.849 2.52 213.863 ;
     RECT  7.8 213.849 7.92 213.863 ;
     RECT  13.2 213.849 13.32 213.863 ;
     RECT  18.6 213.849 18.72 213.863 ;
     RECT  24 213.849 24.12 213.863 ;
     RECT  29.4 213.849 29.52 213.863 ;
     RECT  34.8 213.849 34.92 213.863 ;
     RECT  40.2 213.849 40.32 213.863 ;
     RECT  45.6 213.849 45.72 213.863 ;
     RECT  51 213.849 51.12 213.863 ;
     RECT  56.4 213.849 56.52 213.863 ;
     RECT  61.8 213.849 61.92 213.863 ;
     RECT  67.2 213.849 67.32 213.863 ;
     RECT  72.6 213.849 72.72 213.863 ;
     RECT  78 213.849 78.12 213.863 ;
     RECT  83.4 213.849 83.52 213.863 ;
     RECT  88.8 213.849 88.92 213.863 ;
     RECT  94.2 213.849 94.32 213.863 ;
     RECT  99.6 213.849 99.72 213.863 ;
     RECT  105 213.849 105.12 213.863 ;
     RECT  110.4 213.849 110.52 213.863 ;
     RECT  115.8 213.849 115.92 213.863 ;
     RECT  121.2 213.849 121.32 213.863 ;
     RECT  126.6 213.849 126.72 213.863 ;
     RECT  132 213.849 132.12 213.863 ;
     RECT  137.4 213.849 137.52 213.863 ;
     RECT  142.8 213.849 142.92 213.863 ;
     RECT  148.2 213.849 148.32 213.863 ;
     RECT  153.6 213.849 153.72 213.863 ;
     RECT  159 213.849 159.12 213.863 ;
     RECT  164.4 213.849 164.52 213.863 ;
     RECT  169.8 213.849 169.92 213.863 ;
     RECT  175.2 213.849 175.32 213.863 ;
     RECT  180.6 213.849 180.72 213.863 ;
     RECT  186 213.849 186.12 213.863 ;
     RECT  191.4 213.849 191.52 213.863 ;
     RECT  196.8 213.849 196.92 213.863 ;
     RECT  202.2 213.849 202.32 213.863 ;
     RECT  207.6 213.849 207.72 213.863 ;
     RECT  213 213.849 213.12 213.863 ;
     RECT  218.4 213.849 218.52 213.863 ;
     RECT  223.8 213.849 223.92 213.863 ;
     RECT  229.2 213.849 229.32 213.863 ;
     RECT  234.6 213.849 234.72 213.863 ;
     RECT  240 213.849 240.12 213.863 ;
     RECT  245.4 213.849 245.52 213.863 ;
     RECT  250.8 213.849 250.92 213.863 ;
     RECT  256.2 213.849 256.32 213.863 ;
     RECT  2.712 8.485 4.032 18.659 ;
     RECT  4.488 21.013 5.712 22.163 ;
     RECT  5.736 22.165 7.056 23.123 ;
     RECT  13.512 22.741 14.64 23.795 ;
     RECT  4.512 25.139 4.536 26.101 ;
     RECT  13.512 25.669 14.976 31.379 ;
     RECT  2.712 26.101 3.984 28.163 ;
     RECT  4.008 26.101 4.536 26.149 ;
     RECT  4.008 26.149 5.472 26.819 ;
     RECT  4.008 26.819 4.248 27.301 ;
     RECT  7.152 27.395 7.68 28.453 ;
     RECT  2.712 28.163 4.224 29.123 ;
     RECT  15.816 29.653 16.8 29.699 ;
     RECT  29.712 32.437 30.72 103.235 ;
     RECT  13.512 33.877 14.832 35.939 ;
     RECT  13.512 35.939 14.928 37.235 ;
     RECT  17.592 35.941 18.6 58.163 ;
     RECT  8.112 41.893 9.216 49.475 ;
     RECT  4.656 42.803 4.68 43.285 ;
     RECT  4.656 43.285 4.992 43.813 ;
     RECT  4.608 47.315 5.088 48.421 ;
     RECT  9.24 48.325 10.464 49.475 ;
     RECT  2.712 56.725 3.984 57.635 ;
     RECT  4.008 56.725 5.088 56.771 ;
     RECT  4.008 56.771 4.392 57.635 ;
     RECT  4.368 57.635 4.392 58.117 ;
     RECT  13.512 59.749 15.024 66.901 ;
     RECT  8.568 60.373 9.936 63.107 ;
     RECT  38.76 62.677 40.2 62.867 ;
     RECT  2.712 63.205 4.224 67.283 ;
     RECT  11.736 64.837 13.2 67.237 ;
     RECT  13.608 66.901 15.024 67.285 ;
     RECT  2.712 67.283 4.152 67.813 ;
     RECT  13.608 67.285 14.832 68.387 ;
     RECT  2.712 67.813 4.128 69.203 ;
     RECT  15.36 68.387 15.696 69.493 ;
     RECT  15.72 70.453 17.136 79.763 ;
     RECT  18.912 70.645 20.304 79.045 ;
     RECT  4.584 71.797 5.568 72.995 ;
     RECT  8.664 72.565 9.936 73.571 ;
     RECT  9.936 75.635 9.96 76.357 ;
     RECT  9.936 76.357 10.224 76.885 ;
     RECT  10.248 76.357 11.712 78.371 ;
     RECT  9.096 76.885 10.224 77.363 ;
     RECT  2.712 78.565 3.984 78.707 ;
     RECT  4.008 78.565 5.424 78.707 ;
     RECT  18.912 79.045 20.016 84.325 ;
     RECT  21.672 83.173 23.04 83.843 ;
     RECT  16.344 83.989 17.328 84.035 ;
     RECT  13.512 85.237 14.832 87.251 ;
     RECT  5.784 92.917 6.96 93.491 ;
     RECT  25.992 93.301 27.312 94.549 ;
     RECT  26.232 94.549 27.312 95.219 ;
     RECT  4.56 95.219 4.584 96.277 ;
     RECT  25.992 95.219 27.312 95.795 ;
     RECT  26.664 99.541 27.888 102.083 ;
     RECT  27.912 99.541 28.944 105.059 ;
     RECT  24.696 104.915 25.68 106.549 ;
     RECT  25.992 105.013 27.36 107.795 ;
     RECT  27.384 105.059 28.944 106.549 ;
     RECT  13.512 106.885 15.024 108.709 ;
     RECT  25.992 107.795 28.176 108.805 ;
     RECT  22.824 108.085 24 108.325 ;
     RECT  20.856 108.131 21.144 108.133 ;
     RECT  20.856 108.133 22.512 108.421 ;
     RECT  20.856 108.421 22.464 108.469 ;
     RECT  20.856 108.469 22.368 108.659 ;
     RECT  5.112 108.709 6.576 109.667 ;
     RECT  6.6 108.709 7.8 110.819 ;
     RECT  13.512 108.709 14.976 109.861 ;
     RECT  26.76 108.805 28.176 108.995 ;
     RECT  26.76 108.995 28.944 109.381 ;
     RECT  22.776 109.091 24 109.283 ;
     RECT  22.536 109.283 24 110.003 ;
     RECT  10.248 109.333 11.712 110.051 ;
     RECT  26.76 109.381 27.744 109.669 ;
     RECT  27.816 109.381 28.944 109.715 ;
     RECT  6.528 109.667 6.576 110.819 ;
     RECT  27.768 109.715 28.944 109.907 ;
     RECT  13.896 109.861 14.976 112.355 ;
     RECT  25.992 110.003 27.024 110.627 ;
     RECT  15.048 110.293 16.56 111.155 ;
     RECT  6.528 110.819 7.8 110.869 ;
     RECT  6.552 110.869 7.8 113.701 ;
     RECT  13.512 112.355 14.976 113.221 ;
     RECT  13.512 113.221 14.928 114.275 ;
     RECT  11.496 113.269 12.48 130.595 ;
     RECT  13.512 114.275 14.976 129.971 ;
     RECT  5.64 117.349 6.96 119.605 ;
     RECT  29.712 119.653 30.72 131.939 ;
     RECT  30.744 119.653 32.256 131.795 ;
     RECT  6.312 119.747 7.8 120.755 ;
     RECT  6.36 122.389 7.8 122.675 ;
     RECT  4.872 129.395 4.968 129.925 ;
     RECT  4.872 129.925 6.336 137.653 ;
     RECT  4.872 137.653 6.192 139.139 ;
     RECT  2.712 138.133 4.128 138.563 ;
     RECT  4.872 139.139 6.336 146.437 ;
     RECT  2.712 141.109 4.032 143.651 ;
     RECT  6.36 145.043 7.8 154.213 ;
     RECT  4.872 146.437 6 146.963 ;
     RECT  4.872 146.963 6.336 149.125 ;
     RECT  4.92 149.125 6.336 150.949 ;
     RECT  4.92 150.949 6.288 150.995 ;
     RECT  4.872 150.995 6.288 154.259 ;
     RECT  6.456 154.213 7.8 156.035 ;
     RECT  4.872 154.259 6.336 155.989 ;
     RECT  4.872 155.989 6.288 158.579 ;
     RECT  6.36 156.035 7.8 158.389 ;
     RECT  4.752 156.803 4.848 158.053 ;
     RECT  6.552 170.147 7.8 174.421 ;
     RECT  6.648 174.421 7.8 178.499 ;
  END
END ot_coll_bank_land137
END LIBRARY
